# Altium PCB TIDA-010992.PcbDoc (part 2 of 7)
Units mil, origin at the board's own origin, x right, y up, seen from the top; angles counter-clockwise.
Board outline 2810.81 x 2427 mil, 8 copper layers (L01-TOP, L02-GND, L03-SIG, L04-GND, L05-PWR, L06-SIG, L07-GND, L08-BOTTOM), stack 61.9 mil thick; 521 components, 377 nets, 1545 pads, 874 vias.

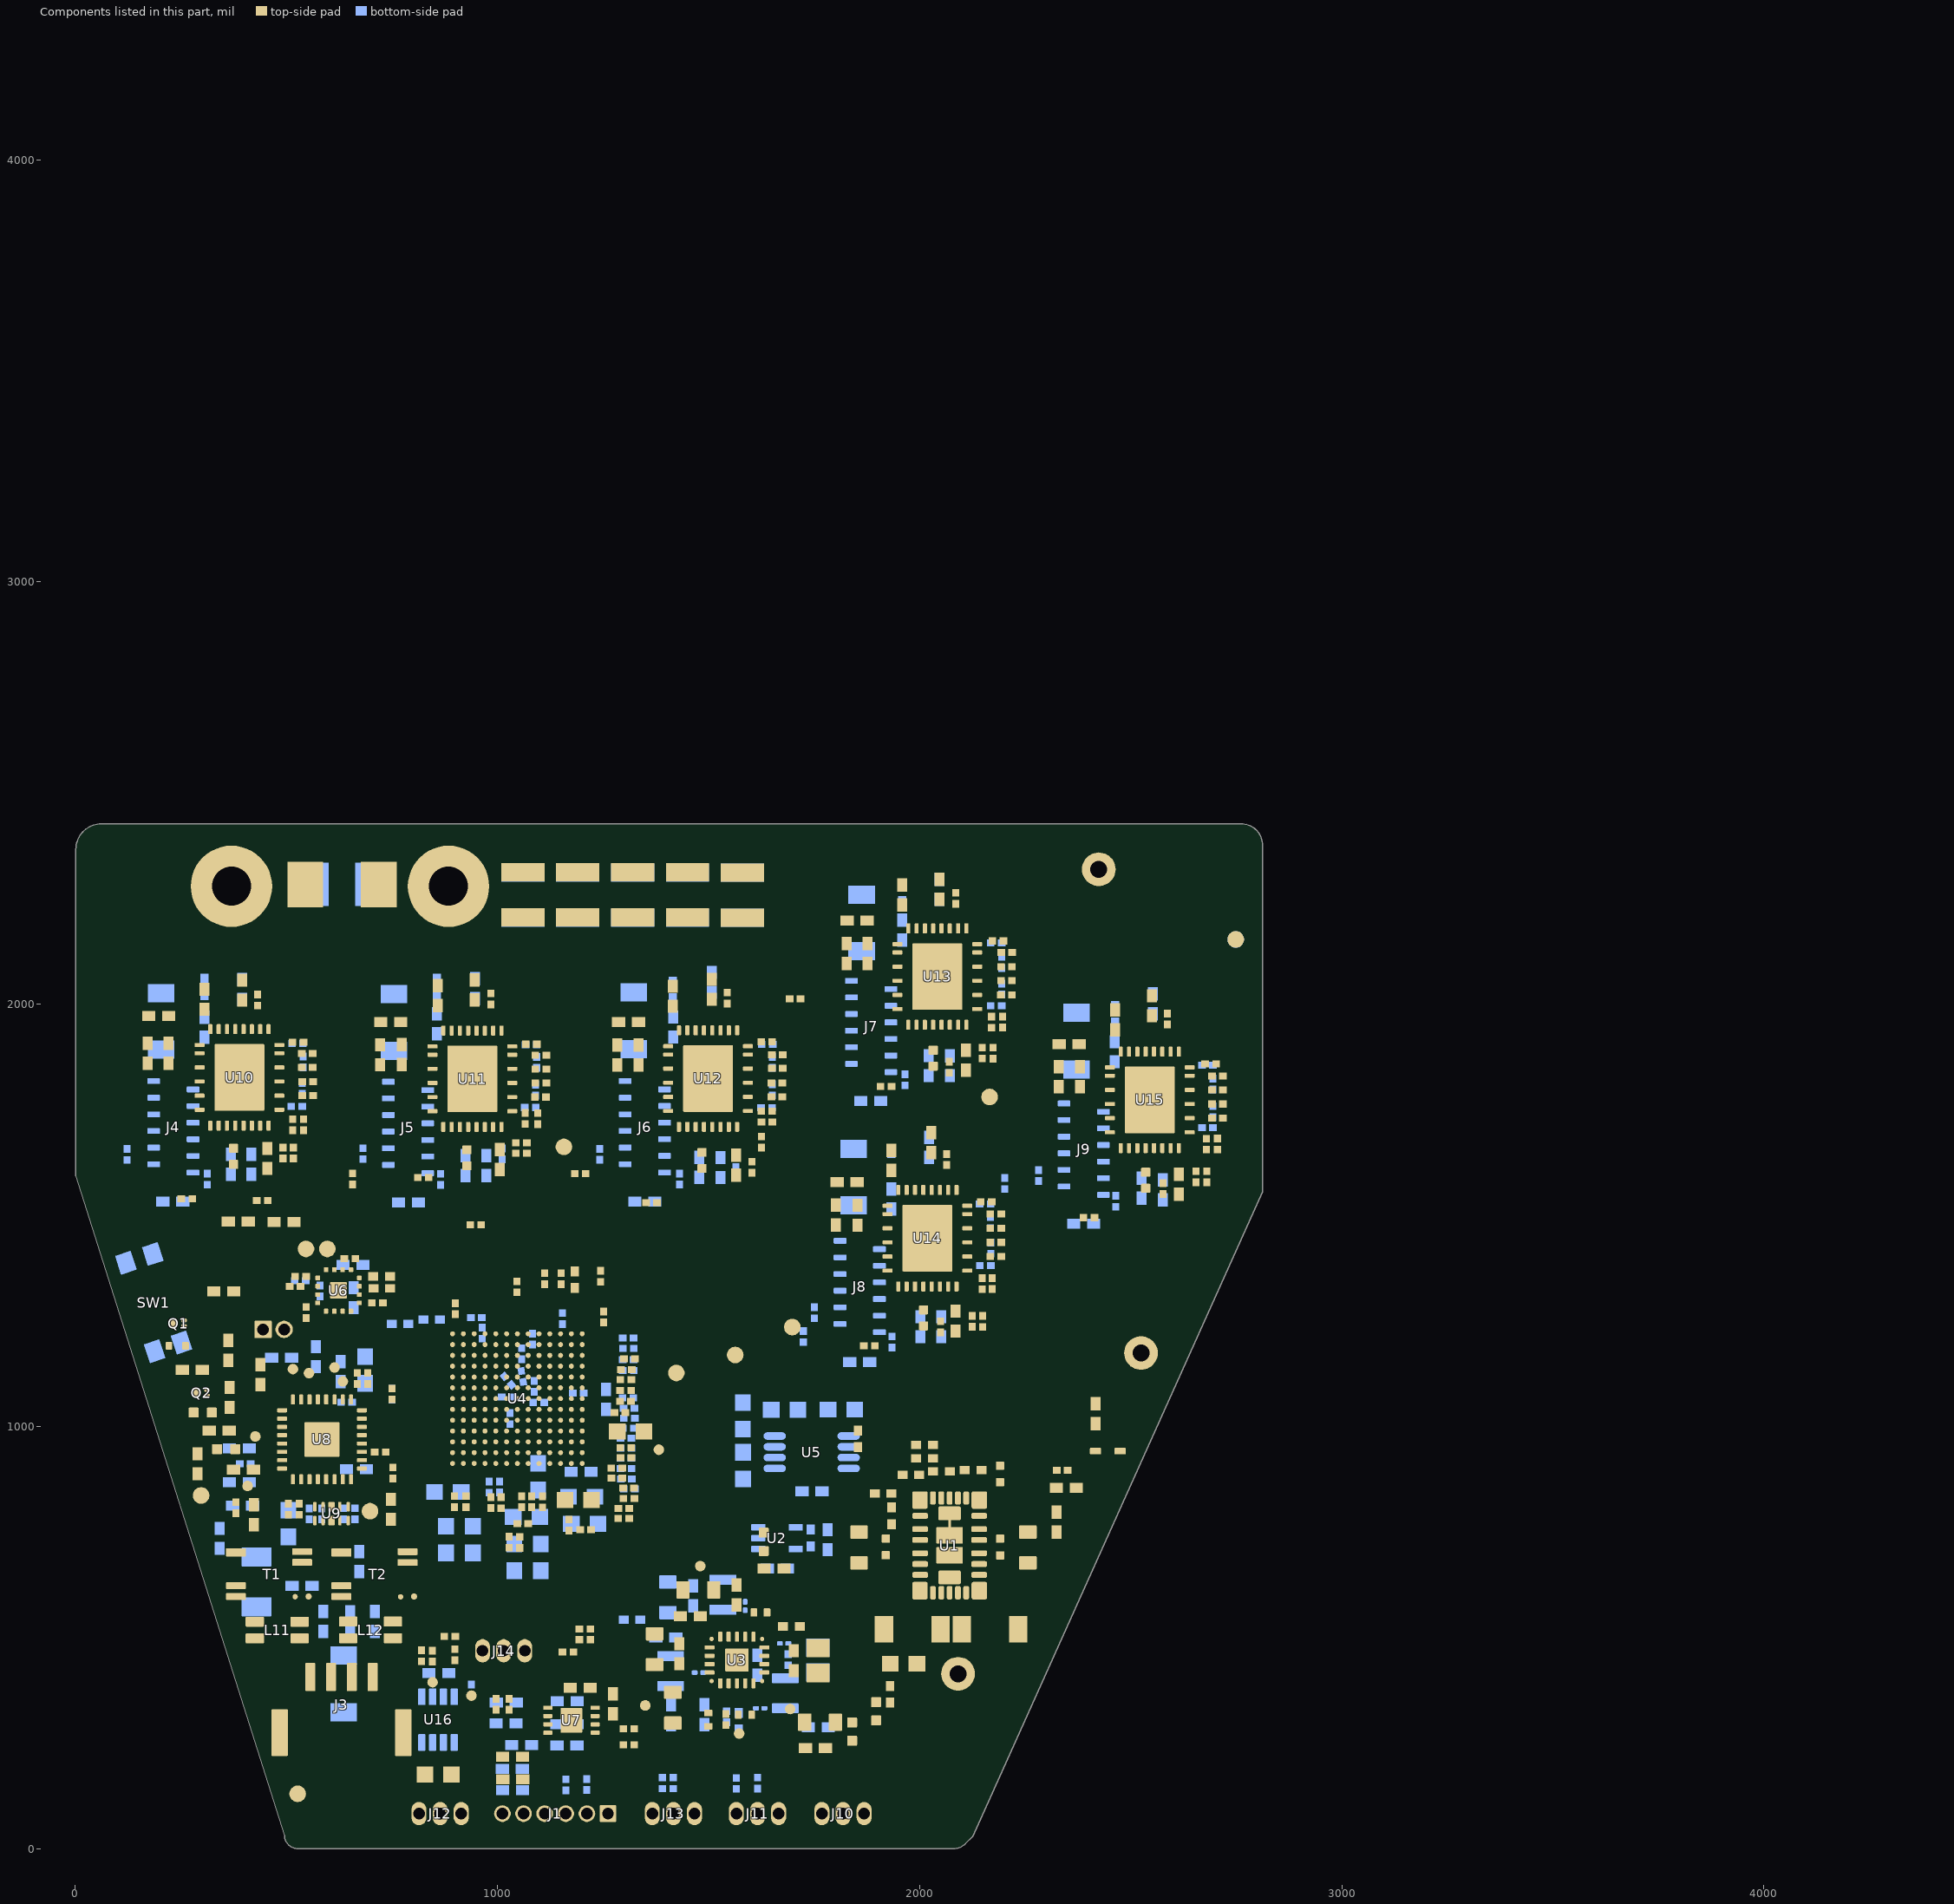
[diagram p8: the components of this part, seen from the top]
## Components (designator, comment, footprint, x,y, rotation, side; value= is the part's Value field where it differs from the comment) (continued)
R187 "RC0201FR-7D4K7L" 0201 2064,1632.04 r90 top value=4.70k
R188 "RC0201FR-7D4K7L" 0201 2049.39,1235.67 r270 top value=4.70k
R189 "CRCW020120R0FNED" 0201_033 2180.31,1469.13 r180 top value=20.0
R190 "CRCW04021K00FKED" 0402 2022.56,1660.43 r270 bottom value=1.00k
R191 "CRCW020120R0FNED" 0201_033 2180.31,1502.6 r180 top value=20.0
R192 "RC0402FR-0715KL" 0402 1932.82,1538.28 r270 bottom value=15.0k
R193 "CRCW040210K0FKED" 0402L 1933.08,1627.23 r270 bottom value=10.0k
R194 "CRCW04021K00FKED" 0402 2576.5,1560.19 r90 bottom value=1.00k
R195 "CRCW04021K00FKED" 0402 2614.01,1573.65 r90 top value=1.00k
R196 "CRCW020120R0FNED" 0201_033 2680.37,1591.04 r90 top value=20.0
R197 "CRCW020120R0FNED" 0201_033 2705.41,1668.69 r90 top value=20.0
R198 "ERJ-1GNJ220C" 0201 2281.89,1593.93 r90 bottom value=22
R199 "CRCW020120R0FNED" 0201_033 2705.6,1729.93 r180 top value=20.0
R200 "CRCW020120R0FNED" 0201_033 2705.6,1763.35 r180 top value=20.0
R201 "ERJ-1GNJ220C" 0201 2464.56,1532.86 r90 bottom value=22
R202 "ERJ-1GNJ220C" 0201 2689.21,1857.99 r180 top value=22
R203 "RC0201FR-7D4K7L" 0201 2586.9,1964.76 r90 top value=4.70k
R204 "RC0201FR-7D4K7L" 0201 2576.81,1562.92 r270 top value=4.70k
R205 "CRCW020120R0FNED" 0201_033 2705.6,1796.38 r180 top value=20.0
R206 "CRCW04021K00FKED" 0402 2551.98,2000.5 r270 bottom value=1.00k
R207 "CRCW020120R0FNED" 0201_033 2705.6,1829.56 r180 top value=20.0
R208 "RC0402FR-0715KL" 0402 2462.11,1887.2 r270 bottom value=15.0k
R209 "CRCW040210K0FKED" 0402L 2463.32,1976.24 r270 bottom value=10.0k
R210 "CMP-0025950-3" 0402 2324.18,773.39 r270 top value=100k
R211 "ERJ-1GNJ220C" 0201 1566.06,154.19 r270 bottom value=22
R212 "ERJ-1GNJ220C" 0201 1615.82,155.04 r270 bottom value=22
R213 "RC0402FR-0710K5L" 0402 2347.32,854.72 r180 top value=10.5k
R214 "CMP-0026825-5" 0402 2416.96,1030.24 r90 top value=10k
R215 "RC0603FR-07120RL" 0603 859.53,175.46 r180 top value=120
R216 "ERJ-1GNJ220C" 0201 1403.37,142 r0 bottom value=22
R217 "ERJ-1GNJ220C" 0201 938.15,375.22 r270 bottom value=22
R218 "RC0201FR-07100KL" 0201 1195.88,1598.07 r0 top value=100k
R219 "RC0201FR-07100KL" 0201 657,1586.06 r90 top value=100k
R220 "CRCW04020000Z0EDHP" 0402 1490.33,316.78 r270 bottom value=0
R221 "CRCW04020000Z0EDHP" 0402 1398.89,499.46 r180 bottom value=0
R222 "ERJ-2GE0R00X" 0402L 1182.73,1347.25 r90 top value=0
R223 "CRCW040210K0FKED" 0402L 1318.87,542.33 r180 bottom value=10.0k
RT1 "TMP6131DYAT" DYA0002A-MFG 2445.73,941.28 r180 top value=10k
SW1 "434351045816" FP-434351045816_SMT_SW_4MM7_4MM5-MFG 185.49,1292.97 r108 bottom
T1 "74930000" FP-74930000_SMT_4MM7_3MM22-MFG 458.67,650.2 r180 top
T2 "74930000" FP-74930000_SMT_4MM7_3MM22-MFG 708.51,649.97 r180 top
TP1 "5000" Keystone5000 2091.03,413.96 r90 top
TP2 "CMP-0055138-2" Keystone5001 2524.37,1173.74 r180 top
TP3 "CMP-0055138-2" Keystone5001 2424.26,2319.33 r180 top
TP4 "TP_SM_1MM" TP_SM_1MM 2165.66,1780.1 r180 top
TP5 "TP_SM_1MM" TP_SM_1MM 1157.21,1661.93 r180 top
TP6 "TP_SM_1MM" TP_SM_1MM 1698.31,1235.08 r180 top
TP7 "TP_SM_1MM" TP_SM_1MM 297.88,836.15 r180 top
TP8 "TESTPOINT" TP_25MIL-SMT 1572.32,272.42 r270 top
TP9 "TESTPOINT" TP_25MIL-SMT 1693.27,330.54 r270 top
TP10 "TESTPOINT" TP_25MIL-SMT 1350.06,338.88 r270 top
TP11 "TESTPOINT" TP_25MIL-SMT 1480.33,669.09 r270 top
TP12 "TESTPOINT" TP_25MIL-SMT 1382.2,944.69 r270 top
TP13 "TP_SM_1MM" TP_SM_1MM 546.27,1420.25 r270 top
TP14 "TP_SM_1MM" TP_SM_1MM 596.83,1420.25 r270 top
TP15 "TESTPOINT" TP_25MIL-SMT 613.75,1139.23 r270 top
TP16 "TESTPOINT" TP_25MIL-SMT 633.58,1106.29 r270 top
TP17 "TESTPOINT" TP_25MIL-SMT 553.4,1125.95 r270 top
TP18 "TP_SM_1MM" TP_SM_1MM 697.88,799.01 r270 top
TP19 "TESTPOINT" TP_25MIL-SMT 515.33,1135.65 r270 top
TP20 "TESTPOINT" TP_25MIL-SMT 426.29,975.96 r270 top
TP21 "TESTPOINT" TP_25MIL-SMT 407.9,858.7 r270 top
TP22 "TESTPOINT" TP_25MIL-SMT 938.26,362.12 r270 top
TP23 "TESTPOINT" TP_25MIL-SMT 846.25,393.98 r270 top
TP24 "TP_SM_1MM" TP_SM_1MM 1423.65,1126.49 r270 top
TP25 "TP_SM_1MM" TP_SM_1MM 1563.1,1169.09 r270 top
U1 "TLVM13630RDHR" RDH0030A-MFG 2070.88,718.09 r0 top
U2 "TLV7021DCKR" DCK0005A_N 1662.1,735.32 r0 bottom
U3 "TPS65035000RZDRQ1" RZD0022A-MFG 1567.06,446.54 r90 top
U4 "TMS320F28P650DK9NMRR" NMR0169A-MFG 1047.09,1065.65 r90 top locked
U5 "REF6230IDGKR" DGK0008A_N 1744.28,938.68 r0 bottom
U6 "LMK3C0105V33RERR" RER0016A-MFG 623.26,1321.92 r90 top
U7 "AT24C256C-MAHL-T" 8MA2 1175.17,303.85 r0 top
U8 "DP83826A" RHB0032M-MFG 584.22,969.03 r90 top locked
U9 "TPD4E05U06DQAR" DQA0010A 606.72,793.19 r270 top
U10 "DRV8376SNLGR" NLG0028A-MFG 388.61,1826.48 r0 top locked
U11 "DRV8376SNLGR" NLG0028A-MFG 940.42,1823.13 r0 top
U12 "DRV8376SNLGR" NLG0028A-MFG 1498.8,1823.59 r0 top
U13 "DRV8376SNLGR" NLG0028A-MFG 2041.86,2065.12 r0 top
U14 "DRV8376SNLGR" NLG0028A-MFG 2018.45,1445.51 r0 top
U15 "DRV8376SNLGR" NLG0028A-MFG 2545.14,1773.24 r0 top
U16 "TCAN332GDCNR" DCN0008A_N 859.04,305.3 r270 bottom
ZZ1 "This Assembly Note is for PCB labels only" AssemblyNoteLabel 185,3938 r0 top
ZZ2 "These assemblies are ESD sensitive, ESD precautions shall be observed." AssemblyNote 185,3829.11 r0 top
ZZ3 "These assemblies must be clean and free from flux and all contaminants. Use of no clean flux is not acceptable." AssemblyNote 185,3740.56 r0 top
ZZ4 "These assemblies must comply with workmanship standards IPC-A-610 Class 2, unless otherwise specified." AssemblyNote 185,3652 r0 top

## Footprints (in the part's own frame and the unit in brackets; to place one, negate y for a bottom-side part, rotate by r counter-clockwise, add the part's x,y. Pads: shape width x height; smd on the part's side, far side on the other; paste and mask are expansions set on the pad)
8MA2 [mm] "ATMEL DFN"
  rrect40% 0.55x0.25 smd: 1(-1.425,0.75) 2(-1.425,0.25) 3(-1.425,-0.25) 4(-1.425,-0.75) 5(1.425,-0.75) 6(1.425,-0.25) 7(1.425,0.25) 8(1.425,0.75)
  rrect8% 1.3x1.5 smd paste-1: 9(0,0)
  rrect8% 1.21x1.38 on Top Paste: 9(0,0)
  silkscreen extent -1.55,-1.15 0.75,1.15, body extent -1.55,-1.05 1.55,1.05, height 0.61
0201 [mm] "Data from Kemet datasheet CC101_COM dated 7/28/11"
  rect 0.46x0.42 smd mask+0.048: 1(-0.33,0) 2(0.33,0)
  body extent -0.31,-0.16 0.31,0.16, height 0.26
0201_033 [mm] "SMD, 2-Leads, Height 0.33mm"
  rect 0.46x0.42 smd mask+0.048: 1(-0.33,0) 2(0.33,0)
  body extent -0.31,-0.16 0.31,0.16, height 0.33
0402 [mm] "0402 from SM-752 data"
  rect 0.8x0.6 smd: 1(-0.6,0) 2(0.6,0)
  silkscreen extent -1.22,-0.52 1.22,0.52, body extent -0.55,-0.3 0.55,0.3, height 0.6
0402_065 [mm] "0402"
  rect 0.8x0.6 smd: 1(-0.6,0) 2(0.6,0)
  silkscreen extent -1.22,-0.52 1.22,0.52, body extent -0.55,-0.3 0.55,0.3, height 0.65
0402L [mm] "0402 from SM-752 data"
  rect 0.6x0.5 smd: 1(-0.5,0) 2(0.5,0)
  body extent -0.55,-0.3 0.55,0.3, height 0.6
0603 [mm] "0603 from SM-752 data"
  rect 1x0.95 smd: 1(-0.8,0) 2(0.8,0)
  silkscreen extent -1.52,-0.69 1.52,0.69, body extent -0.87,-0.47 0.87,0.47, height 1
0805L [mm] "0805 from SM-752 data"
  rect 1.1x1.4 smd: 1(-0.75,0) 2(0.75,0)
  body extent -1.1,-0.72 1.1,0.72, height 1.45
1206_180 [mm] "1206_180"
  rect 1.1x1.6 smd: 1(-1.7,0) 2(1.7,0)
  silkscreen extent -0.9,-1 0.9,1, body extent -1.75,-0.95 1.75,0.95, height 1.8
1206_190 [mm] "1206_190"
  rect 1.1x1.6 smd: 1(-1.7,0) 2(1.7,0)
  silkscreen extent -0.9,-1 0.9,1, body extent -1.75,-0.95 1.75,0.95, height 1.9
1210_270L [mm] "1210"
  rect 1.1x2.6 smd: 1(-1.35,0) 2(1.35,0)
  silkscreen extent -0.4,-1.2 0.4,1.2, body extent -1.7,-1.35 1.7,1.35, height 2.7
AssemblyNote [mil] "Assembly Note"
AssemblyNoteLabel [mil] "Assembly Note for PCB Labels"
CE_Mark_5mm [mil] "Minimum text height for CE Mark"
  silkscreen extent -138,-98 138,98
DCK0005A_N [mm] "SOT353, 5-Leads, Body 2x1.3mm, Pitch 0.65mm, Lead Span 2.1mm, IPC Medium Density"
  rrect25% 0.85x0.4 smd: 1(-1.125,0.65) 2(-1.125,0) 3(-1.125,-0.65) 4(1.125,-0.65) 5(1.125,0.65)
  silkscreen extent -1.48,-1.02 0.55,1.1, body extent -1.14,-1 1.14,1, height 0.95
DCN0008A_N [mm] "SOP, 8-Leads, Body 2.9x1.6mm, Pitch 0.65mm, IPC Medium Density"
  rrect22% 1x0.45 smd: 1(-1.375,0.975) 2(-1.375,0.325) 3(-1.375,-0.325) 4(-1.375,-0.975) 5(1.375,-0.975) 6(1.375,-0.325) 7(1.375,0.325) 8(1.375,0.975)
  silkscreen extent -1.75,-1.5 0.58,1.5, body extent -1.41,-1.45 1.41,1.45, height 1.45
DGK0008A_N [mm] "TSOP, 8-Leads, Body 3x3mm, Pitch 0.65mm, IPC Medium Density"
  oval 1.35x0.45 smd: 1(-2.225,0.975) 2(-2.225,0.325) 3(-2.225,-0.325) 4(-2.225,-0.975) 5(2.225,-0.975) 6(2.225,-0.325) 7(2.225,0.325) 8(2.225,0.975)
  silkscreen extent -2.75,-1.55 0.95,1.55, body extent -2.45,-1.5 2.45,1.5, height 0.96
DQA0010A [mm] "SON, 10-Leads, Body 1x2.5mm, Pitch 0.5mm, TI Recommended"
  rrect50% 0.565x0.2 smd: 1(-0.417,1) 2(-0.417,0.5) 4(-0.417,-0.5) 5(-0.417,-1) 6(0.417,-1) 7(0.417,-0.5) 9(0.417,0.5) 10(0.417,1)
  rrect28% 0.565x0.36 on Top Paste: 3(-0.417,0) 8(0.417,0)
  rrect25% 0.565x0.4 smd paste-0.2: 3(-0.417,0) 8(0.417,0)
  silkscreen extent -0.67,-1.45 0.55,1.45, body extent -0.55,-1.3 0.55,1.3, height 0.56
DYA0002A-MFG [mm]
  rrect25% 0.67x0.4 smd paste+0 mask+0: 1(-0.74,0) 2(0.74,0)
  silkscreen extent -1.75,-0.63 0.65,0.63, body extent -1.17,-0.67 1.17,0.67, height 0.25
FCC_disclaimer [mil]
Fiducial10-20 [mm]
  round 1 smd mask+0.5: 1(0,0)
  L01-TOP keep-out circle w1.178: c0,0 r0.5
FP-12FHT-SM1-GAN-TF(HF)_CONN_FPC_12-MFG [mm] "Recommended Land Pattern"
  rrect29% 0.35x0.77 smd paste+0 mask+0: 1(-2.75,1.185) 2(-2.25,-1.185) 3(-1.75,1.185) 4(-1.25,-1.185) 5(-0.75,1.185) 6(-0.25,-1.185) 7(0.25,1.185) 8(0.75,-1.185) 9(1.25,1.185) 10(1.75,-1.185) 11(2.25,1.185) 12(2.75,-1.185)
  silkscreen extent -3.75,-1.15 3.75,2.24, body extent -3.75,-1.5 3.75,1.44, height 3.3
FP-1206Y2K00222KET_1206-MFG [mm]
  rrect9% 1.15x1.8 smd paste+0 mask+0: 1(-1.5,0) 2(1.5,0)
  silkscreen extent -0.55,-0.9 0.55,0.9, body extent -1.6,-0.8 1.6,0.8, height 1.7
FP-150040RS73220_0402-MFG [mm]
  rrect25% 0.4x0.46 smd paste+0 mask+0: 1(-0.5,0) 2(0.5,0)
  silkscreen extent -1.37,-0.61 0.5,0.61, body extent -0.5,-0.25 0.5,0.25, height 0.35
FP-74930000_SMT_4MM7_3MM22-MFG [mm]
  rrect24% 1.2x0.41 smd paste+0 mask+0: 1(-1.99,-1.35) 2(-1.99,-0.7) 6(1.99,0.7) 7(1.99,1.35)
  round 0.373 smd paste+0 mask+0: 3(-2.382,1.347)
  round 0.321 smd paste+0 mask+0: 4(-1.574,1.365)
  rrect20% 1.2x0.5 smd paste+0 mask+0: 5(1.99,-1.305)
  L01-TOP region: -1.82,1.6 -1.69,1.1 -1.39,1.1 -1.39,1.6
  L01-TOP region: -2.59,1.6 -2.59,1.1 -2.16,1.1 -2.19,1.6
  silkscreen extent -3.27,-1.71 2.45,1.71, body extent -2.69,-1.81 2.69,1.81, height 0.25
FP-744232222_SMT4_3MM2_1MM6-MFG [mm]
  rrect17% 1.1x0.6 smd paste+0 mask+0: 1(-1.35,0.5) 2(1.35,0.5) 3(1.35,-0.5) 4(-1.35,-0.5)
  silkscreen extent -2.6,-0.9 0.43,0.9, body extent -2,-1 2,1, height 0.25
FP-434351045816_SMT_SW_4MM7_4MM5-MFG [mm]
  rrect10% 1.2x1 smd paste+0 mask+0: 1(2.8,0.85) 2(2.8,-0.85) 3(-2.8,0.85) 4(-2.8,-0.85)
  silkscreen extent -2.4,0.73 4.07,1.85, body extent -3.2,-2.75 3.2,1.75, height 1.75
FP-885012205086_0402-MFG [mm]
  rrect20% 0.5x0.5 smd paste+0 mask+0: 1(-0.5,0) 2(0.5,0)
  silkscreen extent -0.6,-0.63 0.6,0.63, body extent -0.5,-0.25 0.5,0.25, height 0.7
FP-BM04B-GHS-TBT(LF)(SN)_HDR4-MFG [mm] "Recommended Land Pattern"
  rrect17% 0.6x1.7 smd paste+0 mask+0: 1(1.875,2.325) 2(0.625,2.325) 3(-0.625,2.325) 4(-1.875,2.325)
  rrect10% 1x2.8 smd paste+0 mask+0: 5(-3.725,-1.025) 6(3.725,-1.025)
  silkscreen extent -4.13,-2.12 4.13,3.92, body extent -4.13,-2.12 4.13,2.83, height 4.2
FP-C2012X7R1H475K125AC_0805-MFG [mm]
  rrect13% 0.8x1.05 smd paste+0 mask+0: 1(-0.925,0) 2(0.925,0)
  silkscreen extent -0.15,-0.75 0.15,0.75, body extent -1,-0.63 1,0.63, height 1.5
FP-CGA4J3X7S1A106K125AE_0805-MFG [mm]
  rrect13% 0.8x1.05 smd paste+0 mask+0: 1(-0.925,0) 2(0.925,0)
  silkscreen extent -0.15,-0.75 0.15,0.75, body extent -1.2,-0.62 1.2,0.63, height 1.5
FP-GMC04X7R105K10NT_0402-MFG [mil]
  rrect19% 21x22 smd paste+0 mask+0: 1(-19,0) 2(19,0)
  silkscreen extent -21,-27 21,27, body extent -33,-15 33,15, height 10
FP-GRM155C71A105KE11D_0402-MFG [mm]
  rrect25% 0.4x0.5 smd paste+0 mask+0: 1(-0.4,0) 2(0.4,0)
  silkscreen extent -0.55,-0.65 0.55,0.65, body extent -0.7,-0.4 0.7,0.4, height 0.25
"FP-RC0201JR-070RL_0201 (0603 Metric)-IPC_C" [mil]
  rrect38% 13.94x10.34 smd paste+0 mask+0: 1(-10.01,0) 2(10.01,0)
  body extent -12,-6 12,6, height 10
IEC_HotSurface_Small [mil]
  silkscreen extent -107,-93 107,92
Keystone5000 [mil] "For Keystone 500x miniature loop terminals"
  round 80 hole 40: 1(0,0)
  silkscreen extent -52,-52 52,52, body extent -49,-49 49,49, height 182
Keystone5001 [mil] "For Keystone 500x miniature loop terminals"
  round 80 hole 40: 1(0,0)
  silkscreen extent -52,-52 52,52, body extent -49,-49 49,49, height 182
Label_650x200 [mil] "Thermal Transfer Label"
  round 1 on Mech13: 0(0,0)
  silkscreen extent -325,-100 325,100, body extent -325,-100 325,100, height 1
MTGP_2-48_PanHead [mm] "2-48 Mounting Hole, Plated, for Pan Head"
  round 4.9 hole 2.35: 1(0,0)
Net-Tie7milsWide_20milsLong [mil] "7 mils wide by 20 mils long"
  rect 10x7 smd paste-5 mask-5: 1(-5,0) 2(5,0)
NLG0028A-MFG [mm]
  rrect40% 0.6x0.25 smd paste+0 mask+0: 1(-2.4,1.95) 2(-2.4,1.45) 3(-2.4,0.6) 4(-2.4,-0.25) 5(-2.4,-1.1) 6(-2.4,-1.95) 15(2.4,-1.95) 16(2.4,-1.1) 17(2.4,-0.25) 18(2.4,0.6) 19(2.4,1.45) 20(2.4,1.95)
  rrect40% 0.25x0.6 smd paste+0 mask+0: 7(-1.75,-2.9) 8(-1.25,-2.9) 9(-0.75,-2.9) 10(-0.25,-2.9) 11(0.25,-2.9) 12(0.75,-2.9) 13(1.25,-2.9) 14(1.75,-2.9) 21(1.75,2.9) 22(1.25,2.9) 23(0.75,2.9) 24(0.25,2.9) 25(-0.25,2.9) 26(-0.75,2.9) 27(-1.25,2.9) 28(-1.75,2.9)
  rrect3% 3x4 smd paste-1000 mask+0: 29(0,0)
  silkscreen extent -3.37,-3.05 2.55,3.05, body extent -2.8,-3.3 2.8,3.3, height 0.25
NMR0169A-MFG [mm]
  round 0.3 smd paste+0 mask+0.05: A1(-3.9,3.9) A2(-3.25,3.9) A3(-2.6,3.9) A4(-1.95,3.9) A5(-1.3,3.9) A6(-0.65,3.9) A7(0,3.9) A8(0.65,3.9) A9(1.3,3.9) A10(1.95,3.9) A11(2.6,3.9) A12(3.25,3.9) A13(3.9,3.9) B1(-3.9,3.25) B2(-3.25,3.25) B3(-2.6,3.25) B4(-1.95,3.25) B5(-1.3,3.25) B6(-0.65,3.25) B7(0,3.25) B8(0.65,3.25) B9(1.3,3.25) B10(1.95,3.25) B11(2.6,3.25) B12(3.25,3.25) B13(3.9,3.25) C1(-3.9,2.6) C2(-3.25,2.6) C3(-2.6,2.6) C4(-1.95,2.6) C5(-1.3,2.6) C6(-0.65,2.6) C7(0,2.6) C8(0.65,2.6) C9(1.3,2.6) C10(1.95,2.6) C11(2.6,2.6) C12(3.25,2.6) C13(3.9,2.6) D1(-3.9,1.95) D2(-3.25,1.95) D3(-2.6,1.95) D4(-1.95,1.95) D5(-1.3,1.95) D6(-0.65,1.95) D7(0,1.95) D8(0.65,1.95) D9(1.3,1.95) D10(1.95,1.95) D11(2.6,1.95) D12(3.25,1.95) D13(3.9,1.95) E1(-3.9,1.3) E2(-3.25,1.3) E3(-2.6,1.3) E4(-1.95,1.3) E5(-1.3,1.3) E6(-0.65,1.3) E7(0,1.3) E8(0.65,1.3) E9(1.3,1.3) E10(1.95,1.3) E11(2.6,1.3) E12(3.25,1.3) E13(3.9,1.3) F1(-3.9,0.65) F2(-3.25,0.65) F3(-2.6,0.65) F4(-1.95,0.65) F5(-1.3,0.65) F6(-0.65,0.65) F7(0,0.65) F8(0.65,0.65) F9(1.3,0.65) F10(1.95,0.65) F11(2.6,0.65) F12(3.25,0.65) F13(3.9,0.65) G1(-3.9,0) G2(-3.25,0) G3(-2.6,0) G4(-1.95,0) G5(-1.3,0) G6(-0.65,0) G7(0,0) G8(0.65,0) G9(1.3,0) G10(1.95,0) G11(2.6,0) G12(3.25,0) G13(3.9,0) H1(-3.9,-0.65) H2(-3.25,-0.65) H3(-2.6,-0.65) H4(-1.95,-0.65) H5(-1.3,-0.65) H6(-0.65,-0.65) H7(0,-0.65) H8(0.65,-0.65) H9(1.3,-0.65) H10(1.95,-0.65) H11(2.6,-0.65) H12(3.25,-0.65) H13(3.9,-0.65) J1(-3.9,-1.3) J2(-3.25,-1.3) J3(-2.6,-1.3) J4(-1.95,-1.3) J5(-1.3,-1.3) J6(-0.65,-1.3) J7(0,-1.3) J8(0.65,-1.3) J9(1.3,-1.3) J10(1.95,-1.3) J11(2.6,-1.3) J12(3.25,-1.3) J13(3.9,-1.3) K1(-3.9,-1.95) K2(-3.25,-1.95) K3(-2.6,-1.95) K4(-1.95,-1.95) K5(-1.3,-1.95) K6(-0.65,-1.95) K7(0,-1.95) K8(0.65,-1.95) K9(1.3,-1.95) K10(1.95,-1.95) K11(2.6,-1.95) K12(3.25,-1.95) K13(3.9,-1.95) L1(-3.9,-2.6) L2(-3.25,-2.6) L3(-2.6,-2.6) L4(-1.95,-2.6) L5(-1.3,-2.6) L6(-0.65,-2.6) L7(0,-2.6) L8(0.65,-2.6) L9(1.3,-2.6) L10(1.95,-2.6) L11(2.6,-2.6) L12(3.25,-2.6) L13(3.9,-2.6) M1(-3.9,-3.25) M2(-3.25,-3.25) M3(-2.6,-3.25) M4(-1.95,-3.25) M5(-1.3,-3.25) M6(-0.65,-3.25) M7(0,-3.25) M8(0.65,-3.25) M9(1.3,-3.25) M10(1.95,-3.25) M11(2.6,-3.25) M12(3.25,-3.25) M13(3.9,-3.25) N1(-3.9,-3.9) N2(-3.25,-3.9) N3(-2.6,-3.9) N4(-1.95,-3.9) N5(-1.3,-3.9) N6(-0.65,-3.9) N7(0,-3.9) N8(0.65,-3.9) N9(1.3,-3.9) N10(1.95,-3.9) N11(2.6,-3.9) N12(3.25,-3.9) N13(3.9,-3.9)
  silkscreen extent -5.15,-4.55 4.55,4.55, body extent -5.05,-5.05 5.05,5.05, height 0.25
RDH0030A-MFG [mm]
  rrect22% 0.93x1.05 smd paste-1000 mask-1000: 1(-1.786,2.725) 8(-1.786,-2.725) 14(1.786,-2.725) 21(1.786,2.725)
  rrect57% 0.95x0.35 smd paste-1000 mask-1000: 2(-1.775,1.775) 3(-1.775,0.975) 4(-1.775,0.325) 5(-1.775,-0.475) 6(-1.775,-1.125) 7(-1.775,-1.775) 15(1.775,-1.775) 16(1.775,-1.125) 17(1.775,-0.475) 18(1.775,0.325) 19(1.775,0.975) 20(1.775,1.775)
  rrect57% 0.35x0.8 smd paste-1000 mask-1000: 9(-1,-2.85) 10(-0.5,-2.85) 11(0,-2.85) 12(0.5,-2.85) 13(1,-2.85) 22(1,2.85) 23(0.5,2.85) 24(0,2.85) 25(-0.5,2.85) 26(-1,2.85)
  rrect24% 1.35x0.84 smd paste-1000 mask-1000: 27(0,1.925) 30(0,-1.925)
  rrect12% 1.6x1 smd paste-1000 mask-1000: 28(0,0.6) 29(0,-0.6)
  L01-TOP region: -0.85,-1.05 -0.85,1.05 -0.837,1.1 -0.8,1.137 -0.75,1.15 -0.75,1.15 0.75,1.15 0.8,1.137 0.837,1.1 0.85,1.05 0.85,1.05 0.85,-1.05 0.837,-1.1 0.8,-1.137 0.75,-1.15 0.75,-1.15 -0.75,-1.15 -0.8,-1.137 -0.837,-1.1 -0.85,-1.05
  silkscreen extent -2.95,-3.65 2.05,3.65, body extent -2,-3 2,3, height 1.9
RER0016A-MFG [mm] "Recommended Land Pattern"
  rrect36% 0.3x0.275 smd paste-1000 mask+0: 1(-1.25,0.75) 2(-1.25,0.25) 3(-1.25,-0.25) 4(-1.25,-0.75) 9(1.25,-0.75) 10(1.25,-0.25) 11(1.25,0.25) 12(1.25,0.75)
  rrect36% 0.275x0.3 smd paste-1000 mask+0: 5(-0.75,-1.25) 6(-0.25,-1.25) 7(0.25,-1.25) 8(0.75,-1.25) 13(0.75,1.25) 14(0.25,1.25) 15(-0.25,1.25) 16(-0.75,1.25)
  rrect10% 1x1 smd paste-1000 mask+0: 17(0,0)
  silkscreen extent -2.15,-1.55 1.55,1.55, body extent -1.5,-1.5 1.5,1.5, height 1.5
RHB0032M-MFG [mm] "Recommended Land Pattern"
  rrect40% 0.6x0.25 smd paste+0 mask+0: 1(-2.4,1.75) 2(-2.4,1.25) 3(-2.4,0.75) 4(-2.4,0.25) 5(-2.4,-0.25) 6(-2.4,-0.75) 7(-2.4,-1.25) 8(-2.4,-1.75) 17(2.4,-1.75) 18(2.4,-1.25) 19(2.4,-0.75) 20(2.4,-0.25) 21(2.4,0.25) 22(2.4,0.75) 23(2.4,1.25) 24(2.4,1.75)
  rrect40% 0.25x0.6 smd paste+0 mask+0: 9(-1.75,-2.4) 10(-1.25,-2.4) 11(-0.75,-2.4) 12(-0.25,-2.4) 13(0.25,-2.4) 14(0.75,-2.4) 15(1.25,-2.4) 16(1.75,-2.4) 25(1.75,2.4) 26(1.25,2.4) 27(0.75,2.4) 28(0.25,2.4) 29(-0.25,2.4) 30(-0.75,2.4) 31(-1.25,2.4) 32(-1.75,2.4)
  rrect5% 2.1x2.1 smd paste-1000 mask+0: 33(0,0)
  silkscreen extent -3.37,-2.55 2.55,2.55, body extent -2.8,-2.8 2.8,2.8, height 0.25
RZD0022A-MFG [mm]
  round 0.259 smd paste+0 mask+0: 1(-1.269,1.519) 7(-1.269,-1.519) 12(1.269,-1.519) 18(1.269,1.519)
  rrect40% 0.6x0.25 smd paste+0 mask+0: 2(-1.4,1) 3(-1.4,0.5) 4(-1.4,0) 5(-1.4,-0.5) 6(-1.4,-1) 13(1.4,-1) 14(1.4,-0.5) 15(1.4,0) 16(1.4,0.5) 17(1.4,1)
  rrect40% 0.25x0.6 smd paste+0 mask+0: 8(-0.75,-1.65) 9(-0.25,-1.65) 10(0.25,-1.65) 11(0.75,-1.65) 19(0.75,1.65) 20(0.25,1.65) 21(-0.25,1.65) 22(-0.75,1.65)
  rrect7% 1.4x1.4 smd paste-1000 mask+0: 23(0,0)
  L01-TOP region: -1.175,-1.375 -1.156,-1.379 -1.14,-1.39 -1.129,-1.406 -1.125,-1.425 -1.125,-1.425 -1.125,-1.9 -1.129,-1.919 -1.14,-1.935 -1.156,-1.946 -1.175,-1.95 -1.175,-1.95 -1.325,-1.95 -1.35,-1.943 -1.368,-1.925 -1.375,-1.9 -1.375,-1.9 -1.375,-1.725 -1.383,-1.687 -1.404,-1.654 -1.437,-1.633 -1.475,-1.625 -1.475,-1.625 -1.65,-1.625 -1.675,-1.618 -1.693,-1.6 -1.7,-1.575 -1.7,-1.575 -1.7,-1.425 -1.693,-1.4 -1.675,-1.382 -1.65,-1.375 -1.65,-1.375
  L01-TOP region: 1.125,-1.425 1.129,-1.406 1.14,-1.39 1.156,-1.379 1.175,-1.375 1.175,-1.375 1.65,-1.375 1.669,-1.379 1.685,-1.39 1.696,-1.406 1.7,-1.425 1.7,-1.425 1.7,-1.575 1.693,-1.6 1.675,-1.618 1.65,-1.625 1.65,-1.625 1.475,-1.625 1.437,-1.633 1.404,-1.654 1.383,-1.687 1.375,-1.725 1.375,-1.725 1.375,-1.9 1.368,-1.925 1.35,-1.943 1.325,-1.95 1.325,-1.95 1.175,-1.95 1.15,-1.943 1.132,-1.925 1.125,-1.9 1.125,-1.9
  L01-TOP region: 1.175,1.375 1.156,1.379 1.14,1.39 1.129,1.406 1.125,1.425 1.125,1.425 1.125,1.9 1.129,1.919 1.14,1.935 1.156,1.946 1.175,1.95 1.175,1.95 1.325,1.95 1.35,1.943 1.368,1.925 1.375,1.9 1.375,1.9 1.375,1.725 1.383,1.687 1.404,1.654 1.437,1.633 1.475,1.625 1.475,1.625 1.65,1.625 1.675,1.618 1.693,1.6 1.7,1.575 1.7,1.575 1.7,1.425 1.693,1.4 1.675,1.382 1.65,1.375 1.65,1.375
  L01-TOP region: -1.125,1.425 -1.129,1.406 -1.14,1.39 -1.156,1.379 -1.175,1.375 -1.175,1.375 -1.65,1.375 -1.669,1.379 -1.685,1.39 -1.696,1.406 -1.7,1.425 -1.7,1.425 -1.7,1.575 -1.693,1.6 -1.675,1.618 -1.65,1.625 -1.65,1.625 -1.475,1.625 -1.437,1.633 -1.404,1.654 -1.383,1.687 -1.375,1.725 -1.375,1.725 -1.375,1.9 -1.368,1.925 -1.35,1.943 -1.325,1.95 -1.325,1.95 -1.175,1.95 -1.15,1.943 -1.132,1.925 -1.125,1.9 -1.125,1.9
  silkscreen extent -2.37,-2.17 1.92,2.17, body extent -1.5,-1.75 1.5,1.75, height 1.05
SMB-Bi [mil] "Molded Diode, 2-Leads, Body 5.4x3.6mm, IPC Medium Density, based on OnSemi component dimensions"
  rect 85x107.99 smd: 1(-87.01,0) 2(87.01,0)
  silkscreen extent -125,-79 125,79, body extent -104,-73 104,73, height 89
Sullins_GRPB021VWVN-RC [mil] "Sullins"
  rrect10% 41x41 hole 28: 1(-25,0)
  round 41 hole 28: 2(25,0)
  silkscreen extent -70,-42 50,42, body extent -50,-42 50,42, height 157
Sullins_GRPB031VWVN-RC [mm] "SULLINS"
  oval 0.9x1.4 hole 0.7: 1(-1.27,0) 2(0,0) 3(1.27,0)
  silkscreen extent -2.25,-1.47 2.17,1.2, body extent -2.15,-1.17 2.17,1.17, height 4.2
Sullins_GRPB061VWVN-RC [mm] "SULLINS"
  rrect10% 1x1 hole 0.7: 1(-3.175,0)
  round 1 hole 0.7: 2(-1.905,0) 3(-0.635,0) 4(0.635,0) 5(1.905,0) 6(3.175,0)
  silkscreen extent -4.25,-1.17 3.93,1.22, body extent -3.85,-1.1 3.85,1.1, height 4.3
TFM201610 [mm] "TDK"
  rect 0.6x1.6 smd: 1(-0.9,0) 2(0.9,0)
  silkscreen extent -0.4,-1 0.4,1, body extent -1.1,-0.9 1.1,0.9, height 1
TFM201610ALMA [mm] "TDK"
  rrect17% 0.6x1.6 smd: 1(-0.9,0) 2(0.9,0)
  body extent -1.1,-0.9 1.1,0.9, height 1
TI_Symbol_Overlay_Small [mil]
  silkscreen extent -90,-88 91,88
TP_25MIL-SMT [mil]
  round 25 smd mask-2.5: 1(0,0)
TP_SM_1MM [mm] "1mm Test Point, SMT"
  round 1 smd paste-0.5: 1(0,0)
WEEE_Minimum [mil] "WEEElie bin"
  silkscreen extent -95,-172 99,104
WL-SMCC_0402_Green [mm] "SMD, 2-Leads, Body 1x0.5mm"
  rrect17% 0.6x0.6 smd: 1(-0.55,0) 2(0.55,0)
  body extent -0.5,-0.25 0.5,0.25, height 0.39
YJC0003A [mm] "TI"
  rrect50% 0.25x0.2 on Top Paste: 0(-0.325,0.2) 0(-0.325,-0.2)
  rrect80% 0.35x0.25 smd paste-0.13 mask-0.05: 1(-0.325,0.175) 2(-0.325,-0.175)
  rrect57% 0.35x0.6 smd paste-0.05 mask-0.05: 3(0.325,0)
  body extent -0.5,-0.3 0.5,0.3, height 0.35

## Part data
1: library part CMP-0074837-1, "IEC 61010-1 Hot Surface Warning"
C1: library part CMP-0006620-2, "CAP, CERM, 1 uF, 35 V, +/- 20%, X5R, 0402", Cap_Case=0402, Manufacturer=MuRata, Supplier Part Number 1=490-10020-1-ND, TempCo=X5R, Tolerance_%=20%, Value1=Unknown, Value2=35V, ValueDisplayed=1uF
C2 C3: library part CMP-0008656-2, "CAP, CERM, 47 uF, 25 V, +/- 20%, X5R, 1206_190", Cap_Case=1206, Manufacturer=TDK, Supplier Part Number 1=445-8047-1-ND, TempCo=X5R, Tolerance_%=20%, Value1=Unknown, Value2=25V, ValueDisplayed=47uF
C4 C5 C6 C7 C8 C9 C16 C17 C18 C19 C20: library part CMP-0009226-3, "CAP, CERM, 10 uF, 50 V, +/- 10%, X7R, 1210", Cap_Case=1210, Manufacturer=MuRata, Supplier Part Number 1=490-6544-1-ND, TempCo=X7R, Tolerance_%=10%, Value1=Unknown, Value2=50V, ValueDisplayed=10uF
C10 C11 C14: library part CMP-0096737-1, "100 nF ±10% 50V Ceramic Capacitor X7R 0402 (1005 Metric)", Manufacturer=Wurth, Operating Temperature Range="-55°C to +125°C", TempCo=15%, Temperature Characteristic=X7R, Tolerance_%=10%, ValueDisplayed=100nF
C12 C13: library part CMP-0088943-1, "4.7µF ±10% 50V Ceramic Capacitor X7R 0805 (2012 Metric)", Digikey Part Number=445-C2012X7R1H475K125ACCT-ND, Manufacturer=TDK, Mouser Part Number=810-C2012X7R475K125C, Operating Temperature Range="-55°C to +125°C", TempCo=15%, Temperature Characteristic=X7R, Tolerance_%=10%, ValueDisplayed=4.7uF
C15: library part CMP-0860831-1, "CAP, CERM, 22 pF, 50 V,+/- 5%, C0G/NP0, AEC-Q200 Grade 1, 0402", Cap_Case=0402, Manufacturer=TDK, TempCo=C0G/NP0, Tolerance_%=5%, Value2=50V, ValueDisplayed=22pF
C21 C24 C26 C29 C31 C33 C36 C37 C41 C115 C116 C120 C125 C126 C130 C131 C135 C140 C141 C145 C146 C150 C155 C156 C160 C161 C165 C170 C171 C175 C176 C180 C185 C186 C190 C191 C195 C200 C201: library part CMP-0006326-2, "CAP, CERM, 0.1 uF, 50 V, +/- 20%, X7R, AEC-Q200 Grade 1, 0402", Cap_Case=0402, Manufacturer=TDK, Supplier Part Number 1=445-12271-1-ND, TempCo=X7R, Tolerance_%=20%, Value1=Unknown, Value2=50V, ValueDisplayed=0.1uF
C22 C23: library part CMP-0076706-1, "CAP, CERM, 4.7 µF, 25 V,+/- 10%, X7R, AEC-Q200 Grade 1, 0805", Cap_Case=2x1.25x1.25mm, Manufacturer=TDK, Supplier Part Number 1=445-6967-1-ND, TempCo=X7R, Tolerance_%=10%, Value2=25V, ValueDisplayed=4.7µF
C25 C30 C39: library part CMP-0035346-1, "1µF ±10% 10V Ceramic Capacitor X7S 0402 (1005 Metric)", Digikey Part Number=490-14457-1-ND, Manufacturer=Murata, Mouser Part Number=81-GRM155C71A105KE1D, Operating Temperature Range="-55°C to +125°C", TempCo=22%, Temperature Characteristic=X7S, Tolerance_%=10%, ValueDisplayed=1uF
C27 C40 C69 C70 C71 C72 C73 C76 C77 C78 C79 C86 C87 C88 C89 C90 C91 C92 C93 C96 C97 C111: library part CMP-0064970-1, "CAP, CERM, 0.1 uF, 16 V,+/- 10%, X7R, 0201", Cap_Case=0201, Manufacturer=MuRata, Supplier Part Number 1=81-GRM033Z71C104KE4D, TempCo=X7R, Tolerance_%=10%, Value1=Unknown, Value2=16V, ValueDisplayed=0.1uF
C28 C32 C34 C35 C38: library part CMP-0089543-1, "10µF ±10% 10V Ceramic Capacitor X7S 0805 (2012 Metric)", Digikey Part Number=445-173805-1-ND, Manufacturer=TDK, Mouser Part Number=810-CG4J3X7S1A106KAE, Operating Temperature Range="-55°C to +125°C", TempCo=22%, Temperature Characteristic=X7S, Tolerance_%=10%, ValueDisplayed=10uF
C42 C43 C95 C106 C203: library part CMP-0006228-2, "CAP, CERM, 0.1 uF, 16 V, +/- 10%, X7R, 0402", Cap_Case=0402, Manufacturer="Wurth Elektronik", Supplier Part Number 1=732-7532-1-ND, TempCo=X7R, Tolerance_%=10%, Value1=Unknown, Value2=16V, ValueDisplayed=0.1uF
C44 C48 C49 C68: library part CMP-0007341-4, "CAP, CERM, 4.7 uF, 16 V, +/- 10%, X5R, 0603", Cap_Case=0603, Manufacturer=MuRata, Supplier Part Number 1=490-10481-1-ND, TempCo=X5R, Tolerance_%=10%, Value1=Unknown, Value2=16V, ValueDisplayed=4.7uF
C45 C104: library part CMP-0007324-5, "CAP, CERM, 22 uF, 10 V, +/- 20%, X5R, 0603", Cap_Case=0603, Manufacturer=MuRata, Supplier Part Number 1=490-10476-1-ND, TempCo=X5R, Tolerance_%=20%, Value1=Unknown, Value2=10V, ValueDisplayed=22uF
C46 C47 C50 C51 C52 C53 C54 C55 C56 C57 C58 C59 C60 C61 C62 C63 C64 C65 C66 C67 C94: library part CMP-0009776-1, "CAP, CERM, 680 pF, 25 V, +/- 10%, X7R, 0201", Cap_Case=0201, Manufacturer=MuRata, Supplier Part Number 1=490-3182-1-ND, TempCo=X7R, Tolerance_%=10%, Value1=Unknown, Value2=25V, ValueDisplayed=680pF
C74: library part CMP-0006659-2, "CAP, CERM, 0.1 uF, 25 V, +/- 10%, X7R, 0402", Cap_Case=0402, Manufacturer=MuRata, Supplier Part Number 1=490-10698-1-ND, TempCo=X7R, Tolerance_%=10%, Value1=Unknown, Value2=25V, ValueDisplayed=0.1uF
C75 C80: library part CMP-0086225-1, "CAP, CERM, 10 µF, 16 V,+/- 10%, X5R, 0603", Cap_Case=0603, Manufacturer=MuRata, Supplier Part Number 1=490-10728-1-ND, TempCo=X5R, Tolerance_%=10%, Value2=16V, ValueDisplayed=10µF
C81 C84 C85: library part CMP-0006825-5, "CAP, CERM, 2.2 uF, 16 V, +/- 20%, X5R, 0603", Cap_Case=0603, Manufacturer="Wurth Elektronik", Supplier Part Number 1=732-7915-1-ND, TempCo=X5R, Tolerance_%=20%, Value1=Unknown, Value2=16V, ValueDisplayed=2.2uF
C82 C83: library part CMP-0006594-2, "CAP, CERM, 2.2 uF, 16 V, +/- 10%, X5R, 0402", Cap_Case=0402, Manufacturer=MuRata, Supplier Part Number 1=490-10695-1-ND, TempCo=X5R, Tolerance_%=10%, Value1=Unknown, Value2=16V, ValueDisplayed=2.2uF
C98 C99 C100 C101: library part CMP-0080076-1, "CAP, CERM, 4.7 pF, 50 V,+/- 3%, C0G/NP0, 0201", Cap_Case=0201, Manufacturer=MuRata, Supplier Part Number 1=490-11332-1-ND, TempCo=C0G/NP0, Tolerance_%=3%, Value2=50V, ValueDisplayed=4.7pF
C102: library part CMP-0007313-5, "CAP, CERM, 47 uF, 6.3 V, +/- 20%, X5R, 0603", Cap_Case=0603, Manufacturer=MuRata, TempCo=X5R, Tolerance_%=20%, Value1=Unknown, Value2=6.3V, ValueDisplayed=47uF
C103 C105: library part CMP-0860568-1, "CAP, CERM, 0.01 µF, 25 V,+/- 10%, X7R, 0201", Cap_Case=0201, Manufacturer=MuRata, TempCo=X7R, Tolerance_%=10%, Value2=25V, ValueDisplayed=0.01µF
C107: library part CMP-0090879-1, "2200pF ±10% 2000V (2kV) Ceramic Capacitor X7R (2R1) 1206 (3216 Metric)", Digikey Part Number=1608-1486-1-ND, Manufacturer="Knowles Syfer", Mouser Part Number=843-1206Y2K00222KET, Operating Temperature Range="-55°C to +125°C", TempCo=15%, Temperature Characteristic=X7R, Tolerance_%=10%, ValueDisplayed=2.2nF
C108: library part CMP-0085851-1, "CAP, CERM, 22 pF, 50 V,+/- 5%, C0G/NP0, 0402", Cap_Case=0402, Manufacturer=Walsin, TempCo=C0G/NP0, Tolerance_%=5%, Value2=50V, ValueDisplayed=22pF
C109: library part CMP-0008579-2, "CAP, CERM, 1000 pF, 2000 V, +/- 10%, X7R, AEC-Q200 Grade 1, 1206", Cap_Case=1206, Manufacturer=Kemet, Supplier Part Number 1=399-12976-1-ND, TempCo=X7R, Tolerance_%=10%, Value1=Unknown, Value2=2000V, ValueDisplayed=1000pF
C110: library part CMP-0006283-2, "CAP, CERM, 2.2 uF, 35 V, +/- 10%, X5R, 0402", Cap_Case=0402_065, Manufacturer=TDK, Supplier Part Number 1=445-9028-1-ND, TempCo=X5R, Tolerance_%=10%, Value1="0.005925 ohm", Value2=35V, ValueDisplayed=2.2uF
C112 C127 C142 C157 C172 C187: library part CMP-0008802-2, "CAP, CERM, 10 uF, 50 V, +/- 10%, X7R, 1206", Cap_Case=1206, Manufacturer=Samsung, Supplier Part Number 1=1276-6767-1-ND, TempCo=X7R, Tolerance_%=10%, Value1=Unknown, Value2=50V, ValueDisplayed=10uF
C113 C114 C128 C129 C143 C144 C158 C159 C173 C174 C188 C189: library part CMP-0064946-2, "CAP, CERM, 0.1 uF, 50 V,+/- 10%, X7R, 0402", Cap_Case=0402, Manufacturer=TDK, Supplier Part Number 1=445-173610-1-ND, TempCo=X7R, Tolerance_%=10%, Value1=Unknown, Value2=50V, ValueDisplayed=0.1uF
C117 C132 C147 C162 C177 C192: library part CMP-0093200-1, "1µF ±10% 10V Ceramic Capacitor X7R 0402 (1005 Metric)", Digikey Part Number=2571-GMC04X7R105K10NTTR-ND, Manufacturer="Cal-Chip Electronics", Operating Temperature Range="-55°C to +125°C", TempCo=15%, Temperature Characteristic=X7R, Tolerance_%=10%, ValueDisplayed=1uF
C118 C119 C121 C122 C123 C124 C133 C134 C136 C137 C138 C139 C148 C149 C151 C152 C153 C154 C163 C164 C166 C167 C168 C169 C178 C179 C181 C182 C183 C184 C193 C194 C196 C197 C198 C199: library part CMP-0009662-3, "CAP, CERM, 47 pF, 25 V, +/- 5%, C0G/NP0, 0201", Cap_Case=0201, Manufacturer=MuRata, Supplier Part Number 1=490-1256-1-ND, TempCo=C0G/NP0, Tolerance_%=5%, Value1=Unknown, Value2=25V, ValueDisplayed=47pF
C202: library part CMP-0009699-1, "CAP, CERM, 0.033 uF, 6.3 V, +/- 10%, X5R, 0201", Cap_Case=0201, Manufacturer=MuRata, Supplier Part Number 1=490-3170-1-ND, TempCo=X5R, Tolerance_%=10%, Value1=Unknown, Value2=6.3V, ValueDisplayed=0.033uF
D1: library part CMP-0005564-3, "Diode, TVS, Bi, 33 V, SMB", Manufacturer="Diodes Inc.", Value1=600W
D2 D3 D4 D5 D7: library part CMP-0081765-2, "LED, Green, SMD", Color=Green, Manufacturer="Wurth Elektronik", Power_TotalModule=99mW, Value1=0.099W, Value2=3.2V
D6: library part CMP-0122246-1, "Red 624nm LED Indication - Discrete 2V 0402 (1005 Metric)", Color=Red, Digikey Part Number=732-13422-1-ND, Forward Current=20mA, Manufacturer=Wurth, Mouser Part Number=710-150040RS73220, Operating Temperature Range="-40°C to +85°C", Power_TotalModule=48mW
DC+ GND: library part CMP-0078421-2, "PCB Mounting Hole", Manufacturer=Any, PartNumber=N/A
FID1 FID2 FID3: library part CMP-0077181-1, "Fiducial mark.  There is nothing to buy or mount.", Manufacturer=N/A
J1: library part CMP-0054561-1, "Header, 50mil, 6x1, Gold,  TH", Manufacturer="Sullins Connector Solutions", Supplier Part Number 1=S9014E-06-ND
J2: library part CMP-0054555-1, "Header, 50mil, 2x1, Gold, TH", Manufacturer="Sullins Connector Solutions", Supplier Part Number 1=S9014E-02-ND
J3: library part CMP-0125599-1, "Connector Header Surface Mount 4 position 0.049\" (1.25mm)", Current_A=1A, Digikey Part Number=455-1580-1-ND, Manufacturer=JST, Operating Temperature Range="-25°C to +85°C", Voltage_V=50V
J4 J5 J6 J7 J8 J9: library part CMP-0126588-1, "Conn FPC Connector F 12 POS 0.5mm Solder Ver SMD T/R", Current_A=500mA, Manufacturer=JST, Operating Temperature Range="-25°C to +85°C", Voltage_V=50V
J10 J11 J12 J13 J14: library part CMP-0054564-1, "Header, 50mil, 3x1, Gold, TH", Color=Black, Manufacturer="Sullins Connector Solutions", Supplier Part Number 1=S9014E-03-ND
L1: library part CMP-0081093-1, "Inductor, Shielded, Metal Composite, 1.5 µH, 2.3 A, 0.11 ohm, AEC-Q200 Grade 0, SMD", Manufacturer=TDK, Supplier Part Number 1=445-174575-1-ND, Value1="0.11 ohm", Value2=2.3A, ValueDisplayed=1.5µH
L2 L3: library part CMP-0062877-1, "Inductor, 1 uH, 3.1 A, 0.06 ohm, SMD", Manufacturer=TDK, Supplier Part Number 1=445-173102-1-ND, Value1="0.06 ohm", Value2=3.1A, ValueDisplayed=1uH
L4: library part CMP-0003226-1, "Ferrite Bead, 75 ohm @ 100 MHz, 0.3 A, 0402", Manufacturer="Wurth Elektronik", Supplier Part Number 1=732-2391-1-ND, Value1="0.31 ohm", Value2=0.3A, ValueDisplayed="75 ohm"
L5: library part CMP-0003353-2, "Ferrite Bead, 220 ohm @ 100 MHz, 2.5 A, 0603", Manufacturer=MuRata, Supplier Part Number 1=490-5225-1-ND, Value1="0.04 ohm", Value2=2.5A, ValueDisplayed="220 ohm"
L6 L7: library part CMP-0003173-2, "Ferrite Bead, 60 ohm @ 100 MHz, 3 A, 0603", Manufacturer="Wurth Elektronik", Supplier Part Number 1=732-4660-1-ND, Value1="0.04 ohm", Value2=3A, ValueDisplayed="60 ohm"
L9 L10: library part CMP-0003238-1, "Ferrite Bead, 70 ohm @ 100 MHz, 1.2 A, 0402", Manufacturer="Wurth Elektronik", Supplier Part Number 1=732-2390-1-ND, Value1="0.09 ohm", Value2=1.2A, ValueDisplayed="70 ohm"
L11 L12: library part CMP-0092201-1, "2 Line Common Mode Choke Surface Mount 200mA DCR 1.2Ohm", Digikey Part Number=732-1474-1-ND, Impedance At Frequency="2200Ω @ 100MHz", Manufacturer=Wurth, Mouser Part Number=710-744232222, Operating Temperature Range="-40°C to +125°C"
LBL1: library part CMP-0003625-1, "Thermal Transfer Printable Labels, 0.650\" W x 0.200\" H - 10,000 per roll", Manufacturer=Brady, Supplier Part Number 1=97C5133
Logo1: library part CMP-0074844-1
Logo2: library part CMP-0074838-1, "Texas Instrument Corporate Signature"
Logo3: library part CMP-0074847-1, "FCC_disclaimer"
Logo4: library part CMP-0074769-1
NT1: library part CMP-0078142-5, "Single point connection between nets.", Manufacturer=N/A
Q1 Q2: library part CMP-0000198-1, "MOSFET, N-CH, 12 V, 2.9 A, YJC0003A (PICOSTAR-3)", Alternate Manufacturer=None, Manufacturer="Texas Instruments", Supplier Part Number 1=296-39991-1-ND, Value1=0.04, Value2="2 nC"
R1: library part CMP-0026504-2, "RES, 681 k, 1%, 0.063 W, AEC-Q200 Grade 0, 0402", Manufacturer=Vishay-Dale, Power_W=63mW, Supplier Part Number 1=541-681KLCT-ND, TempCo="100 ppm/C", Tolerance_%=1%, Value2=0.063W, Value_Code=681k
R2: library part CMP-0026437-2, "RES, 51.1 k, 1%, 0.063 W, AEC-Q200 Grade 0, 0402", Manufacturer=Vishay-Dale, Power_W=63mW, Supplier Part Number 1=541-51.1KLCT-ND, TempCo="100 ppm/C", Tolerance_%=1%, Value2=0.063W, Value_Code=51k1, ValueDisplayed=51.1k
R3: library part CMP-0026367-2, "RES, 40.2 k, 1%, 0.063 W, AEC-Q200 Grade 0, 0402", Manufacturer=Vishay-Dale, Power_W=63mW, Supplier Part Number 1=541-40.2KLCT-ND, TempCo="100 ppm/C", Tolerance_%=1%, Value2=0.063W, Value_Code=40k2, ValueDisplayed=40.2k
R4 R6 R8 R15 R129 R145 R161 R177 R193 R209 R223: library part CMP-0025958-3, "RES, 10.0 k, 1%, 0.063 W, AEC-Q200 Grade 0, 0402", Manufacturer=Vishay-Dale, Power_W=63mW, Supplier Part Number 1=541-10.0KLCT-ND, TempCo="100 ppm/C", Tolerance_%=1%, Value2=0.063W, Value_Code=10k0, ValueDisplayed=10.0k
R5: library part CMP-0026003-3, "RES, 13.0 k, 1%, 0.063 W, AEC-Q200 Grade 0, 0402", Manufacturer=Vishay-Dale, Power_W=63mW, Supplier Part Number 1=541-13.0KLCT-ND, TempCo="100 ppm/C", Tolerance_%=1%, Value2=0.063W, Value_Code=13k0, ValueDisplayed=13.0k
R7 R9 R41: library part CMP-0026890-5, "RES, 2.2 k, 5%, 0.063 W, AEC-Q200 Grade 0, 0402", Manufacturer=Vishay-Dale, Power_W=63mW, Supplier Part Number 1=541-2.2KJCT-ND, TempCo="200 ppm/C", Tolerance_%=5%, Value2=0.063W, Value_Code=2k20, ValueDisplayed=2.2k
R10: library part CMP-0026464-2, "RES, 5.23 k, 1%, 0.063 W, AEC-Q200 Grade 0, 0402", Manufacturer=Vishay-Dale, Power_W=63mW, Supplier Part Number 1=541-5.23KLCT-ND, TempCo="100 ppm/C", Tolerance_%=1%, Value2=0.063W, Value_Code=5k23, ValueDisplayed=5.23k
R11: library part CMP-0086358-1, "RES, 0, 0%, 0.25 W, AEC-Q200 Grade 0, 0603", Manufacturer=Rohm, Power_W=250mW, Tolerance_%=0%, Value2=0.25W, Value_Code=0000, ValueDisplayed=0
R12 R13 R14 R16: library part CMP-0086442-2, "RES SMD 0 OHM JUMPER 1/20W 0201", Manufacturer=Yageo, Power_W=50mW, TempCo=200ppm/°C, Tolerance_%=5%
R17 R18 R19 R24 R25 R26 R27 R28 R29 R30 R31 R32 R34 R35 R37 R38 R40 R42 R116 R119 R120 R134 R137 R138 R150 R153 R154 R166 R169 R170 R182 R185 R186 R198 R201 R202 R211 R212 R216 R217: library part CMP-0027015-3, "RES, 22, 5%, 0.05 W, AEC-Q200 Grade 1, 0201", Manufacturer=Panasonic, Power_W=50mW, Supplier Part Number 1=ERJ-1GNJ220C-ND, TempCo="200 ppm/C", Tolerance_%=5%, Value2=0.05W, Value_Code=22R0, ValueDisplayed=22
R20: library part CMP-0026231-2, "RES, 2.20 k, 1%, 0.063 W, AEC-Q200 Grade 0, 0402", Manufacturer=Vishay-Dale, Power_W=63mW, Supplier Part Number 1=541-2.20KLCT-ND, TempCo="100 ppm/C", Tolerance_%=1%, Value2=0.063W, Value_Code=2k20, ValueDisplayed=2.20k
R21 R22 R23 R66 R91 R92 R93 R94 R95 R96 R97: library part CMP-0026658-1, "RES, 10.0 k, 1%, 0.1 W, 0402", Manufacturer=Panasonic, Power_W=100mW, Supplier Part Number 1=P10.0KLCT-ND, TempCo="100 ppm/C", Tolerance_%=1%, Value2=0.1W, Value_Code=10k0, ValueDisplayed=10.0k
R33 R36 R39 R46 R222: library part CMP-0026992-3, "RES, 0, 5%, 0.1 W, AEC-Q200 Grade 0, 0402", Manufacturer=Panasonic, Power_W=100mW, Supplier Part Number 1=P0.0JCT-ND, TempCo="600 ppm/C", Tolerance_%=5%, Value2=0.1W, Value_Code=0000, ValueDisplayed=0
R43: library part CMP-0022710-2, "RES, 0.005, 1%, 0.25 W, AEC-Q200 Grade 1, 0603", Manufacturer=Panasonic, Power_W=250mW, TempCo=ppm/C, Tolerance_%=1%, Value2=0.25W, Value_Code=5L000, ValueDisplayed=0.005
R44 R45 R48 R49 R50 R51 R52 R53 R54 R55 R56 R57 R58 R59 R60 R61 R62 R63 R64 R65 R77: library part CMP-0027944-1, "RES, 100, 1%, 0.05 W, 0201", Manufacturer="Yageo America", Power_W=50mW, Supplier Part Number 1=603-RC0201FR-7D100RL, TempCo="200 ppm/C", Tolerance_%=1%, Value2=0.05W, Value_Code=100R, ValueDisplayed=100
R47: library part CMP-0023427-3, "RES, 120 k, 0.1%, 0.1 W, 0603", Manufacturer="Susumu Co Ltd", Power_W=100mW, Supplier Part Number 1=RG16P120KBCT-ND, TempCo="25 ppm/C", Tolerance_%=0.1%, Value2=0.1W, Value_Code=120k
R67: library part CMP-0026178-2, "RES, 22.1 k, 1%, 0.063 W, AEC-Q200 Grade 0, 0402", Manufacturer=Vishay-Dale, Power_W=63mW, Supplier Part Number 1=541-22.1KLCT-ND, TempCo="100 ppm/C", Tolerance_%=1%, Value2=0.063W, Value_Code=22k1, ValueDisplayed=22.1k
R68 R69 R71 R72 R121 R122 R139 R140 R155 R156 R171 R172 R187 R188 R203 R204: library part CMP-0028031-1, "RES, 4.70 k, 1%, 0.05 W, 0201", Manufacturer="Yageo America", Power_W=50mW, Supplier Part Number 1=603-RC0201FR-7D4K7L, TempCo="200 ppm/C", Tolerance_%=1%, Value2=0.05W, Value_Code=4k70, ValueDisplayed=4.70k
R70: library part CMP-0027558-1, "RES, 2.20 k, 1%, 0.05 W, 0201", Manufacturer="Yageo America", Power_W=50mW, Supplier Part Number 1=YAG2572CT-ND, TempCo="200 ppm/C", Tolerance_%=1%, Value2=0.05W, Value_Code=2k20, ValueDisplayed=2.20k
R73 R74: library part CMP-0026880-3, "RES, 22, 5%, 0.063 W, AEC-Q200 Grade 0, 0402", Manufacturer=Vishay-Dale, Power_W=63mW, Supplier Part Number 1=541-22JCT-ND, TempCo="200 ppm/C", Tolerance_%=5%, Value2=0.063W, Value_Code=22R0, ValueDisplayed=22
R75: library part CMP-0078193-1, "RES, 1.0 k, 5%, 0.1 W, AEC-Q200 Grade 0, 0402", Manufacturer=Panasonic, Power_W=100mW, Supplier Part Number 1=P1.0KJCT-ND, TempCo="200 ppm/C", Tolerance_%=5%, Value2=0.1W, Value_Code=1k00, ValueDisplayed=1.0k
R76 R98 R100 R102 R110 R111 R220 R221: library part CMP-0081856-1, "RES, 0, 0%, 0.2 W, AEC-Q200 Grade 0, 0402", Manufacturer=Vishay-Dale, Power_W=200mW, Supplier Part Number 1=541-0.0YBTR-ND, Tolerance_%=0%, Value2=0.2W, Value_Code=0
R78 R79 R80: library part CMP-0027562-1, "RES, 2.49 k, 1%, 0.05 W, 0201", Manufacturer="Yageo America", Power_W=50mW, Supplier Part Number 1=YAG2338CT-ND, TempCo="200 ppm/C", Tolerance_%=1%, Value2=0.05W, Value_Code=2k49, ValueDisplayed=2.49k
R81: library part CMP-0028124-1, "RES, 1.50 k, 1%, 0.05 W, AEC-Q200 Grade 0, 0201", Manufacturer="KOA Speer", Power_W=50mW, Supplier Part Number 1=660-RK73H1HTTC1501F, TempCo="200 ppm/C", Tolerance_%=1%, Value2=0.05W, Value_Code=1k50, ValueDisplayed=1.50k
R82 R83 R84 R85 R86 R87 R88 R89 R90: library part CMP-0028071-1, "RES, 10.0 k, 1%, 0.05 W, 0201", Manufacturer="Yageo America", Power_W=50mW, Supplier Part Number 1=603-RC0201FS-7D10KL, TempCo="200 ppm/C", Tolerance_%=1%, Value2=0.05W, Value_Code=10k0, ValueDisplayed=10.0k
R99 R101: library part CMP-0026544-2, "RES, 75.0, 1%, 0.063 W, AEC-Q200 Grade 0, 0402", Manufacturer=Vishay-Dale, Power_W=63mW, Supplier Part Number 1=541-75.0LCT-ND, TempCo="100 ppm/C", Tolerance_%=1%, Value2=0.063W, Value_Code=75R0, ValueDisplayed=75.0
R103: library part CMP-0026515-2, "RES, 6.49 k, 1%, 0.063 W, AEC-Q200 Grade 0, 0402", Manufacturer=Vishay-Dale, Power_W=63mW, Supplier Part Number 1=541-6.49KLCT-ND, TempCo="100 ppm/C", Tolerance_%=1%, Value2=0.063W, Value_Code=6k49, ValueDisplayed=6.49k
R104 R105: library part CMP-0026631-1, "RES, 4.70 k, 1%, 0.063 W, 0402", Manufacturer="TE Connectivity", Power_W=63mW, Supplier Part Number 1=A121542CT-ND, TempCo="100 ppm/C", Tolerance_%=1%, Value2=0.063W, Value_Code=4k70, ValueDisplayed=4.70k
R106: library part CMP-0026088-3, "RES, 1.50 k, 1%, 0.063 W, AEC-Q200 Grade 0, 0402", Manufacturer=Vishay-Dale, Power_W=63mW, Supplier Part Number 1=541-1.50KLCT-ND, TempCo="100 ppm/C", Tolerance_%=1%, Value2=0.063W, Value_Code=1k50, ValueDisplayed=1.50k
R107 R112 R113 R124 R130 R131 R142 R146 R147 R158 R162 R163 R174 R178 R179 R190 R194 R195 R206: library part CMP-0026071-3, "RES, 1.00 k, 1%, 0.063 W, AEC-Q200 Grade 0, 0402", Manufacturer=Vishay-Dale, Power_W=63mW, Supplier Part Number 1=541-1.00KLCT-ND, TempCo="100 ppm/C", Tolerance_%=1%, Value2=0.063W, Value_Code=1k00, ValueDisplayed=1.00k
R108 R109: library part CMP-0026725-1, "RES, 1.00 k, 1%, 0.0625 W, 0402", Manufacturer="Yageo America", Power_W=62.5mW, Supplier Part Number 1=311-1.00KLRCT-ND, TempCo="100 ppm/C", Tolerance_%=1%, Value2=0.0625W, Value_Code=1k00, ValueDisplayed=1.00k
R114 R115 R117 R118 R123 R125 R132 R133 R135 R136 R141 R143 R148 R149 R151 R152 R157 R159 R164 R165 R167 R168 R173 R175 R180 R181 R183 R184 R189 R191 R196 R197 R199 R200 R205 R207: library part CMP-0078192-1, "RES, 20.0, 1%, 0.05 W, 0201", Manufacturer=Vishay-Dale, Power_W=50mW, Supplier Part Number 1=541-2947-1-ND, TempCo="200 ppm/C", Tolerance_%=1%, Value2=0.05W, Value_Code=20R0, ValueDisplayed=20.0
R126 R128 R218 R219: library part CMP-0027293-2, "RES, 100 k, 1%, 0.05 W, 0201", Manufacturer="Yageo America", Power_W=50mW, Supplier Part Number 1=311-100KMCT-ND, TempCo="200 ppm/C", Tolerance_%=1%, Value2=0.05W, Value_Code=100k
R127 R144 R160 R176 R192 R208: library part CMP-0078583-1, "RES, 15.0 k, 1%, 0.063 W, 0402", Manufacturer="Yageo America", Power_W=63mW, Supplier Part Number 1=311-15.0KLRCT-ND, TempCo="100 ppm/C", Tolerance_%=1%, Value2=0.063W, Value_Code=15k0, ValueDisplayed=15.0k
R210: "RES, 100 k, 1%, 0.063 W, AEC-Q200 Grade 0, 0402", Manufacturer=Vishay-Dale, PartNumber=CRCW0402100KFKED, Power_W=63mW, Supplier Part Number 1=541-100KLCT-ND, TempCo="100 ppm/C", Tolerance_%=1%, Value2=0.063W, Value_Code=100k
R213: library part CMP-0078781-1, "RES, 10.5 k, 1%, 0.063 W, 0402", Manufacturer="Yageo America", Power_W=63mW, Supplier Part Number 1=YAG2951CT-ND, TempCo="100 ppm/C", Tolerance_%=1%, Value2=0.063W, Value_Code=10k5, ValueDisplayed=10.5k
R214: "RES, 10 k, 5%, 0.063 W, AEC-Q200 Grade 0, 0402", Manufacturer=Vishay-Dale, PartNumber=CRCW040210K0JNED, Power_W=63mW, Supplier Part Number 1=541-10KJCT-ND, TempCo="200 ppm/C", Tolerance_%=5%, Value2=0.063W, Value_Code=10k0, ValueDisplayed=10k
R215: library part CMP-0022769-3, "RES, 120, 1%, 0.1 W, 0603", Manufacturer="Yageo America", Power_W=100mW, Supplier Part Number 1=311-120HRCT-ND, TempCo="200 ppm/C", Tolerance_%=1%, Value2=0.1W, Value_Code=120R, ValueDisplayed=120
RT1: library part CMP-0091865-2, "±1% tolerance 10kΩ linear thermistor available in 0402 and 0603 package options 2-SOT-5X3 -40 to 125", Digikey Part Number=296-TMP6131DYATCT-ND, Manufacturer="Texas Instruments", Max Current=400uA, Mouser Part Number=595-TMP6131DYAT, Operating Temperature Range="-40°C to +125°C", TempCo=6400ppm/°C, Tolerance_%=1%
SW1: library part CMP-0093456-1, "Tactile Switch SPST-NO Side Actuated Surface Mount, Right Angle", Coil Resistance_ohm=100mΩ, Contact Current Rating=50mA, Digikey Part Number=732-7057-1-ND, Manufacturer="Wurth Electronics", Mouser Part Number=710-434351045816, Operating Force=160gf, Operating Temperature Range="-40°C to +85°C"
T1 T2: library part CMP-0088807-1, "350µH  Pulse Transformer 1:1 Surface Mount", Digikey Part Number=732-74930000CT-ND, Manufacturer="Wurth Electronics", Mouser Part Number=710-74930000, Operating Temperature Range="-40°C to +105°C", Voltage_Isolation_Vrms=1500Vrms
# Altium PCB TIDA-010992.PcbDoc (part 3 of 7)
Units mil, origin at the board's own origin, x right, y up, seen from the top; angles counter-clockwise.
Board outline 2810.81 x 2427 mil, 8 copper layers (L01-TOP, L02-GND, L03-SIG, L04-GND, L05-PWR, L06-SIG, L07-GND, L08-BOTTOM), stack 61.9 mil thick; 521 components, 377 nets, 1545 pads, 874 vias.

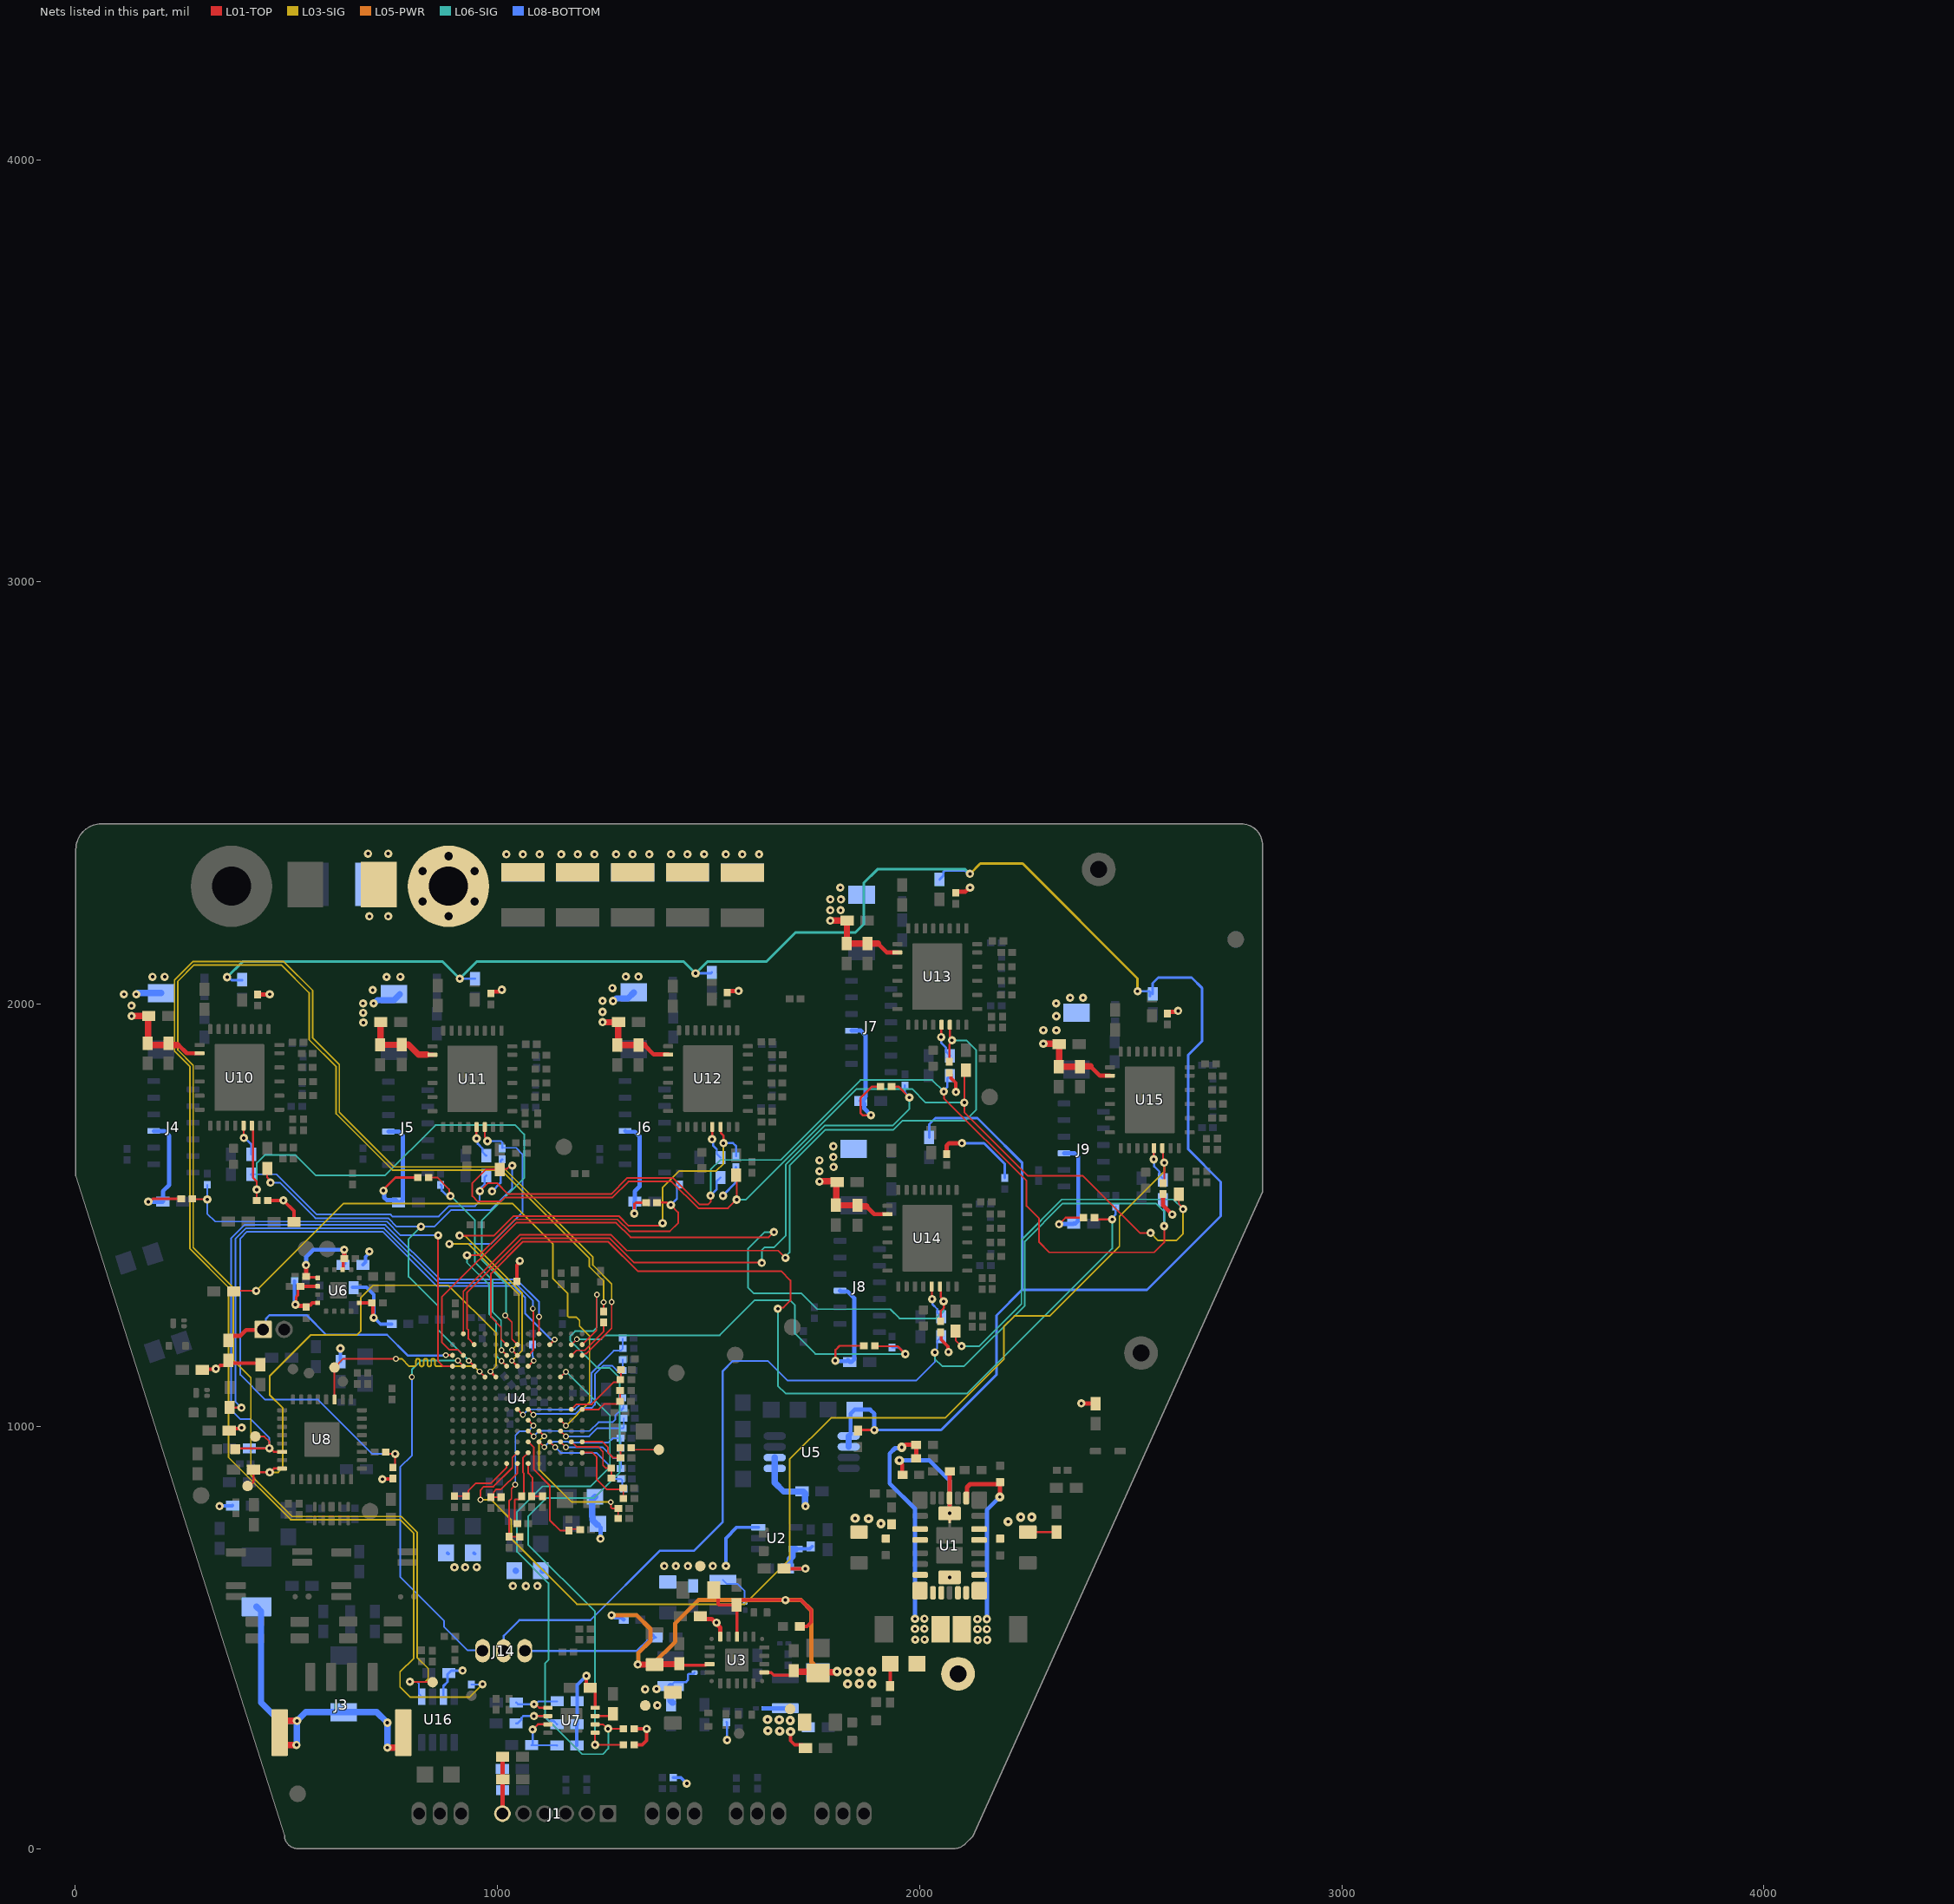
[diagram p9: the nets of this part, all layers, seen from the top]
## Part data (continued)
TP1: library part CMP-0055137-2, "Test Point, Miniature, Red, TH", Color=Red, Manufacturer="Keystone Electronics", Supplier Part Number 1=36-5000-ND
TP2 TP3: "Test Point, Miniature, Black, TH", Color=Black, Manufacturer="Keystone Electronics", PartNumber=5001, Supplier Part Number 1=36-5001-ND
TP4 TP5 TP6 TP7 TP13 TP14 TP18 TP24 TP25: library part CMP-0003825-1, "1mm Test Point, SMT", Manufacturer=Any
TP8 TP9 TP10 TP11 TP12 TP15 TP16 TP17 TP19 TP20 TP21 TP22 TP23: library part CMP-0078143-3, "TEST POINT.  No entry in BOM.", Manufacturer=N/A
U1: library part CMP-0092030-4, "3-V to 36-V Input, 1-V to 6-V Output, 3-A Power Module", Manufacturer="Texas Instruments", Max Supply Voltage=36V, Min Supply Voltage=3V, Operating Temperature Range=to, Output Voltage=1-6V, Switching Frequency=200-2200kHz
U2: library part CMP-0085889-2, "Small-Size Micropower Low-Voltage Comparator, DCK0005A (SOT-SC70-5)", Alternate Manufacturer="Texas Instruments", Alternate PartNumber=TLV7021DCKT, Operating Temperature Range="-40 to 125 C", Rating=Catalog
U3: library part CMP-0097122-2, "Automotive Camera PMIC", Manufacturer="Texas Instruments", Max Supply Voltage=18.3V, Min Supply Voltage=2.5V, Nominal Supply Current=10mA, Operating Temperature Range="-40°C to +125°C", Output Voltage=2.5-4/0.9-1.9/1.8-3.3V
U4: library part CMP-0098413-1, "Real-Time Microcontroller, NFBGA169", Frequency_Fixed=200MHz, Manufacturer="Texas Instruments", Max Supply Voltage=3.63V, Min Supply Voltage=1.14V, Operating Temperature Range="-40°C to +155°C"
U5: library part CMP-0077709-1, "High-Precision Voltage Reference with Integrated High-Bandwidth Buffer, DGK0008A (VSSOP-8)", Alternate Manufacturer="Texas Instruments", Alternate PartNumber=REF6230IDGKT
U6: library part CMP-0126121-1, "5 output reference-less clock generator with bulk acoustic wave (BAW) 16-TQFN -40 to 85", Digikey Part Number=296-LMK3C0105V33RERRTR-ND, Manufacturer="Texas Instruments", Max Frequency=200MHz, Max Supply Voltage=3.465V, Min Supply Voltage=1.71V, Mouser Part Number=595-LMK3C0105V33RERR, Operating Temperature Range="-40°C to +85°C"
U7: library part CMP-0005119-3, "I2C-Compatible (2-Wire) Serial EEPROM 256 kb, 8UDFN", Manufacturer=Atmel, Supplier Part Number 1=AT24C256C-MAHL-TCT-ND
U8: library part CMP-0124715-2, "Deterministic, Low-Latency, Low-Power, 10/100 Mbps, Industrial Ethernet PHY", Manufacturer="Texas Instruments", Max Supply Voltage=3.6V, Min Supply Voltage=1.62V, Operating Temperature Range="-40°C to +85°C"
U9: library part CMP-0073613-3, "4-Channel Ultra-Low-Capacitance IEC ESD Protection Diode, DQA0010A (USON-10)", Alternate Manufacturer="Texas Instruments"
U10 U11 U12 U13 U14 U15: library part CMP-0122073-1, "Three-Phase Integrated FET Motor Driver", Manufacturer="Texas Instruments", Max Supply Voltage=65V, Min Supply Voltage=4.5V, Nominal Supply Current=6.6-8.2mA, Operating Temperature Range="-40°C to +150°C", Switching Frequency=100kHz
U16: library part CMP-0080976-2, "3.3-V CAN Transceivers with CAN FD (Flexible Data Rate), DCN0008A (SOT-23-8)", Alternate Manufacturer="Texas Instruments", Alternate PartNumber=TCAN332GDCNT
ZZ1: library part CMP-0003616-3
ZZ2: library part CMP-0077236-1
ZZ3: library part CMP-0077237-1
ZZ4: library part CMP-0077238-1

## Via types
v1: diameter 19.68, hole 8, L01-TOP to L08-BOTTOM, tented both sides, 520 vias
v2: diameter 14, hole 8, L01-TOP to L08-BOTTOM, tented both sides, 146 vias
v3: diameter 19.68, hole 8, L01-TOP to L08-BOTTOM, 141 vias
v4: diameter 30, hole 18, L01-TOP to L08-BOTTOM, 18 vias
v5: diameter 22, hole 8, L01-TOP to L08-BOTTOM, tented both sides, 16 vias
v6: diameter 39.37, hole 19.68, L01-TOP to L08-BOTTOM, 12 vias
v7: diameter 22, hole 8, L01-TOP to L08-BOTTOM, 8 vias
v8: diameter 18, hole 8, L01-TOP to L08-BOTTOM, tented both sides, 5 vias
v9: diameter 14, hole 8, L01-TOP to L08-BOTTOM, 4 vias
v10: diameter 157.48, hole 98.43, L01-TOP to L08-BOTTOM, 4 vias

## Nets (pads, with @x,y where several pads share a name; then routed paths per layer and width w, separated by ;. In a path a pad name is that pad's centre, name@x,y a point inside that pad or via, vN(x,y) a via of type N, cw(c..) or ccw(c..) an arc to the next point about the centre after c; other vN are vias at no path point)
1V2: C37.1 C38.1 C80.1 L3.2 L5.1 R16.2 TP11.1 U2.3 | length 242.2
  L08-BOTTOM w4: L3.2@1533.71,636.03 1542.72,627.02 1568.48,627.02 1585.35,610.14 1585.35,585.8 R16.2@1586.74,584.41
  L08-BOTTOM w8: v1(1541.04,669.45) 1541.04,734.83 1567.11,760.91 U2.3@1617.81,760.91
  L08-BOTTOM w15: L5.1@1043.03,657.95 L5.1@1043.25,657.74 ; C80.1@1106.34,657.74 C80.1@1106.55,657.53
  other v1: 1036.45,622.01 1067.2,621.62 1094.52,621.88
  other v3: 1394.95,669.09 1422.51,669.09 1451.02,669.09 1510.02,669.09
1V8: C33.1 C34.1 L2.2 R14.2 TP10.1 | length 119.4
  L08-BOTTOM w5: L2.2@1410.13,385.05 1419.44,394.36 1446.69,394.36 1451.02,398.69 1451.02,411.84 1453.2,414.02 1464.23,414.02 R14.2@1466.91,416.69
  L08-BOTTOM w15: L2.2@1410.13,385.05 1410.13,349.76 1414.44,345.45 C33.1@1414.92,345.45
  other v1: 1378.46,339.19
  other v3: 1349.77,377.14 1376.71,377.77
3V3: C21.1 C31.1 C32.1 C41.1 C43.1 C71.1 C72.1 C73.1 C74.2 C81.1 C84.1 C120.2 C135.2 C150.2 C165.2 C180.2 C195.2 C203.2 J1.6 J4.7 J5.7 J6.7 J7.7 J8.7 J9.7 L1.2 L4.1 L6.1 L7.1 L9.2 L10.2 R6.1 R7.2 R9.2 R13.2 R20.2 R21.1 R22.1 R23.1 R33.2 R41.2 R66.1 R67.2 R68.2 R69.2 R70.2 R71.2 R72.2 R76.1 R82.2 R83.2 R84.2 R85.2 R86.2 R87.2 R88.2 R89.2 R92.1 R93.1 R94.1 R108.2 R109.2 R121.2 R122.2 R126.1 R139.2 R140.2 R155.2 R156.2 R171.2 R172.2 R187.2 R188.2 R203.2 R204.2 R214.2 TP9.1 U2.5 U3.17 U5.1 U5.2 U6.5 U6.14 U6.16 U7.8 U16.3 | length 5019.2
  L01-TOP w5: v1(1800.29,1155.69) 1800.6,1155.99 1800.6,1180.99 1810.28,1190.68 R87.2@1867.95,1190.68 ; v1(1884.56,1737.05) 1864.77,1737.05 1859.63,1742.19 1859.63,1777.41 1886.86,1804.63 R86.2@1907.22,1804.63 ; v1(2330.26,1478.61) 2345.91,1494.26 R88.2@2388.2,1494.26
  L01-TOP w6: v1(172.72,1531.92) 176.42,1531.92 183.55,1539.05 R83.2@251.15,1539.05 ; v1(521.28,1288.32) 523.38,1290.43 523.38,1307.17 527.53,1311.31 527.53,1326.49 532.79,1331.76 C72.1@533.58,1331.76 ; v1(729.61,1558.12) 729.61,1560.64 758.46,1589.48 R84.2@811.02,1589.48 ; v1(1323.98,1503.95) 1323.98,1526.28 1327.49,1529.79 R85.2@1351.95,1529.79
  L01-TOP w8: R108.2@300.53,1134.04 301.66,1135.18 v1@331.54,1135.18 ; v1(332.67,1136.31) 334.76,1136.31 343.2,1144.75 354.15,1144.75 361.96,1152.56 R66.1@361.96,1156.5 ; R66.1@362.94,1153.55 366.68,1149.82 433.89,1149.82 R67.2@437.83,1145.88 ; R109.2@364.31,990.14 368.65,994.48 391.56,994.48 v1(393.8,996.72) ; R122.2@455.76,1535.17 v1(492.71,1535.17) 517.98,1509.9 R41.2@517.98,1484.46 ; C72.1@533.58,1331.76 U6.14@574.04,1331.76 ; C73.1@546.93,1283.39 551.2,1287.65 556.75,1287.65 561.19,1292.09 573.75,1292.09 U6.16@574.04,1292.39 ; U6.5@672.47,1292.39 672.62,1292.24 702.16,1292.24 C71.1@702.31,1292.09 704.58,1289.82 704.58,1259.45 v1(706.82,1257.22) ; v1(727.37,874.82) 728.26,875.71 751.41,875.71 R70.2@752.3,876.6 ; R68.2@1046.11,1343.38 1045.78,1343.71 1045.78,1381.75 1052.71,1388.68 v1(1052.71,1391.84) ; v1(1210.61,408.93) 1210.61,388.32 1218.42,380.51 C74.2@1219.68,380.51 ; C74.2@1223.46,380.51 1231.27,372.69 U7.8@1231.27,333.37 ; R72.2@1323.92,245.74 1343.18,245.74 1353.23,255.79 v1(1353.23,283.54) 1353.03,283.74 1324.12,283.74 R71.2@1323.92,283.93 ; R7.2@1678.62,662.99 1678.67,663.03 1729.38,663.03 v1(1729.42,663.08) ; v5(1694.22,276.69) 1694.22,255.35 1703.83,245.74 1721.78,245.74 R9.2@1729.6,237.93 ; R188.2@2050.44,1221.33 2051.08,1220.69 2051.08,1204.83 2066.75,1189.16 2066.75,1177.62 v1(2068.43,1175.95) ; R172.2@2070.28,1837.54 2074.55,1833.27 2074.55,1824.22 2085.12,1813.66 2085.12,1792.69 v1(2085.99,1791.81)
  L01-TOP w10: R121.2@431.58,2022.53 431.93,2022.88 460.09,2022.88 v1(460.44,2023.23) ; v1(521.28,1288.32) 523.9,1288.32 526.89,1285.33 544.2,1285.33 C73.1@546.93,1282.6 ; R139.2@984.19,2025.38 987.46,2028.65 987.46,2029.43 1002.95,2029.43 1007.55,2034.02 v1(1010.17,2034.02) ; J1.6@1011.65,82.68 R21.1@1011.65,166.97 ; R21.1@1012.19,164.63 R20.2@1012.19,217.24 ; C41.1@1480.33,550.58 1487.14,543.77 1507.34,543.77 1515.91,535.2 v1(1518.53,535.2) 1518.53,532.58 1527.61,523.51 1527.61,501.73 U3.17@1527.69,501.66 ; R155.2@1543.62,2031.14 v1(1570.98,2031.14) ; R187.2@2064,1645.03 2064,1664.7 2069.96,1670.66 v1(2099.99,1670.66) ; v1@2084.14,1793.67 v1@2085.12,1792.69 ; R171.2@2085.17,2263.73 2087.93,2266.5 2108.71,2266.5 2118.17,2275.96 v1(2119.41,2275.96) ; v1(2382.77,1054.4) 2416.42,1054.4 R214.2@2416.96,1053.86 ; R204.2@2576.81,1549.93 2576.81,1523.27 v1(2598.24,1501.84) ; R203.2@2586.9,1977.75 2586.9,1978.54 2590.17,1981.8 2607.56,1981.8 2609.73,1983.98 v1(2612.35,1983.98)
  L08-BOTTOM w5: v1(987.09,1556.5) 1007.22,1576.63 1007.22,1628.35 R140.2@1011.19,1632.31 ; R69.2@1542.56,299.19 1543.87,297.88 v1(1543.87,256.87)
  L08-BOTTOM w6: U16.3@871.84,359.44 871.84,384.77 881.47,394.4 881.47,412.51 C203.2@884.76,415.8 890.51,421.54 v1(917.16,421.54) ; v1(1534.24,1546.19) 1534.24,1547.36 1564.82,1577.94 R156.2@1564.82,1613.82 ; v1(2099.99,1670.66) 2152.6,1670.66 2201.54,1621.72 R126.1@2201.54,1588.19
  L08-BOTTOM w8: v1(341.58,810.87) 342.32,811.61 371.63,811.61 L10.2@372.37,812.35 ; R82.2@518.55,1343.49 518.55,1294.22 521.28,1291.49 v1(521.28,1288.32) ; v1(627.88,1184.57) 628.04,1184.41 628.04,1153.69 L9.2@628.2,1153.53 ; R76.1@656.1,1329.26 689.24,1329.26 706.82,1311.68 v1(706.82,1257.22) 707.89,1257.22 722.8,1242.31 R33.2@749.18,1242.31 ; L4.1@681.25,1382.77 687.24,1388.75 687.24,1401.89 696.3,1410.95 v1(696.3,1414.11) ; v1(727.37,874.82) v1@728.37,875.82 ; C84.1@881.51,699.95 C84.1@883.23,698.23 ; L7.1@944.21,699.95 L7.1@945.94,698.23 ; R94.1@1187.98,244.42 1187.98,294.19 R93.1@1188.23,294.44 ; R93.1@1188.72,294.19 R92.1@1188.72,348.42 1188.72,387.04 v1(1210.61,408.93) ; R89.2@1416.36,168.04 1434.33,168.04 v1(1448.36,154) ; C21.1@1686.1,662.99 1688.43,662.99 1729.33,662.99 v1(1729.42,663.08) ; U2.5@1706.39,709.73 1739.4,709.73 1745.25,715.57 R6.1@1745.25,715.63
  L08-BOTTOM w10: v1(172.72,1531.92) 172.87,1532.06 207.27,1532.06 C120.2@207.42,1532.21 ; J4.7@185.49,1699.46 210.98,1699.46 222.14,1688.3 222.14,1571.53 207.52,1556.91 C120.2@207.52,1532.21 ; v1(729.61,1558.12) 731.46,1556.27 731.46,1542.09 737.32,1536.23 759.12,1536.23 C135.2@765.56,1529.79 ; J5.7@741.4,1698 766.31,1698 775.81,1688.5 775.81,1536.61 C135.2@768.99,1529.79 ; J1.6@1012.14,83.16 R23.1@1012.14,138.02 R22.1@1012.14,187.65 ; C81.1@1237.64,766.6 1243.8,760.43 v1(1243.8,733.72) ; J6.7@1302.44,1699.57 1304.33,1697.69 1325.7,1697.69 1336.58,1686.81 1336.58,1568.01 1325.32,1556.75 C150.2@1325.32,1532.68 1323.98,1531.33 v1(1323.98,1503.95) ; R13.2@1630.21,332.28 L1.2@1681.64,332.28 ; v1(1800.29,1155.69) 1801.85,1154.12 1827.11,1154.12 1830.06,1157.07 C180.2@1834.56,1152.56 1838.5,1152.56 1845.31,1159.37 1845.31,1163.3 1845.46,1163.45 1845.46,1303.37 1829.15,1319.68 1813.01,1319.68 J8.7@1811.42,1321.26 ; J7.7@1838.64,1937.16 1860.64,1937.16 1871.55,1926.25 1871.55,1781.68 1871.39,1781.52 1871.39,1777.58 1864.58,1770.77 C165.2@1861.85,1770.77 ; C165.2@1860.64,1770.77 C165.2@1861.85,1770.77 ; v1(1884.56,1737.05) 1868.66,1752.95 1868.66,1763.96 C165.2@1861.85,1770.77 ; v1(2330.26,1478.61) 2330.97,1479.33 2364.04,1479.33 C195.2@2364.75,1480.04 2368.69,1480.04 2375.5,1486.85 2375.5,1492.65 2375.55,1492.71 2375.55,1638.35 2367.23,1646.67 J9.7@2342.03,1646.67
  L08-BOTTOM w15: L6.1@1231.13,833.15 1223.91,825.93 1223.91,786.35 1225.22,785.04 1225.22,777.57 1236.42,766.36 C81.1@1237.4,766.36 ; U5.2@1656.68,925.88 U5.1@1656.68,900.29 1656.69,866.51 1677.56,845.64 C43.1@1721.56,845.64 1724.39,845.64 1728.7,841.32 1728.7,811.77 v1(1729.6,810.87) ; C21.1@1688.43,662.99 1692.74,667.3 1692.74,685.72 1698.93,691.91 1698.93,709.35 1699.31,709.73 U2.5@1706.39,709.73
  other v1: 897.94,665.97 923.48,665.97 950.6,666.45
  other v5: 1668.29,278.15 1693.39,303.25 1667.3,304.97 1639.87,305.58
  other v7: 1640.33,278.92
3V3_VDDO: C69.1 C70.1 L4.2 U6.10 U6.13 | length 254.1
  L01-TOP w6: C69.1@548.55,1353.42 572.07,1353.42 U6.13@574.04,1351.44
  L01-TOP w8: U6.10@633.1,1371.13 634.51,1372.54 634.51,1393.19 C70.1@637.06,1395.74
  L01-TOP w10: v1(546.37,1382.07) 546.47,1381.97 546.47,1355.49 C69.1@548.55,1353.42 ; v1(636.72,1418.32) 636.89,1418.14 636.89,1395.92 C70.1@637.06,1395.74
  L08-BOTTOM w10: v1(546.37,1382.07) 546.37,1401 563.69,1418.32 v1(636.72,1418.32) L4.2@636.72,1385.48
5V: C22.1 C23.1 C24.1 C28.1 C29.1 C35.1 C36.1 R8.1 R11.1 R15.2 R223.2 U3.8 U3.15 U3.21 | length 1792.2
  L01-TOP w8: C36.1@1431.03,437.87 1434.83,434.07 1492.58,434.07 1495.21,436.69 U3.21@1502.1,436.69 ; C28.1@1510.43,610.09 1522.18,598.34 1522.18,579.53 1524.81,576.91 C29.1@1566.06,576.91 ; U3.15@1567.19,501.79 1567.19,575.78 C29.1@1566.06,576.91 ; U3.8@1632.02,417.01 1632.29,416.74 1648.3,416.74 1654.59,410.44 1694,410.44 C24.1@1701.81,418.25 ; R15.2@1715.91,526.26 1732.82,526.26 1743.5,536.94 1743.5,564.01 1718.93,588.58 v1(1682.11,588.58) 1573.88,588.58 1566.06,580.77 C29.1@1566.06,576.91 ; R8.1@1930.21,385 1930.21,421.54 R11.1@1934.34,425.67
  L01-TOP w15: v1(1332.41,435.88) 1332.58,435.7 1364.81,435.7 1365.8,436.7 1429.86,436.7 C36.1@1431.03,437.87 ; C24.1@1701.81,419.09 1702.43,418.47 C23.1@1759.35,418.47 ; C23.1@1759.35,415.72 1763.34,419.71 1765.1,417.96 1802.06,417.96 v5@1803.82,419.71
  L05-PWR w10: v1(1270.17,552.5) 1329.85,552.5 1362.39,519.96 1362.39,492.15 1333.83,463.59 1333.83,437.31 v1(1332.41,435.88) 1366.99,435.88 1420.97,489.86 1420.97,533.83 1475.72,588.58 v1(1682.11,588.58) 1718.93,588.58 1743.5,564.01 1743.5,441.91 1767.34,418.07 1803.33,418.07 v5(1804.4,419.14)
  L08-BOTTOM w10: v1(1270.17,552.5) 1272.79,552.5 1278.12,547.17 1294.34,547.17 R223.2@1299.19,542.33
  L08-BOTTOM w15: C22.1@1758.7,417.01 1759.77,418.07 1803.33,418.07 v5(1804.4,419.14)
  other v5: 1886.63,389.74 1857.18,390.6 1857.4,419.4 1886.63,419.18
  other v7: 1829.45,389.7 1829.45,418.97
5V_SYS: C2.1 C3.1 C14.2 C15.1 R3.2 R11.2 TP1.1 U1.7 U1.8 U1.9 U1.10 U1.12 U1.13 U1.14 U1.15 U1.22 U1.30 | length 962.4
  L01-TOP w10: v7(1957.68,950.48) 1960.93,950.48 1966.58,956.14 C15.1@1991.99,956.14 ; R3.2@1991.73,922.09 C15.1@1991.73,950.48 ; U1.22@2110.25,830.3 2112.14,832.19 2112.14,855.82 2119.41,863.09 2186.1,863.09 C14.2@2190.41,867.41 2190.14,867.13 2190.14,832.89 v7(2189.86,832.61)
  L08-BOTTOM w10: v7(1957.68,950.48) 1955.38,948.18 1941.71,948.18 1928.92,935.4 1928.92,864.79 1988.93,804.79 v1(1988.93,544.05) ; v1(2159.24,543.58) 2159.24,801.99 v7(2189.86,832.61)
  other v1: 2137.41,494.09 2159.79,494.29 1989.48,494.76 2011.85,494.95 1988.93,520.23 2011.3,520.42 2136.86,519.56 2159.24,519.76 2136.86,543.38 2011.3,544.24
  other v3: 2070.88,642.31
24V: C4.2 C5.2 C6.2 C7.2 C8.2 C9.2 C10.2 C11.2 C12.2 C13.2 C16.2 C17.2 C18.2 C19.2 C20.2 C112.1 C113.1 C114.1 C115.1 C127.1 C128.1 C129.1 C130.1 C142.1 C143.1 C144.1 C145.1 C157.1 C158.1 C159.1 C160.1 C172.1 C173.1 C174.1 C175.1 C187.1 C188.1 C189.1 C190.1 D1.2 DC+.1 R1.2 R210.2 U1.3 U1.4 U1.18 U1.19 U10.2 U11.2 U12.2 U13.2 U14.2 U15.2 | length 1573
  L01-TOP w5: C12.2@2256.68,749.77 R210.2@2324.18,749.77
  L01-TOP w10: 241.07,1903.25 244.46,1903.25 264.14,1883.56 U10.2@294.12,1883.56 ; 832.49,1880.22 U11.2@845.93,1880.22 ; 1347.95,1903.08 1370.36,1880.68 U12.2@1404.31,1880.68 ; 1873.79,1521.11 1892.3,1502.6 U14.2@1923.96,1502.6 ; 1901.23,2143.53 1922.48,2122.28 1947.3,2122.28 U13.2@1947.38,2122.2 ; 2404.81,1852.93 2427.42,1830.32 U15.2@2450.65,1830.32
  L01-TOP w15: v1(133.14,1971.72) C115.1@173.7,1971.72 172.42,1970.44 172.42,1908.47 C114.1@171.14,1907.19 175.08,1903.25 241.07,1903.25 ; C130.1@723.34,1957.14 722.57,1956.37 722.57,1904.47 721.87,1903.77 773.44,1903.77 C128.1@773.51,1903.84 789.14,1903.84 812.77,1880.22 832.49,1880.22 ; v1(1248.8,1957.13) C145.1@1287.07,1957.13 1285.59,1955.64 1285.59,1904.31 C143.1@1284.24,1902.95 ; C143.1@1284.11,1902.82 C143.1@1284.24,1902.95 ; 1347.95,1903.08 C144.1@1333.69,1903.08 1333.56,1902.95 C143.1@1284.24,1902.95 ; v1(1762.67,1579.69) 1763.94,1579.69 1765.01,1580.75 1802.78,1580.75 C175.1@1804.84,1578.69 1802.22,1576.08 C174.1@1802.22,1524.14 ; v1(1788.51,2197.67) 1788.78,2197.94 C160.1@1828.06,2197.94 ; C174.1@1802.73,1523.63 C173.1@1852.79,1523.61 ; C159.1@1826.68,2143.2 C159.1@1826.85,2143.37 ; C160.1@1828.33,2198.21 C160.1@1828.06,2197.94 ; C173.1@1852.79,1523.61 1855.29,1521.11 1873.79,1521.11 ; 1901.23,2143.53 C158.1@1876.15,2143.53 1875.98,2143.37 C159.1@1826.85,2143.37 ; v1(2293.04,1906.17) 2293.28,1905.93 C190.1@2320.77,1905.93 ; C188.1@2329.96,1851.59 C188.1@2330.18,1851.81 ; C190.1@2330.68,1905.66 2330.32,1905.3 2330.32,1851.95 C188.1@2330.18,1851.81 ; C189.1@2380.09,1852.03 2379.87,1851.81 C188.1@2330.18,1851.81 ; C189.1@2380.98,1852.93 2404.81,1852.93 ; C159.1@1826.85,2143.37 1827.51,2144.02 1827.51,2197.39 C160.1@1828.06,2197.94
  L08-BOTTOM w15: v1(144.4,2023.23) 145.66,2023.23 148.54,2026.11 C112.1@202.98,2026.11 ; v1(706.37,2001.76) 707.64,2001.76 715.1,2009.23 754.48,2009.23 C127.1@768.63,2023.38 ; v1@1274.06,2007.71 v1(1273.68,2007.33) 1274.95,2007.33 1281.08,2013.47 1308.76,2013.47 C142.1@1322.91,2027.62 ; v1(1813.39,2247.88) v1@1814.29,2246.98
  other v1: 1762.57,1604.28 1796.17,1614.1 1762.67,1630.08 1795.53,1637.75 1795.53,1663.3 2293.04,1938.32 2323.87,1938.1 682.19,1956.37 2323.87,1971.37 681.83,1979.37 1248.69,1981.71 133.04,1996.3 681.37,2001.61 2323.24,2001.76 1248.8,2007.52 2356.54,2015.11 2386.89,2015.11 114.88,2023.23 704.35,2033.42 1272.03,2038.09 737.23,2064.46 182.92,2064.75 211.57,2064.75 769.95,2064.75 1304.05,2065.12 1333.74,2065.12 696.3,2207.78 741.17,2207.78 1788.4,2222.26 1812.76,2222.26 1788.51,2248.07 1812.12,2275.96 1020.96,2354.67 1060,2354.67 1099.55,2354.87 1150.96,2354.67 1190,2354.67 1229.55,2354.87 1280.96,2354.67 1320,2354.67 1359.55,2354.87 1410.96,2354.87 1450,2354.87 1489.55,2355.06 1540.96,2354.67 1580,2354.67 1619.55,2354.87 693.2,2356.28 741.17,2356.28
  other v5: 1908.2,769.49 2239.27,784.96 2265.59,784.96
  other v6: 883.92,2207.78 822.12,2243.46 945.72,2243.46 822.12,2314.82 945.72,2314.82 883.92,2350.5
  other v7: 2209.49,774.19 1879.18,781.38 1846.98,782.1
ADC_VREF: R43.2 R46.2 R124.1 R142.1 R158.1 R174.1 R190.1 R206.1 U5.5 U5.6 | length 5459.6
  L01-TOP w6: R46.2@1854.15,989.86 1855.44,991.14 v3(1892.66,991.14)
  L03-SIG w6: v1(2119.18,2308.47) 2143.71,2333 2244,2333 2516.03,2060.97 v1(2516.03,2030.53)
  L06-SIG w6: v1(359.37,2063.78) 396.04,2100.45 870.34,2100.45 v1(910.51,2060.29) 950.68,2100.45 1441.39,2100.45 v1(1469.13,2072.71) ; v1@1469.13,2072.79 1496.8,2100.45 1636.84,2100.45 1706.44,2170.06 1848.36,2170.06 1867.38,2189.07 1867.38,2286.79 1899.9,2319.32 2108.34,2319.32 v1(2119.18,2308.47)
  L08-BOTTOM w6: v1(359.37,2063.78) 363.07,2063.78 370.06,2056.79 R124.1@395.08,2056.79 ; v1(910.51,2060.29) R142.1@946.86,2060.29 ; v1(1469.13,2072.71) 1505.23,2072.71 R158.1@1507.71,2075.18 ; v3(1892.66,991.14) 2050.96,991.14 2182.03,1122.22 2182.03,1262.87 2242.33,1323.18 ; R190.1@2022.56,1684.05 2022.56,1715.38 2037.1,1729.93 2137.12,1729.93 2159.47,1707.57 2242.33,1624.72 2242.33,1323.18 ; R174.1@2047.42,2295.36 2056.24,2304.17 2056.24,2313.08 2059.75,2316.59 2107.36,2316.59 2115.48,2308.47 v1(2119.18,2308.47) ; v1(2516.03,2030.53) 2543.17,2030.53 2546.07,2027.63 R206.1@2546.07,2018.3 ; R206.1@2551.98,2024.12 2551.98,2049.64 2565.02,2062.69 2644.08,2062.69 2669.29,2037.48 2669.29,1912.79 2635.9,1879.4 2635.9,1656.38 2713,1579.28 2713,1497.68 2538.49,1323.18 2242.33,1323.18
  L08-BOTTOM w10: U5.5@1831.88,977.07 1832.74,977.07 1836.3,980.63 1836.3,1029.69 R43.2@1846.01,1039.4 1882.95,1039.4 1892.66,1029.69 v3(1892.66,991.14)
  L08-BOTTOM w15: U5.6@1831.88,951.48 U5.5@1831.88,977.07
AGND: NT1.2 R4.1 R5.1 U1.24 U1.27 | length 373.3
  L01-TOP w6: NT1.2@2070.88,776.09 v3(2070.88,793.88)
  L01-TOP w10: v5(1952.14,919.21) 1952.14,915.96 1958.63,909.47 1958.63,889.94 1959.73,888.84 R5.1@1959.73,885.09 ; v3(2070.88,793.88) U1.24@2070.88,830.3 R4.1@2070.88,896.09
  L08-BOTTOM w10: v5(1952.14,919.21) 2023.09,919.21 2070.88,871.42 v3(2070.88,793.88)
BOOTPIN1: J2.1 R66.2 U4.A11 | length 617.2
  L01-TOP w5: v2(877.31,1168.68) 877.65,1168.35 893.21,1168.35 U4.A11@893.54,1168.01
  L01-TOP w10: R66.2@360.01,1201.53 360.01,1205.73 368.77,1214.49 390.72,1214.49 404.29,1228.06 J2.1@451.14,1228.06
  L08-BOTTOM w5: J2.1@451.14,1228.06 451.14,1254.64 459.84,1263.34 547.45,1263.34 594.01,1216.79 738.37,1216.79 787.14,1168.01 876.64,1168.01 v2(877.31,1168.68)
CAN_TX: R42.2 TP23.1 U16.1 | length 3755.9
  L01-TOP w4: v1(792.56,394.99) 793.07,394.49 845.74,394.49 TP23.1@846.25,393.98 ; R42.2@1251.09,1271.96 v2(1251.09,1293.96)
  L03-SIG w3.7: v1(792.56,394.99) 828.67,394.99 835.84,402.16 835.84,426.45 809.37,452.91 809.37,749.65 772.4,786.61 513.11,786.61 415.68,884.05 415.68,1115.33 373.83,1157.17 373.83,1328.94 279.22,1423.55 279.22,1854.85 242.56,1891.52 242.56,2054.2 281.23,2092.87 487.66,2092.87 553.92,2026.61 553.92,1915.6 617.65,1851.87 617.65,1740.31 751.14,1606.83 1008.76,1606.83 1217.25,1398.34 1217.25,1378.65 1251.09,1344.8 v2(1251.09,1293.96)
  L08-BOTTOM w4: v1(792.56,394.99) 808.8,394.99 814.04,389.75 814.04,366.05 U16.1@820.66,359.44
CANA_RX: R217.1 U4.N11 | length 4034.1
  L01-TOP w3.7: U4.N11@1200.63,1168.01 1202.83,1168.01 1206.88,1172.07 1210.07,1172.07 1270.35,1232.34 v2(1270.35,1294.26)
  L03-SIG w3.7: v1(964.67,389.34) 933.74,358.41 793.49,358.41 769.21,382.69 769.21,418.51 801.67,450.96 801.67,746.46 769.21,778.91 509.92,778.91 362.79,926.05 362.79,1329.09 271.52,1420.36 271.52,1851.66 234.86,1888.33 234.86,2057.39 278.04,2100.57 493.76,2100.57 562.36,2031.97 562.36,1919.85 625.35,1856.86 625.35,1743.5 754.33,1614.53 1011.95,1614.53 1225.97,1400.51 1225.97,1381.82 1270.35,1337.45 v2(1270.35,1294.26)
  L08-BOTTOM w3.7: R217.1@938.15,388.21 963.54,388.21 v1(964.67,389.34)
CANA_TX: R42.1 U4.M11 | length 121.2
  L01-TOP w3.7: U4.M11@1175.04,1168.01 1186.8,1179.77 1206.88,1179.77 1251.09,1223.98 R42.1@1251.09,1245.98
Current_A1: C50.1 R48.2 U4.L3 | length 183.1
  L01-TOP w4: U4.L3@1149.45,963.23 U4.L3@1149.45,963.29 v2(1162.25,950.49)
  L08-BOTTOM w4: v2(1162.25,950.49) 1248.85,950.49 1274.71,924.63 C50.1@1291.34,924.63 1292.47,923.49 1292.47,901.13 R48.2@1291.67,900.32
Current_A2: C51.1 R51.2 U4.K3 | length 239.1
  L01-TOP w4: U4.K3@1123.86,963.29 U4.K3@1123.86,963.29 1136.6,950.61 v2(1136.65,950.61)
  L08-BOTTOM w4: v2(1136.65,950.61) 1149.93,937.33 1234.8,937.33 1269.72,902.41 1269.72,885.09 1279.7,875.1 C51.1@1292.56,875.1 ; C51.1@1292.42,875.41 1296,871.83 1296,858.04 1299.2,854.84 R51.2@1299.54,854.84
Current_A3: C52.1 R54.2 U4.J3 | length 231.9
  L01-TOP w4: U4.J3@1098.27,963.29 U4.J3@1098.27,963.29 1110.89,950.74 v2(1110.97,950.74)
  L08-BOTTOM w4: v2(1110.97,950.74) 1110.97,951.17 1121.47,961.68 1129.76,961.68 1131.39,963.31 1167.39,963.31 1169.02,961.68 1263.04,961.68 1273.26,971.9 C52.1@1291.31,971.9 ; R54.2@1291.56,948.4 C52.1@1291.56,971.65
Current_A4: C53.1 R57.2 U4.H3 | length 287.4
  L01-TOP w4: U4.H3@1072.68,963.29 1086.36,949.6 1086.36,897.4 1123.99,859.78 1123.99,777.54 1148.12,753.41 C53.1@1169.28,753.41 1172.52,756.65 R57.2@1193.09,756.65
Current_A5: C54.1 R60.2 U4.H2 | length 200.2
  L01-TOP w4: R60.2@1040.48,769.62 1046.75,763.36 R60.2@1047.19,763.36 ; R60.2@1046.9,769.62 1046.75,769.62 1040.48,775.89 1040.48,825.06 1042.82,827.4 1051.29,827.4 1057.56,833.67 C54.1@1057.56,834.45 1062.25,839.15 1062.25,888.95 1060.07,891.13 1060.07,925.09 U4.H2@1072.68,937.7
Current_A6: C55.1 R63.2 U4.H1 | length 107.1
  L01-TOP w4: U4.H1@1072.68,912.11 1072.68,888.95 1082.65,878.99 C55.1@1082.65,834.67 ; C55.1@1081.33,834.23 R63.2@1106.82,834.23
Current_B1: C56.1 R49.2 U4.N2 | length 187.6
  L01-TOP w4: U4.N2@1200.63,937.7 1224.84,937.7 1234.63,927.9 1234.63,874.98 1258.51,851.1 C56.1@1296.53,851.1 ; C56.1@1297.34,854.02 1297.34,851.92 1298.16,851.1 R49.2@1298.16,829.53
Current_B2: C57.1 R52.2 U4.J4 | length 359.3
  L01-TOP w4: U4.J4@1098.27,988.88 1098.41,988.88 1110.73,976.56 v2(1110.87,976.56) ; v2(1268.41,820.3) 1268.61,820.1 1268.61,807.7 1270.95,805.36 1285.73,805.36 C57.1@1285.81,805.45 ; R52.2@1285.81,781.33 R52.2@1285.76,781.75 C57.1@1285.81,805.45 ; C57.1@1286.01,805.65 C57.1@1285.81,805.45
  L03-SIG w4: v2(1110.87,976.56) 1109.99,976.56 1098.27,964.84 1098.27,898.59 1176.26,820.6 1268.11,820.6 v2(1268.41,820.3)
Current_B3: C58.1 R55.2 U4.M3 | length 162.2
  L01-TOP w4: U4.M3@1175.04,963.29 1186.95,951.38 1238.07,951.38 1249.88,939.58 1249.88,907.71 1256.43,901.15 C58.1@1269.37,901.15 ; R55.2@1269.74,877.49 C58.1@1269.74,900.95
Current_B4: C59.1 R58.2 U4.L4 | length 185.1
  L01-TOP w4: U4.L4@1149.45,988.88 v2(1162.12,976.18)
  L08-BOTTOM w4: v2(1162.12,976.18) 1162.37,976.43 1217.24,976.43 1236.49,995.68 1292.76,995.68 1297.21,995.68 1299.12,997.58 R58.2@1299.12,1018.91
Current_B5: C60.1 R61.2 U4.M6 | length 169.1
  L01-TOP w4: U4.M6@1175.04,1040.06 1187.34,1052.36 1223.21,1052.36 1274.85,1104 1284.67,1104 C60.1@1290.94,1110.26 1292.18,1111.51 R61.2@1292.18,1133.92
Current_B6: C61.1 R64.2 U4.N6 | length 121.3
  L01-TOP w4: U4.N6@1200.63,1040.06 1239.9,1040.06 1252.75,1052.91 1284,1052.91 C61.1@1290.14,1059.05 1290.14,1082.8 R64.2@1290.28,1082.94
Current_C1: C62.1 R50.2 U4.F1 | length 164.3
  L01-TOP w4: R50.2@898.1,834.76 923.63,834.76 930.7,841.83 930.7,847.13 949.02,865.45 984.6,865.45 1021.5,902.34 U4.F1@1021.5,912.11
Current_C2: C63.1 R53.2 U4.G1 | length 136.6
  L01-TOP w4: R53.2@1007.83,832.52 R53.2@1008.39,831.95 985.25,831.95 C63.1@984.68,832.52 990.95,838.78 990.95,844.18 997.59,850.82 1008.39,850.82 1047.15,889.59 1047.15,896.72 1047.09,896.79 U4.G1@1047.09,912.11
Current_C3: C64.1 R56.2 U4.H4 | length 285.8
  L01-TOP w4: U4.H4@1072.68,988.88 1072.81,988.88 1085.47,976.22 v2(1085.61,976.22)
  L08-BOTTOM w4: v2(1085.61,976.22) 1085.61,976.49 1098.52,989.4 1123.41,989.4 1123.93,988.88 1218.37,988.88 1239.33,1009.84 1272.35,1009.84 1279.56,1017.05 1279.56,1026.41 1289.69,1036.54 1291.42,1036.54 1295.6,1040.72 C64.1@1295.6,1042.45 ; R56.2@1298.09,1065.73 1298.09,1043.2 C64.1@1298.48,1042.81
Current_C4: C65.1 R59.2 U4.H5 | length 342.4
  L01-TOP w4: C65.1@1027.07,738.54 1027.07,822.96 1033.1,828.99 1033.1,851.95 1041.77,860.62 v2(1041.77,861.66) ; C65.1@1027.17,738.44 1052.32,738.44 R59.2@1052.63,738.13 ; U4.H5@1072.68,1014.47 1072.68,1014.33 1084.92,1002.09 v2(1084.92,1001.95)
  L08-BOTTOM w4: v2(1041.77,861.66) 1042.31,862.2 1042.31,978.42 1052.57,988.68 1072.75,988.68 1084.92,1000.85 v2(1084.92,1001.95)
Current_C5: C66.1 R62.2 U4.H6 | length 349.9
  L01-TOP w4: U4.H6@1072.68,1040.06 1072.68,1039.92 1084.92,1027.68 v2(1084.92,1027.54)
  L08-BOTTOM w4: v2(1084.92,1027.54) 1086.78,1029.39 1184.37,1029.39 1198.72,1043.73 1222.9,1043.73 1230.59,1051.43 1230.59,1123.34 1250.93,1143.69 1271.34,1143.69 1282.64,1132.39 C66.1@1296.59,1132.39 1296.59,1157.98 R62.2@1296.52,1158.06
Current_C6: C67.1 R65.2 U4.G6 | length 383.3
  L01-TOP w4: U4.G6@1047.09,1040.06 v2(1059.9,1027.24)
  L08-BOTTOM w4: v2(1059.9,1027.24) 1060.12,1027.24 1073.12,1040.24 1120.16,1040.24 1120.47,1039.92 1183.51,1039.92 1195.95,1052.36 1216.07,1052.36 1222.59,1058.87 1222.59,1126.66 1275.18,1179.25 1291.7,1179.25 C67.1@1296.95,1184.5 1296.95,1207.17 R65.2@1296.75,1207.37
DAC_OUT: R77.2 TP12.1 | length 66.6
  L01-TOP w4: R77.2@1316.77,947.61 1319.69,944.69 TP12.1@1382.2,944.69
DACC_OUT: C94.1 R77.1 U4.N3 | length 135.6
  L01-TOP w4: U4.N3@1200.63,963.29 1248.55,963.29 1261.78,950.06 1261.78,937.56 1273.69,925.65 C94.1@1291.22,925.65 1291.22,947.18 R77.1@1290.79,947.61
DRV_FLT_AX1: R122.1 U4.G12 U10.12 | length 1541.7
  L01-TOP w4: v9(1017.96,1262.9) 1034.16,1246.7 1034.16,1206.53 U4.G12@1047.09,1193.6
  L01-TOP w5: U10.12@418.14,1712.3 420.45,1709.99 420.45,1589.28 429.63,1580.1 v1(429.63,1560.72) 429.63,1535.32 R122.1@429.78,1535.17
  L06-SIG w4: v1(429.63,1560.72) 429.63,1623.92 448.3,1642.59 521.28,1642.59 569.81,1594.06 733.59,1594.06 852.9,1713.37 1041.85,1713.37 1063.33,1691.89 1063.33,1587.94 962.37,1486.98 962.37,1395.02 1019.82,1337.58 1019.82,1264.75 v9(1017.96,1262.9)
DRV_FLT_AX2: R140.1 U4.G11 U11.12 | length 847.6
  L01-TOP w4: v2(1034.02,1180.81) 1034.16,1180.81 1046.95,1168.01 U4.G11@1047.09,1168.01
  L01-TOP w5: U11.12@969.95,1708.96 969.95,1685.68 v3@976.09,1679.54
  L03-SIG w4: v1(886.03,1431.9) 931.01,1431.9 1050.5,1312.4 1050.5,1197.29 v2(1034.02,1180.81)
  L08-BOTTOM w4: v1(886.03,1431.9) 984.13,1431.9 1059.09,1506.86 1059.09,1644.61 1044.11,1659.59 R140.1@1011.5,1659.59
  L08-BOTTOM w5: v3(976.09,1675.57) 1007.81,1675.57 1011.5,1671.88 R140.1@1011.5,1659.59
DRV_FLT_AX3: R156.1 U4.G10 U12.12 | length 1304.5
  L01-TOP w4: v1@910.29,1452.11 910.56,1451.83 991.52,1451.83 1037.78,1498.1 1287.33,1498.1 1310.4,1475.03 1380.83,1475.03 1386.97,1481.16 v3(1391.02,1481.16) ; v2(1034.02,1155.22) 1034.16,1155.22 1046.95,1142.42 U4.G10@1047.09,1142.42
  L01-TOP w5: U12.12@1528.32,1709.42 1529.46,1708.28 1529.46,1694.36 1535.19,1688.63 v1(1535.19,1670.56)
  L03-SIG w4: v1(910.01,1451.83) 911.03,1450.82 923.4,1450.82 1058.5,1315.72 1058.5,1179.7 v2(1034.02,1155.22) ; v3(1391.02,1481.16) 1391.02,1565.09 1430.71,1604.79 1518.08,1604.79 1534.97,1621.67 v1@1534.97,1670.33
  L08-BOTTOM w5: v1(1535.19,1670.56) 1557.91,1670.56 1565.38,1663.1 1565.38,1640.36 R156.1@1564.82,1639.81
DRV_FLT_AX4: R172.1 U4.B13 U13.12 | length 1963
  L01-TOP w3.8: U4.B13@919.13,1219.2 919.13,1319.49 921.27,1321.63
  L01-TOP w4: 921.27,1321.63 1052.9,1453.26 1269.26,1453.26 1306.32,1416.21 1664.99,1416.21 v1(1682.07,1399.13)
  L01-TOP w5: R172.1@2070.56,1863.8 2070.56,1904.44 2076.47,1910.35 2076.47,1918.3 2071.39,1923.38 U13.12@2071.39,1950.94 U13.12@2073.14,1949.2
  L06-SIG w4: v1(1682.07,1399.13) 1682.07,1401.67 1692,1411.6 1692,1617.91 1776.5,1702.41 1937.66,1702.41 1959.02,1723.77 2107.63,1723.77 2134,1750.14 2134,1891.06 2110.74,1914.33 v1(2076.47,1914.33)
DRV_FLT_AX5: R188.1 U4.B11 U14.12 | length 1833.6
  L01-TOP w4: U4.B11@919.13,1168.01 905.45,1181.7 885.34,1181.7 868,1199.04 868,1305.97 1044.33,1482.3 1280.79,1482.3 1315.48,1447.6 1642.37,1447.6 v1(1654.98,1460.21)
  L01-TOP w5: U14.12@2047.98,1331.34 2050.16,1329.16 2050.16,1306.6 2056.74,1300.02 v1(2056.74,1296.04) 2057.21,1295.57 2057.21,1280.03 2050.46,1273.28 2050.46,1249.74 R188.1@2049.39,1248.67
  L06-SIG w4: v1(1654.98,1460.21) 1632.87,1460.21 1593.35,1420.69 1593.35,1328.91 1607.63,1314.63 1720.07,1314.63 1757.14,1277.55 1930.39,1277.55 1952.12,1255.82 2039.16,1255.82 2056.74,1273.4 v1(2056.74,1296.04)
DRV_FLT_AX6: R204.1 U4.G2 U15.12 | length 2667.3
  L01-TOP w4: v2(959.42,825.73) 959.42,848.52 967.78,856.88 990.03,856.88 1035.18,902.03 1035.18,925.79 U4.G2@1047.09,937.7 ; U15.12@2574.67,1659.06 2576.95,1656.79 2576.95,1626.78 v3(2579.22,1624.5) 2579.22,1578.32 R204.1@2576.81,1575.91
  L03-SIG w4: v2(959.42,825.73) 985.6,825.73 1032.58,778.75 1032.58,734.32 1188.11,578.79 1585.76,578.79 ; 1586.05,579.08 1585.76,578.79 ; v3(2579.22,1624.5) 2579.22,1603.23 2473.26,1497.26 2473.26,1426.44 2308.37,1261.55 2224.47,1261.55 2199.33,1236.42 2199.33,1158.51 2061.38,1020.55 1790.78,1020.55 1691.82,921.59 1691.82,684.85 1585.76,578.79
DRV_nSleep: R113.1 R131.1 R147.1 R163.1 R179.1 R195.1 U4.C10 | length 4358.6
  L01-TOP w4: R113.1@454.33,1611 454.33,1589.25 462.19,1581.39 v1(462.19,1577.18) ; U4.C10@944.73,1142.42 U4.C10@944.73,1142.56 ; v1(1034.77,1617.42) 1030.52,1617.42 1023.06,1609.96 1006.37,1609.96 R131.1@1004.87,1608.46 972.39,1608.46 940.33,1576.41 940.33,1545.35 953.2,1532.48 1007.52,1532.48 1017.21,1542.18 1272.36,1542.18 1310.03,1579.85 1412.46,1579.85 1475.9,1516.4 1545.97,1516.4 v1(1566.48,1536.92) 1566.48,1593.84 R147.1@1565.38,1594.95 ; R179.1@2085.32,1225.69 2085.32,1203.9 v1(2099.46,1189.77) ; R163.1@2109.44,1843.51 2105.89,1839.97 v1(2105.89,1766.9) 2105.89,1744.01 2256.9,1593 2386.74,1593 2521.86,1457.88 v1(2546.82,1457.88) ; R195.1@2614.01,1550.03 2614.01,1526.94 2623.89,1517.06 v1(2623.89,1514.41)
  L01-TOP w5: v2(931.93,1155.31) 944.64,1142.56 U4.C10@944.73,1142.56
  L01-TOP w6: U4.C10@944.73,1142.42 U4.C10@944.73,1143
  L03-SIG w4: v1(2546.82,1457.88) 2564.65,1440.05 2608.12,1440.05 2623.89,1455.82 v1(2623.89,1514.41)
  L06-SIG w4: v3(818.74,1473.07) 789.14,1443.47 789.14,1354.48 859.23,1284.4 859.23,1228.01 v2(931.93,1155.31) ; v1(1566.48,1536.92) 1588.39,1536.92 1850.69,1799.22 1982.21,1799.22 2014.54,1766.9 v1(2105.89,1766.9) ; v1(2099.46,1189.77) 2141.37,1189.77 2241.1,1289.5 2241.1,1441.34 2337.12,1537.36 2600.93,1537.36 v1(2623.89,1514.41)
  L08-BOTTOM w4: v1(462.19,1577.18) 484.43,1577.18 568.65,1492.96 741.17,1492.96 761.06,1473.07 v3(818.74,1473.07) 850.63,1473.07 889.46,1511.9 982.87,1511.9 1034.82,1563.85 v1(1034.77,1617.42) v1(1034.77,1617.42)
DRV_OFF: J14.2 R112.1 R130.1 R146.1 R162.1 R178.1 R194.1 | length 5466.5
  L01-TOP w4: v1(958.49,1557.24) 977.24,1575.99 998.67,1575.99 1024.49,1550.18 1269.05,1550.18 1306.71,1587.85 1415.77,1587.85 1477.94,1525.68 1498.98,1525.68 1504.65,1531.35 v1(1504.65,1546.49) ; v1(2057.33,1792.82) 2057.59,1792.56 2057.59,1776.98 2253.06,1581.52 2253.06,1521.8 2283.04,1491.82 2283.04,1436.21 2307.21,1412.04 2555.88,1412.04 2579.18,1435.34 v1(2579.18,1474.31)
  L06-SIG w4: v1(1504.65,1546.49) 1504.65,1607.81 1527.73,1630.9 1670.58,1630.9 1859.93,1820.25 2029.9,1820.25 v1(2057.33,1792.82) ; v1(2036.04,1175) 2036.04,1159.83 2053.35,1142.52 2105.43,1142.52 2249.1,1286.18 2249.1,1438.03 2339.14,1528.07 2559.9,1528.07 2579.18,1508.79 v1(2579.18,1474.31)
  L08-BOTTOM w4: R112.1@416.47,1596.95 475.97,1596.95 570.89,1502.03 745.94,1502.03 750.92,1497.05 860.69,1497.05 885.44,1521.8 946.92,1521.8 957.58,1532.46 957.58,1556.33 v1(958.49,1557.24) ; 1557.01,1154.41 1641.09,1154.41 1686.78,1108.71 1992.2,1108.71 2036.04,1152.56 v1(2036.04,1175) 2036.04,1179.24 2041.37,1184.57 2041.37,1202.39 R178.1@2051.18,1212.2
  L08-BOTTOM w5: R112.1@416.47,1596.95 R112.1@417.06,1596.36 ; v1(958.49,1557.24) 961.3,1560.05 961.3,1565.77 968.96,1573.43 968.96,1589.58 R130.1@973.12,1593.75 ; J14.2@1014.58,468.46 1014.58,503.71 1051.88,541.01 1219.98,541.01 1383.99,705.02 1465.04,705.02 1533.74,773.72 1533.74,1131.13 1557.01,1154.41 ; v1(1504.65,1546.49) 1518.78,1560.62 1518.78,1579.99 R146.1@1528.1,1589.3 ; v1(2057.33,1792.82) 2057.33,1795.31 2065.11,1803.1 2065.11,1823.78 R162.1@2071.84,1830.51 ; R194.1@2575.69,1540.54 2579.18,1537.05 v1(2579.18,1474.31)
DRV_OFF_MCU: J14.3 U4.B10 | length 914.9
  L01-TOP w4: v2(906.34,1155.49) 906.34,1155.35 919.13,1142.56 U4.B10@919.13,1142.42
  L06-SIG w4: v2(796.94,1117.06) 796.94,1134.19 818.24,1155.49 v2(906.34,1155.49)
  L08-BOTTOM w4: v2(796.94,1117.06) 796.94,1025.81 796.96,930.71 769.37,903.12 769.37,643.52 873.52,539.37 873.52,524.95 928.78,469.69 963.36,469.69 J14.3@964.58,468.46
DRV_OFF_PMIC: J14.1 R221.2 | length 349.3
  L08-BOTTOM w5: J14.1@1064.58,468.46 1330.73,468.46 1354.95,492.68 1364.55,492.68 R221.2@1371.33,499.46 ; R221.2@1362.02,508.77 R221.2@1371.33,499.46 ; R221.2@1366.32,508.4 R221.2@1375.27,499.46 R221.2@1371.33,499.46
DRVOFF1: R112.2 U10.11 | length 77.3
  L01-TOP w5: U10.11@398.46,1712.3 398.76,1711.99 398.76,1683.31 v1(399.07,1683)
  L08-BOTTOM w5: v1(399.07,1683) 402.05,1683 416.47,1668.57 R112.2@416.47,1644.19
DRVOFF2: R130.2 U11.11 | length 77.4
  L01-TOP w5: v1(950.32,1681.71) U11.11@950.29,1708.93
  L08-BOTTOM w5: v1(950.32,1681.71) 953.13,1678.9 953.13,1669.2 963.81,1658.52 963.81,1650.3 R130.2@973.12,1640.99
DRVOFF3: R146.2 U12.11 | length 81.4
  L01-TOP w5: v1(1508.1,1679.85) 1508.37,1680.11 1508.37,1709.15 U12.11@1508.64,1709.42
  L08-BOTTOM w5: v1(1508.1,1679.85) 1510.9,1677.04 1510.9,1664.6 1519.45,1656.06 1519.45,1645.19 R146.2@1528.1,1636.54
DRVOFF4: R162.2 U13.11 | length 82.3
  L01-TOP w5: v1(2050.82,1921.91) 2051.26,1922.35 2051.26,1950.5 U13.11@2051.71,1950.94
  L08-BOTTOM w5: v1(2050.82,1921.91) 2051.33,1921.39 2051.33,1907.9 2062.53,1896.7 2062.53,1887.06 R162.2@2071.84,1877.75
DRVOFF5: R178.2 U14.11 | length 81.4
  L01-TOP w5: U14.11@2028.29,1331.34 2028.94,1330.69 2028.94,1301.92 v1(2029.59,1301.27)
  L08-BOTTOM w5: v1(2029.59,1301.27) 2030.95,1299.92 2030.95,1288.31 2041.87,1277.39 2041.87,1268.76 R178.2@2051.18,1259.45
DRVOFF6: R194.2 U15.11 | length 80.3
  L01-TOP w5: v1(2554.44,1632.48) 2554.71,1632.75 2554.71,1658.79 U15.11@2554.98,1659.06
  L08-BOTTOM w5: v1(2554.44,1632.48) 2555.49,1631.43 2555.49,1615.76 2567.88,1603.37 2567.88,1595.59 R194.2@2575.69,1587.78
EARTH: C107.2 C109.2 J3.5 J3.6 | length 874.3
  L01-TOP w15: v1(523.69,245.41) 495.89,245.41 483.71,257.6 J3.5@483.71,274.42 483.71,290.26 495.89,302.45 v1(525.09,302.45) ; v1(739,239) 764.83,239 777.01,251.19 J3.6@777.01,274.42
  L08-BOTTOM w15: C107.2@429.26,572.53 439.75,562.04 439.75,345.7 483.01,302.45 v1(525.09,302.45) ; v1(523.69,245.41) 524.39,246.11 524.39,301.75 v1(525.09,302.45) ; v1(739,239) v1(739,297.95) 713.9,323.05 C109.2@635.42,323.05 545.69,323.05 v1(525.09,302.45)
EEPROM_A0: R92.2 R95.2 U7.1 | length 137.8
  L01-TOP w5: v1(1086.47,341.7) 1090.44,341.7 1098.77,333.37 U7.1@1119.07,333.37
  L08-BOTTOM w5: R95.2@1044.36,346.19 1048.84,341.7 1090.03,341.7 1096.74,348.42 R92.2@1141.48,348.42
EEPROM_A1: R93.2 R96.2 U7.2 | length 147.3
  L01-TOP w5: v1(1086.25,313.69) U7.2@1119.07,313.69
  L08-BOTTOM w5: R96.2@1043.83,296.66 1047.76,296.66 1057.08,305.97 1057.08,309.9 1060.86,313.69 v1(1086.25,313.69) 1110.48,313.69 1121.28,302.9 1132.52,302.9 R93.2@1140.98,294.44
EEPROM_A2: R94.2 R97.2 U7.3 | length 141
  L01-TOP w5: v1(1083.16,282.01) 1083.7,282.01 1095.69,294 1114.98,294 1117.02,291.96 U7.3@1119.07,294
  L08-BOTTOM w5: v1(1083.16,282.01) 1083.16,247.07 R97.2@1080.76,244.66 1140.49,244.66 R94.2@1140.73,244.42
EEPROM_WP: R91.1 U7.7 | length 47.5
  L01-TOP w5: U7.7@1231.27,313.69 1271.29,313.69 R91.1@1276.55,318.95
ENC_SPI_CS1: R83.1 R119.1 U4.A10 | length 1010.3
  L01-TOP w4: R83.1@277.13,1539.05 278.71,1537.47 v1(312.4,1537.47) ; v1(859.4,1452.46) 859.23,1452.29 859.23,1154.22 871.03,1142.42 U4.A10@893.54,1142.42
  L08-BOTTOM w4: R119.1@312.14,1572.31 312.4,1572.05 v1(312.4,1537.47) 312.4,1503.6 331.04,1484.96 737.86,1484.96 770.52,1452.3 v1@859.24,1452.3
ENC_SPI_CS2: R84.1 R137.1 U4.F11 | length 550.9
  L01-TOP w4: R84.1@837,1589.48 857.34,1589.48 885.57,1561.25 885.57,1548.41 v3(888.58,1545.41) ; v2(1009.51,1180.3) 1009.51,1180.15 1021.5,1168.17 U4.F11@1021.5,1168.01
  L06-SIG w4: v3(888.58,1545.41) 889.14,1545.41 946.37,1488.17 946.37,1388.4 988.32,1346.45 988.32,1270.96 1008.43,1250.85 1008.43,1181.38 v2(1009.51,1180.3)
  L08-BOTTOM w5: R137.1@865.14,1572 868.02,1569.12 868.02,1558.38 878.18,1548.22 885.77,1548.22 v3(888.58,1545.41)
ENC_SPI_CS3: R85.1 R153.1 U4.F10 | length 998.6
  L01-TOP w3.8: v1(927.76,1405.24) 956.1,1405.24 1041.05,1490.2 1284.06,1490.2 1312.27,1461.98 1408.54,1461.98 1427.84,1481.28 1427.84,1507.05 v1(1410.64,1524.24)
  L01-TOP w4: v2(1009.51,1154.71) 1009.51,1154.56 1021.5,1142.57 U4.F10@1021.5,1142.42
  L01-TOP w5: R85.1@1377.93,1529.79 1401.11,1529.79 1406.66,1524.24 v1(1410.64,1524.24)
  L06-SIG w3.8: v1(927.76,1405.24) 927.76,1387.68 980.42,1335.02 980.42,1265.54 996.52,1249.44 996.52,1167.41 1009.22,1154.71 v2(1009.51,1154.71)
  L08-BOTTOM w5: v1(1410.64,1524.24) 1425.03,1538.64 1425.03,1566.83 R153.1@1430.8,1572.6
ENC_SPI_CS4: R86.1 R169.1 U4.C12 | length 1636
  L01-TOP w3.8: 929.78,1318.83 927.63,1316.68 927.63,1231.55 931.04,1228.14 931.04,1207.29 U4.C12@944.73,1193.6
  L01-TOP w4: 929.78,1318.83 1056.22,1445.26 1265.95,1445.26 1323.33,1387.88 1625.19,1387.88 v1(1626.02,1387.06)
  L01-TOP w5: R86.1@1933.21,1804.63 1949.68,1804.63 v3(1975.56,1778.76)
  L06-SIG w4: v1(1626.02,1387.06) 1626.02,1417.35 1632.87,1424.21 1655.6,1424.21 1682.5,1451.12 1682.5,1619.73 1775.7,1712.93 1936.87,1712.93 1975.35,1751.41 v3@1975.35,1778.55
  L08-BOTTOM w5: R169.1@1964.95,1807.5 1964.95,1790.95 1975.56,1780.34 v3(1975.56,1778.76)
ENC_SPI_CS5: R87.1 R185.1 U4.M12 | length 1044.3
  L01-TOP w4: U4.M12@1175.04,1193.6 1175.11,1193.6 v2(1188.04,1206.47) v2(1188.04,1206.47)
  L01-TOP w5: R87.1@1893.93,1190.68 1894.98,1189.63 1947.64,1189.63 v3(1966.04,1171.23)
  L06-SIG w4: v2(1188.04,1206.47) 1246.12,1206.47 1255.14,1215.49 1526.44,1215.49 1609.58,1298.63 1692.57,1298.63 1704.59,1286.61 1704.59,1219.69 1753.04,1171.23 v3(1966.04,1171.23)
  L08-BOTTOM w5: R185.1@1934.75,1186.7 1950.57,1186.7 v3(1966.04,1171.23)
ENC_SPI_CS6: R88.1 R201.1 U4.F12 | length 2318.2
  L01-TOP w4: U4.F12@1021.5,1193.6 1008.43,1206.67 1008.43,1234.67 984.45,1258.66 984.45,1362.18 1059.53,1437.26 1262.64,1437.26 1332.08,1367.82 1671.61,1367.82 1694,1345.42 1694,1297.91 1677.57,1281.49 1667.08,1281.49 v1(1664.08,1278.48)
  L01-TOP w5: R88.1@2414.18,1494.26 2418.36,1490.08 v3(2456.23,1490.08)
  L06-SIG w4: v1(1664.08,1278.48) 1664.08,1096.16 1682.35,1077.89 2112.95,1077.89 2456.23,1421.18 v3(2456.23,1490.08)
  L08-BOTTOM w5: v3(2456.23,1490.08) 2456.23,1494.05 2464,1501.82 2464,1519.3 R201.1@2464.56,1519.86
ESC_I2C_SCL: R71.1 U4.L9 U7.6 | length 1380.9
  L01-TOP w3.8: U7.6@1231.27,294 1250.01,294 1260.25,283.77 v1(1261.75,283.77) 1297.76,283.77 R71.1@1297.93,283.93
  L01-TOP w4: U4.L9@1149.45,1116.83 1149.58,1116.83 1162.12,1129.37 v2(1162.25,1129.37)
  L06-SIG w3.8: v2(1162.25,1129.37) 1266.19,1025.43 1266.19,903.97 1219.85,857.62 1106.21,857.62 1046.13,797.55 1046.13,702.94 1120.62,628.45 1120.62,446.69 1112.46,438.54 1112.46,311.72 1200.47,223.7 1249.66,223.7 1262.45,236.49 1262.45,283.07 v1(1261.75,283.77)
ESC_I2C_SDA: R72.1 U4.N12 U7.5 | length 1632.5
  L01-TOP w4: U4.N12@1200.63,1193.6 1234.39,1227.36 1234.39,1310.91 v2(1235.45,1311.97) ; U7.5@1231.27,274.32 1231.11,274.16 v1(1231.11,245.67) R72.1@1297.93,245.74 R72.1@1297.93,245.74
  L06-SIG w4: v1@1230.87,245.91 1230.87,561.22 1072.36,719.73 1072.36,786.62 1116,830.26 1229.01,830.26 1289.59,890.83 1289.59,1114.24 1265.79,1138.04 1237.57,1138.04 1171.93,1203.68 1171.93,1213.23 1183.94,1225.24 1225.97,1225.24 1235.45,1234.72 v2(1235.45,1311.97)
ESC_LED_ERR: R110.1 U4.L5 | length 1399.8
  L01-TOP w4: R110.1@375.11,1319.88 376.09,1320.87 v1(428.46,1320.87) ; U4.L5@1149.45,1014.47 1149.45,1014.34 1162.05,1001.74 v2(1162.05,1001.6)
  L03-SIG w4: v1(428.46,1320.87) 635.57,1527.98 1035.13,1527.98 1130.92,1432.2 1130.92,1350.29 1166.04,1315.17 1166.04,1261.43 1169.23,1258.23 1186.69,1258.23 1194.33,1250.6 1194.33,1237.11 1217.97,1213.47 1217.97,1057.52 v2(1162.05,1001.6)
ESC_LED_RUN: R111.1 U4.H11 | length 1356.6
  L01-TOP w3.7: 1085.12,1180.46 v2@1085.12,1277.15
  L01-TOP w4: U4.H11@1072.68,1168.01 1085.12,1180.46 ; v2(1083.57,1278.7) v2@1085.12,1277.15
  L01-TOP w5: R111.1@365.19,1044.99 366.27,1043.92 v1(393.41,1043.92)
  L08-BOTTOM w4: v1(393.41,1043.92) 378.8,1058.53 378.8,1444.19 403.56,1468.96 731.23,1468.96 860.1,1340.09 1041.48,1340.09 1083.57,1297.99 v2(1083.57,1278.7)
ESC_MDC: R32.1 U4.H10 | length 57.5
  L01-TOP w4: U4.H10@1072.68,1142.42 v2@1085.59,1155.35
  L08-BOTTOM w4: R32.1@1083.05,1193.51 1083.05,1166.96 1083.68,1166.33 1083.68,1157.27 v2(1085.59,1155.35)
ESC_MDIO: R19.1 R70.1 U4.K12 | length 1719.2
  L01-TOP w4: R19.1@739.75,939.58 739.75,936.9 742.04,934.6 v1(757.65,934.6) 757.65,907.93 R70.1@752.3,902.58 ; U4.K12@1123.86,1193.6 1123.86,1193.78 1135.49,1205.41 v2(1135.49,1205.58)
  L08-BOTTOM w4: v1(757.65,934.6) 703.5,934.6 575.04,1063.06 449.79,1063.06 390.66,1122.19 390.66,1444.74 406.88,1460.96 727.92,1460.96 856.79,1332.09 1038.16,1332.09 1065.45,1304.8 1065.45,1267.16 1126.07,1206.54 1134.53,1206.54 v2(1135.49,1205.58)
ESC_PHY0_LINK: D5.2 R106.1 TP20.1 U4.J13 U8.30 | length 1660.8
  L01-TOP w4: TP20.1@426.29,975.96 447.62,975.96 459.72,963.86 v1(459.72,947.91) ; U4.J13@1098.27,1219.2 v2@1098.3,1259.22
  L01-TOP w5: D5.2@378.82,946.03 380.7,947.91 v1(459.72,947.91) 462.02,947.91 470.43,939.5 U8.30@489.74,939.5
  L08-BOTTOM w4: v1(459.72,947.91) 459.72,972.69 415.36,1017.05 390.66,1017.05 369.11,1038.6 369.11,1445.82 400.25,1476.96 734.55,1476.96 863.42,1348.09 1044.79,1348.09 1098.33,1294.55 v2(1098.33,1259.25)
  L08-BOTTOM w5: R106.1@414.33,940.46 421.63,947.76 v1@459.57,947.76
ESC_PHY_RST: R105.2 TP21.1 U4.E9 U8.32 | length 1220.5
  L01-TOP w5: TP21.1@407.9,858.7 413.31,858.7 413.31,859.9 422.08,868.66 R105.2@422.08,897.51 428.46,891.13 461.43,891.13 470.43,900.13 U8.32@489.74,900.13 ; v2(982.98,1129.76) U4.E9@995.91,1116.83
  L03-SIG w3.8: v2(982.98,1129.76) 996.71,1143.49 996.71,1220.8
  L03-SIG w4: v1(460.44,891.13) 480.74,891.13 490.78,901.17 490.78,1044.02 460.38,1074.42 460.38,1119.21 557.96,1216.79 667.35,1216.79 676.06,1225.5 676.06,1304.43 705.68,1334.05 883.45,1334.05 996.71,1220.8
ESC_RX0_CLK: TP15.1 U4.D9 U8.19 | length 545.6
  L01-TOP w4: U8.19@613.75,1063.52 TP15.1@613.75,1139.23 634.72,1160.2 v2(759,1160.2) ; v2(957.52,1129.76) 957.52,1129.7 970.32,1116.9 U4.D9@970.32,1116.83
  L03-SIG w4: v2(759,1160.2) 772.9,1160.2 790.97,1142.13 800.49,1142.13 802.49,1142.13 ccw(c802.49,1146.63) 806.99,1146.63 806.99,1155.66 cw(c811.49,1155.66) 815.99,1155.66 815.99,1146.23 ccw(c820.49,1146.23) 824.99,1146.23 824.99,1155.66 cw(c829.49,1155.66) 833.99,1155.66 833.99,1146.23 ccw(c838.49,1146.23) 842.99,1146.23 842.99,1155.66 cw(c847.49,1155.66) 851.99,1155.66 851.99,1146.63 ccw(c856.49,1146.63) 856.49,1142.13 867.95,1142.13 945.16,1142.13 v2(957.52,1129.76)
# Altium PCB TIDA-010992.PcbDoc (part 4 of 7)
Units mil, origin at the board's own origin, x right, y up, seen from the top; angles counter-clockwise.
Board outline 2810.81 x 2427 mil, 8 copper layers (L01-TOP, L02-GND, L03-SIG, L04-GND, L05-PWR, L06-SIG, L07-GND, L08-BOTTOM), stack 61.9 mil thick; 521 components, 377 nets, 1545 pads, 874 vias.

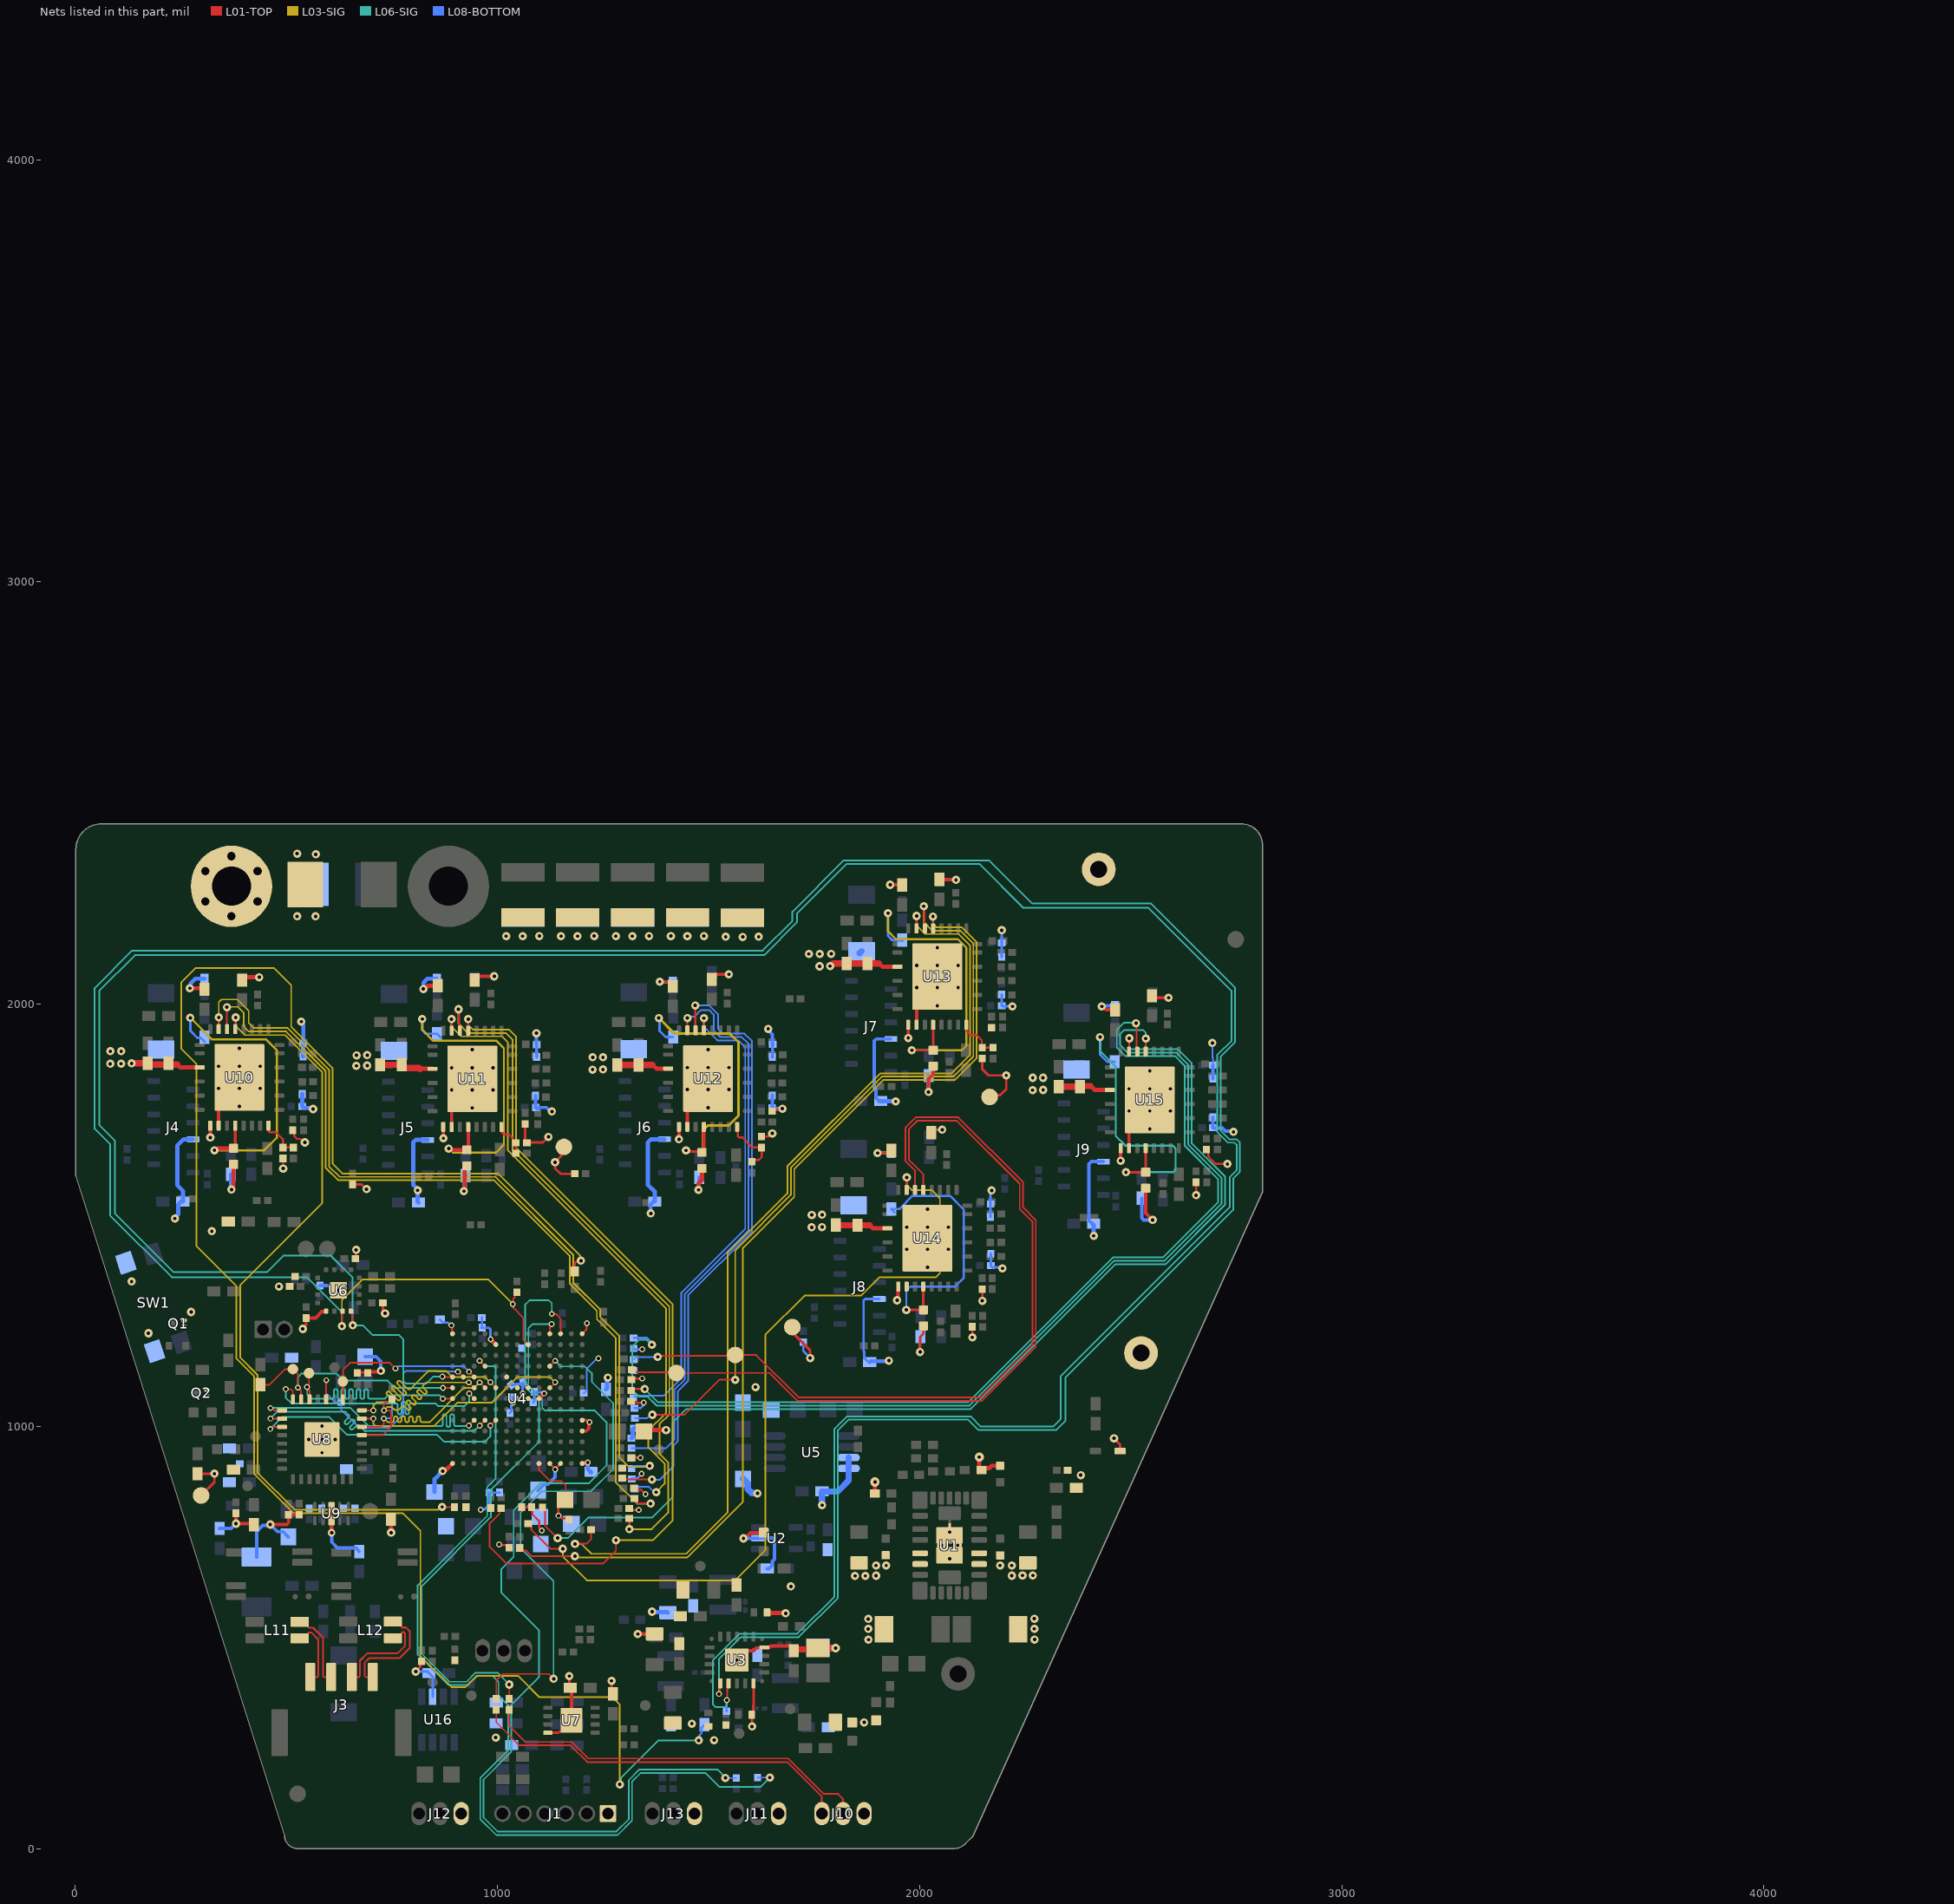
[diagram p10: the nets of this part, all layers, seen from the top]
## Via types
v1: diameter 19.68, hole 8, L01-TOP to L08-BOTTOM, tented both sides, 520 vias
v2: diameter 14, hole 8, L01-TOP to L08-BOTTOM, tented both sides, 146 vias
v3: diameter 19.68, hole 8, L01-TOP to L08-BOTTOM, 141 vias
v4: diameter 30, hole 18, L01-TOP to L08-BOTTOM, 18 vias
v5: diameter 22, hole 8, L01-TOP to L08-BOTTOM, tented both sides, 16 vias
v6: diameter 39.37, hole 19.68, L01-TOP to L08-BOTTOM, 12 vias
v7: diameter 22, hole 8, L01-TOP to L08-BOTTOM, 8 vias
v8: diameter 18, hole 8, L01-TOP to L08-BOTTOM, tented both sides, 5 vias
v9: diameter 14, hole 8, L01-TOP to L08-BOTTOM, 4 vias
v10: diameter 157.48, hole 98.43, L01-TOP to L08-BOTTOM, 4 vias

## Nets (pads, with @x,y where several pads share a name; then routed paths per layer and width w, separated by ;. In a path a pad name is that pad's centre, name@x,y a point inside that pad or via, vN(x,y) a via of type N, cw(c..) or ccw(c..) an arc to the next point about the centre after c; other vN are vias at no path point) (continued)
ESC_RX0_D0: U4.E8 U8.16 | length 548.8
  L01-TOP w4: U8.16@678.71,1037.93 678.77,1037.88 706.11,1037.88 v2(706.16,1037.82) ; v2(983.11,1104.17) 983.11,1104.11 995.91,1091.31 U4.E8@995.91,1091.24
  L03-SIG w4: v2(706.16,1037.82) 706.16,1049.77 713.21,1056.82 740.79,1056.82 745.48,1056.82 ccw(c745.48,1061.32) 748.66,1064.51 738.4,1074.78 cw(c741.58,1077.96) 738.4,1081.14 cw(c741.58,1077.96) 744.76,1081.14 763.1,1062.8 ccw(c766.29,1065.98) 769.47,1062.8 ccw(c766.29,1065.98) 769.47,1069.16 751.12,1087.5 cw(c754.31,1090.69) 751.12,1093.87 cw(c754.31,1090.69) 757.49,1093.87 775.83,1075.52 ccw(c779.01,1078.7) 782.2,1075.52 ccw(c779.01,1078.71) 782.2,1081.89 763.85,1100.23 cw(c767.03,1103.41) 763.85,1106.6 cw(c767.03,1103.41) 770.21,1106.6 787.97,1088.84 ccw(c791.16,1092.02) 794.34,1088.84 802.77,1097.27 836.17,1130.67 879,1130.67 893.03,1116.64 970.65,1116.64 v2(983.11,1104.17)
ESC_RX0_D1: U4.K8 U8.15 | length 544.2
  L01-TOP w4: U8.15@678.71,1018.24 678.82,1018.35 705.55,1018.35 v2(705.66,1018.47) ; U4.K8@1123.86,1091.28 v2(1136.65,1104.11)
  L03-SIG w4: v2(705.66,1018.47) 705.66,1006.74 712.07,1000.32 849.26,1000.32 904.68,1055.74 986.33,1055.74 1047.49,1116.9 1123.86,1116.9 v2(1136.65,1104.11)
ESC_RX0_D2: R80.1 U4.D8 U8.14 | length 496.2
  L01-TOP w4: U8.14@678.71,998.56 723.15,998.56 730.71,1006.12 v2(730.71,1018.72) ; v2(957.52,1103.94) 957.57,1103.94 U4.D8@970.32,1091.24 U4.D8@970.32,1091.24
  L03-SIG w4: v2(730.71,1018.72) 731,1018.72 740.05,1009.67 747.8,1009.67 749.8,1009.67 ccw(c749.8,1014.17) 754.3,1014.17 754.3,1019.09 cw(c758.8,1019.09) 763.3,1019.09 763.3,1014.17 ccw(c767.8,1014.17) 772.3,1014.17 772.3,1019.09 cw(c776.8,1019.09) 781.3,1019.09 781.3,1014.17 ccw(c785.8,1014.17) 790.3,1014.17 790.3,1019.09 cw(c794.8,1019.09) 799.3,1019.09 799.3,1014.17 ccw(c803.8,1014.17) 808.3,1014.17 808.3,1019.09 cw(c812.8,1019.09) 817.3,1019.09 817.3,1014.17 ccw(c821.8,1014.17) 821.8,1009.67 837.64,1009.67 838.51,1009.67 919.95,1091.11 944.69,1091.11 v2(957.52,1103.94)
  L08-BOTTOM w4: v2(730.71,1018.72) 743.98,1018.72 749.94,1024.67 R80.1@749.94,1063.38
ESC_RX0_D3: R79.1 U4.C8 U8.13 | length 543.8
  L01-TOP w4: U8.13@679.52,979.68 U8.13@678.71,978.87 727.84,978.87 747.65,998.69 747.65,1033.9 743.81,1037.74 v2(730.97,1037.74) 730.97,1052.8 734.99,1056.82 743.67,1056.82 749.94,1063.09 R79.1@749.94,1063.67 ; v2(931.93,1103.94) 931.98,1103.94 U4.C8@944.73,1091.24 U4.C8@944.73,1091.24
  L03-SIG w4: v2(730.97,1037.74) 739.21,1045.98 748.95,1045.98 756.21,1038.72 765.86,1038.72 773.64,1046.49 cw(c776.82,1043.31) 780,1046.49 786.53,1039.97 ccw(c789.71,1043.15) 792.9,1039.97 ccw(c789.71,1043.15) 792.9,1046.33 785.69,1053.54 cw(c788.87,1056.72) 785.69,1059.91 cw(c788.87,1056.72) 792.05,1059.91 799.26,1052.7 ccw(c802.44,1055.88) 805.62,1052.7 ccw(c802.44,1055.88) 805.62,1059.06 798.41,1066.27 cw(c801.6,1069.45) 798.41,1072.63 cw(c801.6,1069.45) 804.78,1072.63 811.99,1065.42 ccw(c815.17,1068.61) 818.35,1065.42 ccw(c815.17,1068.61) 818.35,1071.79 811.14,1079 cw(c814.32,1082.18) 811.14,1085.36 cw(c814.32,1082.18) 817.51,1085.36 824.72,1078.15 ccw(c827.9,1081.33) 831.08,1078.15 ccw(c827.9,1081.33) 831.08,1084.52 824.55,1091.04 cw(c827.73,1094.22) 824.55,1097.41 831.08,1103.94 843,1103.94 v2(931.93,1103.94)
ESC_RX0_DV: TP16.1 U4.C9 U8.18 | length 406.4
  L01-TOP w4: U8.18@633.44,1063.52 633.58,1063.67 633.58,1106.14 TP16.1@633.66,1106.21 ; TP16.1@633.58,1106.29 633.94,1106.64 633.94,1133.28 650.85,1150.19 744.75,1150.19 v2(757.98,1136.96) ; v2(932.39,1129.43) 932.39,1129.3 944.73,1116.97 U4.C9@944.73,1116.83
  L08-BOTTOM w4: v2(757.98,1136.96) 759.65,1136.96 765.32,1142.63 919.19,1142.63 v2(932.39,1129.43)
ESC_RX0_ERR: R78.1 U4.B9 U8.20 | length 563.6
  L01-TOP w4: U8.20@594.07,1063.52 594.24,1063.69 594.24,1108.98 v2(594.4,1109.15) ; v2(906.53,1129.43) U4.B9@919.13,1116.83
  L08-BOTTOM w4: v2(594.4,1109.15) 594.31,1109.05 594.31,1078.24 615.72,1056.82 R78.1@629.34,1056.82 629.34,1039.37 672.03,996.68 745.64,996.68 776.64,1027.68 776.64,1124.61 782.7,1130.67 854.37,1130.67 854.8,1130.24 905.71,1130.24 v2(906.53,1129.43)
ESC_TX0_CLK: TP17.1 U4.A7 U8.22 | length 636.2
  L01-TOP w4: TP17.1@553.4,1125.95 553.4,1100.24 548.9,1095.74 v2(548.9,1093.03) 548.9,1090.33 554.7,1084.53 554.7,1066.74 553.08,1065.13 U8.22@554.7,1063.52 ; v2(870.47,1065.66) U4.A7@893.54,1065.65
  L06-SIG w4: v2(548.9,1093.03) 549.2,1092.74 549.2,1075.63 559.17,1065.66 605.76,1065.66 607.76,1065.66 ccw(c607.76,1070.16) 612.26,1070.16 612.26,1083.82 cw(c616.76,1083.82) 621.26,1083.82 621.26,1069.32 ccw(c625.76,1069.32) 630.26,1069.32 630.26,1083.84 cw(c634.76,1083.84) 639.26,1083.84 639.26,1069.32 ccw(c643.76,1069.32) 648.26,1069.32 648.26,1083.87 cw(c652.76,1083.87) 657.26,1083.87 657.26,1069.32 ccw(c661.76,1069.32) 666.26,1069.32 666.26,1083.9 cw(c670.76,1083.9) 675.26,1083.9 675.26,1069.32 ccw(c679.76,1069.32) 684.26,1069.32 684.26,1083.93 cw(c688.76,1083.93) 693.26,1083.93 693.26,1070.16 ccw(c697.76,1070.16) 697.76,1065.66 704.34,1065.66 733.31,1065.66 741.68,1074.04 862.09,1074.04 v2(870.47,1065.66)
ESC_TX0_D0: U4.C7 U8.24 | length 638.1
  L01-TOP w4: v2(498.3,1088.32) 499.16,1087.46 511.3,1087.46 515.33,1083.43 U8.24@515.33,1063.52 ; v2(933.06,1077.66) 933.06,1077.48 944.73,1065.82 U4.C7@944.73,1065.65
  L06-SIG w4: v2(498.3,1088.32) 498.3,1068.23 512.2,1054.34 741.93,1054.34 759.04,1054.34 cw(c759.04,1049.84) 763.54,1049.84 763.54,1033.16 ccw(c768.04,1033.16) 772.54,1033.16 772.54,1054.23 cw(c777.04,1054.23) 781.54,1054.23 781.54,1033.16 ccw(c786.04,1033.16) 790.54,1033.16 790.54,1049.84 cw(c795.04,1049.84) 795.04,1054.34 797.04,1054.34 852.9,1054.34 859.5,1047.74 921.22,1047.74 933.06,1059.58 v2(933.06,1077.66)
ESC_TX0_D1: U4.C5 U8.25 | length 637.6
  L01-TOP w4: v2(462.05,1043.3) 464.75,1043.3 470.12,1037.93 U8.25@489.74,1037.93 ; v2(932.24,1001.8) 932.24,1001.89 944.73,1014.38 U4.C5@944.73,1014.47
  L06-SIG w4: v2(462.05,1043.3) 462.28,1043.53 651.7,1043.53 694.9,1000.32 863.53,1000.32 865.53,1000.32 ccw(c865.53,1004.82) 870.03,1004.82 870.03,1024.08 cw(c874.53,1024.08) 879.03,1024.08 879.03,1003.08 ccw(c883.53,1003.08) 888.03,1003.08 888.03,1024.08 cw(c892.53,1024.08) 897.03,1024.08 897.03,1004.82 ccw(c901.53,1004.82) 901.53,1000.32 909.04,1000.32 930.76,1000.32 v2(932.24,1001.8)
ESC_TX0_D2: U4.D5 U8.26 | length 640.2
  L01-TOP w4: v2(462.08,1018.47) 462.19,1018.35 489.62,1018.35 U8.26@489.74,1018.24 ; v2(957.92,1001.8) 957.92,1001.94 970.32,1014.33 U4.D5@970.32,1014.47
  L06-SIG w4: v2(462.08,1018.47) 478.52,1034.91 639.4,1034.91 647.18,1027.14 cw(c643.99,1023.95) 647.18,1020.77 639.08,1012.68 ccw(c642.26,1009.5) 639.08,1006.31 ccw(c642.26,1009.5) 645.45,1006.31 653.91,1014.77 cw(c657.09,1011.59) 660.27,1014.77 cw(c657.09,1011.59) 660.27,1008.41 651.81,999.95 ccw(c654.99,996.77) 651.81,993.59 ccw(c654.99,996.77) 658.17,993.59 666.27,1001.68 cw(c669.45,998.5) 672.63,1001.68 685.64,988.68 688.52,988.68 688.82,988.98 945.1,988.98 v2(957.92,1001.8)
ESC_TX0_D3: U4.E5 U8.27 | length 636.9
  L01-TOP w4: v2(461.89,993.86) 464.6,993.86 469.46,998.72 489.58,998.72 U8.27@489.74,998.56 ; v2(982.88,1001.71) 983.01,1001.71 995.77,1014.47 U4.E5@995.91,1014.47
  L06-SIG w4: v2(461.89,993.86) 490.56,1022.52 600.78,1022.52 642.77,980.53 856.28,980.53 873.55,963.26 970.32,963.26 983.11,976.05 983.11,1001.48 v2(982.88,1001.71)
ESC_TX0_EN: R67.1 TP19.1 U4.A8 U8.23 | length 592.9
  L01-TOP w4: R67.1@444.32,1105.13 R67.1@437.83,1098.64 459.84,1098.64 496.06,1134.85 514.53,1134.85 TP19.1@515.33,1135.65 527.2,1123.77 v2(527.2,1091.61) 534.77,1084.04 534.77,1067.71 532.8,1065.73 U8.23@535.01,1063.52 ; v2(870.72,1091.06) 870.81,1091.15 U4.A8@893.54,1091.24 U4.A8@893.54,1091.24
  L06-SIG w4: v2(527.2,1091.61) 527.2,1116.19 536.31,1125.3 618.35,1125.3 635.18,1108.47 739.71,1108.47 757.12,1091.06 v2(870.72,1091.06)
Fault_IN: R220.2 R222.2 | length 4474.5
  L01-TOP w5: R222.2@1182.73,1366.94 1182.73,1386.25 1185.94,1389.46 1194.98,1389.46 v1(1197.79,1392.27)
  L03-SIG w4: v1(1197.79,1392.27) 1195.76,1394.31 1195.76,1404.64 1001.61,1598.79 632.55,1598.79 608.91,1622.43 608.91,1848.19 511.29,1945.81 511.29,2044.54 470.81,2085.02 284.48,2085.02 250.41,2050.95 250.41,1894.77 287.07,1858.11 287.07,1426.8 381.68,1332.19 381.68,1160.42 423.53,1118.58 423.53,887.3 516.37,794.46 775.66,794.46 817.37,752.75 817.37,456.01 891.04,382.35 923.92,382.35 950.25,408.68 1049.23,408.68 1099.29,358.62 1271.96,358.62 1289.67,340.91 v1(1289.67,151.81)
  L06-SIG w4: v1(1289.67,151.81) 1292.04,154.18 1292.04,167.21 1381.03,256.2 v1(1476.61,256.2)
  L08-BOTTOM w5: v1(1476.61,256.2) 1478.82,258.41 1478.82,268.52 1483.14,272.84 1483.14,285.97 R220.2@1490.33,293.16
FSIRXA_CLK: R211.1 U4.K13 | length 2387.2
  L01-TOP w3.8: U4.K13@1123.86,1219.2 1123.88,1235.44 1127.85,1239.41 v2(1127.85,1242.17)
  L06-SIG w3.8: v2(1127.85,1242.17) 1082.96,1242.17 1072.99,1232.2 1072.99,1096.61 1106.05,1063.55 1106.05,1043.17 1111.81,1037.41 1230.6,1037.41 1258.39,1009.62 1258.39,907.2 1216.61,865.42 1102.83,865.42 1038.33,800.92 1038.33,690.87 1008.7,661.24 1008.7,606.52 1098.11,517.11 1098.11,406.53 1097.57,405.99 1097.57,405.1 1032.89,340.42 1032.89,229.29 967.01,163.41 967.01,73.04 999.69,40.36 1282.04,40.36 1310.93,69.25 1310.93,161.89 1336.32,187.29 1520.64,187.29 1539.67,168.26 v1(1539.67,167.18)
  L08-BOTTOM w3.8: v1(1539.67,167.18) R211.1@1566.06,167.18
FSIRXA_D0: R212.1 U4.D10 | length 2286.1
  L01-TOP w4: v2(957.52,1155.31) U4.D10@970.32,1142.47
  L06-SIG w3.7: v2(957.52,1155.31) 970.32,1142.47 993.67,1142.47 995.84,1140.3 995.84,876.69 975.53,856.37 975.53,788.08 810.89,623.45 810.89,459.61 882.99,387.51 930.63,387.51 951.8,408.68 988.82,408.68 1002.21,395.28 1002.21,362.87 1025.14,339.95 1025.14,232.5 959.26,166.62 959.26,69.83 997.09,32 1284.64,32 1318.73,66.09 1318.73,158.73 1338.72,178.73 1493.26,178.73 1526.17,145.81 1622.67,145.81 v1(1644.89,168.04)
  L08-BOTTOM w3.8: R212.1@1615.82,168.04 v1(1644.89,168.04)
FSITXA_CLK: R18.1 U4.K10 | length 1242.9
  L01-TOP w3.7: R18.1@997.04,354.58 997.04,397.9 1012.72,413.58 1121.51,413.58 v1(1132.91,402.18)
  L01-TOP w4: U4.K10@1123.86,1142.42 v2(1136.65,1155.22)
  L06-SIG w3.7: v1(1132.91,402.18) 1132.91,633.6 1054.76,711.76 1054.76,795.22 1105.45,845.91 1221.15,845.91 1273.94,898.69 1273.94,1054.9 1223.43,1105.41 1223.43,1125.7 1207.03,1142.1 1149.78,1142.1 v2(1136.65,1155.22)
FSITXA_CLK_P1: J10.1 R18.2 | length 913.9
  L01-TOP w3.8: R18.2@997.04,328.59 997.04,299.04 1051.66,244.42 1172.78,244.42 1212.48,204.72 1686.3,204.72 1768.35,122.67 J10.1@1768.35,82.68
FSITXA_D0: R17.1 U4.L13 | length 1402.4
  L01-TOP w3.7: R17.1@1027.07,354.7 1027.78,355.41 v1(1027.78,388.47) ; v2(1128.55,1266.14) 1128.84,1265.85 1138.62,1265.85 1149.45,1255.01 U4.L13@1149.45,1219.2
  L06-SIG w3.7: v1(1027.78,388.47) 999.82,416.43 947.92,416.43 926.76,395.26 886.2,395.26 820.17,461.3 820.17,621.16 984.09,785.08 984.09,849.13 1098.25,963.29 1098.25,1060.32 1065.19,1093.38 1065.19,1287.96 1075.86,1298.63 1121.43,1298.63 1128.55,1291.51 v2(1128.55,1266.14)
FSITXA_D0_P1: J10.2 R17.2 | length 935.5
  L01-TOP w3.8: R17.2@1027.07,328.71 1027.07,291.56 1066.41,252.22 1176.01,252.22 1214.98,213.26 1688.79,213.26 1772.83,129.22 1806.93,129.22 1818.35,117.8 J10.2@1818.35,82.68
GND: C1.2 C2.2 C3.2 C4.1 C5.1 C6.1 C7.1 C8.1 C9.1 C10.1 C11.1 C12.1 C13.1 C14.1 C16.1 C17.1 C18.1 C19.1 C20.1 C21.2 C22.2 C23.2 C24.2 C25.2 C26.2 C28.2 C29.2 C30.2 C31.2 C32.2 C33.2 C34.2 C35.2 C36.2 C37.2 C38.2 C39.1 C40.1 C41.2 C42.2 C43.2 C44.2 C45.2 C46.2 C47.2 C48.2 C49.2 C50.2 C51.2 C52.2 C53.2 C54.2 C55.2 C56.2 C57.2 C58.2 C59.2 C60.2 C61.2 C62.2 C63.2 C64.2 C65.2 C66.2 C67.2 C68.2 C69.2 C70.2 C71.2 C72.2 C73.2 C74.1 C75.2 C76.2 C77.2 C78.2 C79.2 C80.2 C81.2 C82.2 C83.2 C84.2 C85.2 C86.2 C87.2 C88.2 C89.2 C90.2 C91.2 C92.2 C93.2 C94.2 C95.2 C96.2 C97.2 C98.1 C99.1 C100.1 C101.1 C102.2 C103.2 C104.2 C105.2 C106.2 C107.1 C108.2 C110.2 C111.2 C112.2 C113.2 C114.2 C116.1 C117.1 C118.2 C119.2 C120.1 C121.2 C122.2 C123.2 C124.2 C125.1 C126.1 C127.2 C128.2 C129.2 C131.1 C132.1 C133.2 C134.2 C135.1 C136.2 C137.2 C138.2 C139.2 C140.1 C141.1 C142.2 C143.2 C144.2 C146.1 C147.1 C148.2 C149.2 C150.1 C151.2 C152.2 C153.2 C154.2 C155.1 C156.1 C157.2 C158.2 C159.2 C161.1 C162.1 C163.2 C164.2 C165.1 C166.2 C167.2 C168.2 C169.2 C170.1 C171.1 C172.2 C173.2 C174.2 C176.1 C177.1 C178.2 C179.2 C180.1 C181.2 C182.2 C183.2 C184.2 C185.1 C186.1 C187.2 C188.2 C189.2 C191.1 C192.1 C193.2 C194.2 C195.1 C196.2 C197.2 C198.2 C199.2 C200.1 C201.1 C202.2 C203.1 D1.1 D2.1 D3.1 D4.1 GND.1 J1.1 J4.8 J5.8 J6.8 J7.8 J8.8 J9.8 J10.3 J11.3 J12.3 J13.3 NT1.1 Q1.2 Q2.2 R2.1 R10.1 R36.1 R47.1 R75.1 R81.1 R90.1 R91.2 R95.1 R96.1 R97.1 R102.1 R103.2 R105.1 R106.2 R107.1 R128.1 R129.1 R145.1 R161.1 R177.1 R193.1 R209.1 R213.1 R218.1 R219.1 RT1.1 SW1.2 SW1.4 TP2.1 TP3.1 TP4.1 TP5.1 TP6.1 TP7.1 U1.5 U1.6 U1.16 U1.17 U1.28 U1.29 U2.2 U3.6 U3.11 U3.23 U4.A1 U4.A13 U4.E12 U4.F9 U4.G7 U4.G8 U4.H7 U4.H8 U4.J1 U4.J7 U4.K1 U4.L1 U4.N1 U4.N4 U4.N5 U4.N13 U5.7 U5.8 U6.1 U6.17 U7.4 U7.9@1175.17,303.85 U8.33 U9.3@606.72,809.63 U9.8@606.72,776.75 U10.3 U10.7 U10.8 U10.29 U11.3 U11.7 U11.8 U11.29 U12.3 U12.7 U12.8 U12.29 U13.3 U13.7 U13.8 U13.29 U14.3 U14.7 U14.8 U14.29 U15.3 U15.7 U15.8 U15.29 U16.2 | length 9750
  L01-TOP w4: U4.J1@1098.27,912.11 1098.27,897.51 1125.82,869.96 1151.57,869.96 1161.48,860.06 1161.48,832.05 C68.2@1167.35,826.18
  L01-TOP w5: C118.2@491.73,1634.21 492.26,1633.68 v1(492.26,1610.55) ; C119.2@514.74,1701.44 518.38,1697.79 518.38,1687.81 525.43,1680.76 533.39,1680.76 541.69,1672.46 v1(543.66,1672.46) ; v2(890.89,1239.35) 892.62,1237.63 892.62,1232.69 892.7,1232.6 892.7,1220.04 U4.A13@893.54,1219.2 ; v2(1003.6,720.39) 1004.98,719.01 1021.41,719.01 1027.17,713.24 C65.2@1027.17,712.46 ; C54.2@1057.56,808.47 C55.2@1082.4,808.47 ; C55.2@1081.21,808.36 1082.29,807.29 1082.29,791.55 1098.41,775.42 1098.41,760.48 1105,753.89 v2(1105,753.05) ; U4.J1@1098.27,912.11 U4.J1@1098.99,911.38 ; U4.K1@1123.86,912.11 1123.86,911.5 v2@1136.72,898.65 ; v2(1136.72,898.04) v2@1136.72,898.65 ; U4.L1@1149.45,912.11 1149.45,911.44 1136.72,898.71 v2@1136.72,898.65 ; C53.2@1167.35,782.61 1151.77,782.61 1145.97,788.41 v2(1144.34,788.41) 1144.34,811.11 1159.4,826.18 C68.2@1167.35,826.18 ; U4.N13@1200.63,1219.2 1200.63,1219.28 1210.89,1229.54 1210.89,1243.14 v2(1211.79,1244.04) ; C57.2@1312,802.01 1312.1,801.91 v2(1334.7,801.91) ; C60.2@1315.32,1110.68 1317.92,1113.28 v2(1342.99,1113.28) ; C61.2@1316.12,1059.05 1319.35,1055.82 v2(1346.49,1055.82) ; C94.2@1317.2,925.65 1317.42,925.44 v2(1338.87,925.44) ; C56.2@1323.14,850.46 1339.28,850.46 v2(1350.6,839.15) ; C178.2@2124.44,1235.67 2124.85,1235.26 v1(2124.85,1210.69) ; C179.2@2148.13,1324.9 2148.54,1324.49 v1(2148.54,1297.27) ; v3(2654.9,1547.27) 2654.9,1578.03 C193.2@2654.96,1578.09 ; C194.2@2680.88,1655.4 2683.74,1652.54 2683.74,1638.57 2700.79,1621.52 v1(2729,1621.52)
  L01-TOP w6: R107.1@289.84,887.8 v1(329.43,887.8) 329.43,867.69 TP7.1@297.88,836.15 ; v1(538.69,1230.71) 538.69,1232.31 546.93,1240.55 C73.2@546.93,1256.62 ; R219.1@657,1573.07 678.16,1573.07 v1(689.58,1561.64) ; C70.2@663.23,1397.28 665.19,1399.25 v1(665.19,1418.02) ; C71.2@728.3,1292.09 728.61,1291.78 728.61,1276.21 733.69,1271.12 v1(733.69,1267.42) ; v1(806.19,419.31) 817.03,430.15 817.03,440.17 C47.2@820.17,443.31 ; C46.2@898.97,446.07 C46.2@899.23,446.34 ; C134.2@1065.72,1716.09 1065.72,1675.33 C133.2@1069.27,1671.78 1069.95,1672.46 1107.35,1672.46 v3(1120.57,1685.68) ; U7.4@1119.07,274.32 1144.62,274.32 1147.62,277.32 1152.58,277.32 1175.17,299.91 U7.9@1175.17,303.85 ; TP5.1@1157.21,1661.93 1150.83,1655.54 1150.83,1640.03 v1(1136.39,1625.6) 1136.49,1625.5 1136.49,1611.05 1149.48,1598.07 R218.1@1182.89,1598.07 ; v1(1170.05,408.38) 1170.05,382.88 C74.1@1172.43,380.51 C74.1@1175.17,377.77 ; U4.N5@1200.63,1014.47 1201.37,1015.21 1210.52,1015.21 1215.8,1009.93 v2(1217.96,1009.93) ; v1(1270.05,397.19) 1270.05,369.53 R91.2@1273.54,366.04 ; v1(1603.03,289.13) 1602.5,289.66 1602.5,315.66 1599.97,318.19 1605.4,323.62 1605.4,337.88 1606.43,338.91 U3.6@1606.43,391.42 ; C148.2@1625.74,1686.42 1641.16,1686.42 1648.46,1693.72 v3(1651,1693.72) ; C149.2@1650.61,1746.65 1653.65,1749.7 1672.19,1749.7 v1(1674.81,1752.32) ; TP6.1@1698.31,1235.08 1704.69,1228.7 1704.69,1215.77 1740.7,1179.76 v1@1740.7,1161.78 ; v1(1900.48,1647.41) 1927.13,1647.41 C186.1@1933.42,1653.71 ; v1(2000.88,1176.13) 2000.88,1211.37 2008.99,1219.48 C177.1@2008.99,1237.67 ; C185.1@2025.64,1694.23 2033.82,1702.41 v1(2053.26,1702.41) ; v3(2070.88,749.59) NT1.1@2070.88,766.09 ; C163.2@2147.78,1871.12 2147.78,1846.67 2163.25,1831.2 v3(2205.16,1831.2) 2205.16,1798.96 2190.26,1784.06 2169.62,1784.06 TP4.1@2165.66,1780.1 ; v1(2460.5,971.56) 2474.86,957.2 RT1.1@2474.86,941.28
  L01-TOP w8: v1(319.72,1684.03) U10.7@319.72,1712.3 ; U10.8@338.48,1711.38 U10.8@339.4,1712.3 339.4,1751.74 345.24,1757.58 v1(388.61,1757.58) ; C111.2@380.67,794.49 v1(380.67,769.57) 420.55,769.57 C110.2@423.14,766.98 ; v1(461.63,767.41) 500.3,767.41 504.98,772.1 C105.2@504.98,790.61 C97.2@530.32,790.61 ; C73.2@546.93,1256.62 568.88,1256.62 583.77,1271.51 592.54,1271.51 U6.1@593.73,1272.7 ; C103.2@667.44,1126.51 668.5,1127.57 692.69,1127.57 692.85,1127.41 694.72,1129.29 721.5,1129.29 v1(723.74,1131.52) ; U11.7@871.52,1708.96 871.7,1708.79 871.7,1682.48 v1(871.87,1682.31) ; U11.8@890.29,1708.04 U11.8@891.21,1708.96 891.21,1748.39 897.05,1754.24 v1(940.42,1754.24) ; C140.1@945.64,2057.04 945.64,2058.15 953.45,2065.96 v3(992.34,2065.96) ; U4.E12@995.91,1193.6 U4.E12@995.91,1193.74 ; U7.9@1175.17,303.85 C74.1@1175.17,377.77 ; U4.N4@1200.63,988.88 1210.52,988.88 1216.81,995.18 1216.81,1008.78 v2(1217.96,1009.93) ; v1(1384.32,2052.98) 1407.78,2052.98 1415.37,2045.39 C156.1@1415.37,2041.19 ; v1(1429.9,1679.8) U12.7@1429.9,1709.42 ; U12.8@1449.58,1709.42 1449.58,1748.85 1455.43,1754.69 v1(1498.8,1754.69) ; C155.1@1507.71,2058.79 1507.71,2062.69 1515.52,2070.5 v3(1548.01,2070.5) ; C29.2@1566.06,624.15 C29.2@1572,618.21 ; v1(1567.06,446.54) 1588.98,468.46 1606.43,468.46 1613.11,475.14 1631.1,475.14 U3.11@1632.02,476.06 1632.94,476.99 1644.89,476.99 1648.02,480.12 1694,480.12 C24.2@1701.81,472.31 ; v1(1582.67,734.56) 1585.83,734.56 1599.26,747.99 D4.1@1630.66,747.99 ; v1(1930.17,2282.61) 1958.01,2282.61 C171.1@1958.21,2282.42 ; v1(1946.72,1298.56) 1948.63,1300.47 1948.63,1330.42 U14.7@1949.55,1331.34 ; v1(1972.97,1919.75) U13.7@1972.97,1950.94 ; U13.8@1992.65,1950.94 1992.65,1990.38 1998.49,1996.22 v1(2041.86,1996.22) ; v1(2021.14,1791.81) 2021.14,1822.31 2032.02,1833.2 C162.1@2032.02,1852.85 ; C170.1@2047.42,2295.36 2084.73,2295.36 v3(2086.02,2294.06) ; v1(2431.33,1994.49) 2433.98,1994.49 2441.41,1987.06 2462.48,1987.06 C201.1@2463.32,1986.22 ; v1(2476.24,1629.01) U15.7@2476.24,1659.06 ; U15.8@2495.93,1659.06 2495.93,1698.5 2501.77,1704.34 v1(2545.14,1704.34) ; C192.1@2535.54,1563.9 2535.54,1505.06 v1(2551.81,1488.8) ; C200.1@2550.75,2019.63 2555.41,2014.98 2589.46,2014.98 v3(2589.59,2015.11)
  L01-TOP w10: 241.07,1856.94 247.92,1850.1 U10.3@294.12,1850.1 ; v1(271.12,2037.77) 303.3,2037.77 C126.1@306.14,2034.93 ; v1(369.9,1560.88) 369.9,1563.5 374.71,1568.32 C117.1@374.71,1620.4 ; C125.1@395.14,2061.12 397.54,2063.52 v3(435.61,2063.52) ; U9.3@606.72,809.63 606.9,809.45 606.9,776.75 606.81,776.66 606.81,748.08 v8(606.9,747.99) ; C108.2@747.65,779.98 747.85,779.78 747.85,748.29 v1(748.04,748.09) ; 816.41,1846.76 U11.3@845.93,1846.76 ; v1(824.19,2035.74) 826.81,2035.74 834.75,2043.68 851.22,2043.68 853.51,2041.38 C141.1@853.51,2033.42 ; v1(870.02,894.2) 871.87,896.05 877.49,896.05 U4.A1@893.54,912.11 ; v1(920.46,1557) 922.08,1558.61 922.08,1614.89 C132.1@927.42,1620.23 ; v2(983.8,1206) 983.8,1205.85 U4.E12@995.91,1193.75 ; U4.J7@1098.27,1065.65 v2@1110.74,1078.08 ; U4.L1@1149.45,912.11 U4.L1@1149.8,911.76 ; U4.N1@1200.63,912.11 1201.12,912.11 1201.47,912.45 1210.91,912.45 1212.8,914.34 v2(1213.88,914.34) ; v1(1332.41,508.05) 1332.56,508.21 1371.91,508.21 C35.2@1372.06,508.36 ; C49.2@1346.58,988.03 1349.86,991.3 v3(1399.32,991.3) ; 1367.42,1855.84 1376.05,1847.21 U12.3@1404.31,1847.21 ; v1(1476.04,1559.94) 1476.14,1560.05 1476.14,1574.97 1484.27,1583.1 C147.1@1484.27,1610.75 ; C30.2@1638.52,559.09 1639.55,558.05 1681.46,558.05 v1(1682.5,557.01) ; C24.2@1701.81,468.46 C24.2@1702.14,468.79 ; 1881.64,1476.36 1888.87,1469.13 U14.3@1923.96,1469.13 ; R2.1@1893.73,841.09 1893.93,841.3 1893.93,867.82 v5(1894.13,868.02) ; 1903.81,2096.29 1911.36,2088.74 U13.3@1947.38,2088.74 ; C1.2@2140.1,896.09 C1.2@2140.65,896.64 ; v5(2141.19,927.32) 2140.65,926.77 C1.2@2140.65,896.64 ; C14.1@2190.41,906.78 2170.52,906.78 2164.67,900.94 2144.94,900.94 C1.2@2140.65,896.64 ; 2404.96,1806.21 2414.31,1796.86 U15.3@2450.65,1796.86
  L01-TOP w15: v1(133.14,1859.56) 133.33,1859.75 170.95,1859.75 C114.2@171.14,1859.94 174.14,1856.94 241.07,1856.94 ; C129.2@721.8,1856.07 747.2,1856.07 747.65,1856.53 773.44,1856.53 C128.2@773.51,1856.6 ; C129.2@721.8,1856.46 C129.2@721.87,1856.53 ; C128.2@773.51,1852.81 777.82,1848.5 814.66,1848.5 816.41,1846.76 ; C8.1@1059.53,2205.38 C8.1@1060,2205.85 ; C143.2@1284.11,1855.58 1284.35,1855.82 C144.2@1333.69,1855.84 ; C144.2@1333.69,1855.84 1367.42,1855.84 ; C24.2@1702.14,468.79 1704.97,471.62 1756.19,471.62 C23.2@1759.35,474.78 v1(1800.95,474.78) v1@1800.06,473.88 ; v1(1787.76,2090.05) 1789.03,2090.05 1795.27,2096.29 C158.2@1876.15,2096.29 1903.81,2096.29 ; C174.2@1802.76,1476.36 C173.2@1852.79,1476.36 1881.64,1476.36 ; C188.2@2329.8,1804.18 C188.2@2329.96,1804.35 2330.18,1804.57 2379.87,1804.57 C189.2@2380.09,1804.79 2381.51,1806.21 2404.96,1806.21
  L08-BOTTOM w4: C91.2@1204.1,1078.52 1204.86,1078.52 1211.13,1084.79 1211.13,1135.37 1236.92,1161.16 v2(1239.13,1161.16)
  L08-BOTTOM w5: R36.1@863.73,1252.66 871.07,1245.32 882.49,1245.32 888.46,1239.35 v2(890.89,1239.35) ; C51.2@1317.11,876.53 1330.8,876.53 1341.35,887.07 v2(1341.35,887.66) ; C50.2@1317.32,924.63 1318.13,925.44 v2(1338.87,925.44) ; C67.2@1322.93,1184.5 1325.22,1182.21 v2(1342.92,1182.21) ; C64.2@1324.46,1042.81 1324.93,1043.28 1339.01,1043.28 1344.77,1049.04 1344.77,1054.09 v2(1346.49,1055.82) ; v1(2000.88,1176.13) 2000.88,1211.37 C176.1@2001.92,1212.41 ; v1@2693.64,1907.9 2693.64,1874.31 2694.68,1873.26 C199.2@2694.68,1855.16
  L08-BOTTOM w6: v1(806.19,419.31) 833.49,419.31 833.75,419.56 C203.1@837.51,415.8 846.25,407.06 U16.2@846.25,359.44 ; v2(960.04,802.49) 961.1,803.56 969.6,803.56 980.15,814.11 C92.2@980.15,843.04 1004.78,843.04 C90.2@1004.96,843.22 ; C93.2@961.89,1233.35 979.6,1233.35 983.11,1229.84 983.11,1206.69 v2(983.8,1206) ; C93.2@963.15,1233.96 C89.2@963.15,1257.74 ; C79.2@1029.57,1031.35 1034.83,1036.62 1033.19,1036.62 1032.41,1037.41 1032.41,1049.41 1036.59,1053.59 v2(1036.59,1055.75) 1036.59,1068.51 C76.2@1035.76,1069.34 ; C86.2@1032.93,1098.66 1033.43,1098.15 1041.95,1098.15 1044.32,1100.51 1055.97,1100.51 1059.09,1103.64 1059.09,1078.67 v2(1059.73,1078.04) ; C88.2@1084.43,1056.67 1086.97,1059.21 C78.2@1086.97,1081.79 ; C78.2@1086.56,1081.01 1105.68,1081.01 1108.62,1078.08 v2(1110.78,1078.08) ; C151.2@1650.43,1754.61 1651.57,1753.46 1673.67,1753.46 v1(1674.81,1752.32) ; R128.1@1724.39,1199.42 1724.39,1178.49 1740.7,1162.18 v1(1740.7,1161.59) ; C180.1@1881.81,1152.56 1877.87,1152.56 1869.06,1161.37 1869.06,1176.13 1867.18,1178.02 1867.18,1298.06 1870.69,1301.57 J8.8@1904.73,1301.57 ; v1(1900.48,1647.41) 1932.58,1647.41 R193.1@1933.08,1646.92 ; C183.2@2168.06,1495.5 C184.2@2168.06,1526.16 ; C182.2@2168.27,1409.11 2168.27,1380.44 C181.2@2168.39,1380.31 2172,1376.7 2193.73,1376.7 v1(2196.35,1374.08) ; C184.2@2168.24,1526.34 2167.58,1527.01 2167.58,1551.97 2170.5,1554.89 v1(2170.5,1558.6) ; C167.2@2194.35,2022.6 C166.2@2194.35,1996.22 2195.21,1995.36 2219.09,1995.36 v1(2219.95,1994.49) ; C168.2@2194.35,2111.57 C169.2@2194.35,2144.69 v1(2194.35,2175.1)
  L08-BOTTOM w8: C95.2@341.58,758.22 369.31,758.22 v1(380.67,769.57) ; C107.1@429.26,690.64 429.26,751.23 443.64,765.61 459.82,765.61 v1(461.63,767.41) 478.59,750.45 492.22,750.45 C104.2@504.6,738.07 ; R90.1@579.65,1333.78 608.23,1333.78 620.1,1321.92 v1(623.26,1321.92) ; v8(606.9,747.99) 606.9,725.84 620.69,712.05 664.56,712.05 672.37,704.24 C106.2@672.37,703.57 ; C102.2@686.1,1164.95 712.55,1164.95 723.74,1153.76 v1(723.74,1131.52) ; C137.2@1090.49,1783.43 C136.2@1090.49,1755.16 1094.24,1751.42 1094.24,1753.85 1095.55,1755.16 1116.06,1755.16 1125.58,1745.64 v1(1128.75,1745.64) ; v1(1092.09,1931.16) 1092.29,1930.95 1092.29,1903.43 C139.2@1092.49,1903.23 1092.57,1903.15 1092.57,1875.1 C138.2@1092.64,1875.02 ; C44.2@1095.65,847.12 1095.65,847.86 1110.35,862.56 1119.56,862.56 1136.72,879.71 v2(1136.72,898.04) ; v1(1384.32,2052.98) 1384.44,2053.09 1415.47,2053.09 R161.1@1415.59,2053.21 ; v1(1476.04,1559.94) 1476.81,1560.72 1476.81,1588.75 C146.1@1477.58,1589.52 ; v1(1582.67,734.56) 1583.05,734.94 1617.43,734.94 U2.2@1617.81,735.32 1651.73,735.32 1656.42,730.63 1656.42,685.65 1650.57,679.8 1650.57,670.8 1642.76,662.99 C21.2@1638.85,662.99 ; v1(1641.16,1941.46) 1641.16,1938.3 1651.21,1928.26 1651.21,1905.25 C154.2@1651.68,1904.78 1651.49,1904.59 1651.49,1875.07 C153.2@1651.31,1874.88 ; C151.2@1650.43,1754.61 1650.58,1754.76 1650.58,1783.9 C152.2@1650.74,1784.06 ; C165.1@1903.95,1770.77 1896.14,1778.58 1896.14,1797.53 1892.65,1801.02 1892.65,1912.79 1897.34,1917.48 J7.8@1931.95,1917.48 ; v1(1930.17,2282.61) 1958.29,2282.61 R177.1@1958.86,2283.18 ; v1(2021.14,1791.81) C161.1@2021.14,1830.52 ; C195.1@2409,1480.04 2401.19,1487.85 2401.19,1621.31 2406.86,1626.99 J9.8@2435.34,1626.99 ; v1(2431.33,1994.49) 2432.76,1995.92 R209.1@2463.32,1995.92 ; C191.1@2525.93,1540.2 2525.93,1493.48 2530.62,1488.8 v1(2551.81,1488.8) ; C197.2@2694.68,1732.11 C196.2@2694.68,1707.62 2696.16,1706.13 2717.52,1706.13 2724.1,1699.56 2741.13,1699.56 v3(2743.36,1697.32) ; C198.2@2694.68,1823.56 C199.2@2694.68,1855.16
  L08-BOTTOM w10: v1(235.78,1492.26) 235.78,1494.88 243.92,1503.02 243.92,1525.4 250.73,1532.21 C120.1@254.67,1532.21 ; C120.1@254.76,1532.21 254.76,1557.68 241.25,1571.19 241.25,1664.36 256.67,1679.78 J4.8@278.79,1679.78 ; v1(271.12,2037.77) 272.97,2039.62 272.97,2049.06 284.24,2060.33 R129.1@306.14,2060.33 ; C116.1@368.33,1596.75 369.11,1595.97 369.11,1561.67 v1(369.9,1560.88) ; v1(535.1,1958.61) 535.1,1955.99 539.91,1951.17 539.91,1909.57 539.12,1908.77 C123.2@539.1,1875.91 ; C122.2@537.15,1787.3 537.14,1758.11 537.54,1757.71 541.19,1754.04 558.13,1754.04 560.55,1751.62 v1(563.17,1751.62) ; C135.1@812.8,1529.79 810.89,1531.7 v1(810.89,1559.02) 810.89,1561.64 800.23,1572.31 800.23,1672.46 806.08,1678.31 J5.8@834.7,1678.31 ; v1(824.19,2035.74) 824.54,2036.09 824.54,2050.52 834.21,2060.19 R145.1@856.47,2060.19 ; C85.2@851,844.51 851,875.18 v1(870.02,894.2) ; v1(920.46,1557) 922.31,1558.85 922.31,1591.33 C131.1@924.58,1593.6 ; v2(1213.88,914.34) 1213.88,898.41 C83.2@1221.6,890.7 ; C82.2@1256.8,1087.49 1259.67,1090.35 1259.67,1113.7 v1(1261.52,1115.55) ; C52.2@1317.3,971.9 1320.25,974.85 1320.25,992.41 1323.02,995.18 1365.44,995.18 1369.48,991.14 1399.16,991.14 v3(1399.32,991.3) ; v1(1362.95,1504.13) 1362.95,1525.87 1369.76,1532.68 C150.1@1372.56,1532.68 1372.56,1555.54 1356.04,1572.06 1356.04,1672.38 1363.55,1679.89 J6.8@1395.75,1679.89 ; v1(1366.21,561) 1367.34,559.87 1402.25,559.87 C38.2@1403.37,558.75 ; C180.1@1881.81,1152.56 1883.37,1154.12 1925.62,1154.12 v1(1927.18,1155.69) ; C165.1@1903.95,1770.77 1904.6,1770.12 1942.58,1770.12 v1(1943.23,1769.46) ; C195.1@2409,1480.04 2412.27,1476.77 v1(2412.27,1451.12)
  L08-BOTTOM w15: R47.1@1581.63,875.54 1592.83,864.34 1592.83,851.42 1602.26,841.99 1614.92,841.99 v1(1615.82,841.09) ; C22.2@1758.7,476.06 1759.35,475.42 1800.31,475.42 v1(1800.95,474.78) ; v1(1768.96,813.19) 1768.88,813.27 1768.88,845.56 C43.2@1768.8,845.64 1805.99,845.64 1831.88,871.52 U5.8@1831.88,900.29 U5.7@1831.88,925.88 ; C157.2@1857.74,2120.61 C157.2@1862.59,2125.46
  other v1: 1513.13,256.72 995.69,262.98 1460.31,295.74 1868.35,298.65 1878.62,494.64 2272.29,495.03 1878.07,520.11 2271.74,520.5 1878.07,543.93 2271.74,544.32 1694.76,620.85 1846.98,645.7 1871.35,645.7 1896.82,646.25 2218.23,646.33 2243.7,646.88 2268.07,646.88 1896.82,670.48 1920.64,670.48 2190.56,670.48 2218.2,670.48 2381.74,884.44 584.22,937.53 552.73,969.03 584.22,969.03 615.72,969.03 584.22,1000.53 1611.21,1092.86 172.87,1220.47 274.34,1270.9 482.09,1331.24 133.14,1343.09 2018.45,1376.61 1969.24,1419.33 2018.45,1419.33 2067.66,1419.33 323.34,1461.98 1744.15,1471.28 1768.96,1471.84 1969.24,1471.69 2018.45,1471.69 2067.66,1471.69 1744.43,1500.58 1768.96,1501.28 2018.45,1514.41 2495.93,1747.06 2545.14,1747.06 2594.35,1747.06 2267.59,1796.31 891.21,1796.95 940.42,1796.95 989.63,1796.95 1449.58,1797.41 1498.8,1797.41 1548.01,1797.41 2292.4,1796.86 2495.93,1799.42 2545.14,1799.42 2594.35,1799.42 339.4,1800.3 388.61,1800.3 437.83,1800.3 2267.87,1825.6 2292.13,1825.6 2545.14,1842.13 1225.06,1844.71 1249.88,1845.27 891.21,1849.31 940.42,1849.31 989.63,1849.31 1449.58,1849.77 1498.8,1849.77 1548.01,1849.77 339.4,1852.66 388.61,1852.66 437.83,1852.66 665.47,1853.9 691.43,1854.33 82.66,1858.8 108.33,1859.01 1225.34,1874.01 1249.88,1874.01 665.96,1878.82 691.21,1879.2 82.77,1888.3 108.6,1888.3 940.42,1892.03 1498.8,1892.49 388.61,1895.37 2693.52,1908.02 1992.65,2038.94 2041.86,2038.94 2091.08,2038.94 1762.95,2089.49 1992.65,2091.3 2041.86,2091.3 2091.08,2091.3 1737.39,2118.79 1763.23,2118.79 1790.53,2118.99 2041.86,2134.01 1580.93,2159.18 1540.61,2159.69 1618.71,2159.52 1020.49,2161 1059.53,2161 1099.08,2161.2 1150.49,2161 1189.53,2161 1229.08,2161.2 1280.49,2161 1319.53,2161 1359.08,2161.2 1410.64,2161.2 1449.66,2161 1488.95,2161.2 525.43,2207.78 568.88,2207.78 569.53,2354.87 525.43,2356.28
  other v3: 2070.88,686.6 2051.59,718.09 2090.17,718.09
  other v6: 369.74,2207.78 307.94,2243.46 431.54,2243.46 307.94,2314.82 431.54,2314.82 369.74,2350.5
GVDD1: C117.2 R127.2 U10.10 | length 778.7
  L01-TOP w8: C117.2@378.69,1663.83 378.69,1712.23 U10.10@378.77,1712.3
  L01-TOP w10: v1(329.43,1653.76) 332.05,1653.76 336.61,1658.33 374.63,1658.33 C117.2@374.71,1658.41 ; C117.2@376.17,1661.31 C117.2@378.69,1663.83
  L03-SIG w5: v1(272.18,1967.69) 323.81,1916.07 452.04,1916.07 476.9,1891.2 476.9,1683.4 447.26,1653.76 v1(329.43,1653.76)
  L08-BOTTOM w6: v1(272.18,1967.69) 272.18,1936.99 288.84,1920.33 297.33,1920.33 306.14,1911.52 R127.2@306.14,1911.27
GVDD2: C132.2 R144.2 U11.10 | length 784.7
  L01-TOP w8: C132.2@927.33,1654.77 930.62,1658.06 U11.10@930.62,1708.92
  L01-TOP w10: v1(884.37,1657.88) 886.99,1657.88 890.37,1654.5 C132.2@927.06,1654.5
  L03-SIG w5: v1(821.82,1964.83) 821.82,1938.93 847.79,1912.96 997.56,1912.96 1015.15,1895.37 1015.15,1667.04 996.35,1648.24 894.64,1648.24 885,1657.88 v1(884.37,1657.88)
  L08-BOTTOM w6: v1(821.82,1964.83) 821.82,1938.93 830.88,1929.87 R144.2@856.68,1929.87 R144.2@865.47,1921.08
GVDD3: C147.2 R160.2 U12.10 | length 744.5
  L01-TOP w6: v1(1446.58,1653.44) 1448.92,1651.09 1481.93,1651.09 C147.2@1484.27,1648.75
  L01-TOP w8: C147.2@1484.27,1648.75 1488.95,1653.44 U12.10@1488.95,1709.42
  L03-SIG w6: v1(1382.2,1967.01) 1419.23,1929.98 1550.48,1929.98 1570.98,1909.48 1570.98,1735.76 1548.15,1712.93 1498.68,1712.93 1486.54,1700.79 1486.54,1655.71 1481.93,1651.09 1448.92,1651.09 v1(1446.58,1653.44)
  L08-BOTTOM w6: v1(1382.2,1967.01) 1384.02,1965.19 1384.02,1936.41 1398.16,1922.26 R160.2@1415.93,1922.26
GVDD4: C162.2 R176.2 U13.10 | length 815.3
  L01-TOP w6: v3(1981.4,1890.69) 1981.48,1890.77 2031.94,1890.77 C162.2@2032.02,1890.85 U13.10@2032.02,1950.94
  L03-SIG w5: v1(1924.99,2215.36) 1924.99,2172.59 1943.93,2153.65 2090.39,2153.65 2110.64,2133.39 2110.64,1901.1 2100.23,1890.69 v3(1981.4,1890.69)
  L08-BOTTOM w6: v1(1924.99,2215.36) 1924.99,2161.68 1935.19,2151.48 R176.2@1958.86,2151.48 R176.2@1958.86,2149.27
GVDD5: C177.2 R192.2 U14.10 | length 661
  L01-TOP w6: v1(1968.35,1275.73) C177.2@2008.99,1275.67 ; U14.10@2008.61,1331.34 2008.61,1276.05 C177.2@2008.99,1275.67
  L08-BOTTOM w5: R192.2@1932.82,1514.66 1951.68,1514.66 1982.87,1545.85 2071.78,1545.85 2104.81,1512.81 2104.81,1352.05 2083.76,1331 1978.12,1331 1968.35,1321.23 v1(1968.35,1275.73)
  L08-BOTTOM w6: R192.2@1932.82,1514.66 R192.2@1940.22,1507.26
GVDD6: C192.2 R208.2 U15.10 | length 761.8
  L01-TOP w6: v3(2488.63,1601.9) C192.2@2535.54,1601.9 2535.3,1602.15 U15.10@2535.3,1659.06
  L06-SIG w5: v1(2427.45,1921.87) 2427.45,1888.68 2464.51,1851.61 2464.51,1687.51 2487.02,1665 2599.66,1665 2606.3,1658.36 2606.3,1607.68 2600.53,1601.9 v3(2488.63,1601.9)
  L08-BOTTOM w6: v1(2427.45,1921.87) 2427.45,1879.98 2443.84,1863.58 R208.2@2462.11,1863.58
H0_RD_N: J3.3 L11.2 | length 182.9
  L01-TOP w4.25: L11.2@531.31,537.16 541.15,537.16 550.84,527.48 550.84,525.57 553.33,523.08 563.17,523.08 586.75,499.49 586.75,408.8 589.24,406.31 J3.3@605.75,406.31
H0_RD_P: J3.4 L11.3 | length 164.3
  L01-TOP w4.25: L11.3@531.31,497.79 541.15,497.79 550.84,507.48 550.84,509.39 553.33,511.88 558.53,511.88 575.55,494.86 575.55,408.8 573.06,406.31 J3.4@556.54,406.31
H0_TD_N: J3.1 L12.2 | length 262.8
  L01-TOP w4.25: J3.1@704.18,406.31 687.66,406.31 685.17,408.8 685.17,440.35 695.86,451.04 767.84,451.04 792.28,475.47 792.28,514.39 783.23,523.44 774.31,523.44 771.83,525.93 771.83,527.84 762.14,537.52 L12.2@752.3,537.52
H0_TD_P: J3.2 L12.3 | length 244.3
  L01-TOP w4.25: J3.2@654.97,406.31 671.48,406.31 673.97,408.8 673.97,444.99 691.22,462.24 763.21,462.24 781.08,480.11 781.08,509.75 778.59,512.24 774.31,512.24 771.83,509.75 771.83,507.84 762.14,498.15 L12.3@752.3,498.15
I2CA_SCL: R68.1 U3.2 U4.H12 U6.3 | length 7542.9
  L01-TOP w4: v1(631.37,1237.3) 632.24,1238.17 632.24,1271.84 U6.3@633.1,1272.7 ; v2(1036.09,1289.2) 1036.42,1289.53 1036.42,1300.73 1040.69,1305.01 1040.69,1311.97 R68.1@1046.11,1317.39 ; v2@1036.42,1289.2 1037.8,1287.82 1037.8,1280.2 1060.77,1257.23 1060.77,1205.51 U4.H12@1072.68,1193.6
  L01-TOP w5: v2(1524.81,366.21) 1526.25,367.65 1526.25,389.98 U3.2@1527.69,391.42
  L03-SIG w4: v1(631.37,1237.3) 631.37,1299.15 680.31,1348.09 977.53,1348.09 1036.09,1289.53 v2(1036.09,1289.2)
  L06-SIG w4: v1(631.37,1237.3) 631.37,1270.29 548.61,1353.05 228.43,1353.05 82.66,1498.83 82.66,1667.77 45.68,1704.76 45.68,2037.8 134.47,2126.59 1628.2,2126.59 1698.44,2196.84 1698.44,2218.69 1820.02,2340.27 2164.27,2340.27 2265.78,2238.76 2547.37,2238.76 2747.25,2038.88 2747.25,1910.33 2712.72,1875.8 2712.72,1700.7 2733.42,1680 2750.88,1680 2758.78,1672.1 2758.78,1602.96 2742.56,1586.75 2742.56,1512.3 2345.15,1114.89 2345.15,1012.6 2323.7,991.14 2138.96,991.14 2114.46,1015.64 1831.24,1015.64 1806.49,990.89 1806.49,593.82 1713.44,500.77 1576.28,500.77 1524.81,449.29 v2(1524.81,366.21)
I2CA_SDA: R69.1 U3.3 U4.A9 U6.4 | length 7416
  L01-TOP w4: U6.4@652.78,1272.7 655.42,1270.07 655.42,1240.77 v1(657,1239.19) ; v2(869.58,1117.54) 869.93,1117.19 893.19,1117.19 U4.A9@893.54,1116.83
  L01-TOP w5: v2(1542.89,351.61) 1544.07,352.8 1544.07,373.06 1544.95,373.93 1544.95,389 U3.3@1547.37,391.42
  L06-SIG w4: v2(869.58,1117.54) 847.25,1117.54 830.61,1100.91 783.51,1100.91 776.64,1107.77 776.64,1113.28 776.6,1113.33 776.6,1206.3 766.11,1216.79 703.47,1216.79 681.07,1239.19 v1(657,1239.19) 657,1352.25 605.24,1404.01 492.67,1404.01 454.4,1365.74 231.85,1365.74 93.48,1504.1 93.48,1676.99 56.39,1714.07 56.39,2031.32 141.01,2115.94 1631.52,2115.94 1709.43,2193.85 1709.43,2214.82 1826.88,2332.27 2141.37,2332.27 2245.72,2227.92 2541.66,2227.92 2739.25,2030.33 2739.25,1913.64 2704.72,1879.11 2704.72,1697.39 2730.11,1672 2745.91,1672 2750.78,1667.13 2750.78,1606.27 2734.56,1590.06 2734.56,1519.25 2334.37,1119.06 2334.37,1017.91 2316.07,999.61 2145.03,999.61 2121,1023.64 1827.93,1023.64 1798.13,993.84 1798.13,596.77 1710.12,508.77 1572.97,508.77 1510.02,445.82 1510.02,341.78 1516.93,334.86 1538.25,334.86 1542.89,339.51 v2(1542.89,351.61)
  L08-BOTTOM w5: R69.1@1542.56,325.18 1542.89,325.51 v2(1542.89,351.61)
I_A1: R48.1 U10.27 | length 1959.5
  L01-TOP w5: U10.27@339.4,1940.65 339.57,1940.82 339.57,1968.47 v3(339.74,1968.64)
  L03-SIG w4: v3(339.74,1968.64) 339.74,2004.37 346.35,2010.99 383.77,2010.99 410.55,1984.21 410.55,1955.49 422.13,1943.91 501.87,1943.91 600.91,1844.87 600.91,1615.91 626.03,1590.79 994.96,1590.79 1179.47,1406.27 1179.47,1340.64 1243.45,1276.66 1243.45,1259.25 1288.41,1214.29 1288.41,926.59 1311.38,903.62 1357.95,903.62 v3(1360.61,906.28)
  L08-BOTTOM w4: R48.1@1318.01,902.59 1321.7,906.28 v3(1360.61,906.28)
I_A2: R51.1 U11.27 | length 1514
  L01-TOP w5: U11.27@891.21,1937.31 v3@891.17,1964.47
  L03-SIG w4: v3(891.14,1964.5) 891.14,1946.69 914.23,1923.6 1010.74,1923.6 1024.63,1909.71 1024.63,1653.61 1399.04,1279.2 1399.04,1031.43 1357,989.39 1357,950.52 1396.08,911.44 1396.08,864.19 v3(1375.9,844)
  L08-BOTTOM w4: R51.1@1325.63,852.15 1330.18,856.69 1358.96,856.69 1371.66,844 v3(1375.9,844)
I_A3: R54.1 U12.27 | length 1357.6
  L01-TOP w5: U12.27@1449.58,1937.76 1449.66,1937.84 1449.66,1966.88 v3(1449.74,1966.96)
  L08-BOTTOM w4: R54.1@1317.54,948.4 1399.59,948.4 1418.77,967.58 1418.77,1085.98 1443.58,1110.79 1443.58,1313.48 1594.79,1464.69 1594.79,1905.76 1578.57,1921.98 1527.71,1921.98 1511.85,1937.84 1511.85,1975.29 1501.16,1985.99 1482.32,1985.99 1466.29,1969.96 1452.74,1969.96 v3(1449.74,1966.96)
I_A4: R57.1 U13.27 | length 2354.2
  L01-TOP w4: v3(1183.65,721.39) 1184.12,721.87 1210.67,721.87 1221.23,732.43 1221.23,754.7 R57.1@1221.81,755.28
  L01-TOP w5: U13.27@1992.65,2179.29 v3(1992.65,2208.75)
  L03-SIG w4: v3(1183.65,721.39) 1183.82,721.22 1199.49,721.22 1222.58,698.13 1446.84,698.13 1544.76,796.06 1544.76,1409.58 1686.79,1551.61 1686.79,1616 1907.04,1836.25 2075.52,1836.25 2119.14,1879.88 2119.14,2139.36 2092.49,2166.02 2013.12,2166.02 1992.65,2186.49 v3(1992.65,2208.75)
I_A5: R60.1 U14.27 | length 1962.1
  L01-TOP w4: R60.1@1072.88,769.62 1073.34,769.62 1079.61,763.36 1079.61,755.7 1125.36,709.94 v1(1154.52,709.94)
  L01-TOP w6: U14.27@1969.24,1559.68 1969.46,1559.91 v3(1969.46,1589.36)
  L03-SIG w4: v1(1154.52,709.94) 1154.39,709.81 1154.39,692.22 1211.54,635.08 1562.85,635.08 1634.48,706.7 1634.48,1216.5 1727.53,1309.55 1861.18,1309.55 1904.29,1352.66 2037.51,1352.66 2048,1363.16 2048,1539.98 2028.07,1559.91 1981.16,1559.91 1969.46,1571.61 v3(1969.46,1589.36)
I_A6: R63.1 U15.27 | length 2685.8
  L01-TOP w4: R63.1@1106.2,808.68 1112.47,802.41 1112.47,765.25 v3(1142.43,735.28) ; U15.27@2496.07,1887.55 2496.3,1887.78 2496.3,1918.63 v3(2496.67,1919)
  L01-TOP w5: U15.27@2495.93,1887.41 U15.27@2496.07,1887.55
  L06-SIG w4: v3(1142.43,735.28) 1166.39,735.28 1214.64,783.53 1366.2,783.53 1415.04,832.37 1415.04,1009.39 1446.61,1040.97 2121.28,1040.97 2464.51,1384.2 2583.01,1384.2 2723.41,1524.6 2723.41,1591.49 2643.9,1671.01 2643.9,1860.64 2611.54,1892.99 2500.54,1892.99 2496.07,1897.46 2496.07,1918.4 v3(2496.67,1919)
I_B1: R49.1 U10.26 | length 1992.4
  L01-TOP w4: v3(359,1992.8) v3(359,1992.8) 359.04,1940.69 U10.26@359.09,1940.65 ; R49.1@1324.14,829.53 1330.29,823.38 1330.29,819.99 1332.64,817.65 1361.65,817.65 v3(1362.42,816.89)
  L03-SIG w4: v3(359,1992.8) 359.66,1993.46 385,1993.46 398.46,1980.01 398.46,1946.84 410.11,1935.19 499.28,1935.19 592.91,1841.56 592.91,1612.6 622.72,1582.79 991.64,1582.79 1171.47,1402.96 1171.47,1337.32 1235.45,1273.35 1235.45,1253.72 1280.41,1208.76 1280.41,867.04 1330.57,816.89 v3(1362.42,816.89)
I_B2: R52.1 U11.26 | length 1654.2
  L01-TOP w5: v3(907.38,1987.88) 909.14,1986.12 909.14,1939.06 U11.26@910.89,1937.31 ; v3(1312.28,756.42) R52.1@1312.28,780.43
  L03-SIG w4: v3(907.38,1987.88) 907.38,1954.02 929.8,1931.6 1019.67,1931.6 1035.2,1916.07 1035.2,1655.77 1407.04,1283.93 1407.04,1028.11 1383.78,1004.85 1383.78,935.06 1404.08,914.75 1404.08,795.29 1365.22,756.42 v3(1312.28,756.42)
I_B3: R55.1 U12.26 | length 1469
  L01-TOP w4: R55.1@1295.84,878.4 1300.12,874.12 v3(1365.96,874.12)
  L01-TOP w5: v3(1468.5,1997) 1468.89,1996.62 1468.89,1938.15 U12.26@1469.27,1937.76
  L08-BOTTOM w4: v3(1365.96,874.12) 1366.6,873.48 1384.89,873.48 1416.98,905.58 1416.98,954.47 1426.77,964.27 1426.77,1082.67 1451.58,1107.48 1451.58,1310.16 1602.79,1461.37 1602.79,1912.35 1585.16,1929.98 1534.57,1929.98 1522.35,1942.2 1522.35,1976.11 1501.46,1997 v3(1468.5,1997)
I_B4: R58.1 U13.26 | length 1872.1
  L01-TOP w4: v3(1366.65,1027.43) 1442.73,1027.43 1525.93,1110.64 1562.61,1110.64 v1(1563.24,1110.01)
  L01-TOP w5: v3(2009.68,2231.74) 2011.01,2230.41 2011.01,2180.62 U13.26@2012.34,2179.29
  L03-SIG w4: v1(1563.24,1110.01) 1563.1,1110.14 1563.1,1416.61 1694.79,1548.29 1694.79,1612.69 1910.35,1828.25 2079.54,1828.25 2127.14,1875.86 2127.14,2143.38 2096.51,2174.02 2029.98,2174.02 2009.68,2194.32 v3(2009.68,2231.74)
  L08-BOTTOM w4: R58.1@1325.1,1018.91 1353.88,1018.91 1362.41,1027.43 v3(1366.65,1027.43)
I_B5: R61.1 TP24.1 U14.26 | length 1952.4
  L01-TOP w4: R61.1@1317.73,1133.48 1323.55,1127.65 1423.65,1127.65 1424.81,1126.49 1644.21,1126.49 1710.36,1060.35 2147.37,1060.35 2275.04,1188.01 2275.04,1488.51 2245.06,1518.49 2245.06,1578.2 2091.5,1731.77 1990.76,1731.77 1966.49,1707.49 1966.49,1627.96 1988.96,1605.49 U14.26@1988.96,1559.72
I_B6: R64.1 U15.26 | length 2299.7
  L01-TOP w4: v3(2512.49,1954.69) 2514.05,1953.13 2514.05,1888.97 U15.26@2515.61,1887.41
  L01-TOP w5: R64.1@1316.41,1084.52 1320.22,1088.32 v3(1348.77,1088.32)
  L06-SIG w4: v3(1348.77,1088.32) 1380.13,1056.97 2114.65,1056.97 2457.88,1400.2 2576.39,1400.2 2707.41,1531.23 2707.41,1584.86 2627.9,1664.38 2627.9,1854.01 2604.91,1876.99 2487.02,1876.99 2467.14,1896.88 2467.14,1939.12 2483.71,1955.7 2511.49,1955.7 v3(2512.49,1954.69)
I_C1: R50.1 U10.25 | length 1849.7
  L01-TOP w4: v3@869.01,808.78 R50.1@898.1,808.78
  L01-TOP w5: U10.25@378.77,1940.65 379.31,1941.19 379.31,1967.81 v3(379.86,1968.35)
  L03-SIG w4: v3(379.86,1968.35) 379.86,1947.9 401.07,1926.69 496.47,1926.69 584.91,1838.25 584.91,1529.19 390.66,1334.94 390.66,1162.76 431.53,1121.89 431.53,890.62 519.68,802.46 858.62,802.46 865.14,808.99 v3(868.81,808.99)
I_C2: R53.1 U11.25 | length 2074.7
  L01-TOP w4: R53.1@1008.39,805.97 1005.36,802.94 1005.36,793.26 981.01,768.9 981.01,715.4 1021.57,674.83 1249.8,674.83 1280.69,705.72 v3(1280.69,730.11)
  L01-TOP w5: U11.25@930.58,1937.31 v3(930.58,1964.5)
  L03-SIG w4: v3(930.58,1964.5) 930.82,1964.26 930.82,1950.21 941.44,1939.6 1027.29,1939.6 1044.2,1922.69 1044.2,1659.5 1415.04,1288.66 1415.04,777.47 1367.68,730.11 v3(1280.69,730.11)
I_C3: R56.1 U12.25 | length 1144.8
  L01-TOP w5: U12.25@1488.95,1937.76 U12.25@1488.95,1937.76 1489,1966.83 v3(1489.05,1966.88)
  L08-BOTTOM w4: R56.1@1324.07,1067.94 1328.91,1072.78 1394.26,1072.78 1435.58,1114.1 1435.58,1316.79 1586.79,1468 1586.79,1897.76 1570.57,1913.98 1520.92,1913.98 1489.02,1945.89 v3@1489.02,1966.85
I_C4: R59.1 U13.25 | length 2414.1
  L01-TOP w4: R59.1@1052.63,712.15 1052.63,711.84 1058.89,705.57 1067.62,705.57 1081.09,692.1 1182.84,692.1 v3(1183.21,692.47)
  L01-TOP w5: v3(2031.65,2207.45) 2031.83,2207.27 2031.83,2179.48 U13.25@2032.02,2179.29
  L03-SIG w4: v3(1183.21,692.47) 1185.86,689.83 1449.85,689.83 1581.53,821.5 1581.53,1422.72 1702.79,1543.98 1702.79,1609.37 1913.67,1820.25 2082.85,1820.25 2135.14,1872.55 2135.14,2146.7 2099.82,2182.02 2039.45,2182.02 2031.65,2189.83 v3(2031.65,2207.45)
I_C5: R62.1 TP25.1 U14.25 | length 1928.4
  L01-TOP w4: v3(1379.54,1164.42) 1381.87,1166.76 1560.77,1166.76 TP25.1@1563.1,1169.09 1612.93,1169.09 1713.67,1068.35 2144.06,1068.35 2267.04,1191.33 2267.04,1485.2 2237.06,1515.18 2237.06,1574.89 2088.18,1723.77 1994.07,1723.77 1974.49,1704.18 1974.49,1631.28 1986,1619.76 1986.12,1619.76 2008.61,1597.27 U14.25@2008.61,1559.68
  L08-BOTTOM w4: R62.1@1322.76,1158.31 1328.65,1164.2 1379.32,1164.2 v3(1379.54,1164.42)
I_C6: R65.1 U15.25 | length 2503.7
  L01-TOP w4: U15.25@2535.3,1887.41 2535.42,1887.53 2535.42,1918.41 v3(2535.54,1918.53)
  L06-SIG w4: v3(1365.79,1193.34) 1364.54,1193.34 1352.55,1205.33 1335.65,1205.33 1318.73,1188.4 1318.73,1086.57 1334.57,1070.73 1354.95,1070.73 1376.71,1048.97 2117.96,1048.97 2461.2,1392.2 2579.7,1392.2 2715.41,1527.91 2715.41,1588.18 2635.9,1667.69 2635.9,1857.32 2608.22,1884.99 2493.27,1884.99 2475.14,1903.13 2475.14,1929.41 2483.83,1938.1 2529.42,1938.1 2535.5,1932.03 2535.5,1918.57 v3(2535.54,1918.53)
  L08-BOTTOM w5: R65.1@1322.26,1209.42 1353.82,1209.42 1357.36,1205.89 1357.36,1205.75 1365.79,1197.31 v3(1365.79,1193.34)
INHA1: C118.1 R114.2 U10.14 | length 97.5
  L01-TOP w5: U10.14@457.51,1712.3 457.51,1699.23 460.44,1696.3 475.32,1696.3 491.73,1679.9 C118.1@491.73,1660.2 491.83,1660.3 R114.2@514.14,1660.3
INHA2: C133.1 R132.2 U11.14 | length 84.1
  L01-TOP w5: U11.14@1009.32,1708.96 1011.74,1706.54 1011.74,1694.33 1014.67,1691.4 1026.79,1691.4 1036.73,1681.46 1036.73,1677.54 1042.5,1671.78 C133.1@1043.29,1671.78 R132.2@1043.29,1646.54
INHA3: C148.1 R148.2 U12.14 | length 140.8
  L01-TOP w5: U12.14@1567.69,1709.42 1569.01,1708.1 1569.01,1687.13 1571.94,1684.2 1580.2,1684.2 1603.96,1660.43 C148.1@1625.74,1660.43 1625.74,1637.75 1618.89,1630.9 1606.88,1630.9 R148.2@1602.79,1626.82
INHA4: C163.1 R164.2 U13.14 | length 104
  L01-TOP w5: U13.14@2110.76,1950.94 2112.41,1949.3 2112.41,1934.26 2120.05,1926.62 2134.93,1926.62 2147.12,1914.44 2147.12,1897.77 C163.1@2147.78,1897.11 ; C163.1@2147.98,1896.91 R164.2@2174.08,1896.91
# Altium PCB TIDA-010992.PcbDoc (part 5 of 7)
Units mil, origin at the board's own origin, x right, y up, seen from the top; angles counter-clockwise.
Board outline 2810.81 x 2427 mil, 8 copper layers (L01-TOP, L02-GND, L03-SIG, L04-GND, L05-PWR, L06-SIG, L07-GND, L08-BOTTOM), stack 61.9 mil thick; 521 components, 377 nets, 1545 pads, 874 vias.

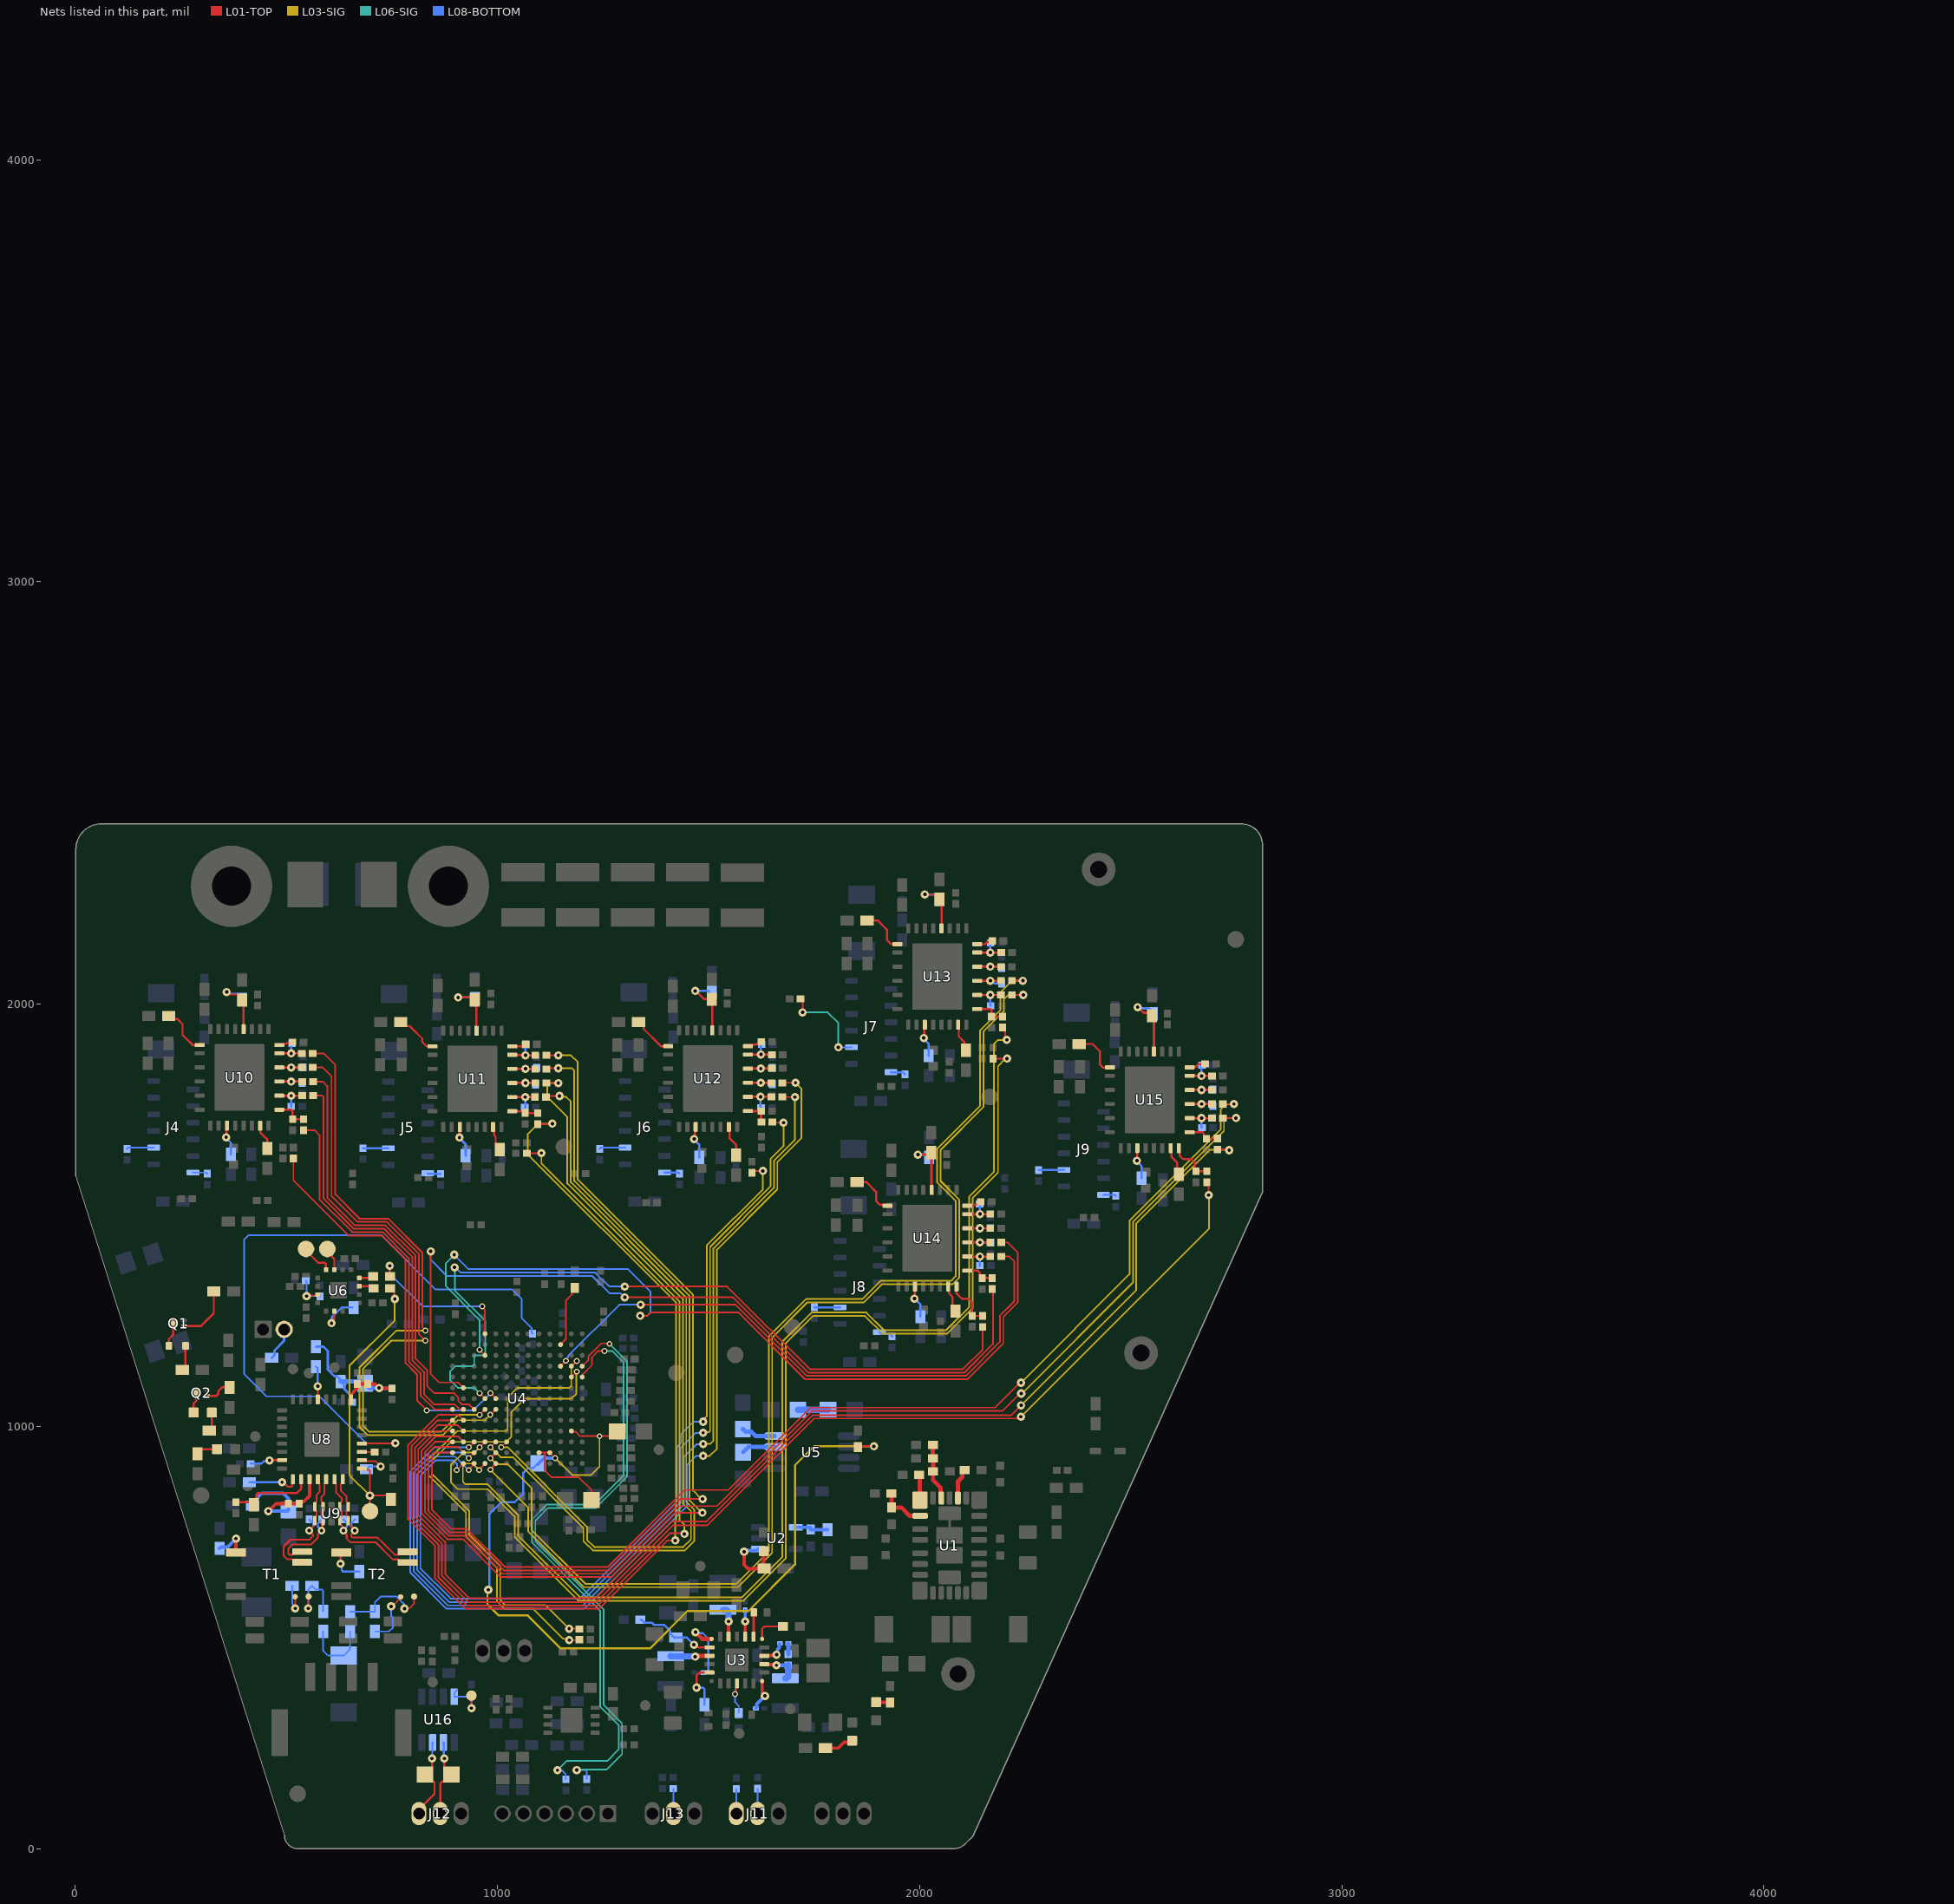
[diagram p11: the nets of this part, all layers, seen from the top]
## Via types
v1: diameter 19.68, hole 8, L01-TOP to L08-BOTTOM, tented both sides, 520 vias
v2: diameter 14, hole 8, L01-TOP to L08-BOTTOM, tented both sides, 146 vias
v3: diameter 19.68, hole 8, L01-TOP to L08-BOTTOM, 141 vias
v4: diameter 30, hole 18, L01-TOP to L08-BOTTOM, 18 vias
v5: diameter 22, hole 8, L01-TOP to L08-BOTTOM, tented both sides, 16 vias
v6: diameter 39.37, hole 19.68, L01-TOP to L08-BOTTOM, 12 vias
v7: diameter 22, hole 8, L01-TOP to L08-BOTTOM, 8 vias
v8: diameter 18, hole 8, L01-TOP to L08-BOTTOM, tented both sides, 5 vias
v9: diameter 14, hole 8, L01-TOP to L08-BOTTOM, 4 vias
v10: diameter 157.48, hole 98.43, L01-TOP to L08-BOTTOM, 4 vias

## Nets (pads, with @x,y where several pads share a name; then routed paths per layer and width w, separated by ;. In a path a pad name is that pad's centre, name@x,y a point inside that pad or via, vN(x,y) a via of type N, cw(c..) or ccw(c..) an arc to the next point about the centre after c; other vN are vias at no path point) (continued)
INHA5: C178.1 R180.2 U14.14 | length 119.3
  L01-TOP w5: U14.14@2087.35,1331.34 2087.35,1314.7 2099.91,1302.13 2116,1302.13 2124.44,1293.69 C178.1@2124.44,1261.66 ; C178.1@2124.57,1261.53 R180.2@2149.4,1261.53
INHA6: C193.1 R196.2 U15.14 | length 109.1
  L01-TOP w5: U15.14@2614.04,1659.06 2616.46,1656.64 2616.46,1640.28 2623.89,1632.85 2643.84,1632.85 2651.61,1625.08 2651.61,1607.42 2655,1604.03 R196.2@2680.37,1604.03
INHB1: C121.1 R117.2 U10.16 | length 79.7
  L01-TOP w5: U10.16@483.1,1783.17 537.01,1783.17 R117.2@537.15,1783.3
  L08-BOTTOM w5: C121.1@511.15,1757.3 511.29,1757.44 v1(511.29,1782.83)
INHB2: C136.1 R135.2 U11.16 | length 78.8
  L01-TOP w5: U11.16@1034.91,1779.83 v1(1065.72,1779.83) R135.2@1088.51,1779.83
  L08-BOTTOM w5: C136.1@1064.51,1755.16 1065.72,1756.37 v1(1065.72,1779.83)
INHB3: C151.1 R151.2 U12.16 | length 82.5
  L01-TOP w5: U12.16@1593.28,1780.28 1593.56,1780.56 v1(1622.96,1780.56) 1648.25,1780.56 R151.2@1648.83,1779.98
  L08-BOTTOM w5: v1(1622.96,1780.56) 1622.96,1756.09 C151.1@1624.44,1754.61
INHB4: C166.1 R167.2 U13.16 | length 82.1
  L01-TOP w5: U13.16@2136.35,2021.81 v1(2167.27,2021.81) R167.2@2192.36,2021.81
  L08-BOTTOM w5: v1(2167.27,2021.81) 2167.27,1997.31 C166.1@2168.36,1996.22
INHB5: C181.1 R183.2 U14.16 | length 76.4
  L01-TOP w5: U14.16@2112.94,1402.2 R183.2@2167.31,1402.2
  L08-BOTTOM w5: C181.1@2142.41,1380.31 2142.69,1380.6 v1(2142.69,1402.2)
INHB6: C196.1 R199.2 U15.16 | length 75.7
  L01-TOP w5: U15.16@2639.63,1729.93 v1(2667.65,1729.93) R199.2@2692.61,1729.93
  L08-BOTTOM w5: v1(2667.65,1729.93) 2667.65,1708.67 C196.1@2668.7,1707.62
INHC1: C123.1 R123.2 U10.18 | length 80.9
  L01-TOP w5: U10.18@483.1,1850.1 v1(511.29,1850.1) R123.2@536.15,1850.1
  L08-BOTTOM w5: v1(511.29,1850.1) 538.93,1850.1 C123.1@539.1,1849.93
INHC2: C138.1 R141.2 U11.18 | length 82.3
  L01-TOP w5: U11.18@1034.91,1846.76 v1(1066.11,1846.76) 1089.41,1846.76 R141.2@1089.62,1846.55
  L08-BOTTOM w5: v1(1066.11,1846.76) 1090.36,1846.76 C138.1@1092.64,1849.04
INHC3: C153.1 R157.2 U12.18 | length 84.9
  L01-TOP w5: U12.18@1593.28,1847.21 v1(1623.84,1847.21) 1648.8,1847.21 R157.2@1649.66,1848.07
  L08-BOTTOM w5: v1(1623.84,1847.21) 1649.62,1847.21 C153.1@1651.31,1848.9
INHC4: C168.1 R173.2 U13.18 | length 84.7
  L01-TOP w5: U13.18@2136.35,2088.74 v1(2167.27,2088.74) R173.2@2192.69,2088.74
  L08-BOTTOM w5: v1(2167.27,2088.74) 2191.2,2088.74 C168.1@2194.35,2085.59
INHC5: C183.1 R189.2 U14.18 | length 79.2
  L01-TOP w5: U14.18@2113.47,1469.13 v1(2142.84,1469.13) R189.2@2167.31,1469.13
  L08-BOTTOM w5: v1(2142.84,1469.13) 2167.68,1469.13 C183.1@2168.06,1469.52
INHC6: C198.1 R205.2 U15.18 | length 80.5
  L01-TOP w5: U15.18@2639.63,1796.86 v1(2667.65,1796.86) 2692.13,1796.86 R205.2@2692.61,1796.38
  L08-BOTTOM w5: v1(2667.65,1796.86) 2693.96,1796.86 C198.1@2694.68,1797.58
INLA1: C119.1 R115.2 U10.15 | length 78.2
  L01-TOP w5: U10.15@483.1,1749.71 511.81,1749.71 514.74,1746.78 C119.1@514.74,1727.42 ; C119.1@514.85,1727.3 R115.2@540.86,1727.3
INLA2: C134.1 R133.2 U11.15 | length 62.1
  L01-TOP w5: U11.15@1034.91,1746.36 1061.63,1746.36 C134.1@1065.82,1742.17 ; C134.1@1065.72,1742.07 1066.15,1741.64 R133.2@1094.96,1741.64
INLA3: C149.1 R149.2 U12.15 | length 57.5
  L01-TOP w6: U12.15@1593.28,1746.82 1593.37,1746.74 1624.54,1746.74 C149.1@1624.62,1746.65 1624.62,1721.38 R149.2@1625.19,1720.82
INLA4: C164.1 R165.2 U13.15 | length 72.9
  L01-TOP w5: U13.15@2136.35,1988.34 2167.27,1988.34 2170.2,1985.42 C164.1@2170.2,1970.22 2192.43,1970.22 R165.2@2192.7,1970.5
INLA5: C179.1 R181.2 U14.15 | length 70.6
  L01-TOP w5: U14.15@2112.94,1368.74 2137.64,1368.74 2142.84,1363.53 2142.84,1356.17 C179.1@2148.13,1350.89 2148.43,1351.19 R181.2@2171.68,1351.19
INLA6: C194.1 R197.2 U15.15 | length 77.1
  L01-TOP w5: U15.15@2639.63,1696.47 2670.09,1696.47 2673.02,1693.54 2673.02,1687.92 2679.55,1681.39 C194.1@2680.88,1681.39 ; C194.1@2679.1,1681.68 R197.2@2705.41,1681.68
INLB1: C122.1 R118.2 U10.17 | length 81.3
  L01-TOP w5: U10.17@483.1,1816.63 v1(511.29,1816.63) R118.2@537.15,1816.63
  L08-BOTTOM w5: v1(511.29,1816.63) 533.8,1816.63 C122.1@537.15,1813.29
INLB2: C137.1 R136.2 U11.17 | length 80.8
  L01-TOP w5: U11.17@1034.91,1813.29 v1(1066.11,1813.29) 1089.31,1813.29 R136.2@1089.62,1812.98
  L08-BOTTOM w5: v1(1066.11,1813.29) 1086.62,1813.29 C137.1@1090.49,1809.42
INLB3: C152.1 R152.2 U12.17 | length 84.1
  L01-TOP w5: U12.17@1593.28,1813.75 v1(1623.84,1813.75) 1648.65,1813.75 R152.2@1648.83,1813.57
  L08-BOTTOM w5: v1(1623.84,1813.75) 1647.03,1813.75 C152.1@1650.74,1810.04
INLB4: C167.1 R168.2 U13.17 | length 86.2
  L01-TOP w5: U13.17@2136.35,2055.27 v1(2167.27,2055.27) R168.2@2192.69,2055.27
  L08-BOTTOM w5: v1(2167.27,2055.27) 2170.85,2055.27 2177.54,2048.58 C167.1@2194.35,2048.58
INLB5: C182.1 R184.2 U14.17 | length 79.5
  L01-TOP w5: U14.17@2113.47,1435.67 v1(2142.84,1435.67) R184.2@2167.31,1435.67
  L08-BOTTOM w5: v1(2142.84,1435.67) 2167.69,1435.67 C182.1@2168.27,1435.09
INLB6: C197.1 R200.2 U15.17 | length 82.2
  L01-TOP w5: U15.17@2639.63,1763.39 v1(2667.65,1763.39) 2692.56,1763.39 R200.2@2692.61,1763.35
  L08-BOTTOM w5: v1(2667.65,1763.39) 2689.38,1763.39 C197.1@2694.68,1758.09
INLC1: C124.1 R125.2 U10.19 | length 76.9
  L01-TOP w5: U10.19@483.1,1883.56 535.89,1883.56 R125.2@536.15,1883.3
  L08-BOTTOM w5: v1(511.29,1883.3) 511.29,1904.44 C124.1@513.15,1906.3
INLC2: C139.1 R143.2 U11.19 | length 80
  L01-TOP w5: U11.19@1034.91,1880.22 1035.62,1879.51 1065.4,1879.51 v1(1066.11,1878.79) 1089.33,1878.79 R143.2@1089.62,1879.09
  L08-BOTTOM w5: v1(1066.11,1878.79) 1066.11,1902.83 C139.1@1066.51,1903.23
INLC3: C154.1 R159.2 U12.19 | length 81.3
  L01-TOP w5: U12.19@1593.28,1880.68 v1(1624.09,1880.68) 1649.29,1880.68 R159.2@1649.66,1880.31
  L08-BOTTOM w5: v1(1624.09,1880.68) 1624.09,1903.18 C154.1@1625.69,1904.78
INLC4: C169.1 R175.2 U13.19 | length 79.7
  L01-TOP w5: U13.19@2136.35,2122.2 U13.19@2136.35,2122.2 2167.23,2122.24 v1(2167.27,2122.28) 2193.09,2122.28 R175.2@2193.16,2122.2
  L08-BOTTOM w5: v1(2167.27,2122.28) 2167.27,2143.6 C169.1@2168.36,2144.69
INLC5: C184.1 R191.2 U14.19 | length 77.8
  L01-TOP w5: U14.19@2113.47,1502.6 v1(2142.84,1502.6) R191.2@2167.31,1502.6
  L08-BOTTOM w5: C184.1@2142.26,1526.34 2142.84,1525.76 v1(2142.84,1502.6)
INLC6: C199.1 R207.2 U15.19 | length 78.8
  L01-TOP w5: U15.19@2639.63,1830.32 2639.8,1830.15 2667.65,1830.15 v1(2667.82,1829.98) 2692.19,1829.98 R207.2@2692.61,1829.56
  L08-BOTTOM w5: v1(2667.82,1829.98) 2667.82,1854.29 C199.1@2668.7,1855.16
MCU_CLK_25M: R73.2 U4.D13 | length 363
  L01-TOP w4: v1(744.74,1380.34) 744.74,1355.47 R73.2@745.14,1355.07 ; v2(964.05,1284.4) 964.05,1281.69 970.32,1275.42 U4.D13@970.32,1219.2
  L08-BOTTOM w4: v1(744.74,1380.34) 744.74,1361.95 822.29,1284.4 v2(964.05,1284.4)
MDC: R32.2 U8.12 | length 1641.5
  L01-TOP w4: U8.12@678.71,959.19 679.19,959.66 757.44,959.66 v1(757.91,960.14)
  L08-BOTTOM w4: v1(757.91,960.14) 689.28,960.14 578.35,1071.06 453.1,1071.06 399.48,1124.68 399.48,1442.24 410.19,1452.96 724.61,1452.96 853.47,1324.09 1034.85,1324.09 1057.45,1301.49 1057.45,1255.94 1081.18,1232.21 1081.18,1221.37 R32.2@1083.05,1219.5
MDIO: R19.2 U8.11 | length 30.1
  L01-TOP w4: U8.11@678.89,939.33 R19.2@709.01,939.33
NetC1_1: C1.1 U1.23 | length 73.3
  L01-TOP w10: U1.23@2090.56,830.3 2090.56,869.23 2100.73,879.4 2100.73,891.38 2105.57,896.22 C1.1@2106.78,896.22
NetC15_2: C15.2 R3.1 R4.2 U1.25 | length 127.6
  L01-TOP w10: C15.2@2031.1,947.09 2031.3,946.89 R3.1@2031.32,924.38 ; R4.2@2031.51,896.09 2031.51,872.7 2049.3,854.91 2049.3,832.19 U1.25@2051.19,830.3 ; R4.2@2031.79,893.02 R3.1@2031.79,923.91
NetC27_1: C27.1 R12.2 | length 25.8
  L08-BOTTOM w10: C27.1@1688.5,460.03 1688.73,460.25 1688.73,485.43 R12.2@1688.95,485.61 R12.2@1688.95,485.61
NetC27_2: C27.2 L1.1 U3.9 | length 92.8
  L01-TOP w8: U3.9@1632.02,436.69 1632.94,435.77 1658.94,435.77 v1(1660.64,434.07)
  L08-BOTTOM w10: v1@1660.66,434.06 C27.2@1688.49,434.06
  L08-BOTTOM w15: L1.1@1681.64,403.15 1684.19,403.15 1688.5,407.46 C27.2@1688.5,434.05
NetC30_1: C30.1 U3.13 | length 57.7
  L01-TOP w6: U3.13@1606.43,501.66 1606.72,501.95 1606.72,558.79 C30.1@1607.02,559.09
NetC44_1: C44.1 C49.1 C68.1 R46.1 U4.J2 U4.K2 U4.M4 | length 2354.6
  L01-TOP w4: U4.J2@1098.27,937.7 1111.36,937.7 ; v2(1136.65,924.63) 1136.65,924.77 1123.86,937.56 U4.K2@1123.86,937.7 1111.36,937.7 ; U4.M4@1175.04,988.88 1176.16,987.76 1184.92,987.76 1195.7,976.97 1275.72,976.97 C49.1@1286.51,987.76 ; C68.1@1230.34,826.18 1222.74,833.78 1222.74,848.71 1192.46,879 1128.8,879 1111.34,896.46 1111.34,937.68
  L01-TOP w5: R46.1@1854.15,950.49 1856.22,952.56 v1(1891.74,952.56)
  L03-SIG w4: v2(1136.65,924.63) 1176.63,884.66 1222.05,884.66 1241.59,904.19 v2(1241.59,976.49)
  L03-SIG w5: v1(978.07,612.85) 976.07,610.85 976.07,578.79 1002.93,551.93 1071.8,551.93 1149.71,474.02 1361.15,474.02 1449.8,562.66 1594.6,562.66 1704.74,672.81 1704.74,907.73 1749.57,952.56 v1(1891.74,952.56)
  L08-BOTTOM w5: v1(978.07,612.85) 980.39,615.17 980.39,792.03 1008.69,820.33 1040.71,820.33 1061.16,840.78 1061.16,890.04 1072.56,901.44 1085.28,901.44 C44.1@1096.11,912.28
  L08-BOTTOM w8: C44.1@1095.65,910.11 1110.18,924.63 v2(1136.65,924.63)
NetC45_1: C45.1 R43.1 | length 71.7
  L08-BOTTOM w15: C45.1@1711.38,1039.32 1711.42,1039.36 R43.1@1783.02,1039.4 R43.1@1783.02,1039.4
NetC48_1: C48.1 U5.4 | length 82.3
  L08-BOTTOM w10: C48.1@1581.15,993.45 1587.65,986.94 1601.35,986.94 1611.23,977.07 U5.4@1656.68,977.07
NetC95_1: C95.1 T1.5 | length 81.3
  L01-TOP w8: T1.5@380.32,701.58 380.67,701.92 v1(380.67,734.09)
  L08-BOTTOM w8: C95.1@341.58,710.97 344.75,714.13 360.71,714.13 v1(380.67,734.09)
NetC106_1: C106.1 T2.5 | length 86.9
  L01-TOP w5: v1(628.05,674.41) 628.05,699.24 T2.5@630.16,701.35
  L08-BOTTOM w5: v1(628.05,674.41) 630.86,671.6 630.86,659.26 633.79,656.33 C106.1@672.37,656.33
NetC109_1: C109.1 R99.2 R101.2 | length 162.4
  L08-BOTTOM w4: R99.2@587,514.29 587,468.46 598.55,456.91 C109.1@635.42,456.91 650.54,472.03 650.54,482.22 650.92,482.59 R101.2@650.92,513.9
NetC110_1: C110.1 C111.1 U8.2 | length 205.5
  L01-TOP w5: C111.1@380.67,820.47 416.89,820.47 C110.1@423.14,814.23 429.26,820.35 429.26,838.68 432.19,841.61 524.07,841.61 535.01,852.55 U8.2@535.01,874.54
NetC115_2: C115.2 U10.1 | length 116.6
  L01-TOP w5: C115.2@220.94,1971.72 227.7,1964.96 241.26,1964.96 253.91,1952.31 253.91,1926.64 277.31,1903.25 U10.1@294.12,1903.25
NetC116_2: C116.2 U10.9 | length 82.7
  L01-TOP w5: v3(357.16,1684.58) 358.12,1685.54 358.12,1711.34 U10.9@359.09,1712.3
  L01-TOP w6: U10.9@357.16,1703.49 359.01,1705.34 U10.9@359.01,1711.72
  L08-BOTTOM w5: v3(357.16,1684.58) 357.16,1682.39 368.33,1671.22 C116.2@368.33,1644
NetC125_2: C125.2 R124.2 U10.24 | length 173.3
  L01-TOP w5: v3(358.48,2028.73) 362.45,2028.73 368.39,2022.79 385.77,2022.79 387.87,2020.68 387.87,2006.73 C125.2@397.89,2006.73 ; C125.2@395.08,2009.54 C125.2@397.89,2006.73 ; U10.24@398.46,1940.65 398.46,2006.16 C125.2@397.89,2006.73
  L08-BOTTOM w5: v3(358.48,2028.73) 362.45,2028.73 367.11,2024.07 385.77,2024.07 395.08,2014.76 R124.2@395.08,2010.83
NetC130_2: C130.2 U11.1 | length 103.5
  L01-TOP w5: C130.2@770.58,1957.14 779.89,1947.82 792.13,1947.82 794.94,1945.01 821.51,1918.45 821.51,1910.89 832.49,1899.9 U11.1@845.93,1899.9
NetC131_2: C131.2 U11.9 | length 74.7
  L01-TOP w6: v1(909.79,1683.95) 910.34,1684.5 910.34,1708.41 U11.9@910.89,1708.96
  L08-BOTTOM w6: v1(909.79,1683.95) 909.79,1682.64 924.58,1667.85 C131.2@924.58,1640.84
NetC140_2: C140.2 R142.2 U11.24 | length 155.1
  L01-TOP w5: v3(906.66,2015.71) 936.33,2015.71 950.26,2001.77 U11.24@950.26,1937.31
  L08-BOTTOM w5: v3(906.66,2015.71) 944.19,2015.71 R142.2@946.86,2013.04
NetC145_2: C145.2 U12.1 | length 97.5
  L01-TOP w5: C145.2@1334.31,1957.13 1337.12,1957.13 1346.43,1947.81 1346.43,1941.08 1387.15,1900.36 U12.1@1404.31,1900.36
NetC146_2: C146.2 U12.9 | length 79
  L01-TOP w5: v3(1465.81,1680.42) 1467.54,1682.15 1467.54,1707.69 U12.9@1469.27,1709.42
  L08-BOTTOM w5: v3(1465.81,1680.42) 1465.81,1679.44 1477.58,1667.67 C146.2@1477.58,1636.77
NetC155_2: C155.2 R158.2 U12.24 | length 162
  L01-TOP w5: v3(1468.5,2031.14) 1470.41,2031.14 1490.01,2011.55 C155.2@1507.71,2011.55 ; C155.2@1507.26,2010.52 1507.26,2006.59 1508.64,2005.21 U12.24@1508.64,1937.76
  L08-BOTTOM w5: v3(1468.5,2031.14) 1498.72,2031.14 R158.2@1506.6,2023.26
NetC160_2: C160.2 U13.1 | length 109.4
  L01-TOP w5: C160.2@1875.57,2198.21 1900.62,2198.21 1922.48,2176.36 1922.48,2152.03 1932.61,2141.89 U13.1@1947.38,2141.89
NetC161_2: C161.2 U13.9 | length 79
  L01-TOP w5: v3(2009.68,1919.75) 2011.01,1921.08 2011.01,1949.61 U13.9@2012.34,1950.94
  L08-BOTTOM w5: v3(2009.68,1919.75) 2009.68,1918.14 2021.14,1906.68 C161.2@2021.14,1877.77
NetC170_2: C170.2 R174.2 U13.24 | length 152.9
  L01-TOP w5: v3(2012.34,2259.86) 2013.14,2259.05 2038.11,2259.05 2047.42,2249.74 C170.2@2047.42,2248.11 2051.71,2243.83 U13.24@2051.71,2179.29
  L08-BOTTOM w5: v3(2012.34,2259.86) 2038.11,2259.86 2047.42,2250.55 R174.2@2047.42,2248.11
NetC175_2: C175.2 U14.1 | length 108.1
  L01-TOP w5: C175.2@1852.08,1578.69 1873.79,1578.69 1876.45,1576.04 1896.8,1555.68 1896.8,1533.68 1905.77,1524.7 1921.54,1524.7 U14.1@1923.96,1522.28
NetC176_2: C176.2 U14.9 | length 78.2
  L01-TOP w5: v3(1987.56,1302.39) 1988.24,1303.07 1988.24,1330.66 U14.9@1988.92,1331.34
  L08-BOTTOM w5: v3(1987.56,1302.39) 2001.92,1288.03 C176.2@2001.92,1259.66
NetC185_2: C185.2 R190.2 U14.24 | length 146.5
  L01-TOP w6: v1(1995.91,1643.57) 2027.74,1643.57 2028.29,1644.12 U14.24@2028.29,1559.68
  L08-BOTTOM w6: v1(1995.91,1643.57) 2015.79,1643.57 R190.2@2022.56,1636.81
NetC190_2: C190.2 U15.1 | length 114.2
  L01-TOP w5: C190.2@2377.93,1905.66 2409.54,1905.66 2427.42,1887.79 2427.42,1856.4 2433.8,1850.01 U15.1@2450.65,1850.01
NetC191_2: C191.2 U15.9 | length 76.7
  L01-TOP w5: v3(2514.64,1629.01) 2515.13,1629.5 2515.13,1658.58 U15.9@2515.61,1659.06
  L08-BOTTOM w5: v3(2514.64,1629.01) 2514.64,1627.07 2525.93,1615.78 C191.2@2525.93,1587.45
NetC200_2: C200.2 R206.2 U15.24 | length 178.2
  L01-TOP w6: v3(2516.34,1992.88) 2517.03,1992.88 2530.01,1979.9 2546.46,1979.9 2554.98,1971.37 U15.24@2554.98,1887.41
  L08-BOTTOM w6: v3(2516.34,1992.88) 2520.05,1992.88 2523.3,1989.62 2543.17,1989.62 2551.69,1981.1 R206.2@2551.69,1974.65
NetD2_2: D2.2 R8.2 | length 33.9
  L01-TOP w8: D2.2@1896.82,346.75 1897.38,346.19 1929.64,346.19 R8.2@1930.21,345.63
NetD3_2: D3.2 R9.1 | length 70.4
  L01-TOP w8: R9.1@1776.84,237.93 1806.93,237.93 1821,252 1836.65,252 D3.2@1840,255.35
NetD4_2: D4.2 R7.1 U2.1 | length 160.2
  L01-TOP w8: v1(1584.17,702.92) 1584.17,672.27 1593.45,662.99 R7.1@1631.38,662.99 1630.66,663.7 D4.2@1630.66,704.68
  L08-BOTTOM w8: v1(1584.17,702.92) 1587.33,702.92 1590.26,705.85 1613.93,705.85 U2.1@1617.81,709.73
NetD5_1: D5.1 R107.2 | length 51.2
  L01-TOP w5: R107.2@289.84,935.04 289.84,936.72 299.15,946.03 D5.1@335.51,946.03
NetD6_1: D6.1 Q1.3 | length 57.6
  L01-TOP w5: D6.1@221.56,1190.58 221.56,1206.69 231.66,1216.79 Q1.3@231.66,1244
NetD6_2: D6.2 R108.1 | length 59.7
  L01-TOP w5: R108.1@253.28,1134.04 260.93,1141.7 D6.2@260.93,1190.58
NetD7_1: D7.1 Q2.3 | length 49.2
  L01-TOP w5: D7.1@280.03,1032.55 280.03,1053.94 286.17,1060.09 Q2.3@286.17,1079.23
NetD7_2: D7.2 R109.1 | length 45
  L01-TOP w5: R109.1@317.06,990.14 323.34,996.41 D7.2@323.34,1032.55
NetJ2_2: J2.2 R75.2 | length 79.3
  L08-BOTTOM w6: R75.2@465.31,1162.35 471.54,1168.59 471.54,1179.65 494.52,1202.63 J2.2@494.52,1229.6
NetJ4_9: J4.9 R116.2 | length 64.7
  L08-BOTTOM w5: R116.2@122.04,1657.02 125.11,1660.09 J4.9@185.49,1660.09
NetJ4_12: J4.12 R119.2 | length 34.5
  L08-BOTTOM w4: J4.12@278.79,1601.04 309.4,1601.04 R119.2@312.14,1598.3
NetJ5_9: J5.9 R134.2 | length 60
  L08-BOTTOM w5: R134.2@681.51,1658.79 681.67,1658.63 J5.9@741.4,1658.63
NetJ5_12: J5.12 R137.2 | length 31.1
  L08-BOTTOM w5: J5.12@834.7,1599.57 836.29,1597.99 R137.2@865.14,1597.99
NetJ6_9: J6.9 R150.2 | length 62
  L08-BOTTOM w5: R150.2@1241.73,1657.11 1244.83,1660.2 J6.9@1302.44,1660.2
NetJ6_12: J6.12 R153.2 | length 36.1
  L08-BOTTOM w5: J6.12@1395.75,1601.15 1428.23,1601.15 R153.2@1430.8,1598.58
NetJ7_9: J7.9 R166.2 | length 217.8
  L01-TOP w4: R166.2@1717.93,2012.39 1722.54,2007.77 v1(1722.54,1980.31)
  L06-SIG w4: v1(1722.54,1980.31) 1782.12,1980.31 1807.38,1955.05 v3(1807.38,1897.79)
  L08-BOTTOM w4: v3(1807.38,1897.79) J7.9@1838.64,1897.79
NetJ7_12: J7.12 R169.2 | length 35.2
  L08-BOTTOM w5: J7.12@1931.95,1838.74 1959.7,1838.74 R169.2@1964.95,1833.49
NetJ8_9: J8.9 R182.2 | length 60.9
  L08-BOTTOM w5: R182.2@1750.59,1282.07 1750.77,1281.89 J8.9@1811.42,1281.89
NetJ8_12: J8.12 R185.2 | length 34.5
  L08-BOTTOM w5: J8.12@1904.73,1222.83 1908.34,1219.22 1922.6,1219.22 1922.98,1218.84 1928.98,1218.84 1934.75,1213.08 R185.2@1934.75,1212.69
NetJ9_9: J9.9 R198.2 | length 60.3
  L08-BOTTOM w5: R198.2@2281.89,1606.92 2282.27,1607.3 J9.9@2342.03,1607.3
NetJ9_12: J9.12 R201.2 | length 30.2
  L08-BOTTOM w5: J9.12@2435.34,1548.25 2462.17,1548.25 R201.2@2464.56,1545.85
NetJ11_1: J11.1 R211.2 | length 58.6
  L08-BOTTOM w3.8: J11.1@1565.82,82.68 1565.82,140.95 R211.2@1566.06,141.2
NetJ11_2: J11.2 R212.2 | length 59.4
  L08-BOTTOM w3.8: J11.2@1615.82,82.68 R212.2@1615.82,142.05
NetJ12_1: J12.1 R215.2 U16.7 | length 203.1
  L01-TOP w5: J12.1@814,82.68 814,92.52 850.7,129.22 850.7,156.33 847.77,159.26 844.24,159.26 R215.2@828.04,175.46 828.65,175.46 844.85,191.66 v1(844.85,213.19)
  L08-BOTTOM w5: v1(844.85,213.19) 845.55,213.88 845.55,250.47 U16.7@846.25,251.17
NetJ12_2: J12.2 R215.1 U16.6 | length 191.2
  L01-TOP w5: J12.2@864,82.68 864.51,83.19 864.51,154.24 869.53,159.26 874.83,159.26 R215.1@891.03,175.46 890.2,175.46 874,191.66 v1(874,213.26)
  L08-BOTTOM w5: U16.6@871.84,251.17 872.92,250.09 872.92,214.34 v1(874,213.26)
NetJ13_2: J13.2 R216.2 | length 59.1
  L08-BOTTOM w4: J13.2@1416.36,82.94 R216.2@1416.36,142
NetL2_1: L2.1 U3.20 | length 93.4
  L01-TOP w10: v1(1468.34,454.45) 1470.19,456.3 1502.02,456.3 U3.20@1502.1,456.38
  L08-BOTTOM w15: L2.1@1410.13,455.7 1410.76,455.08 1467.71,455.08 v1(1468.34,454.45) v1@1468.23,454.34
NetL3_1: L3.1 U3.16 | length 74.7
  L01-TOP w8: U3.16@1547.37,501.66 v1(1547.37,537.91)
  L08-BOTTOM w15: L3.1@1533.71,565.17 1543.06,565.17 1547.37,560.86 v1(1547.37,537.91)
NetQ1_1: Q1.1 R110.2 | length 135.4
  L01-TOP w5: Q1.1@257.25,1237.11 297.23,1237.11 327.86,1267.75 R110.2@327.86,1319.88
NetQ2_1: Q2.1 R111.2 | length 65.4
  L01-TOP w5: Q2.1@311.77,1072.34 334.23,1072.34 338.29,1076.4 338.29,1082.79 347.73,1092.24 R111.2@365.19,1092.24
NetR1_1: R1.1 R2.2 U1.2 | length 109.3
  L01-TOP w10: R2.2@1933.1,841.09 1933.29,840.9 1933.29,807.85 R1.1@1933.48,807.66 1956.85,807.66 1976.41,788.09 2000.88,788.09 U1.2@2001,787.98
NetR5_2: R5.2 U1.1 | length 61.7
  L01-TOP w10: U1.1@2000.56,825.38 R5.2@2000.56,887.09
NetR6_2: R6.2 R10.2 U2.4 | length 75.2
  L08-BOTTOM w8: U2.4@1706.39,760.91 R6.2@1741.47,760.91 ; R6.2@1741.74,755.07 R10.2@1781.87,755.07
NetR12_1: R12.1 U3.10 | length 60.2
  L01-TOP w8: U3.10@1632.02,456.38 1632.94,457.3 1659.1,457.3 v1(1660.87,459.07)
  L08-BOTTOM w8: v1(1660.87,459.07) 1663.1,461.3 1663.1,471.35 1667.16,475.41 1667.16,484.43 1668.33,485.61 R12.1@1668.92,485.61
NetR13_1: R13.1 U3.7 | length 76.4
  L01-TOP w8: U3.7@1626.85,396.59 1626.85,368.33 1633.56,361.62 v1(1633.56,361.51)
  L08-BOTTOM w8: R13.1@1612.16,332.38 1613.11,332.38 1614.28,333.56 1614.28,342.23 v1(1633.56,361.51)
NetR14_1: R14.1 U3.18 | length 173.2
  L01-TOP w10: v1(1468.76,512.5) 1484.78,496.49 U3.18@1507.26,496.49
  L08-BOTTOM w5: v1(1468.76,512.5) 1471,510.27 1486.1,510.27 1499.53,496.84 1499.53,419.94 1496.6,417.01 1487.25,417.01 R14.1@1486.93,416.69
NetR15_1: R15.1 U3.12 | length 76.1
  L01-TOP w5: U3.12@1626.85,496.49 1626.85,520.6 1632.3,526.05 R15.1@1676.53,526.05
NetR16_1: R16.1 U3.14 | length 62.7
  L01-TOP w8: U3.14@1586.74,501.66 v1(1586.74,537.91)
  L08-BOTTOM w8: v1(1586.74,537.91) R16.1@1586.74,564.38
NetR24_2: R24.2 U4.M10 | length 1172.5
  L01-TOP w3.8: v1(1169.81,493.8) 1192.94,493.8 R24.2@1193.89,494.76
  L01-TOP w4: U4.M10@1175.04,1142.42 1175.13,1142.42 v2(1187.45,1154.65) v2(1187.45,1154.65)
  L03-SIG w3.8: v1(1169.81,493.8) 1166.77,496.84 1155.55,496.84 1084.46,567.93 1016.38,567.93 998.64,585.67 998.64,665.63 925.36,738.91 925.36,795.86 836.17,885.06 836.17,920.72 904.36,988.9 1019.26,988.9 1023.74,993.38 1023.74,1067.93 1047.05,1091.24 1170.22,1091.24 1174.95,1095.98 1174.95,1142.24 v2(1187.45,1154.65) v2(1187.45,1154.65)
NetR25_2: R25.2 U4.N9 | length 1507.4
  L01-TOP w3.8: U4.N9@1200.63,1116.83 1202.16,1118.37 1202.16,1123.72 1223.66,1145.22 1223.66,1163.5 1238.58,1178.43 v2(1253.16,1178.43)
  L06-SIG w3.8: v1(1142.06,185.63) 1163.95,207.53 1259.91,207.53 1287.1,234.72 1287.1,292.28 1242.86,336.53 1242.86,563.53 1081.9,724.48 1081.9,779.83 1116.62,814.56 1229.68,814.56 1298.85,883.72 1298.85,1150.64 1271.06,1178.43 v2(1253.16,1178.43)
  L08-BOTTOM w3.8: v1(1142.06,185.63) 1144.03,183.67 1154.47,183.67 1161.61,176.53 1161.61,164.05 R25.2@1161.65,164
NetR26_2: R26.2 U4.M9 | length 1125.8
  L01-TOP w3.8: v1(1169.69,520.75) 1192.86,520.75 R26.2@1194.13,519.48 ; U4.M9@1175.04,1116.83 v2(1187.73,1129.55)
  L03-SIG w3.8: v1(1169.69,520.75) 1114.13,576.31 1019.03,576.31 1006.44,588.9 1006.44,669.79 933.16,743.07 933.16,799.1 844.17,888.09 844.17,917.68 889.73,963.25 1020.49,963.25 1032.68,975.43 1032.68,1033.64 1064.52,1065.48 1174.87,1065.48 1186.96,1077.57 1186.96,1128.77 v2(1187.73,1129.55)
NetR28_2: R28.2 U4.N10 | length 1489.3
  L01-TOP w3.8: U4.N10@1200.63,1142.42 1215.66,1157.45 1215.66,1166.54 1245.56,1196.44 1264.08,1196.44 v2(1265.2,1195.32)
  L06-SIG w3.8: v1(1187.6,185.78) 1189.12,187.29 1258.89,187.29 1294.9,223.3 1294.9,296.77 1251.09,340.58 1251.09,566.32 1089.7,727.72 1089.7,776.6 1119.86,806.76 1232.91,806.76 1306.65,880.49 1306.65,1153.87 v2(1265.2,1195.32)
  L08-BOTTOM w3.8: v1(1187.6,185.78) 1187.74,185.63 1208.97,185.63 1211.2,183.41 R28.2@1211.2,164.58
NetR47_2: R47.2 U5.3 | length 80.4
  L08-BOTTOM w10: R47.2@1581.63,938.53 1594.57,951.48 U5.3@1656.68,951.48
NetR73_1: R73.1 U6.8 | length 33.9
  L01-TOP w5: U6.8@672.47,1351.44 704.85,1351.44 R73.1@705.96,1352.55
NetR74_1: R74.1 U6.7 | length 35.5
  L01-TOP w5: U6.7@672.47,1331.76 701,1331.76 R74.1@705.96,1326.8
NetR76_2: R76.2 U6.2 | length 103.6
  L01-TOP w5: v1(606.7,1244.43) 606.7,1248.4 613.41,1255.12 U6.2@613.41,1272.7
  L08-BOTTOM w5: v1(606.7,1244.43) 607.53,1245.26 607.53,1258.13 631.41,1282.02 R76.2@656.1,1282.02
NetR82_1: R82.1 R90.2 U6.15 | length 97.7
  L01-TOP w4: v1(547.68,1308.28) 549.57,1310.18 572.15,1310.18 U6.15@574.04,1312.07
  L08-BOTTOM w4: R82.1@545.51,1345.03 547.68,1342.86 v1(547.68,1308.28) 579.16,1308.28 R90.2@579.65,1307.79
NetR98_1: R98.1 R99.1 T1.3 | length 166.7
  L01-TOP w4: v1(551.62,568.63) 552.04,569.05 552.04,596.74 T1.3@552.46,597.17
  L08-BOTTOM w4: v1(551.62,568.63) 551.62,613.32 R98.1@560.64,622.33 569.89,613.09 584.66,613.09 587,610.74 R99.1@587,561.53
NetR98_2: R98.2 T1.4 | length 84.5
  L01-TOP w4: v1(520.65,568.63) T1.4@520.65,596.46
  L08-BOTTOM w4: R98.2@513.39,622.33 513.39,580.14 520.65,572.88 v1(520.65,568.63)
NetR100_1: R100.1 R101.1 T2.3 | length 218.6
  L01-TOP w4: v1(779.56,568.13) 781.19,569.76 792.33,569.76 802.31,579.74 T2.3@802.31,596.94
  L08-BOTTOM w4: R101.1@650.92,561.15 709.08,561.15 R100.1@709.46,561.53 709.46,583.33 722.81,596.68 761.07,596.68 777.39,580.36 777.39,570.31 v1(779.56,568.13)
NetR100_2: R100.2 T2.4 | length 131.6
  L01-TOP w4: v1(748.06,573.58) 750.57,573.58 770.49,593.51 T2.4@770.49,596.24
  L08-BOTTOM w4: R100.2@709.46,514.29 742.6,514.29 752.3,523.99 752.3,546.56 748.06,550.8 v1(748.06,573.58)
NetR102_2: R102.2 U8.1 | length 122.9
  L01-TOP w5: v1(489.74,867.65) 492.71,867.65 503.49,856.88 511.29,856.88 512.91,858.5 512.91,872.12 U8.1@515.33,874.54
  L08-BOTTOM w5: R102.2@412.23,867.65 v1(489.74,867.65)
NetR103_1: R103.1 U8.10 | length 86.9
  L01-TOP w4: U8.10@678.71,919.82 680.77,917.76 710.53,917.76 v1(723.26,905.03)
  L08-BOTTOM w4: R103.1@689.58,898.8 695.8,905.03 v1(723.26,905.03)
NetR104_2: R104.2 U8.21 | length 79.7
  L01-TOP w4: v1(574.3,1094.95) v1(574.3,1094.95) 574.34,1063.56 U8.21@574.38,1063.52
  L08-BOTTOM w5: R104.2@569.89,1141.33 574.3,1136.92 v1(574.3,1094.95)
NetR120_2: R120.2 U10.20 | length 33.7
  L01-TOP w5: U10.20@483.1,1903.25 485.52,1905.67 498.62,1905.67 500.14,1907.19 511.97,1907.19 R120.2@514.25,1909.46
NetR138_2: R138.2 U11.20 | length 35.2
  L01-TOP w5: U11.20@1034.91,1899.9 1060.59,1899.9 1067.11,1906.42 R138.2@1067.11,1906.74
NetR154_2: R154.2 U12.20 | length 35.7
  L01-TOP w5: U12.20@1593.28,1900.36 1595.71,1902.78 1608.27,1902.78 1610.57,1905.08 1618.89,1905.08 R154.2@1624.65,1910.85
NetR170_2: R170.2 U13.20 | length 39.1
  L01-TOP w5: U13.20@2136.35,2141.89 2155.35,2141.89 2160.85,2147.38 2169.92,2147.38 R170.2@2172.19,2149.65
NetR186_2: R186.2 U14.20 | length 35.6
  L01-TOP w5: U14.20@2112.94,1522.28 2127.63,1522.28 2130.92,1525.58 2138.98,1525.58 R186.2@2144.75,1531.35
NetR202_2: R202.2 U15.20 | length 39.9
  L01-TOP w5: U15.20@2639.63,1850.01 2641.65,1852.03 2655,1852.03 2660.96,1857.99 R202.2@2676.22,1857.99
NetR217_2: R217.2 TP22.1 U16.4 | length 120.2
  L01-TOP w4: TP22.1@938.26,362.12 TP22.1@938.26,362.12 938.31,332.4 v1(938.37,332.35)
  L08-BOTTOM w4: U16.4@904.29,375.17 897.43,368.32 U16.4@897.43,359.44 935.36,359.44 R217.2@938.15,362.23 938.37,362.01 v1(938.37,332.35)
NetR220_1: R220.1 U3.22 | length 119.8
  L01-TOP w5: v1(1471.53,381.16) 1471.53,409.48 1479.06,417.01 U3.22@1502.1,417.01
  L08-BOTTOM w5: v1(1471.53,381.16) 1487.25,381.16 1490.33,378.08 R220.1@1490.33,340.4
NetR221_1: R221.1 R223.1 U3.19 | length 194
  L01-TOP w5: v1(1465.23,482.59) 1469.2,482.59 1475.73,476.06 U3.19@1502.1,476.06
  L08-BOTTOM w5: R223.1@1338.86,542.16 1340.69,542.16 1347.87,534.99 1365.13,534.99 1370.25,529.87 1393.95,529.87 1409.26,514.56 1409.26,508.77 1418.57,499.46 R221.1@1422.51,499.46 1448.36,499.46 v1(1465.23,482.59)
NetR222_1: R222.1 U4.L12 | length 147.7
  L01-TOP w3.7: 1162.02,1206.17 1162.02,1298.12
  L01-TOP w4: U4.L12@1149.45,1193.6 1162.02,1206.17 ; 1162.02,1298.12 1176.03,1312.13 1176.03,1320.87 R222.1@1182.73,1327.57
NetTP13_1: TP13.1 U6.12 | length 78
  L01-TOP w5: TP13.1@546.27,1420.25 546.27,1416.28 575.08,1387.48 590.8,1387.48 593.73,1384.55 U6.12@593.73,1371.13
NetTP14_1: TP14.1 U6.11 | length 56
  L01-TOP w5: TP14.1@596.83,1420.25 596.83,1412.42 613.41,1395.84 U6.11@613.41,1371.13
nSLEEP1: R113.2 U10.13 | length 60.9
  L01-TOP w5: U10.13@437.83,1712.3 437.83,1696.3 454.33,1679.8 R113.2@454.33,1658.25
nSLEEP2: R131.2 U11.13 | length 59.6
  L01-TOP w5: U11.13@989.63,1708.96 992.06,1706.54 992.06,1696.75 ; 992.09,1696.72 992.09,1689.47 995.56,1685.99 995.56,1665.02 R131.2@1004.87,1655.7
nSLEEP3: R147.2 U12.13 | length 74.4
  L01-TOP w5: U12.13@1548.01,1709.42 1550.16,1707.26 1550.16,1681.78 1565.38,1666.57 R147.2@1565.38,1642.19
nSLEEP4: R163.2 U13.13 | length 67.8
  L01-TOP w5: U13.13@2091.08,1950.94 2092.63,1949.39 2092.63,1923.54 2105.1,1911.08 2105.1,1895.1 R163.2@2109.44,1890.76
nSLEEP5: R179.2 U14.13 | length 65.7
  L01-TOP w5: U14.13@2067.66,1331.34 2069.53,1329.47 2069.53,1314.74 2077.62,1306.65 2077.62,1280.64 R179.2@2085.32,1272.93
nSLEEP6: R195.2 U15.13 | length 69.9
  L01-TOP w5: U15.13@2594.35,1659.06 2596.3,1657.12 2596.3,1638.36 2609.61,1625.05 2609.61,1601.67 R195.2@2614.01,1597.27
PHY0_25MHZ_CLK: C108.1 R74.2 TP18.1 U8.9 | length 738.5
  L01-TOP w4: U8.9@685.6,900.13 U8.9@678.71,900.13 681.63,897.21 694.72,897.21 697.76,894.17 v1(697.76,835.9) ; TP18.1@697.88,799.01 697.82,799.08 697.82,835.84 v1(697.76,835.9) ; R74.2@745.33,1326.8 747.3,1326.8 755.14,1318.96 755.14,1303.13 v1(756.69,1301.58) ; C108.1@747.65,827.22 738.97,835.9 v1(697.76,835.9)
  L03-SIG w4: v1(697.76,835.9) 649.22,884.44 649.22,1143.45 756.69,1250.92 v1(756.69,1301.58)
PHY0_LED1: R81.2 U8.31 | length 77.8
  L01-TOP w5: v1(459.85,919.4) 460.06,919.61 489.53,919.61 U8.31@489.74,919.82
  L08-BOTTOM w5: R81.2@415.41,911.38 440.25,911.38 445.47,916.59 457.04,916.59 v1(459.85,919.4)
PHY0_RD_N: C99.2 T1.2 U8.4 U9.5 U9.6 | length 339.7
  L01-TOP w4.25: T1.2@537.02,677.76 521.46,677.76 514.27,684.95 502.38,684.95 493.33,694 493.33,715.07 509.79,731.53 554.09,731.53 562.86,740.3 562.86,743.82 553.87,752.8 v8(553.87,753.05) 565.54,764.72 565.54,774.94 U9.6@567.35,776.75 567.35,783.94 571.59,788.18 571.59,798.2 567.35,802.44 U9.5@567.35,809.63 567.35,816.81 571.59,821.06 571.59,837.61 578.62,844.64 578.62,863.41 574.38,867.65 U8.4@574.38,874.54
  L08-BOTTOM w4.25: v8(553.87,753.05) 553.87,753.3 563.28,762.72 563.28,770.23 560.79,772.72 560.16,772.72 554.01,778.87 C99.2@554.01,779.65
PHY0_RD_P: C98.2 T1.1 U8.5 U9.4 U9.7 | length 316.9
  L01-TOP w4.25: T1.1@537.02,703.35 521.46,703.35 514.27,696.15 507.02,696.15 504.53,698.64 504.53,710.43 514.42,720.33 558.73,720.33 574.06,735.66 574.06,743.82 583.04,752.8 v8(583.04,753.05) 585.22,755.23 585.22,774.94 U9.7@587.04,776.75 587.04,783.94 582.79,788.18 582.79,798.2 587.04,802.44 U9.4@587.04,809.63 587.04,816.81 582.79,821.06 582.79,832.97 589.82,840 589.82,863.41 594.07,867.65 U8.5@594.07,874.54
  L08-BOTTOM w4.25: v8(583.04,753.05) 583.04,753.86 574.48,762.42 574.48,770.35 576.97,772.84 577.56,772.84 583.71,778.98 C98.2@583.71,779.77
PHY0_TD_N: C101.2 T2.2 U8.6 U9.2 U9.9 | length 360.6
  L01-TOP w4.25: U8.6@613.75,874.54 613.75,867.65 617.99,863.41 617.99,842.81 630.65,830.16 630.65,821.06 626.41,816.81 U9.2@626.41,809.63 626.41,802.44 630.65,798.2 630.65,788.18 626.41,783.94 U9.9@626.41,776.75 626.41,769.57 632.42,763.55 632.42,755.68 v8(635.05,753.05) 635.05,751.3 642.67,743.69 642.67,734.28 651.72,725.23 665.76,725.23 665.84,725.31 711.29,725.31 751.87,684.73 764.11,684.73 771.3,677.53 T2.2@786.86,677.53
  L08-BOTTOM w4.25: v8(635.05,753.05) 635.05,754.29 643.17,762.42 643.17,771.36 635.32,779.21 C101.2@635.32,780
PHY0_TD_P: C100.2 T2.1 U8.7 U9.1 U9.10 | length 344.4
  L01-TOP w4.25: U8.7@633.44,874.54 633.44,867.65 629.19,863.41 629.19,847.45 641.85,834.8 641.85,821.06 646.09,816.81 U9.1@646.09,809.63 646.09,802.44 641.85,798.2 641.85,788.18 646.09,783.94 U9.10@646.09,776.75 646.09,769.57 661.48,754.18 v8(661.48,753.05) 661.48,751.3 653.87,743.69 653.87,738.92 656.36,736.43 661.13,736.43 661.2,736.51 715.92,736.51 726.61,725.83 730.57,721.87 756.51,695.93 764.11,695.93 771.3,703.12 T2.1@786.86,703.12
  L08-BOTTOM w4.25: v8(661.48,753.05) 661.48,755.31 654.37,762.42 654.37,771.36 662.23,779.21 C100.2@662.23,780
PHY0_VDDA: C97.1 C104.1 C105.1 L10.1 U8.3 | length 336.5
  L01-TOP w8: v1(457.21,798.98) 475.21,816.98 504.59,816.98 C105.1@504.98,816.59 C97.1@530.32,816.59 530.32,817.38 534.59,821.64 540.93,821.64 554.7,835.41 U8.3@554.7,874.54
  L08-BOTTOM w8: L10.1@419.61,812.35 421.45,812.35 429.26,820.16 429.26,829.51 441.36,841.61 492.01,841.61 504.6,829.02 C104.1@504.6,801.07 502.52,798.98 v1(457.21,798.98)
PHY0_VDDIO: C96.1 C102.1 C103.1 L9.1 R78.2 R79.2 R80.2 R104.1 U8.17 | length 439.6
  L01-TOP w8: U8.17@653.12,1063.52 654.04,1064.44 654.04,1076.9 666.18,1089.04 666.18,1099.27 C103.1@667.44,1100.52 667.51,1100.45 692.61,1100.45 693.16,1099.9 709.38,1099.9 718.34,1090.95 v1(719.46,1090.95) 720.11,1090.3 749.29,1090.3 R79.2@749.94,1089.65
  L08-BOTTOM w6: R104.1@569.89,1188.57 587.59,1188.57 597.88,1178.28 597.88,1134.76 613.61,1119.03 619.39,1119.03 628.2,1110.22 L9.1@628.2,1106.29 637.01,1097.48 637.01,1088.46 654.04,1071.43 654.04,1058.11 R78.2@655.33,1056.82
  L08-BOTTOM w8: v1(719.46,1090.95) 720.25,1090.16 749.15,1090.16 R80.2@749.94,1089.36
  L08-BOTTOM w10: L9.1@628.2,1106.29 681.78,1106.29 697.12,1090.95 v1(719.46,1090.95)
PMIC_NRST: R39.1 U3.4 | length 75.6
  L01-TOP w5: v2(1562.71,365.71) 1564.43,367.43 1564.43,371.99 1564.52,372.08 1564.52,379.18 1564.64,379.3 1564.64,389 U3.4@1567.06,391.42
  L08-BOTTOM w4: v2(1562.71,365.71) 1562.71,346.39 1571.31,337.8 R39.1@1571.31,321.13
PWM_A1_H: R114.1 U4.E7 | length 959.1
  L01-TOP w4: R114.1@516.42,1634.37 516.42,1582.12 646.46,1452.07 724.6,1452.07 781.97,1394.7 781.97,1149.99 809.64,1122.32 809.64,1060.59 v9(832.49,1037.74) ; v2(983.29,1078.49) 983.29,1078.38 995.91,1065.76 U4.E7@995.91,1065.65
  L08-BOTTOM w4: v9(832.49,1037.74) 942.59,1037.74 983.29,1078.43 v2(983.29,1078.49)
PWM_A1_L: R115.1 U4.A6 | length 889.8
  L01-TOP w4: R115.1@540.86,1701.32 566.72,1701.32 578.37,1689.66 578.37,1537.47 655.78,1460.07 727.92,1460.07 789.97,1398.02 789.97,1153.31 817.64,1125.64 817.64,1073.23 850.81,1040.06 U4.A6@893.54,1040.06
PWM_A2_H: R132.1 U4.A5 | length 2218.7
  L01-TOP w4: U4.A5@893.54,1014.47 858.09,1014.47 796.17,952.55 796.17,783.37 860,719.54 860,643 927.23,575.77 1237.63,575.77 1408.55,746.68 1441.19,746.68 v1(1442.78,745.09) ; R132.1@1069.14,1646.41 1069.98,1647.25 v3(1103.91,1647.25)
  L03-SIG w4: v3(1103.91,1647.25) 1103.91,1623.12 1431.04,1295.99 1431.04,778.61 1442.78,766.87 v1(1442.78,745.09)
PWM_A2_L: R133.1 U4.B5 | length 2387
  L01-TOP w4: U4.B5@919.13,1014.47 906.47,1027.13 859.44,1027.13 788.17,955.86 788.17,780.05 852,716.22 852,639.69 923.92,567.77 1240.95,567.77 1403,729.83 v1(1420.97,729.83) ; R133.1@1094.96,1715.65 1128.49,1715.65 v3(1129.83,1716.99)
  L03-SIG w4: v3(1129.83,1716.99) 1097.21,1716.99 1071.33,1691.11 1071.33,1644.39 1423.04,1292.68 1423.04,774.16 1420.63,771.75 1420.63,730.16 v1(1420.97,729.83)
PWM_A3_H: R148.1 U4.B1 | length 2003.9
  L01-TOP w4: v2(903.39,896.29) U4.B1@919.13,912.11 ; R148.1@1602.79,1600.83 1606.91,1604.95 v3(1628.57,1604.95)
  L03-SIG w4: v1(1487.06,1010.87) 1487.06,1015.12 1495.54,1023.6 1495.54,1428.24 1628.57,1561.27 v3(1628.57,1604.95)
  L08-BOTTOM w4: v2(903.39,896.29) 904.05,896.95 904.05,911.29 895.94,919.4 853.54,919.4 817.37,883.24 817.37,663.41 888.85,591.93 1195.56,591.93 1424.98,821.35 1424.98,951.16 1434.77,960.95 1434.77,982.15 1463.5,1010.87 v1(1487.06,1010.87)
PWM_A3_L: R149.1 U4.C1 | length 2199.1
  L01-TOP w4: v2(931.68,896.46) 931.68,897.76 944.73,910.81 U4.C1@944.73,912.11 ; R149.1@1651.17,1720.82 1652.73,1719.26 v3(1677.57,1719.26)
  L03-SIG w4: v1(1487.06,984.68) 1488.26,985.89 1500.26,985.89 1503.54,989.17 1503.54,1424.93 1646.79,1568.18 1646.79,1632.57 1677.57,1663.35 v3(1677.57,1719.26)
  L08-BOTTOM w4: v2(931.68,896.46) 899.93,928.21 851.03,928.21 809.37,886.55 809.37,660.09 885.54,583.93 1198.87,583.93 1432.98,818.04 1432.98,947.85 1469.82,984.68 v1(1487.06,984.68)
PWM_A4_H: R164.1 U4.D3 | length 2804.7
  L01-TOP w4: v2(957.76,950.56) v2(957.76,950.56) 970.32,963.2 U4.D3@970.32,963.29 ; R164.1@2174.08,1870.93 v3@2206.8,1870.93
  L03-SIG w4: v2(957.76,950.56) 945.06,937.86 918.98,937.86 889.65,908.53 889.65,867.69 906.18,851.15 976.2,851.15 1040.58,786.77 1040.58,738.15 1191.65,587.08 1582.73,587.08 1682.48,686.82 1682.48,1196.62 1747.41,1261.55 1870.25,1261.55 1912.1,1219.7 2065.72,1219.7 2125.38,1279.36 2125.38,1540.8 2185.66,1601.09 2185.66,1853.04 2203.5,1870.87 v3(2206.85,1870.87)
PWM_A4_L: R165.1 U4.D1 | length 2779.5
  L01-TOP w4: R165.1@2196.78,1944.45 2203.04,1938.19 2203.04,1923.1 2206.44,1919.7 v3(2206.44,1915.46)
  L01-TOP w5: v2(956.56,896.46) 956.56,897.41 970.32,911.16 U4.D1@970.32,912.11
  L03-SIG w3.8: 918.04,868.59 918.04,904.81 925.15,911.92 941.11,911.92
  L03-SIG w4: 918.04,868.59 924.07,862.56 976.1,862.56 1048.58,790.08 1048.58,741.47 1194.97,595.08 1579.42,595.08 1674.48,690.14 1674.48,1199.93 1744.09,1269.55 1873.7,1269.55 1915.55,1227.7 2062.4,1227.7 2117.38,1282.68 2117.38,1544.12 2175.47,1602.21 2175.47,1905.19 2185.09,1914.81 2205.79,1914.81 v3(2206.44,1915.46) ; 941.11,911.92 v2(956.56,896.46)
PWM_A5_H: R180.1 U4.D7 | length 1890.9
  L01-TOP w4: v2@957.56,1078.36 U4.D7@970.32,1065.65 ; v1(1301.43,1330.98) 1544.02,1330.98 1739.6,1135.41 2102.72,1135.41 2149.4,1182.09 R180.1@2149.4,1235.55
  L06-SIG w3.8: 888.12,1130.24 900,1142.13 940.4,1142.13 944.63,1146.36 944.63,1166.04 ; 905.8,1091.24 944.64,1091.24 v2(957.52,1078.36) ; 946.97,1168.38 966.62,1168.38 971.1,1172.86 971.1,1249.83
  L06-SIG w4: 888.12,1130.24 888.12,1108.91 905.8,1091.24 ; v1(898.27,1376.26) 898.83,1375.7 898.83,1322.1 971.1,1249.83 ; 944.63,1166.04 946.97,1168.38
  L08-BOTTOM w4: v1(898.27,1376.26) 900.31,1376.26 912.48,1364.09 1231.81,1364.09 1264.91,1330.98 v1(1301.43,1330.98)
PWM_A5_L: R181.1 U4.B8 | length 2003.6
  L01-TOP w4: v1(841.64,1414.53) 841.64,1123.7 861.41,1103.94 906.44,1103.94 U4.B8@919.13,1091.24 ; v1(1301.6,1305.4) 1557.69,1305.4 1735.69,1127.41 2106.03,1127.41 2173.65,1195.03 2173.65,1323.23 R181.1@2171.68,1325.21
  L08-BOTTOM w4: v1(841.64,1414.53) 841.64,1394.19 879.75,1356.09 1224.51,1356.09 1265.8,1314.79 1291.9,1314.79 1301.29,1305.4 v1(1301.6,1305.4)
PWM_A6_H: R196.1 U4.B4 | length 2793.4
  L01-TOP w4: U4.B4@919.13,988.88 905.45,1002.57 857.5,1002.57 804.17,949.23 804.17,786.68 868,722.85 868,646.31 930.53,583.78 1234.33,583.78 1416.23,765.68 1497.26,765.68 1750.24,1018.66 2229.71,1018.66 2230.85,1019.8 2236.89,1019.8 v1(2239.89,1022.8) ; R196.1@2680.37,1578.05 2684.76,1573.65 v3(2684.76,1547.75)
  L03-SIG w4: v1(2239.89,1022.8) 2685.12,1468.03 2685.12,1547.39 v3(2684.76,1547.75)
PWM_A6_L: R197.1 U4.A4 | length 2864.3
  L01-TOP w4: U4.A4@893.54,988.88 855.13,988.88 812.17,945.92 812.17,790 876.17,726 876.17,649.46 932.6,593.03 1232.27,593.03 1414.1,774.86 1495.13,774.86 1746.93,1026.66 2217.19,1026.66 v1(2240.37,1049.84) ; R197.1@2705.41,1655.7 2731.43,1655.7 v3(2733.23,1653.91)
  L03-SIG w4: v1(2240.37,1049.84) 2513.26,1322.73 2513.26,1480.69 2687.97,1655.4 2731.73,1655.4 v3(2733.23,1653.91)
PWM_B1_H: R117.1 U4.B6 | length 979.1
  L01-TOP w4: R117.1@563.13,1783.3 584.7,1783.3 588.11,1779.89 588.11,1539.05 659.09,1468.07 731.23,1468.07 797.97,1401.33 797.97,1156.62 825.64,1128.95 825.64,1076.54 850.22,1051.97 898.48,1051.97 905.45,1044.99 905.45,1044.81 910.2,1040.06 U4.B6@919.13,1040.06
PWM_B1_L: R118.1 U4.C6 | length 1027.9
  L01-TOP w4: R118.1@563.13,1816.63 585.98,1816.63 596.83,1805.79 596.83,1541.65 662.41,1476.07 734.55,1476.07 805.97,1404.64 805.97,1159.94 833.64,1132.26 833.64,1095.01 850.29,1078.36 897.67,1078.36 907.2,1068.83 907.2,1060.75 915.92,1052.03 932.76,1052.03 U4.C6@944.73,1040.06
PWM_B2_H: R135.1 U4.E3 | length 1857.3
  L01-TOP w4: v2(983.07,950.65) 983.17,950.65 995.81,963.29 U4.E3@995.91,963.29 ; R135.1@1114.49,1779.83 1117.12,1782.45 v3(1146.75,1782.45)
  L03-SIG w4: v2(983.07,950.65) 983.15,950.65 1007.03,926.77 1036.04,926.77 1203.65,759.16 1203.65,728.38 1225.89,706.13 1443.53,706.13 1466.32,728.92 1466.32,801.73 1447.04,821.01 1447.04,1304.73 1173.42,1578.35 1173.42,1769.46 1162.59,1780.29 1148.91,1780.29 v3(1146.75,1782.45)
PWM_B2_L: R136.1 U4.F3 | length 1863
  L01-TOP w4: v2(1008.55,950.59) 1008.67,950.59 1021.37,963.29 U4.F3@1021.5,963.29 ; R136.1@1115.61,1812.98 v3(1144.13,1812.98)
  L03-SIG w4: v2(1008.55,950.59) 1023.53,950.59 1211.96,762.16 1211.96,731.38 1229.21,714.13 1440.21,714.13 1458.32,732.24 1458.32,798.41 1439.04,817.69 1439.04,1301.42 1165.42,1575.03 1165.42,1732.1 1117.86,1779.66 1117.86,1804.39 1126.53,1813.06 1144.05,1813.06 v3(1144.13,1812.98)
PWM_B3_H: R151.1 U4.C2 | length 2301.6
  L01-TOP w4: v2(931.72,924.85) 931.8,924.85 944.65,937.7 U4.C2@944.73,937.7 ; R151.1@1674.81,1779.98 1674.97,1779.83 v3(1704.59,1779.83)
  L03-SIG w4: v1(1487.06,958.45) 1503.95,958.45 1511.54,966.04 1511.54,1421.61 1654.79,1564.86 1654.79,1629.26 1704.59,1679.05 v3(1704.59,1779.83)
  L08-BOTTOM w4: v2(931.72,924.85) 918.87,937.7 849.21,937.7 801.37,889.87 801.37,656.78 882.22,575.93 1202.18,575.93 1440.98,814.73 1440.98,927.12 1471.22,957.35 1485.96,957.35 v1(1487.06,958.45)
PWM_B3_L: R152.1 U4.C3 | length 2382.8
  L01-TOP w4: v2(932.11,950.56) v2(932.11,950.56) 944.73,963.23 U4.C3@944.73,963.29 ; R152.1@1674.81,1813.57 1674.99,1813.75 v3(1706,1813.75)
  L03-SIG w4: v1(1487.06,930.1) 1502.65,930.1 1519.54,946.99 1519.54,1418.3 1662.79,1561.55 1662.79,1625.94 1720.13,1683.28 1720.13,1799.62 v3(1706,1813.75)
  L08-BOTTOM w4: v2(932.11,950.56) 850.75,950.56 793.37,893.18 793.37,653.47 878.91,567.93 1205.5,567.93 1448.98,811.41 1448.98,908.8 1470.29,930.1 v1(1487.06,930.1)
PWM_B4_H: R167.1 U4.E1 | length 2698.5
  L01-TOP w4: R167.1@2218.36,2021.79 v3(2245.41,2021.79)
  L01-TOP w5: v2(982.93,897.43) 982.93,898.28 995.91,911.26 U4.E1@995.91,912.11
  L03-SIG w4: v2(982.93,897.43) 1072.58,807.79 1072.58,751.41 1204.91,619.08 1569.48,619.08 1650.48,700.08 1650.48,1209.87 1734.15,1293.55 1867.81,1293.55 1910.55,1336.29 2077.74,1336.29 2093.38,1351.93 2093.38,1537.18 2049.52,1581.05 2049.52,1654.71 2151.16,1756.35 2151.16,1934.59 2199.33,1982.77 2199.33,2011.32 2210.31,2022.3 2244.91,2022.3 v3(2245.41,2021.79)
PWM_B4_L: R168.1 U4.E2 | length 2745.8
  L01-TOP w4: R168.1@2218.67,2055.27 2218.77,2055.38 v3(2244.57,2055.38)
  L01-TOP w5: v2(983.11,924.63) 983.11,924.77 995.91,937.56 U4.E2@995.91,937.7
  L03-SIG w4: v2(983.11,924.63) 995.82,911.92 995.91,911.92 997.84,909.99 1024.81,909.99 1080.58,854.22 1080.58,754.72 1208.22,627.08 1566.17,627.08 1642.48,703.39 1642.48,1213.19 1730.84,1301.55 1864.49,1301.55 1907.61,1344.66 2074.66,1344.66 2085.38,1355.38 2085.38,1533.87 2041.52,1577.73 2041.52,1658.02 2143.14,1759.65 2143.14,1937.89 2191.33,1986.08 2191.33,2027.94 2218.77,2055.38 v3(2244.57,2055.38)
PWM_B5_H: R183.1 U4.L10 | length 1448
  L01-TOP w4: U4.L10@1149.45,1142.42 1149.45,1142.5 1162.25,1155.29 v2(1162.25,1155.36) ; v1(1338.78,1288.03) 1563.75,1288.03 1732.37,1119.41 2109.35,1119.41 2190.01,1200.07 2190.01,1262.22 2224.28,1296.5 2224.28,1390.33 2212.41,1402.2 R183.1@2193.3,1402.2
  L08-BOTTOM w4: v2(1162.25,1155.36) 1162.25,1158.07 1166.95,1162.77 1166.95,1166.22 1288.63,1287.9 v1@1338.65,1287.9
PWM_B5_L: R184.1 U4.D11 | length 2106.9
  L01-TOP w4: v2(957.52,1181.08) 957.52,1180.94 970.32,1168.15 U4.D11@970.32,1168.01 ; v1(1337.99,1261.69) 1355.04,1261.69 1363.54,1270.19 1570.28,1270.19 1729.06,1111.41 2112.66,1111.41 2198.01,1196.76 2198.01,1258.91 2232.28,1293.19 2232.28,1412.04 2208.66,1435.67 R184.1@2193.3,1435.67
  L06-SIG w4: v1(897.59,1406.35) 877.07,1385.83 877.07,1332.54 957.52,1252.1 v2(957.52,1181.08)
  L08-BOTTOM w4: v1(897.59,1406.35) 897.59,1405.67 931.17,1372.09 1309.42,1372.09 1362.08,1319.43 1362.08,1268.8 1354.97,1261.69 v1(1337.99,1261.69)
PWM_B6_H: R199.1 U4.A3 | length 2778
  L01-TOP w4: U4.A3@893.54,963.29 852.17,963.29 828.17,939.29 828.17,796.62 883.93,740.86 921.13,740.86 1011.16,650.83 1267.44,650.83 1427.76,811.15 1520.1,811.15 1745.3,1036.35 2195.76,1036.35 2237.06,1077.64 v1(2240.68,1077.64) ; R199.1@2718.59,1729.93 2719,1730.34 v3(2749.38,1730.34)
  L03-SIG w4: v1(2240.68,1077.64) 2242.23,1077.64 2505.26,1340.67 2505.26,1484.01 2720.86,1699.6 2720.86,1727.59 2723.61,1730.34 v3(2749.38,1730.34)
PWM_B6_L: R200.1 U4.A2 | length 2719.4
  L01-TOP w4: U4.A2@893.54,937.7 849.21,937.7 844.17,932.66 844.17,803.25 890.56,756.86 927.76,756.86 1017.79,666.83 1260.81,666.83 1443.07,849.09 1546.73,849.09 1741.99,1044.35 2178.08,1044.35 2237.09,1103.36 v1(2240.03,1103.36) ; R200.1@2718.59,1763.35 v3(2744.49,1763.35)
  L03-SIG w4: v1(2240.03,1103.36) 2497.26,1360.59 2497.26,1487.32 2712.86,1702.92 2712.86,1749.63 2726.02,1762.8 2743.93,1762.8 v3(2744.49,1763.35)
PWM_C1_H: R123.1 U4.D6 | length 1439.1
  L01-TOP w4: R123.1@562.13,1850.1 585.98,1850.1 606.72,1829.36 606.72,1545.82 668.47,1484.07 737.86,1484.07 813.97,1407.96 813.97,1218.01 v9(828.94,1203.04) ; v2(957.52,1027) 957.52,1027.13 970.32,1039.93 U4.D6@970.32,1040.06
  L03-SIG w4: v9(828.94,1203.04) 748.04,1203.04 681.05,1136.04 681.05,1001.9 695.43,987.52 867.36,987.52 906.83,1027 v2(957.52,1027)
PWM_C1_L: R125.1 U4.E6 | length 1510.9
  L01-TOP w4: R125.1@562.13,1883.3 588.01,1883.3 615.72,1855.6 615.72,1549.4 673.05,1492.07 741.17,1492.07 821.97,1411.27 821.97,1234.06 828.94,1227.09 v9(828.94,1226.72) ; v2(982.84,1027.27) 982.98,1027.27 995.77,1040.06 U4.E6@995.91,1040.06
  L03-SIG w3.8: 856.39,979.52 870.53,979.52 905.41,1014.4 963.14,1014.4 969.57,1014.4
  L03-SIG w4: v9(828.94,1226.72) 760.41,1226.72 673.05,1139.36 673.05,998.59 692.11,979.52 856.39,979.52 ; 969.57,1014.4 982.44,1027.27 v2(982.84,1027.27)
PWM_C2_H: R141.1 U4.B3 | length 2300.8
  L01-TOP w4: U4.B3@919.13,963.29 906.42,976.01 853.57,976.01 820.17,942.6 820.17,793.31 880.62,732.86 917.82,732.86 1007.84,642.83 1270.75,642.83 1423.53,795.61 v1(1485.27,795.61) ; R141.1@1115.61,1846.55 1117.13,1848.07 v3(1144.13,1848.07)
  L03-SIG w4: v3(1144.13,1848.07) 1176.47,1848.07 1181.97,1842.57 1181.97,1581.11 1455.04,1308.04 1455.04,824.32 1483.75,795.61 v1(1485.27,795.61)
PWM_C2_L: R143.1 U4.B2 | length 2249.5
  L01-TOP w4: U4.B2@919.13,937.7 905.45,951.38 851.58,951.38 836.17,935.98 836.17,799.94 887.25,748.86 924.44,748.86 1014.47,658.83 1264.13,658.83 1433.08,827.79 v1(1485.96,827.79) ; R143.1@1115.61,1879.09 1115.9,1878.79 v3(1144.13,1878.79)
  L03-SIG w4: v3(1144.13,1878.79) 1173.75,1878.79 1190,1862.55 1190,1584.4 1463.04,1311.36 1463.04,847.97 1483.23,827.79 v1(1485.96,827.79)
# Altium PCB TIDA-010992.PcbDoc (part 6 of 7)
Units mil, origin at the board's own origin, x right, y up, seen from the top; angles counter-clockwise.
Board outline 2810.81 x 2427 mil, 8 copper layers (L01-TOP, L02-GND, L03-SIG, L04-GND, L05-PWR, L06-SIG, L07-GND, L08-BOTTOM), stack 61.9 mil thick; 521 components, 377 nets, 1545 pads, 874 vias.

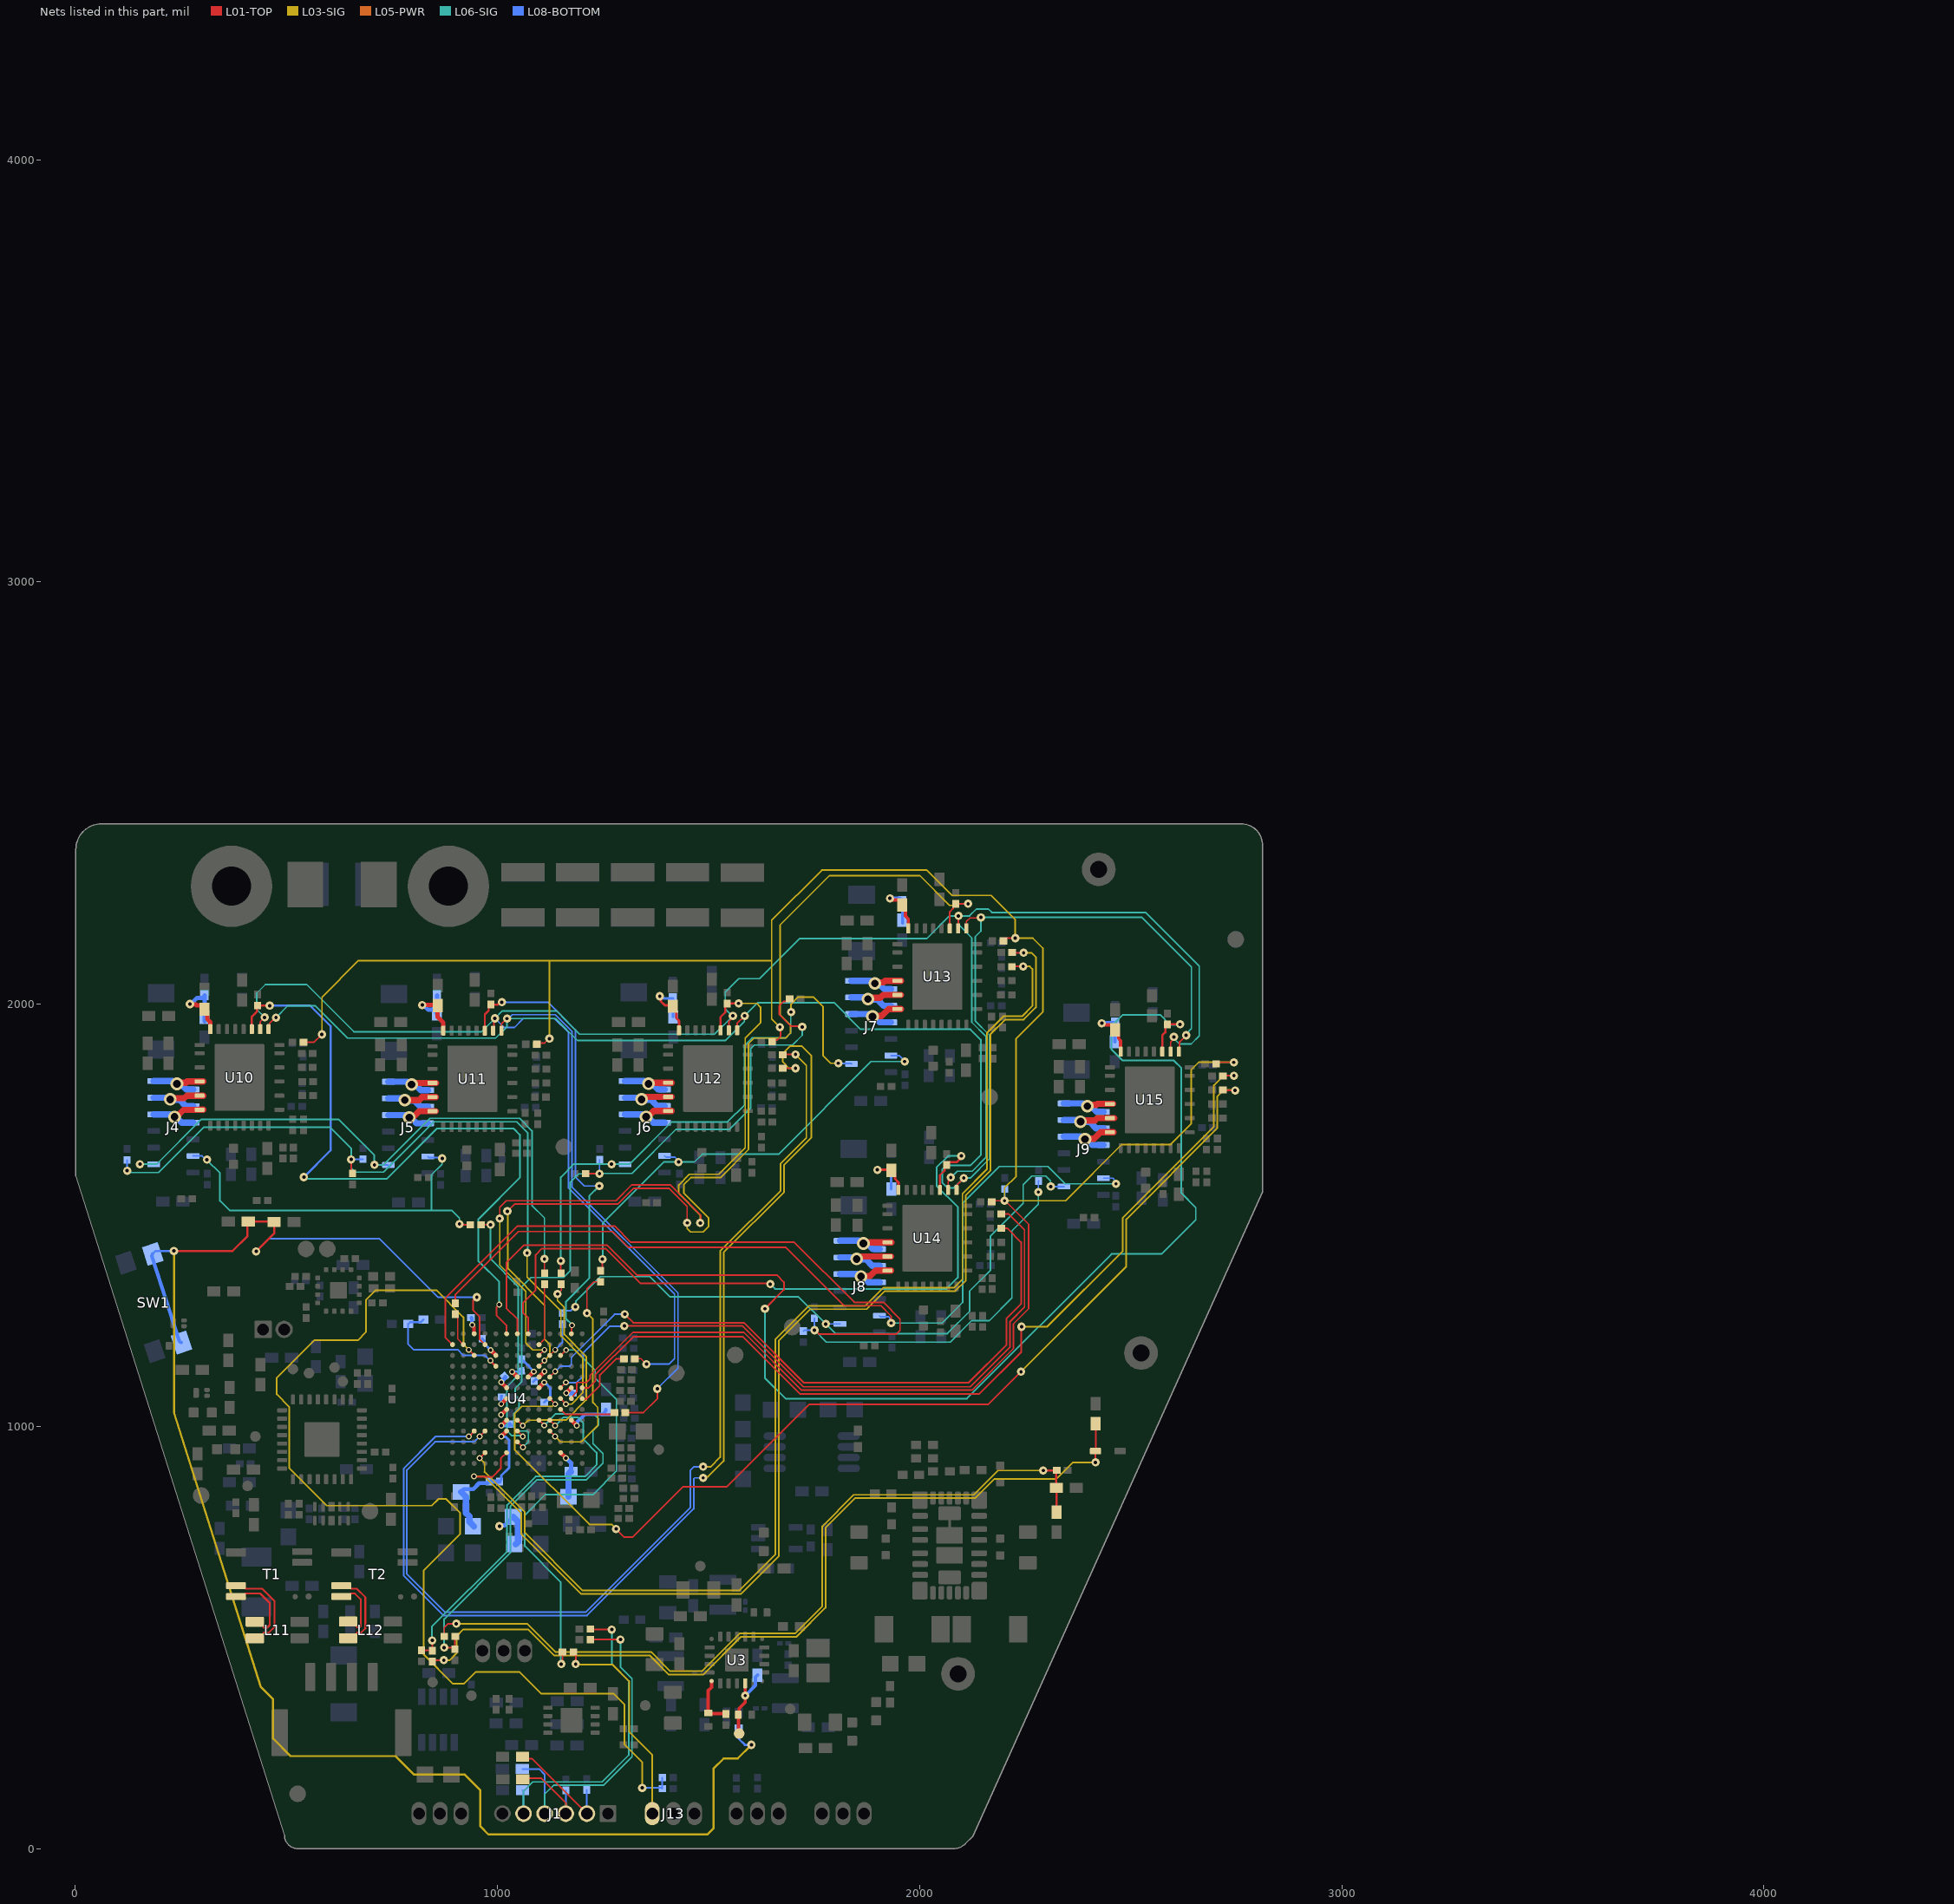
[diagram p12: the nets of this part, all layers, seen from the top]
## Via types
v1: diameter 19.68, hole 8, L01-TOP to L08-BOTTOM, tented both sides, 520 vias
v2: diameter 14, hole 8, L01-TOP to L08-BOTTOM, tented both sides, 146 vias
v3: diameter 19.68, hole 8, L01-TOP to L08-BOTTOM, 141 vias
v4: diameter 30, hole 18, L01-TOP to L08-BOTTOM, 18 vias
v5: diameter 22, hole 8, L01-TOP to L08-BOTTOM, tented both sides, 16 vias
v6: diameter 39.37, hole 19.68, L01-TOP to L08-BOTTOM, 12 vias
v7: diameter 22, hole 8, L01-TOP to L08-BOTTOM, 8 vias
v8: diameter 18, hole 8, L01-TOP to L08-BOTTOM, tented both sides, 5 vias
v9: diameter 14, hole 8, L01-TOP to L08-BOTTOM, 4 vias
v10: diameter 157.48, hole 98.43, L01-TOP to L08-BOTTOM, 4 vias

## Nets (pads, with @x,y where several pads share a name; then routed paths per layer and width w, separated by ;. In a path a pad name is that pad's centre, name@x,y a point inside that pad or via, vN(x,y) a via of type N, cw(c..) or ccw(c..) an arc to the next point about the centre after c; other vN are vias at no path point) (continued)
PWM_C3_H: R157.1 U4.C4 | length 2665.6
  L01-TOP w4: v2(931.94,975.96) v2(931.94,975.96) 944.73,988.81 U4.C4@944.73,988.88 ; R157.1@1675.64,1848.07 v3(1706,1848.07)
  L03-SIG w4: v1(1487.06,877.89) 1489.85,880.68 1498.68,880.68 1535.54,917.54 1535.54,1411.67 1678.79,1554.92 1678.79,1619.32 1743.81,1684.33 1743.81,1877.19 1720.13,1900.87 1693.57,1900.87 1675.83,1883.13 1675.83,1863.07 1690.82,1848.07 v3(1706,1848.07)
  L08-BOTTOM w4: v2(931.94,975.96) v2(931.94,975.96) 853.57,976.01 777.37,899.81 777.37,646.84 872.28,551.93 1212.12,551.93 1464.98,804.78 1464.98,875.55 1467.32,877.89 v1(1487.06,877.89)
PWM_C3_L: R159.1 U4.D4 | length 2532.2
  L01-TOP w4: v2(957.53,975.96) v2(957.53,975.96) 970.32,988.81 U4.D4@970.32,988.88 ; R159.1@1675.64,1880.31 1676.01,1880.68 v3(1706,1880.68)
  L03-SIG w4: v1(1487.06,904.32) 1505.12,904.32 1527.54,926.74 1527.54,1414.98 1670.79,1558.24 1670.79,1622.63 1731.66,1683.5 1731.66,1855.02 v3(1706,1880.68)
  L08-BOTTOM w4: v2(957.53,975.96) 957.12,975.96 944.42,963.26 852.14,963.26 785.37,896.49 785.37,650.15 875.6,559.93 1208.81,559.93 1456.98,808.1 1456.98,895.98 1465.32,904.32 v1(1487.06,904.32)
PWM_C4_H: R173.1 U4.D2 | length 2816.9
  L01-TOP w4: R173.1@2218.67,2088.74 2219.11,2089.18 v3(2245.15,2089.18)
  L01-TOP w5: v2(957.52,924.63) 957.52,924.77 970.32,937.56 U4.D2@970.32,937.7
  L03-SIG w3.8: 969.26,892.03 969.26,912.89
  L03-SIG w4: v2(957.52,924.63) 969.26,912.89 ; 969.26,892.03 1064.58,796.71 1064.58,748.09 1201.59,611.08 1572.79,611.08 1658.48,696.76 1658.48,1206.56 1737.47,1285.55 1871.12,1285.55 1913.86,1328.29 2081.06,1328.29 2101.38,1348.62 2101.38,1550.74 2159.47,1608.84 2159.47,1931.59 2199.31,1971.43 2243.05,1971.43 2267.21,1995.59 2267.21,2083.06 2261.09,2089.18 v3(2245.15,2089.18)
PWM_C4_L: R175.1 U4.F2 | length 2951.3
  L01-TOP w4: v2(944.26,881.71) 945.36,880.61 988.45,880.61 1007.81,899.97 1007.81,924.01 U4.F2@1021.5,937.7 ; R175.1@2219.15,2122.2 2219.76,2121.6 v3(2246.17,2121.6)
  L03-SIG w4: v2(944.26,881.71) 968.27,881.71 1056.58,793.4 1056.58,744.78 1198.28,603.08 1576.11,603.08 1666.48,693.45 1666.48,1203.25 1740.78,1277.55 1874.44,1277.55 1917.18,1320.29 2084.37,1320.29 2109.38,1345.3 2109.38,1547.43 2167.47,1605.53 2167.47,1928.28 2202.62,1963.43 2242.37,1963.43 2246.36,1963.43 2275.21,1992.28 2275.21,2111.17 2264.78,2121.6 v3(2246.17,2121.6)
PWM_C5_H: R189.1 U4.K9 | length 1575.5
  L01-TOP w4: U4.K9@1123.86,1116.83 1123.86,1116.97 v2(1136.65,1129.82) v2(1136.65,1129.82) ; v1(1301.43,1265.5) 1321.37,1245.56 1583.6,1245.56 1725.75,1103.41 2115.97,1103.41 2206.01,1193.44 2206.01,1255.6 2240.28,1289.87 2240.28,1435.83 2206.98,1469.13 R189.1@2193.3,1469.13
  L08-BOTTOM w3.8: v2(1136.65,1129.82) 1136.81,1129.82 1149.45,1142.46 1171.2,1142.46 1174.85,1146.1 1174.85,1162.95 1277.4,1265.5 v1(1301.43,1265.5)
PWM_C5_L: R191.1 U4.L8 | length 1618.3
  L01-TOP w4: U4.L8@1149.48,1091.24 v2(1162.12,1103.84) ; v1(1300.37,1237.56) 1580.28,1237.56 1724.2,1093.64 2119.43,1093.64 2214.01,1188.22 2214.01,1248.25 2248.28,1282.52 2248.28,1465.51 2213.21,1500.59 2211.2,1502.6 R191.1@2193.3,1502.6
  L08-BOTTOM w3.8: v2(1162.12,1103.84) 1162.24,1103.72 1187.51,1103.72 1203.23,1119.43 1203.23,1174.67 1265.23,1236.68 1299.49,1236.68 v1(1300.37,1237.56)
PWM_C6_H: R205.1 U4.K7 | length 2579.4
  L01-TOP w4: U4.K7@1123.86,1065.65 1123.86,1065.53 1136.65,1052.74 v2(1136.65,1052.62) ; v1(1280.95,757.12) 1300.57,737.5 1320.17,737.5 1439.76,857.09 1543.42,857.09 1738.67,1052.35 2162.79,1052.35 2239.62,1129.18 v1(2240.06,1129.18) ; R205.1@2718.59,1796.38 2719.45,1795.52 v3(2747.23,1795.52)
  L03-SIG w3.8: 1040.61,1030.39 1057.51,1047.29 1129.31,1047.29
  L03-SIG w4: 1040.61,1030.39 1040.61,944.83 1217.6,767.84 1270.23,767.84 v1(1280.95,757.12) ; 1129.31,1047.29 1134.64,1052.62 v2(1136.65,1052.62) ; v1(2240.06,1129.18) 2240.06,1129.51 2489.26,1378.71 2489.26,1490.63 2704.86,1706.23 2704.86,1780.73 2720.98,1796.86 2745.89,1796.86 v3(2747.23,1795.52)
PWM_C6_L: R207.1 U4.N8 | length 2135.8
  L01-TOP w3.8: 1231.73,1122.23 1321.4,1211.9
  L01-TOP w4: U4.N8@1200.63,1091.24 1215.68,1091.24 1231.73,1107.29 1231.73,1122.23 ; 1321.4,1211.9 1321.8,1212.3 1581.03,1212.3 1716.99,1076.35 2140.74,1076.35 2240.59,1176.19 2240.59,1235.2 v1(2241.32,1235.93) ; R207.1@2718.59,1829.56 2719.35,1830.32 v3(2744.49,1830.32)
  L03-SIG w4: v1(2241.32,1235.93) 2301.93,1235.93 2481.26,1415.26 2481.26,1493.95 2696.86,1709.55 2696.86,1807.82 2719.35,1830.32 v3(2744.49,1830.32)
SPIA_CLK_AX1_2: J4.11 J5.11 R29.2 | length 1502.8
  L01-TOP w3.75: R29.2@1111.2,1362.87 v3(1111.2,1396.3)
  L06-SIG w3.75: v3(153.14,1621.04) 192.28,1621.04 298.49,1727.25 623.61,1727.25 708.26,1642.59 v3@708.26,1619.5 ; v3(708.51,1619.26) 729.82,1619.26 839.93,1729.37 1052.15,1729.37 1081.6,1699.92 1081.6,1523.28 1111.2,1493.68 v3(1111.2,1396.3)
  L08-BOTTOM w3.75: v3(153.14,1621.04) 153.3,1620.88 185.33,1620.88 J4.11@185.49,1620.72 ; v3(708.51,1619.26) J5.11@741.4,1619.26
SPIA_CLK_AX12: R29.1 U4.J12 | length 148.6
  L01-TOP w3.75: U4.J12@1098.27,1193.6 1111.2,1206.54 R29.1@1111.2,1336.89
SPIA_PICO_AX1_2: J4.10 J5.10 R27.2 | length 942.9
  L01-TOP w3.75: v1(909.86,1479.24) 911.79,1477.31 R27.2@936.61,1477.31
  L06-SIG w3.75: v3(311.82,1631.7) 311.82,1630.3 342.47,1599.65 342.47,1534.04 365.21,1511.3 843.61,1511.3 ; v3(869.06,1634.52) 868.6,1634.06 868.6,1621.02 843.61,1596.04 843.61,1511.3 ; v1(909.86,1479.24) 909.86,1493.09 891.65,1511.3 843.61,1511.3
  L08-BOTTOM w3.75: J4.10@278.79,1640.41 279.02,1640.63 299.95,1640.63 308.88,1631.7 v3(311.82,1631.7) ; J5.10@834.7,1638.94 836.91,1636.73 866.85,1636.73 v3(869.06,1634.52)
SPIA_PICO_AX12: R27.1 U4.G4 | length 608.1
  L01-TOP w3.75: R27.1@962.6,1477.31 962.97,1477.69 v3(983.46,1477.69) ; U4.G4@1047.09,988.88 1047.09,988.76 1059.75,976.1 v2(1059.75,975.98)
  L06-SIG w3.75: v3(983.46,1477.69) 983.46,1396.57 1048.79,1331.24 1048.79,1120.05 1022.34,1093.6 1022.34,990.04 1034.49,977.89 1057.84,977.89 v2(1059.75,975.98)
SPIA_POCI_AX12: R116.1 R134.1 R219.2 U4.L7 | length 1955.6
  L01-TOP w3.75: v3(653.27,1632.17) 653.27,1602.78 R219.2@657,1599.05 ; U4.L7@1149.45,1065.65 1149.45,1065.53 1162.25,1052.74 v2(1162.25,1052.62)
  L03-SIG w3.75: v1(1070.04,1410.89) 1070.04,1353.41 1150.04,1273.41 1150.04,1214.78 1150.83,1213.99 1150.83,1213.46 1201.7,1162.59 1201.97,1162.32 1201.97,1079.11 1175.53,1052.67 1162.29,1052.67 v2(1162.25,1052.62)
  L06-SIG w3.75: v1(122.62,1605.49) 126.87,1605.49 131.3,1601.06 196.91,1601.06 304.5,1708.66 602.97,1708.66 653.27,1658.36 v3(653.27,1632.17) 653.27,1612.51 663.72,1602.06 729.86,1602.06 849.17,1721.37 1045.17,1721.37 1071.33,1695.2 1071.33,1412.18 v1(1070.04,1410.89)
  L08-BOTTOM w3.75: R116.1@122.04,1631.03 122.62,1630.45 v1(122.62,1605.49) ; v3(653.27,1632.17) 680.88,1632.17 R134.1@681.51,1632.8
SPIB_CLK_AX3_4: J6.11 J7.11 R35.2 | length 1381.9
  L01-TOP w3.75: v1(1149.99,1391.89) 1149.99,1363.73 R35.2@1150.84,1362.87
  L03-SIG w3.75: v1(1695.28,1981.19) 1695.28,1999.87 1712.31,2016.9 1748.38,2016.9 1770.87,1994.42 1770.87,1878.12 1789.11,1859.88 v3(1807.38,1859.88)
  L06-SIG w3.75: v1(1149.99,1391.89) 1149.99,1590.07 1181.16,1621.24 1269.74,1621.24 v1(1270.04,1620.94) 1312.64,1620.94 1412.62,1720.93 1544.83,1720.93 1585.35,1761.45 1585.35,1902.21 1602.88,1919.74 1682.76,1919.74 1694.76,1931.73 1694.76,1980.66 v1(1695.28,1981.19)
  L08-BOTTOM w3.75: v1(1270.04,1620.94) 1270.09,1620.89 1302.38,1620.89 J6.11@1302.44,1620.83 ; v3(1807.38,1859.88) 1808.11,1859.15 1837.91,1859.15 J7.11@1838.64,1858.42 J7.11@1838.36,1858.7
SPIB_CLK_AX34: R35.1 U4.G5 | length 498.6
  L01-TOP w3.75: U4.G5@1047.09,1014.47 v2(1059.87,1001.68) ; v1(1142.11,1313.39) 1142.11,1313.55 1151.15,1322.59 1151.15,1335.64 R35.1@1150.95,1335.84
  L03-SIG w3.75: v2(1059.87,1001.68) 1072.84,1014.65 1104.89,1014.65 1105.06,1014.82 1162.37,1014.82 1209.97,1062.42 1209.97,1165.48 1209.87,1165.58 ; v1(1142.11,1313.39) 1142.11,1297.9 1158.04,1281.96 1158.04,1217.56 1209.87,1165.73
SPIB_PICO_AX3_4: J6.10 J7.10 R34.2 | length 1068.4
  L01-TOP w3.75: R34.2@1244.46,1368.38 1248.41,1372.33 v1(1248.41,1395.89)
  L06-SIG w3.75: v1(1248.41,1395.89) 1249.09,1396.58 1249.09,1481.01 1394.04,1625.96 v3(1428.75,1625.96) 1466.04,1625.96 1484.65,1644.56 1665.51,1644.56 1884.91,1863.96 v3(1964.62,1863.96)
  L08-BOTTOM w3.75: J6.10@1395.75,1640.52 1398.77,1637.5 1419.91,1637.5 1428.75,1628.66 v3(1428.75,1625.96) ; J7.10@1931.95,1878.11 1951.44,1878.11 1964.62,1864.93 v3(1964.62,1863.96)
SPIB_PICO_AX34: R34.1 U4.K4 | length 514.3
  L01-TOP w3.75: U4.K4@1123.86,988.88 1123.86,988.8 1136.39,976.26 v2(1136.39,976.18) ; v1(1211.9,1267.89) 1211.9,1325.68 1228.62,1342.4 R34.1@1244.46,1342.4
  L03-SIG w3.75: v2(1136.39,976.18) 1136.53,976.18 1149.45,963.26 1198.54,963.26 1237.56,1002.27 1237.56,1044.82 1225.97,1056.41 1225.97,1253.82 v1(1211.9,1267.89)
  L06-SIG w3.75: v2(1136.39,976.18) v2@1136.39,976.41
SPIB_POCI_AX34: R150.1 R166.1 R218.2 U4.G3 | length 1767.7
  L01-TOP w3.75: U4.G3@1047.09,963.29 1047.22,963.29 1060.02,950.49 v2(1060.15,950.49) ; R218.2@1208.88,1598.07 1209.24,1598.42 v3(1241.56,1598.42) ; R166.1@1691.95,2012.39 1685.68,2006.12 1677.39,2006.12 1667.58,1996.31 1667.58,1974.99 1694.76,1947.81 1719.93,1947.81 v1(1721.86,1945.89)
  L06-SIG w3.75: v2(1060.15,950.49) 1060.15,950.7 1073.03,963.57 1073.03,986.31 1070.66,988.68 1047.4,988.68 1038.12,997.96 1038.12,1030.14 1050.91,1042.93 1050.91,1065.03 1041.71,1074.23 1041.71,1089.59 1057.01,1104.9 1057.01,1330.23 1079.45,1352.66 1155.97,1352.66 1172.6,1369.29 1172.6,1578.53 1192.13,1598.07 1241.2,1598.07 1242.28,1599.14 1318.58,1599.14 1422.91,1703.47 1549.85,1703.47 1599.42,1753.05 1599.42,1893.93 1608.64,1903.15 1698.83,1903.15 1721.86,1926.17 v1(1721.86,1945.89)
  L08-BOTTOM w3.75: v3(1241.56,1598.42) 1241.56,1630.95 R150.1@1241.73,1631.12
SPIC_CLK_AX5_6: J8.11 J9.11 R38.2 | length 1594.9
  L06-SIG w3.75: v3(1184.19,1282.95) 1185.44,1284.19 1185.44,1296.11 1243.96,1354.63 1361.09,1354.63 1409.09,1306.63 1713.16,1306.63 v1(1777.42,1242.37) 1800.09,1219.7 2065.72,1219.7 2118.38,1272.36 2118.38,1320.52 2167.87,1370.01 2167.87,1451.06 2245.06,1528.25 2245.06,1571.93 2266.13,1593 2298.33,1593 2309.9,1581.43 2309.9,1568.42 v3(2310.39,1567.93)
  L08-BOTTOM w3.75: R38.2@1153.69,1268.32 1159.46,1274.08 1174.01,1274.08 1182.87,1282.95 v3(1184.19,1282.95) ; v1(1777.42,1242.37) 1777.49,1242.44 1811.35,1242.44 J8.11@1811.42,1242.52 ; v3(2310.39,1567.93) J9.11@2342.03,1567.93
SPIC_CLK_AX56: R38.1 U4.K11 | length 86.7
  L01-TOP w3.75: U4.K11@1123.86,1168.15 v2@1136.65,1180.94
  L01-TOP w4: U4.K11@1123.86,1168.01 U4.K11@1123.86,1168.15 ; v2@1136.65,1180.94 v2(1136.65,1181.08)
  L08-BOTTOM w3.75: v2(1136.65,1181.08) 1153.69,1198.12 R38.1@1153.69,1242.33
SPIC_PICO_AX5_6: J8.10 J9.10 R37.2 | length 2135.3
  L01-TOP w3.75: R37.2@900.37,1291.63 900.37,1312.04 1049.59,1461.26 1272.58,1461.26 1309.63,1424.21 1682.5,1424.21 1821.16,1285.55 1908.16,1285.55 1932.48,1261.24 v1(1932.48,1244.71)
  L06-SIG w3.75: v1(1932.48,1244.71) 2052.88,1244.71 2101.66,1293.48 2101.66,1528.39 2188.83,1615.57 2303.88,1615.57 2345.15,1574.3 v3(2465.13,1574.3)
  L08-BOTTOM w3.75: J8.10@1904.73,1262.2 1907.64,1259.29 1926.68,1259.29 1929.67,1256.3 1929.67,1247.52 v1(1932.48,1244.71) ; J9.10@2435.34,1587.62 2457.51,1587.62 2462.51,1582.61 2462.51,1576.92 v3(2465.13,1574.3) v3@2466.45,1572.98
SPIC_PICO_AX56: R37.1 U4.B12 | length 79.8
  L01-TOP w3.75: R37.1@900.37,1265.64 905.66,1260.35 905.66,1207.08 U4.B12@919.13,1193.6
SPIC_POCI_AX56: R128.2 R182.1 R198.1 U4.A12 | length 2475
  L01-TOP w3.75: U4.A12@893.54,1193.6 876.17,1210.98 876.17,1302.83 1047.64,1474.3 1277.47,1474.3 1315.84,1435.93 1702.91,1435.93 1845.29,1293.55 1914.39,1293.55 1953.65,1254.3 1953.65,1226.94 1945.42,1218.71 1760.98,1218.71 1752.04,1227.66 v3(1750.84,1227.66)
  L06-SIG w3.75: v3(1750.84,1227.66) 1778.98,1199.52 2072.42,1199.52 2123.19,1250.29 2164.81,1250.29 2218.35,1303.83 2218.35,1462.93 2281.22,1525.8 v3(2281.22,1554.83)
  L08-BOTTOM w3.75: R128.2@1724.39,1225.41 1726.64,1227.66 v3(1750.84,1227.66) 1750.84,1255.84 R182.1@1750.59,1256.08 ; v3(2281.22,1554.83) 2281.22,1580.27 R198.1@2281.89,1580.94
SPID_CLK_DRV: R30.1 U4.N7 | length 152.8
  L01-TOP w3.75: U4.N7@1200.63,1065.65 1211.41,1065.65 1242.42,1096.66 1242.42,1121.63 1280.49,1159.71 1298.99,1159.71 R30.1@1299.61,1160.33
SPID_CLK_DRVCFG: R30.2 U10.22 U11.22 U12.22 U13.22 U14.22 U15.22 | length 4968.7
  L01-TOP w3.75: U10.22@437.83,1940.65 437.83,1958.17 v3(448.3,1968.64) ; U11.22@989.63,1937.31 991.71,1939.38 991.71,1964.24 v3(993.78,1966.31) ; R30.2@1325.6,1160.33 1339.74,1160.33 v3(1352.78,1147.28) ; U12.22@1548.01,1937.76 1548.01,1958.89 1557.48,1968.36 v3(1557.48,1972.33) ; U14.22@2067.66,1559.68 2067.66,1579.38 2073.67,1585.39 v3(2073.67,1589.36) ; U13.22@2091.08,2179.29 2091.44,2179.65 2091.44,2208.55 v3(2091.8,2208.91) ; U15.22@2594.35,1887.41 2596.78,1889.83 2594.35,1892.25 2594.35,1910.4 2602.24,1918.28 v3(2602.24,1922.26)
  L06-SIG w3.75: v3(448.3,1968.64) 429.57,1987.37 429.57,2025.92 450.11,2046.46 547.8,2046.46 659.81,1934.45 961.92,1934.45 v3(993.78,1966.31) 1011.37,1983.9 1139.61,1983.9 1194.74,1928.77 1513.91,1928.77 v3(1557.48,1972.33) 1555.81,1972.33 1539.49,1988.65 1539.49,2028.11 1571.66,2060.29 1620.31,2060.29 1715.23,2155.21 2016.65,2155.21 2070.35,2208.91 v3(2091.8,2208.91) ; v3(2073.67,1589.36) 2074.41,1589.36 2089.33,1604.28 2124.59,1604.28 2156.91,1636.6 2156.91,1923.59 2123.45,1957.05 2123.45,2156.87 2091.81,2188.51 v3(2091.8,2208.91) ; v3(2602.24,1922.26) 2602.24,1918.42 2615.03,1905.62 2643.27,1905.62 2662.43,1924.78 2662.43,2089.98 2535.25,2217.16 2170.85,2217.16 2162.9,2225.11 2134.37,2225.11 2118.16,2208.9 v3(2091.8,2208.91)
  L08-BOTTOM w3.75: v3(993.78,1966.31) 1015.36,1944.73 1039.83,1944.73 1060.78,1965.68 1135.2,1965.68 1168.28,1932.6 1168.28,1564.04 1419.2,1313.13 1419.2,1160.29 1406.19,1147.28 v3(1352.78,1147.28)
SPID_CS1_DRV: R121.1 U4.F13 U10.23 | length 1753.9
  L01-TOP w4: v2(1004.19,1288.57) 1004.19,1287.92 997.5,1281.23 997.5,1262.88 1021.5,1238.88 U4.F13@1021.5,1219.2 U4.F13@1021.24,1219.45
  L01-TOP w5: U10.23@418.14,1940.65 418.14,1970.24 429.73,1981.82 429.73,1994.7 R121.1@431.58,1996.55 431.83,1996.3 v3(460.44,1996.3)
  L06-SIG w4: v1(541.29,1590.37) 545.53,1590.37 549.85,1586.06 736.9,1586.06 856.21,1705.37 1038.54,1705.37 1052.99,1690.92 1052.99,1588.91 957.57,1493.49 954.37,1490.29 954.37,1391.71 957.57,1388.51 1004.19,1341.9 v2(1004.19,1288.57)
  L08-BOTTOM w5: v3(460.44,1996.3) 556.5,1996.3 604.79,1948.01 604.79,1653.88 v1(541.29,1590.37)
SPID_CS2_DRV: R139.1 U4.M13 U11.23 | length 1101.8
  L01-TOP w4: U4.M13@1175.04,1219.2 1175.75,1219.91 1175.75,1238.64 v2(1176.47,1239.35)
  L01-TOP w5: U11.23@969.95,1937.31 969.95,1975.71 979.16,1984.92 979.16,1994.36 R139.1@984.19,1999.39 985.36,1998.23 999.96,1998.23 1006.29,2004.56 v3(1010.17,2004.56)
  L06-SIG w4: v2(1176.47,1239.35) 1176.47,1240.36 1162.02,1254.8 1162.02,1295.44 1217.25,1350.67 1217.25,1545.42 v1(1241.1,1569.27)
  L08-BOTTOM w4: v3(1010.17,2004.56) 1118.95,2004.56 1184.28,1939.23 1184.28,1590.83 1205.84,1569.27 v1(1241.1,1569.27)
SPID_CS3_DRV: R155.1 U4.J11 U12.23 | length 1770
  L01-TOP w3.8: v1(1005.23,1492.26) 1005.23,1519.03 1020.48,1534.28 1280.49,1534.28 1318.16,1571.95 1409.19,1571.95 1482.01,1499.12 1482.01,1483.34 v1(1480.35,1481.68)
  L01-TOP w4: U4.J11@1098.27,1168.01 1098.27,1168.15 1111.06,1180.94 v2(1111.06,1181.08)
  L01-TOP w5: U12.23@1528.32,1937.76 1528.32,1969.15 1539.49,1980.31 1539.49,1997 R155.1@1543.82,2001.34 1544.25,2001.76 v3(1570.98,2001.76)
  L03-SIG w3.8: v1(1005.23,1492.26) 1005.23,1381.75 1066.97,1320.01 1066.97,1197.1 1082.99,1181.08 v2(1111.06,1181.08) ; v1(1480.35,1481.68) 1480.35,1500.78 1429.24,1551.89 1429.24,1571.61 1454.52,1596.89 1524.18,1596.89 1586.68,1659.39 1586.68,1919.42 1622.96,1955.7 1622.96,1992.88 1614.08,2001.76 v3(1570.98,2001.76)
SPID_CS4_DRV: R171.1 U4.J10 U13.23 | length 2553.7
  L01-TOP w3.7: v1(1023.27,1509.4) 1040.39,1526.53 1284.95,1526.53 1321.71,1563.29 1406.88,1563.29 1449.24,1520.93 v1(1449.24,1481.85) ; R171.1@2085.17,2237.74 v3(2114.79,2237.7)
  L01-TOP w4: U4.J10@1098.27,1142.42 1098.27,1142.56 1111.06,1155.35 v2(1111.06,1155.49) ; U13.23@2071.39,2179.29 2071.39,2218.75 2078.9,2226.26 2078.9,2231.48 R171.1@2085.17,2237.74
  L03-SIG w3.7: v1(1023.27,1509.4) 1024.63,1508.04 1024.63,1373.7 1111.2,1287.12 1111.2,1206.81 1123.86,1194.15 1123.86,1168.28 v2(1111.06,1155.49) ; v1(1449.24,1481.85) 1449.24,1468.17 1457.21,1460.21 1487.06,1460.21 1500.26,1473.41 1500.26,1493.47 1441.7,1552.03 1441.7,1572.98 1457.86,1589.14 1527.93,1589.14 1594.43,1655.64 1594.43,1906.33 1607.84,1919.74 1682.43,1919.74 1694.01,1931.31 1694.01,1950.38 1669.45,1974.94 1669.45,2187.41 1786.49,2304.44 2000.24,2304.44 2070.83,2233.85 2088.72,2233.85 2092.57,2237.7 v3(2114.79,2237.7)
SPID_CS5_DRV: R187.1 U4.H13 U14.23 | length 1725.2
  L01-TOP w4: U4.H13@1072.68,1219.2 1072.68,1256.63 1060.71,1268.6 1060.71,1292.93 1090.14,1322.36 1090.14,1406.35 1105.05,1421.26 1256.01,1421.26 1338.21,1339.06 1643.74,1339.06 v1(1646.05,1336.75)
  L01-TOP w5: U14.23@2047.98,1559.68 2047.98,1594.98 2059.06,1606.06 2059.06,1614.1 2067.81,1622.86 2067.81,1623.64 2069.77,1625.6 2087.49,1625.6 2098.52,1636.63 v3(2098.52,1640.54)
  L06-SIG w4: v1(1646.05,1336.75) 1657.46,1325.34 2063.53,1325.34 2090.35,1352.16 2090.35,1519.6 2040.26,1569.69 2040.26,1613.38 2067.42,1640.54 v3(2098.52,1640.54)
SPID_CS6_DRV: R203.1 U4.G13 U15.23 | length 3248.8
  L01-TOP w4: U4.G13@1047.09,1219.2 1047.09,1253.42 1021.21,1279.29 1021.21,1387.63 1062.84,1429.26 1259.32,1429.26 1330.2,1358.39 1661.54,1358.39 1678.62,1341.31 1678.62,1323.62 v1(1633.49,1278.48)
  L01-TOP w5: U15.23@2574.67,1887.41 2574.67,1926.19 2581.81,1933.33 2581.81,1946.68 2587.71,1952.58 2588.18,1952.1 v3(2616.85,1952.1)
  L06-SIG w4: v1(1633.49,1278.48) 1633.49,1114.51 1682.35,1065.66 2112.03,1065.66 2454.57,1408.2 2573.07,1408.2 2654.02,1489.15 2654.02,1517.95 2619.69,1552.28 2619.69,1848.71 2601.78,1866.62 2480.23,1866.62 2454.28,1892.56 2454.28,1947.54 2481.42,1974.67 2569.48,1974.67 2593.81,1950.34 2615.09,1950.34 v3(2616.85,1952.1)
SPID_PICO_DRV: R31.1 U4.L6 | length 134.2
  L01-TOP w3.75: U4.L6@1149.45,1040.06 1161.36,1028.16 1272.42,1028.16 R31.1@1276.85,1032.59
SPID_PICO_DRVCFG: R31.2 U10.21 U11.21 U12.21 U13.21 U14.21 U15.21 | length 5214.8
  L01-TOP w3.75: U10.21@457.51,1940.65 459.72,1942.86 459.72,1954.63 473.12,1968.03 v3(475.21,1968.03) ; U11.21@1009.32,1937.31 1009.32,1953.77 1021.23,1965.68 v3(1022.55,1965.68) ; R31.2@1302.83,1032.59 1345.9,1032.59 1378.61,1065.3 v3(1378.61,1089.05) ; U12.21@1567.69,1937.76 1567.69,1954.62 v3(1585.41,1972.33) ; U14.21@2087.35,1559.68 2089.77,1562.1 2089.77,1573.27 v3(2104.43,1587.93) ; U13.21@2110.76,2179.29 2110.76,2195.5 2119.39,2204.13 2143.95,2204.13 v3(2145.11,2205.29) ; U15.21@2614.04,1887.41 2615.81,1889.18 2615.81,1910.69 v3(2631.26,1926.14)
  L06-SIG w3.75: v3(475.21,1968.03) 503.48,1996.3 567.59,1996.3 644.46,1919.43 995.55,1919.43 1022.55,1946.43 v3(1022.55,1965.68) 1137.63,1965.68 1189.68,1913.62 1539.49,1913.62 1584.71,1958.83 1584.71,1971.63 1616.61,2003.54 1797.24,2003.54 1860.34,1940.44 2120.18,1940.44 2144.94,1915.68 2144.94,1642.33 2120.81,1618.2 2063.71,1618.2 2053.52,1608.01 2053.52,1577.04 2065.83,1564.73 2081.23,1564.73 v3(2104.43,1587.93) 2119.56,1587.93 2165.66,1634.03 2165.66,1926.16 2131.45,1960.37 2131.45,2159.34 2145.11,2173 v3(2145.11,2205.29) 2145.76,2204.65 2146.41,2205.29 2526.71,2205.29 2643.69,2088.31 2643.69,1941.77 2631.26,1929.34 v3(2631.26,1926.14)
  L08-BOTTOM w3.75: v3(1022.55,1965.68) 1026.07,1965.68 1035.51,1975.12 1137.07,1975.12 1176.28,1935.91 1176.28,1567.36 1427.58,1316.05 1427.58,1138.02 v3(1378.61,1089.05)
SPID_POCI_DRV: R120.1 R126.2 R138.1 R154.1 R170.1 R186.1 R202.1 U4.M7 | length 5700.9
  L01-TOP w3.75: R120.1@540.23,1909.46 564.98,1909.46 v3(583.78,1928.26) ; R138.1@1092.64,1907.75 1111.5,1907.75 1122.02,1918.28 v3(1122.96,1918.28) ; U4.M7@1174.55,1068.29 1187.4,1081.14 1187.4,1101.65 1189.63,1103.88 1210.96,1103.88 1219.27,1112.18 1219.27,1120.9 1321.21,1222.84 1583.12,1222.84 1720.2,1085.77 2123.72,1085.77 2222.08,1184.12 2222.08,1242.64 2258.01,1278.57 2258.01,1478.88 2202.63,1534.26 v3(2201.05,1534.26) R186.1@2170.52,1534.26 ; R154.1@1650.15,1913.49 1651.88,1915.22 1662.68,1915.22 1670.7,1923.24 1670.7,1943.82 v3(1668.96,1945.56) ; R170.1@2197.68,2152.3 2201.68,2156.29 v3(2226.33,2156.29) ; R202.1@2701.71,1860.63 2703.19,1862.11 v3(2744.21,1862.11)
  L03-SIG w3.75: v3(583.78,1928.26) 584.06,1928.54 584.06,2016.33 670.82,2103.1 1122.96,2103.1 ; v3(1122.96,1918.28) 1122.96,2103.09 ; v3(1668.96,1945.56) 1649.55,1964.97 1649.55,2103.1 ; v3(2744.21,1862.11) 2743.8,1862.52 2661.66,1862.52 2643.2,1844.06 2643.2,1716.1 2594.75,1667.64 2478.9,1667.64 2345.52,1534.26 v3(2201.05,1534.26) 2201.05,1564.85 2228.4,1592.2 2228.4,1918.2 2291.64,1981.43 2291.64,2132.75 2268.09,2156.29 v3(2226.33,2156.29) 2226.33,2200.27 2168.96,2257.63 2076.73,2257.63 2016.9,2317.46 1768.33,2317.46 1649.55,2198.68 1649.55,2103.1 ; 1122.96,2103.1 1649.55,2103.1
  L08-BOTTOM w3.75: v3(2201.05,1534.26) 2201.54,1534.75 R126.2@2201.54,1562.21
T0_RD_N: L11.1 T1.7 | length 189.7
  L01-TOP w4.25: T1.7@380.32,597.05 395.87,597.05 403.07,604.24 437.77,604.24 460.44,581.57 460.44,529.26 454.25,523.08 447.03,523.08 444.54,525.57 444.54,527.48 434.85,537.16 L11.1@425.01,537.16
T0_RD_P: L11.4 T1.6 | length 226.9
  L01-TOP w4.25: T1.6@380.32,622.64 395.87,622.64 403.07,615.44 442.41,615.44 471.64,586.21 471.64,524.62 458.89,511.88 447.03,511.88 444.54,509.39 444.54,507.48 434.85,497.79 L11.4@425.01,497.79
T0_TD_N: L12.1 T2.7 | length 156.4
  L01-TOP w4.25: T2.7@630.16,596.83 645.71,596.83 652.91,604.02 662.19,604.02 675.71,590.5 675.71,525.93 673.22,523.44 668.02,523.44 665.53,525.93 665.53,527.84 655.84,537.52 L12.1@646,537.52
T0_TD_P: L12.4 T2.6 | length 193.5
  L01-TOP w4.25: T2.6@630.16,622.42 645.71,622.42 652.91,615.22 666.83,615.22 686.91,595.14 686.91,521.29 677.86,512.24 668.02,512.24 665.53,509.75 665.53,507.84 655.84,498.15 L12.4@646,498.15
TCK: J1.4 R22.2 R24.1 | length 801.4
  L01-TOP w3.8: R24.1@1219.88,494.09 1220.72,494.93 v1(1291.31,494.93)
  L06-SIG w3.8: J1.4@1111.65,82.68 1111.65,129.02 1132.64,150 1251.09,150 1318.73,217.63 1318.73,402.18 1291.31,429.59 v1(1291.31,494.93)
  L08-BOTTOM w4: R22.2@1058.79,188.24 1098.77,188.24 1111.65,175.36 J1.4@1111.65,82.68
TDI: J1.3 R21.2 R25.1 | length 207.3
  L01-TOP w4: R21.2@1059.57,166.97 1102.9,166.97 1161.65,108.22 J1.3@1161.65,82.68
  L08-BOTTOM w4: J1.3@1161.65,82.68 R25.1@1161.65,138.02
TDO: J1.5 R23.2 R26.1 | length 758.9
  L01-TOP w3.8: R26.1@1220.11,518.7 v1(1270.75,518.7)
  L06-SIG w3.8: J1.5@1061.65,82.68 1061.65,135.75 1083.71,157.8 1247.69,157.8 1310.93,221.03 1310.93,397.2 1270.75,437.37 v1(1270.75,518.7)
  L08-BOTTOM w4: R23.2@1059.38,138.02 1061.65,135.75 J1.5@1061.65,82.68
Temp_PCB: R45.1 R214.1 RT1.2 | length 2082.1
  L01-TOP w4: R45.1@845.26,442.78 848.68,446.2 v1(872.77,446.2) ; v1(2416.58,914.72) RT1.2@2416.6,941.28 ; RT1.2@2416.6,941.28 2416.96,941.64 R214.1@2416.96,1006.62
  L03-SIG w4: v1(872.77,446.2) 886.82,446.2 903.12,462.5 903.12,503.27 918.49,518.64 1072.82,518.64 1133.94,457.52 1360.25,457.52 1405.9,411.87 1487.38,411.87 1576.92,501.4 1707.96,501.4 1777.22,570.66 1777.22,759.97 1847.08,829.84 2131.47,829.84 2177.22,875.59 2324.26,875.59 2363.4,914.72 v1(2416.58,914.72)
TEMP_SEN: C47.1 R45.2 U4.K5 | length 907.1
  L01-TOP w4: C47.1@820.17,469.29 844.74,469.29 R45.2@845.26,468.77 845.22,468.81 v1(845.22,493.11) ; U4.K5@1123.86,1014.47 1123.86,1014.34 1136.46,1001.74 v2(1136.46,1001.6)
  L06-SIG w4: v1(845.22,493.11) 844.16,494.17 844.16,525.2 1022.43,703.46 1022.43,813.35 1090.4,881.32 1207.41,881.32 1234.77,908.69 1234.77,937.62 1203.53,968.85 1203.53,1007.77 1189.79,1021.51 1156.56,1021.51 1136.65,1001.6 v2(1136.46,1001.6)
TMS: J1.2 R20.1 R28.1 | length 264.1
  L01-TOP w4: R20.1@1059.44,217.24 1064.27,212.41 1081.92,212.41 J1.2@1211.65,82.68
  L08-BOTTOM w4: R28.1@1211.2,138.6 1211.2,83.13 J1.2@1211.65,82.68
U1: J4.1 J4.2 U10.4 | length 166.2
  L01-TOP w15: v4(240.59,1811.16) 243.46,1814.03 261.53,1814.03 264.14,1816.63 U10.4@294.12,1816.63 294.22,1816.73 U10.4@303.06,1816.73
  L08-BOTTOM w15: J4.1@185.49,1817.57 230.11,1817.57 236.53,1811.16 v4(240.59,1811.16) 243.46,1808.29 252.28,1808.29 262.68,1797.89 J4.2@278.79,1797.89
U2: J5.1 J5.2 U11.4 | length 160.7
  L01-TOP w15: v4(796.5,1809.7) 800.55,1809.7 804.15,1813.29 U11.4@845.93,1813.29 845.98,1813.34 U11.4@854.25,1813.34
  L08-BOTTOM w15: J5.1@741.4,1816.11 786.02,1816.11 792.44,1809.7 v4(796.5,1809.7) 799.37,1806.83 808.19,1806.83 818.59,1796.42 J5.2@834.7,1796.42
U3: J6.1 J6.2 U12.4 | length 157.6
  L01-TOP w15: v4(1357.54,1811.27) 1360.01,1813.75 U12.4@1404.31,1813.75 ; U12.4@1404.37,1813.69 U12.4@1412.69,1813.69
  L08-BOTTOM w15: J6.1@1302.44,1817.69 1347.07,1817.69 1353.48,1811.27 v4(1357.54,1811.27) 1360.41,1808.4 1369.23,1808.4 1379.63,1798 J6.2@1395.75,1798
U4: J7.1 J7.2 U13.4 | length 166.3
  L01-TOP w15: v4(1893.74,2048.86) 1896.61,2051.73 1914.69,2051.73 1918.23,2055.27 U13.4@1955.97,2055.27
  L08-BOTTOM w15: J7.1@1838.64,2055.27 1883.27,2055.27 1889.68,2048.86 v4(1893.74,2048.86) 1896.61,2045.99 1905.43,2045.99 1915.84,2035.59 J7.2@1931.95,2035.59
U5: J8.1 J8.2 U14.4 | length 168.9
  L01-TOP w15: v4(1866.71,1433.14) 1869.24,1435.67 U14.4@1933.13,1435.67
  L08-BOTTOM w15: J8.1@1811.61,1439.56 1856.24,1439.56 1862.66,1433.14 v4(1866.71,1433.14) 1869.58,1430.28 1878.41,1430.28 1888.81,1419.87 J8.2@1904.92,1419.87
U6: J9.1 J9.2 U15.4 | length 164.8
  L01-TOP w15: v4(2397.13,1758.37) 2400,1761.24 2418.08,1761.24 2420.69,1763.85 U15.4@2458.24,1763.85
  L08-BOTTOM w15: J9.1@2342.03,1764.78 2386.66,1764.78 2393.07,1758.37 v4(2397.13,1758.37) 2400,1755.5 2408.83,1755.5 2419.23,1745.1 J9.2@2435.34,1745.1
UART_TX: J13.1 R40.2 | length 510.2
  L01-TOP w4: R40.2@1180.07,465.22 1185.18,460.11 v1(1185.18,436.99)
  L03-SIG w4: v1(1185.18,436.99) 1186.49,435.68 1272.45,435.68 1311.87,396.25 1311.87,276.72 1366.62,221.96 J13.1@1366.62,82.68
UARTA_RX: R89.1 R216.1 U4.C11 | length 2596.7
  L01-TOP w4: v2(931.93,1181.08) 931.93,1180.94 944.73,1168.15 U4.C11@944.73,1168.01
  L01-TOP w6: U4.C11@944.73,1168.01 U4.C11@944.73,1168.12
  L03-SIG w4: v2(931.93,1181.08) 919.13,1193.87 919.13,1258.43 854.95,1322.61 711.87,1322.61 688.06,1298.8 688.06,1223.01 669.07,1204.02 566,1204.02 476.9,1114.92 476.9,1075.69 506.35,1046.24 506.35,901.23 595.44,812.14 844.32,812.14 859.96,827.79 878.48,827.79 911.51,794.76 911.51,744.99 825.41,658.89 825.41,459.29 894.35,390.35 920.5,390.35 948.76,418.62 1051.55,418.62 1103.05,367.11 1274.78,367.11 1300.23,341.66 1300.23,247.24 1342.99,204.49 1342.99,143.84 v1(1342.79,143.64)
  L08-BOTTOM w4: v1(1342.79,143.64) 1388.74,143.64 R216.1@1390.38,142 R89.1@1390.38,168.04
UARTA_TX: R40.1 U4.L11 | length 1045.4
  L01-TOP w3.8: v1(1150.91,436.99) 1153.95,440.03 1153.95,451.04 1154.17,451.25 1154.17,465.14 R40.1@1154.08,465.22
  L01-TOP w4: U4.L11@1149.45,1168.01 1149.58,1168.01 1162.38,1180.81 v2(1162.51,1180.81)
  L06-SIG w3.8: v1(1150.91,436.99) 1149.58,438.32 1149.58,631.34 1064.46,716.46 1064.46,789.89 1112.73,838.16 1225.74,838.16 1281.69,894.11 1281.69,1063.78 1231.33,1114.14 1231.33,1132.96 1183.48,1180.81 v2(1162.51,1180.81)
V1: J4.3 J4.4 U10.5 | length 183.7
  L01-TOP w15: v4(224.54,1774.32) 227.41,1777.19 258.16,1777.19 264.14,1783.17 U10.5@294.12,1783.17 294.16,1783.21 U10.5@303.06,1783.21
  L08-BOTTOM w15: J4.3@185.49,1778.2 216.59,1778.2 220.48,1774.32 v4(224.54,1774.32) 225.49,1773.36 246.61,1773.36 261.45,1758.52 J4.4@278.79,1758.52
V1P8: C25.1 C26.1 TP8.1 U3.5 | length 189.3
  L01-TOP w8: TP8.1@1570.47,265.67 C25.1@1570.47,316.78 ; C25.1@1570.7,320.69 1572.48,322.47 1572.48,332.31 1586.74,346.58 v1(1586.74,362.12) U3.5@1586.74,391.42
  L08-BOTTOM w8: v1(1586.74,362.12) 1611.08,386.46 1611.13,386.46 1611.13,406.15 C26.1@1615.82,410.83
V2: J5.3 J5.4 U11.5 | length 177.9
  L01-TOP w15: v4(780.44,1772.86) 814.76,1772.86 821.73,1779.83 U11.5@845.93,1779.83 ; U11.5@853.96,1779.86 U11.5@845.97,1779.86 ; U11.5@845.93,1779.83 U11.5@845.97,1779.86
  L08-BOTTOM w15: J5.3@741.4,1776.74 772.5,1776.74 776.39,1772.86 v4(780.44,1772.86) 781.4,1771.9 802.52,1771.9 817.36,1757.05 J5.4@834.7,1757.05
V3: J6.3 J6.4 U12.5 | length 174.6
  L01-TOP w15: v4(1341.49,1774.43) 1345.55,1774.43 1351.4,1780.28 U12.5@1404.31,1780.28 U12.5@1412.19,1780.29
  L08-BOTTOM w15: J6.3@1302.44,1778.32 1333.55,1778.32 1337.43,1774.43 v4(1341.49,1774.43) 1342.45,1773.47 1363.56,1773.47 1378.41,1758.63 J6.4@1395.75,1758.63
V4: J7.3 J7.4 U13.5 | length 183.3
  L01-TOP w15: v4(1877.69,2012.02) 1880.56,2014.89 1906.42,2014.89 1913.33,2021.81 U13.5@1947.38,2021.81 U13.5@1955.49,2021.81
  L08-BOTTOM w15: J7.3@1838.64,2015.9 1869.75,2015.9 1873.63,2012.02 v4(1877.69,2012.02) 1878.65,2011.06 1899.76,2011.06 1914.61,1996.22 J7.4@1931.95,1996.22
V5: J8.3 J8.4 U14.5 | length 185.3
  L01-TOP w15: v4(1850.66,1396.3) 1854.72,1396.3 1860.62,1402.2 U14.5@1932.08,1402.2
  L08-BOTTOM w15: J8.3@1811.61,1400.19 1842.72,1400.19 1846.6,1396.3 v4(1850.66,1396.3) 1851.62,1395.35 1872.74,1395.35 1887.58,1380.5 J8.4@1904.92,1380.5
V6: J9.3 J9.4 U15.5 | length 185.3
  L01-TOP w15: v4(2381.08,1721.53) 2383.95,1724.4 2414.7,1724.4 2420.23,1729.93 U15.5@2450.65,1729.93 ; U15.5@2450.71,1729.99 U15.5@2461.47,1729.99
  L08-BOTTOM w15: J9.3@2342.03,1725.41 2373.14,1725.41 2377.02,1721.53 v4(2381.08,1721.53) 2382.04,1720.57 2403.16,1720.57 2418,1705.73 J9.4@2435.34,1705.73
VBUS_SEN: C46.1 R44.2 U4.J5 | length 1004.2
  L01-TOP w4: v1(873.52,476.06) 894.96,476.06 C46.1@898.97,472.06 898.97,504.72 R44.2@899.97,505.73 ; U4.J5@1098.27,1014.47 1098.39,1014.47 1110.74,1002.12 v2(1110.87,1002.12)
  L06-SIG w4: v1(873.52,476.06) 873.52,543.24 1030.43,700.15 1030.43,810.04 1093.71,873.32 1210.72,873.32 1249.88,912.48 1249.88,935.83 1226.22,959.49 1226.22,989.74 1238.66,1002.18 1238.66,1018.17 1227.32,1029.51 1138.26,1029.51 v2(1110.87,1002.12)
VBUS_SENSE: C202.1 R44.1 R210.1 R213.2 | length 1930.3
  L01-TOP w4: R44.1@873.9,502.33 873.9,523.67 882.31,532.08 901.7,532.08 v1(902.25,532.63)
  L01-TOP w5: v1(2292.6,895.35) C202.1@2323.71,895.35 ; R210.1@2324.18,797.02 2324.18,854.24 R213.2@2323.7,854.72 C202.1@2323.7,895.33 ; C202.1@2323.71,895.35 C202.1@2324.53,896.17 C202.1@2323.7,895.33
  L03-SIG w4: v1(902.25,532.63) 902.8,532.08 1070.69,532.08 1137.25,465.52 1363.57,465.52 1409.22,419.87 1484.07,419.87 1573.6,509.4 1704.65,509.4 1769.22,573.97 1769.22,763.28 1843.77,837.84 2128.15,837.84 2175.47,885.16 2185.66,895.35 v1(2292.6,895.35)
VDD: C75.1 C76.1 C77.1 C78.1 C79.1 L5.2 U4.F5 U4.F7 U4.G9 U4.J9 | length 290.5
  L01-TOP w10: v2(1008.57,1052.72) U4.F7@1021.5,1065.65 ; v2(1009.15,1001.85) 1009.15,1001.99 1021.5,1014.33 U4.F5@1021.5,1014.47 ; v2(1034.58,1129.06) 1034.72,1129.06 1046.95,1116.83 U4.G9@1047.09,1116.83 ; U4.J9@1098.27,1116.83 1098.27,1116.97 v2(1111.06,1129.82) v2(1111.06,1129.82)
  L08-BOTTOM w6: v2(1008.57,1052.72) 1008.57,1070.99 C76.1@1009.62,1072.05 ; C79.1@1029.57,1005.37 C79.1@1034.42,1000.52 ; v2(1034.58,1129.06) 1035.12,1129.6 1053.4,1129.6 C77.1@1053.8,1130 ; C78.1@1084.71,1105.14 1084.71,1105.93 1089.98,1111.2 1093.82,1111.2 1111.06,1128.44 v2(1111.06,1129.82)
  L08-BOTTOM w10: v1(1004.69,763.38) 1006.54,765.23 1016.29,765.23 1036.32,785.26 C75.1@1037.3,785.26 ; v2(1009.15,1001.85) 1009.92,1002.62 1026.82,1002.62 C79.1@1029.57,1005.37
  L08-BOTTOM w15: C75.1@1037.3,785.26 1048.24,774.31 1048.24,726.16 L5.2@1043.03,720.95
VDDA: C82.1 C83.1 L6.2 U4.L2 U4.M5 | length 230.8
  L01-TOP w10: U4.L2@1149.45,937.7 1149.45,937.56 1162.25,924.77 v2(1162.25,924.63) ; U4.M5@1175.04,1014.47 1175.16,1014.47 1187.75,1001.88 v2(1187.88,1001.88)
  L05-PWR w10: v2(1162.25,924.63) v2@1163.01,925.4
  L08-BOTTOM w8: v2(1187.88,1001.88) 1189.03,1003.03 1189.03,1010.82 1206.91,1028.71 1248.99,1028.71 1256.8,1036.52 C82.1@1256.8,1040.24
  L08-BOTTOM w10: v2(1162.25,924.63) 1174.4,912.48 C83.1@1174.4,890.65
  L08-BOTTOM w15: L6.2@1168.14,833.15 1168.14,887.85 1172.45,892.16 C83.1@1174.35,892.16
VDDIO: C85.1 C86.1 C87.1 C88.1 C89.1 C90.1 C91.1 C92.1 C93.1 L7.2 U4.C13 U4.E11 U4.F4 U4.F6 U4.F8 U4.H9 U4.J8 U4.M8 | length 665.1
  L01-TOP w8: v2(940.33,1240.37) 940.33,1238.74 944,1235.08 944,1219.92 U4.C13@944.73,1219.2 ; U4.E11@995.77,1168.01 U4.E11@995.91,1168.01
  L01-TOP w10: v2(983.7,1180.48) 983.7,1180.35 995.77,1168.28 U4.E11@995.77,1168.01 ; v2(1008.43,1027.27) 1008.57,1027.27 1021.36,1040.06 U4.F6@1021.5,1040.06 ; v2(1008.7,1104.31) 1008.7,1104.17 1021.5,1091.38 U4.F8@1021.5,1091.24 ; v2(1008.8,976.3) 1008.86,976.3 1021.43,988.88 U4.F4@1021.5,988.88 ; U4.H9@1072.68,1116.83 1072.81,1116.83 1085.61,1129.63 v2(1085.74,1129.63) ; U4.J8@1098.27,1091.24 1098.27,1091.38 1110.59,1103.7 v2(1110.59,1103.84) ; v2(1162.72,1078.64) 1162.72,1078.78 1175.04,1091.1 U4.M8@1175.04,1091.24
  L05-PWR w10: v2(1008.43,1027.27) v2@1008.7,1027
  L08-BOTTOM w6: C93.1@963.38,1207.74 968.65,1202.48 968.65,1195.76 983.7,1180.71 v2(983.7,1180.48) ; C90.1@1004.96,869.2 1008.85,873.1 1008.85,883.36 1027.22,901.73 1027.22,967.2 1019.66,974.77 1010.33,974.77 v2(1008.8,976.3) ; C87.1@1057.05,1159.08 1057.05,1158.29 1062.32,1153.02 1063.11,1153.02 1085.74,1130.39 v2(1085.74,1129.63) ; C88.1@1110.41,1056.67 1115.68,1061.94 1121.25,1061.94 1124.76,1065.45 1124.76,1091.14 1112.07,1103.84 v2(1110.59,1103.84)
  L08-BOTTOM w8: C89.1@937.97,1257.66 939.19,1256.44 939.19,1241.51 v2(940.33,1240.37)
  L08-BOTTOM w10: C85.1@913.99,844.51 920.63,851.15 942.32,851.15 956.62,865.45 976.88,865.45 980.23,868.8 980.23,869.11 1004.87,869.11 C90.1@1004.96,869.2 ; v2(1008.7,1104.31) 1008.7,1105.39 1017.96,1114.64 C86.1@1017.96,1117.06 ; v2(1162.72,1078.64) 1162.78,1078.58 1178.05,1078.58 C91.1@1178.11,1078.52
  L08-BOTTOM w15: C85.1@913.99,844.51 925.11,833.39 925.11,794.94 933.16,786.89 933.16,774.29 L7.2@944.36,763.09
VLDO: C39.2 C40.2 U3.1 | length 121.6
  L01-TOP w8: U3.1@1507.26,396.59 1506.85,396.17 1506.85,381.8 1499.26,374.21 C39.2@1499.26,321.05 1500.56,319.75 1539.67,319.75 C40.2@1540.97,318.46
VLIMIT1: C126.2 R127.1 R129.2 U10.28 | length 200.8
  L01-TOP w10: v1(271.39,2000.17) 272.52,1999.04 285.4,1999.04 287.06,1997.38 299.33,1997.38 303.52,1993.19 303.52,1990.31 312.27,1981.55 312.27,1965.04 319.72,1957.59 U10.28@319.72,1940.65
  L08-BOTTOM w10: v1(271.39,2000.17) 274.01,2000.17 288.64,2014.79 301.3,2014.79 306.14,2019.64 R129.2@306.14,2020.96 R127.1@306.14,1958.52
VLIMIT2: C141.2 R144.1 R145.2 U11.28 | length 190.3
  L01-TOP w10: v1(821.82,1997.93) 851.22,1997.93 855.52,1993.63 C141.2@855.52,1992.7 ; C141.2@858.03,1996.43 858.03,1969.43 871.52,1955.94 U11.28@871.52,1937.31
  L08-BOTTOM w10: v1(821.82,1997.93) 824.44,1997.93 835.88,1986.5 849.87,1986.5 856.79,1979.58 R144.1@856.79,1978.85 ; R145.2@856.47,2020.82 856.79,2020.5 R144.1@856.79,1975.12
VLIMIT3: C156.2 R160.1 R161.2 U12.28 | length 183.5
  L01-TOP w6: v1(1384.44,2018.75) 1387.06,2016.13 1387.06,2006.61 1396.83,1996.84 1406.78,1996.84 1415.37,1988.25 C156.2@1415.37,1984.66 ; C156.2@1417.04,1985.57 1424.18,1978.42 1424.18,1966.22 1429.9,1960.51 U12.28@1429.9,1937.76
  L08-BOTTOM w6: v1(1384.44,2018.75) 1388.14,2018.75 1392.97,2013.92 1415.51,2013.92 R161.2@1415.59,2013.84 ; R160.1@1415.93,1969.51 R161.2@1415.93,2013.92
VLIMIT4: C171.2 R176.1 R177.2 U13.28 | length 183.9
  L01-TOP w8: v1(1929.67,2250.55) 1932.83,2250.55 1936.45,2246.92 1950.4,2246.92 1953.06,2244.25 1953.06,2240.32 1966.02,2227.36 1966.02,2208.75 1972.97,2201.8 U13.28@1972.97,2179.29
  L08-BOTTOM w8: v1(1929.67,2250.55) 1953.01,2250.55 1959.73,2243.83 R176.1@1959.73,2191.97
VLIMIT5: C186.2 R192.1 R193.2 U14.28 | length 166.7
  L01-TOP w6: v1(1899.76,1607.57) 1932.31,1607.57 1941.53,1598.35 1941.53,1586.28 1949.55,1578.26 U14.28@1949.55,1559.68
  L08-BOTTOM w6: v1(1899.76,1607.57) R193.2@1933.06,1607.57 ; R192.1@1932.82,1561.9 1932.82,1607.29 R193.2@1933.08,1607.55
VLIMIT6: C201.2 R208.1 R209.2 U15.28 | length 176.6
  L01-TOP w8: v1(2431.33,1954.62) 2434.49,1954.62 2438.39,1950.72 2455.51,1950.72 2463.32,1942.91 C201.2@2463.32,1938.97 2471.14,1931.16 2471.14,1918.53 2476.24,1913.42 U15.28@2476.24,1887.41
  L08-BOTTOM w8: v1(2431.33,1954.62) 2433.26,1956.55 R209.2@2463.32,1956.55 2462.34,1955.57 R208.1@2462.34,1910.82
VREGENZ: R33.1 R36.2 U4.E10 | length 317.2
  L01-TOP w5: v2(983.11,1155.49) 983.11,1155.35 995.91,1142.56 U4.E10@995.91,1142.42
  L08-BOTTOM w4: R33.1@788.32,1242.31 788.32,1194.58 801.19,1181.7 905.45,1181.7 919.13,1168.01 970.59,1168.01 v2(983.11,1155.49)
  L08-BOTTOM w5: R33.1@788.55,1242.31 792.7,1246.45 818.15,1246.45 R36.2@824.36,1252.66
W1: J4.5 J4.6 U10.6 | length 175.2
  L01-TOP w15: v4(235.09,1732.85) 239.15,1732.85 256.01,1749.71 U10.6@294.12,1749.71 294.16,1749.74 U10.6@302.78,1749.74
  L08-BOTTOM w15: J4.5@185.49,1738.83 225.05,1738.83 231.03,1732.85 v4(235.09,1732.85) ; v4@236.71,1734.47 252.03,1719.15 J4.6@278.79,1719.15
W2: J5.5 J5.6 U11.6 | length 169.7
  L01-TOP w15: v4(791,1731.38) 793.87,1734.25 802.03,1734.25 814.14,1746.36 U11.6@845.93,1746.36 846,1746.43 U11.6@853.92,1746.43
  L08-BOTTOM w15: J5.5@741.4,1737.37 780.96,1737.37 786.94,1731.38 v4(791,1731.38) ; v4@792.62,1733 807.94,1717.68 J5.6@834.7,1717.68
W3: J6.5 J6.6 U12.6 | length 166.4
  L01-TOP w15: v4(1352.05,1732.96) 1356.1,1732.96 1369.96,1746.82 U12.6@1404.31,1746.82 ; U12.6@1404.31,1746.82 U12.6@1412.19,1746.84
  L08-BOTTOM w15: J6.5@1302.44,1738.95 1342,1738.95 1347.99,1732.96 v4(1352.05,1732.96) ; v4@1353.67,1734.58 1368.99,1719.26 J6.6@1395.75,1719.26
W4: J7.5 J7.6 U13.6 | length 175.3
  L01-TOP w15: v4(1888.25,1970.55) 1889.64,1971.94 1909.89,1971.94 1926.29,1988.34 U13.6@1947.38,1988.34 U13.6@1955.69,1988.34
  L08-BOTTOM w15: J7.5@1838.64,1976.53 1878.2,1976.53 1884.19,1970.55 v4(1888.25,1970.55) ; v4@1889.87,1972.17 1905.19,1956.85 J7.6@1931.95,1956.85
W5: J8.5 J8.6 U14.6 | length 177.2
  L01-TOP w15: v4(1861.22,1354.83) 1862.61,1356.23 1882.86,1356.23 1895.37,1368.74 U14.6@1923.96,1368.74 ; U14.6@1923.99,1368.76 U14.6@1931.83,1368.76
  L08-BOTTOM w10: J8.5@1811.42,1360.63 J8.5@1811.61,1360.82
  L08-BOTTOM w15: J8.5@1811.61,1360.82 1851.18,1360.82 1857.16,1354.83 v4(1861.22,1354.83) ; v4@1862.84,1356.45 1878.16,1341.13 J8.6@1904.92,1341.13
W6: J9.5 J9.6 U15.6 | length 174.8
  L01-TOP w15: v4(2391.64,1680.06) 2393.03,1681.45 2413.28,1681.45 2428.75,1696.92 U15.6@2458.91,1696.92
  L08-BOTTOM w15: J9.5@2342.03,1686.04 2381.6,1686.04 2387.58,1680.06 v4(2391.64,1680.06) ; v4@2393.26,1681.68 2408.58,1666.36 J9.6@2435.34,1666.36
XRSn: C42.1 R39.2 R41.1 SW1.1 SW1.3 U4.D12 | length 4071.4
  L01-TOP w3.8: v1@948.52,1305.01 942.08,1298.56 942.08,1275.42 957.52,1259.98 957.52,1206.4 U4.D12@970.32,1193.6
  L01-TOP w5: v1(233.44,1415.35) 372.59,1415.35 407.9,1450.67 407.9,1483.52 C42.1@409.39,1485.01 470.18,1485.01 R41.1@470.74,1484.46 470.74,1456.81 v1(428.46,1414.53)
  L03-SIG w5: v1(233.44,1415.35) 233.44,1033.06 439.67,382.55 467.89,354.33 ; 467.96,354.26 467.96,260.78 509.79,218.95 758.1,218.95 801.62,175.43 921.53,175.43 959.26,137.71 959.26,52.82 978.74,33.33 1497,33.33 1511.41,47.74 1511.41,189.13 1535.54,213.26 1568.94,213.26 v1(1601.35,245.67)
  L08-BOTTOM w4: v1(428.46,1414.53) 458.11,1444.19 720.55,1444.19 858.92,1305.82 v1(950.87,1305.82)
  L08-BOTTOM w5: SW1.1@183.25,1408.15 190.45,1415.35 v1(233.44,1415.35) ; R39.2@1571.31,281.76 1571.31,260.22 1585.98,245.54 v1@1601.23,245.54
  L08-BOTTOM w8: SW1.1@183.25,1408.15 180.82,1403.39 246.61,1200.9 SW1.3@251.38,1198.47
pads on no net: FID1.1 FID2.1 FID3.1 LBL1.0 Q1.0 Q2.0 U1.11 U1.20 U1.21 U1.26 U4.B7 U4.E4 U4.E13 U4.J6 U4.K6 U4.M1 U4.M2 U6.6 U6.9 U7.9@1175.17,303.85 U8.8 U8.28 U8.29 U9.3@606.72,809.63 U9.8@606.72,776.75 U16.5 U16.8
copper on no net:
  other v10: 665.35,118.11 2014.57,118.11 118.11,2291.34 2669.29,2291.34

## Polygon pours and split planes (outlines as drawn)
GND on L01-TOP "L01-TOP_GND_P062" (solid, remove dead copper, pour order 62): 1889.92,1536.64 1890.2,1536.36 1890.2,1496.99 1885.44,1492.23 1789.85,1492.23 1789.85,1494.51 1772.06,1512.3 1711.23,1512.3 1699.9,1523.68 1699.9,1716.95 1701.82,1716.95 1732.39,1747.52 1732.39,2013.15 1661.68,2083.86 1397.01,2083.86 1372.8,2059.65 1372.8,1886.07 1358.91,1872.17 1271.68,1872.17 1259.25,1884.6 1198.2,1884.6 1182.84,1899.96 1182.84,2070.83 1165.83,2087.84 830.16,2087.84 809.68,2067.36 811.68,2065.35 811.68,1884.02 799.79,1872.13 785.78,1872.17 712.95,1872.38 696.26,1889.08 641.47,1889.08 627.88,1902.78 627.88,2001.65 541.44,2088.09 282.56,2088.09 257.66,2063.19 257.66,1889.08 243.37,1876.26 137.79,1876.26 113.81,1900.24 57.11,1900.24 40.12,1883.25 40.12,1618.46 49.94,1605.68 111.63,1355.39 200.12,1098.57 308.66,820.3 332.19,737.33 785.28,737.33 796.17,726.45 796.17,548.49 810.89,533.77 810.89,459.23 797.12,445.46 796.17,445.46 796.17,63.83 833.66,26.34 1909.57,26.34 1931.24,48 1931.24,196.24 1966,231 2114.24,231 2204.84,321.6 2222.62,366.49 2293.95,498.3 2746.34,1556.84 2763,1589 2763,2044.52 2744.83,2062.69 2552.56,2062.69 2531.58,2041.71 2432.82,2041.71 2413.29,2022.18 2413.29,1829.26 2412.9,1829.26 2403.9,1820.27 2313.54,1820.27 2296.65,1837.16 2245.82,1837.16 2222.62,1858.58 2222.62,1951 2267.87,1996.25 2267.87,2201.19 2148.48,2320.57 1954.49,2320.57 1917.07,2283.14 1917.07,2140.1 1917.14,2140.03 1917.14,2123.78 1905.76,2112.39 1814.2,2112.39 1797.74,2128.85 1731.34,2128.85 1726.14,2123.66 1726.14,2100.52 1749.4,2077.27 1824.71,2077.27 1846.7,2055.27 1846.7,1930 1824.45,1907.75 1804.07,1907.75 1797.96,1902.75 1797.96,1850.79 1851.17,1804.32 1851.17,1732.14 1889.92,1692.13
24V on L01-TOP "L01-TOP_24V_P029" (solid, remove dead copper, pour order 29): 1899.76,2133.07 1894.24,2126.41 1816.45,2127.75 1802.07,2140.1 1726.08,2140.1 1715.25,2128.85 1716.14,2086.31 1738.64,2066.36 1782,2066.36 1807.38,2066.36 1827.15,2046.59 1827.15,1936.71 1803,1915.47 1787.76,1900.24 1787.76,1851.86 1838.5,1802.25 1838.5,1720.99 1873.86,1685.63 1873.86,1598.49 1873.79,1598.42 1883.74,1588.47 1883.74,1512.55 1878.46,1507.26 1799.52,1507.26 1779.85,1526.94 1721.85,1526.94 1712.31,1536.03 1712.31,1691.37 1744.29,1723.34 1744.29,2013.35 1661.68,2095.96 1390.83,2095.96 1359.85,2064.98 1359.85,1890.82 1354.83,1885.8 1272.89,1885.8 1262.29,1896.4 1206.36,1896.4 1197.63,1904.77 1197.63,2073.05 1170.22,2100.45 822.29,2100.45 795.4,2073.56 795.4,1894.26 787.72,1886.57 713.39,1886.57 698.38,1901.58 654.49,1901.58 644.46,1911.38 644.46,2000.13 548.55,2100.45 274.34,2100.45 241.25,2067.36 241.25,1897.65 235.38,1891.78 235.13,1892.03 135.71,1892.03 118.69,1909.05 68.27,1909.05 40,1934.81 40,2161.73 68.27,2190 155,2190 220.57,2255.57 220.57,2353.57 247,2380 2510,2380 2569.48,2320.52 2569.48,2107.91 2524.26,2062.69 2431.33,2062.69 2405.21,2036.57 2405.21,1842.27 2399.6,1836.66 2324.24,1836.66 2309.52,1851.39 2251.14,1851.39 2245.06,1857.17 2245.06,1930.13 2284.23,1969.3 2284.23,2202.84 2209.19,2282.42 2158.4,2333.21 1945.52,2333.21 1899.76,2287.45
GND on L01-TOP "L01-TOP_GND_P000" (solid, remove dead copper, pour order 0): 517.87,2369.71 575.67,2369.71 592.19,2353.2 592.19,2210.1 577.29,2195.2 516.9,2195.2 497.19,2214.91 497.19,2360.53 506.37,2369.71
GND on L01-TOP "L01-TOP_GND_P005" (solid, remove dead copper, pour order 5): 1014.14,2232.5 1629.59,2232.5 1638.01,2224.09 1638.01,2154.12 1629.07,2145.18 1009.88,2145.18 998.22,2156.84 998.22,2226.17 1003.85,2232.5
24V on L01-TOP "L01-TOP_24V_P002" (solid, remove dead copper, pour order 2): 2122.38,744.79 2122.38,726.05 2125.86,722.57 2274.86,722.57 2278.41,726.12 2278.41,789.88 2271.86,796.43 2211.91,796.43 2179.19,763.71 2124.95,763.71 2122.35,761.11 2122.35,744.82
5V_SYS on L01-TOP "L01-TOP_5V_SYS_P009" (solid, pour order 9): 2170.52,648.21 2170.52,478.19 2170.52,395.27 2143.42,373.83 1993.83,373.83 1974.75,392.91 1974.75,647.01 1984.83,657.09 2164.32,657.09 2170.52,650.9
1V2 on L01-TOP "L01-TOP_1V2_P031" (solid, pour order 31): 1378.73,681.72 1385.07,687.89 1552.44,687.89 1558.61,681.72 1558.61,661.91 1551.32,654.63 1386.54,654.63 1378.73,662.43 1378.73,672.79
24V on L01-TOP "L01-TOP_24V_P007" (solid, remove dead copper, pour order 7): 1910.61,782.1 1897.11,795.61 1840.27,795.61 1830.87,786.2 1831.18,774.36 1831.18,731.75 1839.44,723.49 2018.36,723.49 2021,726.12 2021,762.09 2017.75,765.33 1968.63,765.33 1951.86,782.1
5V on L01-TOP "L01-TOP_5V_P032" (solid, pour order 32): 1950.35,378.67 1943.67,371.99 1796.98,371.99 1776.27,392.7 1693.47,392.7 1687.08,399.09 1687.08,433.8 1692.53,439.24 1888.05,439.24 1905.19,456.38 1950.35,456.38
GND on L01-TOP "L01-TOP_GND_P001" (solid, remove dead copper, pour order 1): 1112.81,1062.51 1106.7,1056.41 1047.85,1056.41 1042.95,1050.39 1037.25,1050.39 1036.89,1050.39 1032.89,1055.69 1032.89,1062.29 1032.89,1096.41 1029.64,1099.66 1021.52,1107.77 1015.78,1107.92 1013.39,1110.31 1013.52,1110.45 1013.52,1123.5 1016.38,1126.37 1031.7,1126.37 1035.33,1122.74 1035.33,1109.75 1044.57,1100.51 1079.94,1100.51 1083.25,1097.21 1083.25,1087.44 1089.88,1080.81 1105,1080.81 1112.81,1073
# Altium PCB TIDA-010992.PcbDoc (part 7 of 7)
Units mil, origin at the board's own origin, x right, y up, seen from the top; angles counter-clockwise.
Board outline 2810.81 x 2427 mil, 8 copper layers (L01-TOP, L02-GND, L03-SIG, L04-GND, L05-PWR, L06-SIG, L07-GND, L08-BOTTOM), stack 61.9 mil thick; 521 components, 377 nets, 1545 pads, 874 vias.

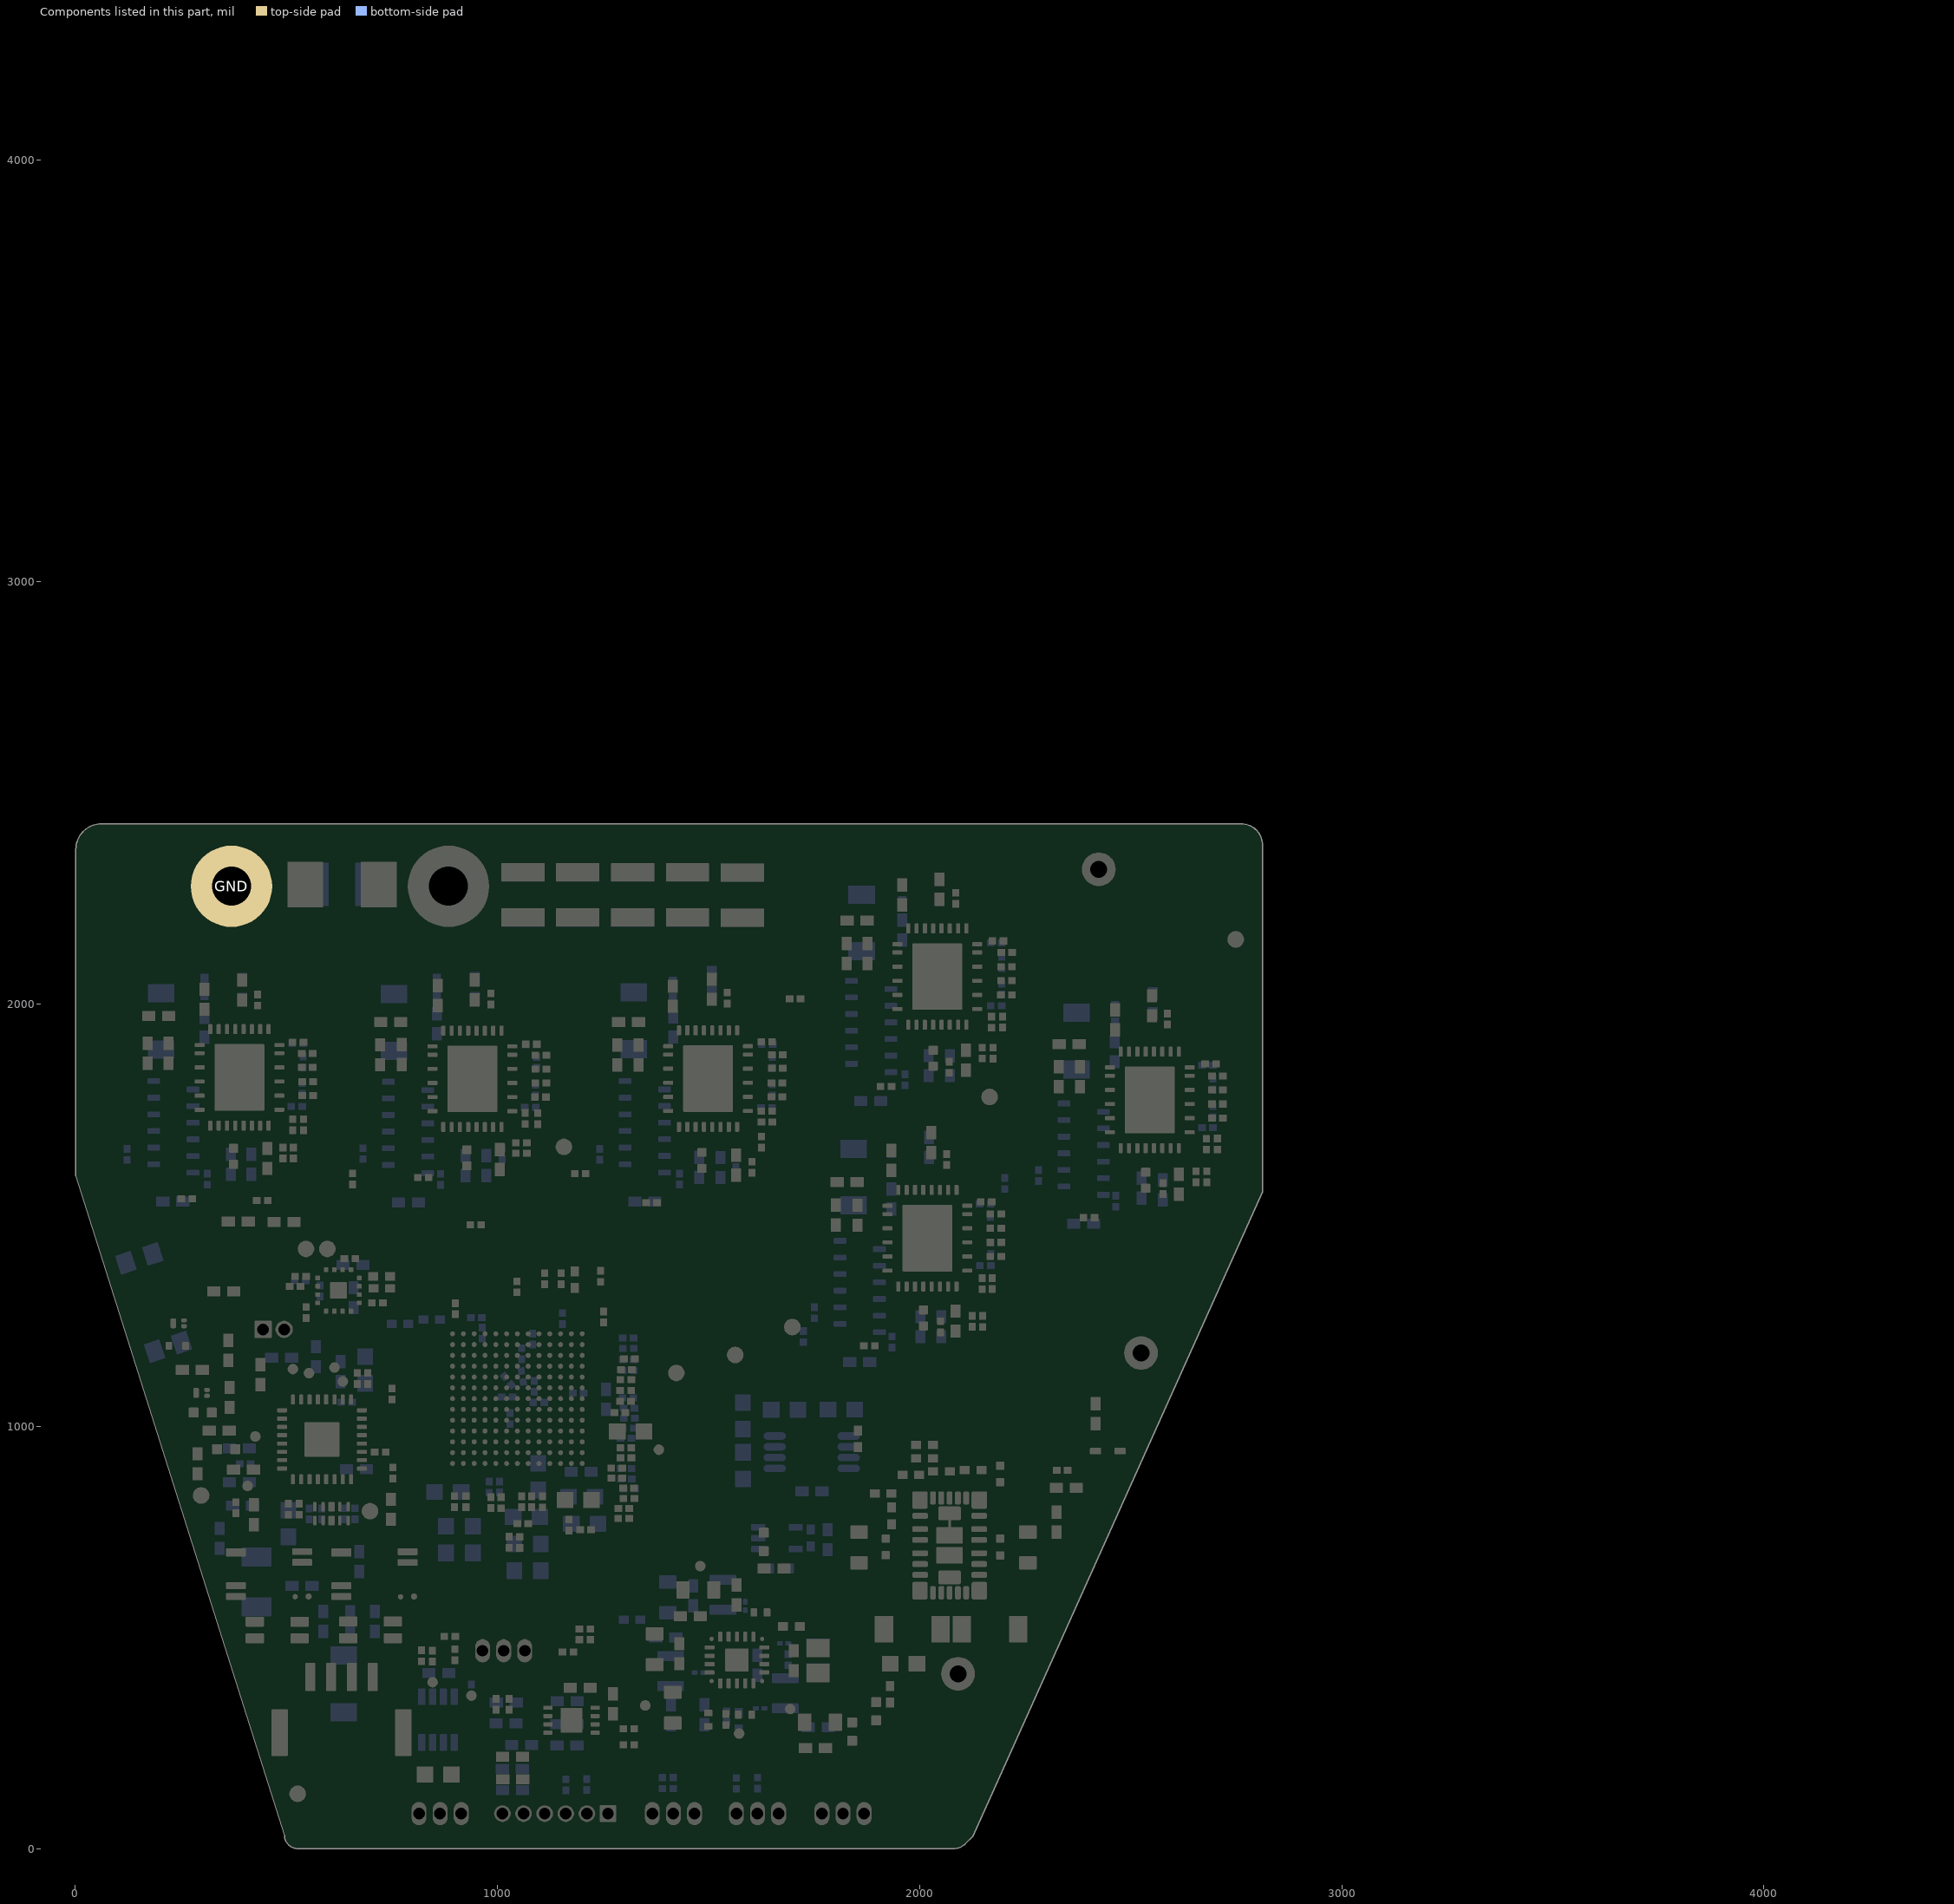
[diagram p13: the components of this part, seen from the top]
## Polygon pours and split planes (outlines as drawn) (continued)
3V3 on L01-TOP "L01-TOP_3V3_P015" (solid, pour order 15): 1635.96,329.08 1635.16,328.3 1626.19,319.46 1626.19,267.64 1629.82,264.01 1742.21,264.01 1745.59,267.38 1745.59,337.13 1738.53,344.2 1719.55,344.34 1664.08,344.34 1654.85,344.25 1652.4,344.25 1649.26,344.2
1V8 on L01-TOP "L01-TOP_1V8_P028" (solid, pour order 28): 1441.9,357.92 1434.83,352.29 1399.18,352.54 1390.18,325.83 1342.81,325.15 1334.7,333.26 1334.7,382.78 1349.09,397.17 1432.11,397.17 1441.9,389.74
GND on L08-BOTTOM "L08-BOTTOM_GND_P067" (solid, remove dead copper, pour order 67): 1291.62,1916.97 1350.05,1916.97 1372.8,1939.38 1372.8,2059.65 1397.01,2083.86 1661.68,2083.86 1732.39,2013.15 1732.39,1747.52 1701.82,1716.95 1699.9,1716.95 1699.9,1571.93 1723.53,1548.18 1875.83,1548.18 1889.92,1562.27 1889.92,1692.13 1851.17,1732.14 1851.17,1804.32 1797.96,1850.79 1797.96,1902.75 1797.96,2028.7 1749.4,2077.27 1726.14,2100.52 1726.14,2123.66 1750.67,2148.19 1891.16,2148.19 1917.07,2174.1 1917.07,2283.14 1954.49,2320.57 2148.48,2320.57 2267.87,2201.19 2267.87,1996.25 2222.62,1951 2222.62,1899.6 2257.5,1867.39 2399.21,1867.39 2413.29,1881.47 2413.29,2022.18 2432.82,2041.71 2531.58,2041.71 2552.56,2062.69 2744.83,2062.69 2763,2044.52 2763,1589 2746.34,1556.84 2293.95,498.3 2222.62,366.49 2204.84,321.6 2114.24,231 1966,231 1931.24,196.24 1931.24,48 1907.69,24.45 835.55,24.45 796.17,63.83 796.17,445.46 797.12,445.46 810.89,459.23 810.89,533.77 796.17,548.49 796.17,726.45 785.28,737.33 332.19,737.33 308.66,820.3 200.12,1098.57 111.63,1355.39 49.94,1605.68 40.12,1618.46 40.12,1883.25 71.43,1914.56 246.91,1914.56 257.66,1925.2 257.66,2063.19 282.56,2088.09 541.44,2088.09 627.88,2001.65 627.88,1937.8 654.24,1911.22 786.7,1911.22 809.68,1933.95 809.68,2067.36 830.16,2087.84 1165.83,2087.84 1182.84,2070.83 1182.84,1949.91 1215.77,1916.97
GND on L08-BOTTOM "L08-BOTTOM_GND_P006" (solid, remove dead copper, pour order 6): 1014.14,2232.5 1629.59,2232.5 1638.01,2224.09 1638.01,2154.12 1629.07,2145.18 1009.88,2145.18 998.22,2156.84 998.22,2226.17 1003.85,2232.5
GND on L08-BOTTOM "L08-BOTTOM_GND_P004" (solid, remove dead copper, pour order 4): 517.87,2369.71 575.67,2369.71 592.19,2353.2 592.19,2210.1 577.29,2195.2 516.9,2195.2 497.19,2214.91 497.19,2360.53 506.37,2369.71
5V_SYS on L08-BOTTOM "L08-BOTTOM_5V_SYS_P063" (solid, remove dead copper, pour order 63): 2164.1,654.63 2173.63,645.1 2173.63,486.83 2166.57,479.78 1980.57,479.78 1974.75,485.61 1974.75,647.01 1982.36,654.63
5V on L08-BOTTOM "L08-BOTTOM_5V_P061" (solid, pour order 61): 1902.15,382.64 1885.73,371.99 1796.98,371.99 1776.27,392.7 1739.17,392.7 1732.06,399.82 1732.06,431.87 1739.43,439.24 1888.05,439.24 1902.15,427.63 1902.15,403.27
24V on L08-BOTTOM "L08-BOTTOM_24V_P035" (solid, remove dead copper, pour order 35): 1787.76,2019.66 1715.69,2087.88 1715.69,2149.34 1738.3,2170.06 1846.7,2170.06 1883.19,2169.6 1899.76,2191.63 1899.76,2222.26 1899.76,2287.45 1945.52,2333.21 2158.4,2333.21 2209.19,2282.42 2284.23,2202.84 2284.23,1969.3 2245.06,1930.13 2245.06,1903.84 2255.66,1893.76 2385.85,1893.76 2405.21,1913.12 2405.21,2036.57 2431.33,2062.69 2524.26,2062.69 2569.48,2107.91 2569.48,2320.52 2510,2380 247,2380 220.57,2353.57 220.57,2255.57 155,2190 68.27,2190 40,2161.73 40,1942.75 53.85,1930.13 231.94,1930.13 241.25,1939.44 241.25,2067.36 274.34,2100.45 548.55,2100.45 644.46,2000.13 644.46,1957.23 659.29,1942.75 787.23,1942.75 795.4,1950.93 795.4,2073.56 822.29,2100.45 1170.22,2100.45 1197.63,2073.05 1197.63,1964.76 1219.14,1944.13 1346.12,1944.13 1359.85,1957.87 1359.85,2064.98 1406.18,2111.31 1622,2111.31 1744.29,1989.02 1744.29,1723.34 1712.31,1691.37 1712.31,1579.62 1724.57,1567.93 1863.21,1567.93 1873.86,1578.59 1873.79,1598.42 1873.86,1598.49 1873.86,1685.63 1838.5,1720.99 1838.5,1802.25 1787.76,1851.86
1V2 on L08-BOTTOM "L08-BOTTOM_1V2_P016" (solid, pour order 16): 1397.33,684.09 1556.24,684.09 1564.52,675.81 1564.52,624.14 1562.71,622.33 1485.27,622.33 1476.02,613.09 1476.02,607.09 1474.02,605.09 1424.02,605.09 1415.02,614.09 1386.9,614.09 1381.94,619.04 1381.94,671.12
3V3 on L08-BOTTOM "L08-BOTTOM_3V3_P034" (solid, remove dead copper, pour order 34): 865.49,653.34 952.46,653.34 961.16,662.04 961.16,718.61 956.9,721.81 862.1,721.81 859.46,719.17 859.46,659.55 865.84,653.16 866.02,653.33
1V2 on L08-BOTTOM "L08-BOTTOM_1V2_P027" (solid, remove dead copper, pour order 27): 1025.29,610.09 1122,610.09 1129.98,618.06 1129.98,674.41 1124.46,678.56 1021.9,678.56 1019.25,675.91 1019.25,616.29 1025.64,609.9 1025.82,610.08
3V3 on L08-BOTTOM "L08-BOTTOM_3V3_P008" (solid, pour order 8): 1664.08,344.34 1738.38,344.34 1752.27,330.45 1752.27,274.07 1742.21,264.01 1629.82,264.01 1626.19,267.64 1626.19,318.8 1644.02,344.25 1652.4,344.25 1654.85,344.25
1V8 on L08-BOTTOM "L08-BOTTOM_1V8_P014" (solid, pour order 14): 1441.9,370.93 1431.17,360.2 1431.17,334.17 1424.44,327.45 1357,327.45 1346.81,337.64 1347.02,337.86 1347.02,395.11 1354.18,402.27 1439.41,402.27 1441.9,400.37
3V3 on L05-PWR "L05-PWR_3V3_P050" (solid, remove dead copper, pour order 50): 796.94,547.72 810.89,533.77 810.89,459.23 810.41,459.23 796.94,445.46 796.94,63.06 823,37 1920.24,37 1931.24,48 1931.24,196.24 1966,231 2114.24,231 2204.84,321.6 2222.62,366.49 2284.12,480.12 2334.58,606.2 2763,1589 2763,2044.52 2744.83,2062.69 2552.56,2062.69 2531.58,2041.71 2432.82,2041.71 2413.29,2022.18 2413.29,1829.26 2428.8,1813.75 2474.54,1813.75 2486.44,1801.84 2486.44,1688.27 2495.93,1678.78 2495.93,1621.39 2482.1,1607.57 2259.48,1607.57 2222.62,1644.43 2222.62,1951 2267.87,1996.25 2267.87,2201.19 2148.48,2320.57 1954.49,2320.57 1917.07,2283.14 1917.07,2140.1 1938.38,2118.79 1970.93,2118.79 1981.54,2108.18 1981.54,1984.15 1999.37,1966.33 1999.37,1915.5 1973.69,1889.83 1847.21,1889.83 1829.28,1907.75 1804.07,1907.75 1797.96,1902.75 1797.96,1850.79 1851.17,1804.32 1851.17,1732.14 1889.92,1692.13 1889.92,1536.64 1957.45,1469.11 1957.45,1369.79 1968.13,1359.11 1968.13,1288.98 1947.23,1268.08 1946.77,1268.54 1711.29,1268.54 1693.64,1286.19 1699.9,1292.46 1699.9,1716.95 1701.82,1716.95 1732.39,1747.52 1732.39,2013.15 1661.68,2083.86 1397.01,2083.86 1372.8,2059.65 1372.8,1886.07 1382.04,1876.83 1421.53,1876.83 1437.78,1860.59 1437.78,1746.57 1449.53,1734.82 1449.53,1670.96 1438.44,1659.87 1204.95,1659.87 1182.84,1681.98 1182.84,2070.83 1165.83,2087.84 830.16,2087.84 809.68,2067.36 811.68,2065.35 811.68,1870.36 816.99,1865.06 868.58,1865.06 877.16,1856.48 877.16,1742.13 891.1,1728.18 891.1,1676.7 876,1661.6 637.84,1661.6 627.88,1671.55 627.88,2001.65 541.44,2088.09 282.56,2088.09 257.66,2063.19 257.66,1885.97 269.88,1873.75 311.32,1873.75 327.49,1857.57 327.49,1754.04 341.23,1740.31 341.23,1678.61 321.44,1658.82 87.72,1658.82 49.94,1621.04 49.94,1605.68 111.63,1355.39 200.12,1098.57 308.66,820.3 352.6,665.41 750.27,665.41 796.94,618.73
24V on L05-PWR "L05-PWR_24V_P020" (solid, remove dead copper, pour order 20): 1873.86,1001.75 1873.79,1001.68 1873.86,971.44 1873.86,818.86 1919,773.72 2173.63,773.72 2196.35,796.43 2274,796.43 2284.23,786.2 2284.23,731.93 2275.78,723.49 1833.28,723.49 1819.16,737.61 1819.16,1107.63 1819.16,1122.59 1819.35,1244.78 1712.31,1351.81 1712.31,1691.37 1744.29,1723.34 1744.29,2018.75 1667.08,2095.96 1390.83,2095.96 1359.85,2064.98 1359.85,1738.18 1345.44,1723.77 1224.26,1723.77 1197.63,1750.4 1197.63,2073.05 1170.22,2100.45 822.29,2100.45 797.06,2075.22 797.06,1735.74 782.7,1721.38 660.45,1721.38 644.46,1737.37 644.46,2000.13 548.55,2100.45 274.34,2100.45 241.61,2067.72 241.61,1733.49 229.15,1721.04 56.33,1721.04 40,1737.37 40,2161.73 68.27,2190 155,2190 220.57,2255.57 220.57,2353.57 247,2380 2510,2380 2569.48,2320.52 2569.48,2107.91 2524.26,2062.69 2431.33,2062.69 2405.21,2036.57 2405.21,1695.51 2386.74,1677.04 2384.52,1679.27 2284.23,1679.27 2245.06,1718.44 2245.06,1930.13 2284.23,1969.3 2284.23,2202.84 2209.19,2282.42 2158.4,2333.21 1945.52,2333.21 1902.23,2289.92 1902.23,1981.15 1836.54,1915.47 1795.01,1915.47 1787.76,1908.22 1787.76,1851.86 1838.5,1802.25 1838.5,1720.99 1873.86,1685.63 1873.86,1598.49 1873.79,1598.42 1873.86,1598.36
VDDA on L05-PWR "L05-PWR_VDDA_P013" (solid, remove dead copper, pour order 13): 1117.86,879 1114.01,882.86 1114.01,988.88 1118.88,993.76 1168.3,993.76 1178.54,1004 1185.4,1010.85 1192.87,1010.85 1195.79,1007.93 1195.66,989.45 1195.66,884.66 1190,879
VDDIO on L05-PWR "L05-PWR_VDDIO_P011" (solid, remove dead copper, pour order 11): 1089.37,1121.72 1092.83,1125.17 1092.83,1137.05 1097.45,1141.67 1121.54,1141.67 1124.75,1138.46 1124.75,1114.08 1120.62,1109.95 1104.66,1109.95 1097.57,1102.57 1097.57,1018.47 1102.57,1013.47 1179.82,1013.47 1187.89,1021.53 1187.89,1221.27 1165.16,1244 949.42,1244 910.38,1244 882.31,1215.93 882.31,924.63 893.93,907.28 1006.61,907.28 1015.15,915.47 1015.15,1134.27 1023,1142.13 1072.42,1142.13 1078.5,1136.04 1078.5,1125.3 1082.09,1121.72
1V2 on L05-PWR "L05-PWR_1V2_P023" (solid, remove dead copper, pour order 23): 1019.25,616.12 1028.29,607.09 1548.55,607.09 1564.52,623.05 1564.52,630.98 1564.52,675.81 1550.5,689.83 1212.63,689.83 1197.63,674.83 1028.68,674.83 1019.25,665.41
VDD on L05-PWR "L05-PWR_VDD_P012" (solid, remove dead copper, pour order 12): 1047.15,879 1039.11,870.95 1039.11,750.79 1030.89,742.58 1001.53,742.58 992.38,751.72 992.38,876.67 1023,908.72 1023,987.1 1020.69,989.41 1004.34,989.41 998.66,995.09 998.66,1007.63 1003.08,1012.05 1019.14,1012.05 1021.12,1014.03 1021.12,1039 1019.4,1040.72 1003.35,1040.72 997.32,1046.75 997.32,1057.83 1002.03,1062.53 1019.83,1062.53 1021.18,1063.88 1021.18,1133.26 1025.95,1138.03 1071.15,1138.03 1087.46,1121.72 1092.83,1121.72 1092.83,1128.63 1102.22,1138.03 1119.91,1138.03 1121.24,1136.7 1121.24,1108.47 1115.34,1102.57 1095.25,1102.57 1095.25,1057.11 1080.58,1042.45 1057.38,1042.45 1047.15,1032.22
GND on L02-GND "L02-GND_GND_P046" (solid, remove dead copper, pour order 46): 44.39,1616.91 40,1630.97 40,2161.73 68.27,2190 155,2190 220.57,2255.57 220.57,2353.57 247,2380 2510,2380 2571.81,2318.19 2571.81,2235.71 2763,2044.52 2763,1589 2734.51,1534.01 2284.12,480.12 2222.62,366.49 2204.84,321.6 2114.24,231 1966,231 1931.24,196.24 1931.24,48 1912.24,29 831,29 796.94,63.06 796.94,445.46 810.89,459.23 810.89,533.77 796.94,547.72 796.94,618.73 750.27,665.41 352.6,665.41 308.66,820.3 200.12,1098.57 111.63,1355.39 49.94,1605.68
EARTH on L02-GND "L02-GND_EARTH_P051" (solid, remove dead copper, pour order 51): 590.45,630.71 751.42,630.29 777.28,604.43 777.28,535.63 795.91,517.01 795.91,473.1 770.98,448.17 770.98,230.36 748.15,207.53 466.31,207.53 466.31,209.42 446.46,229.27 425.06,323.29 403.41,385.11 370.78,522.81 354.36,587.68 354.36,625.68 359.39,630.71
GND on L04-GND "L04-GND_GND_P065" (solid, remove dead copper, pour order 65): 44.39,1616.91 40,1630.97 40,2161.73 68.27,2190 155,2190 220.57,2255.57 220.57,2353.57 247,2380 2510,2380 2571.81,2318.19 2571.81,2235.71 2763,2044.52 2763,1589 2734.51,1534.01 2284.12,480.12 2222.62,366.49 2204.84,321.6 2114.24,231 1966,231 1931.24,196.24 1931.24,48 1906.89,23.65 836.35,23.65 796.94,63.06 796.94,445.46 810.89,459.23 810.89,533.77 796.94,547.72 796.94,618.73 750.27,665.41 352.6,665.41 308.66,820.3 200.12,1098.57 111.63,1355.39 49.94,1605.68
EARTH on L04-GND "L04-GND_EARTH_P052" (solid, remove dead copper, pour order 52): 590.45,630.71 751.42,630.29 777.28,604.43 777.28,535.63 795.91,517.01 795.91,473.1 770.98,448.17 770.98,230.36 748.15,207.53 466.31,207.53 466.31,209.42 446.46,229.27 425.06,323.29 403.41,385.11 370.78,522.81 354.36,587.68 354.36,625.68 359.39,630.71
GND on L07-GND "L07-GND_GND_P066" (solid, remove dead copper, pour order 66): 44.39,1616.91 40,1630.97 40,2161.73 68.27,2190 155,2190 220.57,2255.57 220.57,2353.57 247,2380 2510,2380 2571.81,2318.19 2571.81,2235.71 2763,2044.52 2763,1589 2734.51,1534.01 2284.12,480.12 2222.62,366.49 2204.84,321.6 2114.24,231 1966,231 1931.24,196.24 1931.24,48 1908.95,25.71 834.29,25.71 796.94,63.06 796.94,445.46 810.89,459.23 810.89,533.77 796.94,547.72 796.94,618.73 750.27,665.41 352.6,665.41 308.66,820.3 200.12,1098.57 111.63,1355.39 49.94,1605.68
EARTH on L07-GND "L07-GND_EARTH_P053" (solid, remove dead copper, pour order 53): 590.45,630.71 751.42,630.29 777.28,604.43 777.28,535.63 795.91,517.01 795.91,473.1 770.98,448.17 770.98,230.36 748.15,207.53 466.31,207.53 466.31,209.42 446.46,229.27 425.06,323.29 403.41,385.11 370.78,522.81 354.36,587.68 354.36,625.68 359.39,630.71

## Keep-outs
Keep-Out Layer:
  text ".Layer_Name" at 577,-858.49 h60

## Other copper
L01-TOP:
  text ".Layer_Name" at 577,-858.49 h60
L08-BOTTOM:
  text ".Layer_Name" at 577,-858.49 h60

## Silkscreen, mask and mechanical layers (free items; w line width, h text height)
Top Overlay:
  lines w6: 382,1369.13 463.18,1347.98 483.62,1347.98 ; 473.94,1340.38 483.62,1347.98 ; 475.32,1356.47 483.62,1347.98
  text "'.PRJ_Number'.PCB_Rev" at 1351.59,1231.39 h50
  text ".Layer_Name" at 577,-858.49 h60
Bottom Overlay:
  text ".Layer_Name" at 577,-858.49 h60
Top Paste:
  text ".Layer_Name" at 577,-858.49 h60
Bottom Paste:
  text ".Layer_Name" at 577,-858.49 h60
Top Solder:
  text ".Layer_Name" at 577,-858.49 h60
  text ".Layer_Name" at 577,-858.49 h60
Bottom Solder:
  text ".Layer_Name" at 577,-858.49 h60
Drill Guide:
  text ".Layer_Name" at 577,-858.49 h60
M1 Board Outline:
  lines w10: 1.19,1592.72 495.35,31.41 ccw(c526.76,31.41) 526.76,0 529,0 2034.41,0 2049.34,0 2081,0 ccw(c2081,38.63) 2108.31,11.31 2126,29 2811.97,1555 2812,2377 ccw(c2762,2377) 2762,2427 2739,2427 61.71,2427 ccw(c61.71,2366.47) 1.19,2366.47 1.19,1592.72
  text ".Layer_Name" at 577,-858.49 h60
M2 Board Dimensions:
  rectangle: 39,-500 164,-375
  rectangle: 164,-625 539,-500
  lines w7: 39,-500 1039,-500 ; 164,-625 164,-375 ; 289,-625 289,-375 ; 539,-625 539,-375 ; 789,-625 789,-375 ; 39,-625 1039,-625 1039,-375 39,-375 39,-625
  text ".Layer_Name" at -42,-469 h60
M3 3D STEP Top:
  text ".Layer_Name" at 577,-858.49 h60
M4 3D STEP Bottom:
  text ".Layer_Name" at 577,-858.49 h60
M5 Assembly Top:
  lines w10: -292,-930.17 6308,-930.17 ; -292,-726.83 6310,-726.83 ; -292,-523.5 -292,-1133.5 3713,-1133.5 6310,-1133.5 6310,-523.5 -291.5,-523.5 -291.5,-1133.5 1284,-1133.5 ; 2173,-1133.5 2173,-523.5 ; 3440,-726.83 3440,-523.5 ; 4280,-726.83 4280,-523.5 ; 4902,-1140 4902,-937.17
  text "COMPONENTS MARKED 'DNP' SHOULD NOT BE POPULATED." at 1153.5,-318.5 h25
  text "ASSEMBLY VARIANT:" at 1153,-434 h25
  text ".VariantName" at 2189,-434 h25
  text "PCB VIEWED FROM TOP SIDE" at -228.5,-655.67 h60
  text "BOARD #:" at 2248,-655.67 h60
  text ".PRJ_Number" at 2793.5,-655.67 h60
  text "REV:" at 3638,-655.67 h60
  text ".PCB_Rev" at 3929.5,-655.67 h60
  text "SVN REV:" at 4476,-655.67 h60
  text ".VersionControl_RevNumber" at 4982,-655.67 h60
  text "TID #:" at 2248,-859 h60
  text ".TID" at 2793.5,-859 h60
  text "PLOT NAME =" at -228.5,-1064.34 h60
  text ".plot_File_Name" at 577,-1064.34 h60
  text "GENERATED    :" at 2250,-1064.34 h60
  text ".Print_Date" at 3119.5,-1064.34 h60
  text ".Print_Time" at 3848.5,-1064.34 h60
  text "TEXAS INSTRUMENTS" at 5113,-1064.34 h60
M6 Assembly Bottom:
  lines w10: -292.5,-727.33 6309.5,-727.33 ; -290.5,-930.67 6309.5,-930.67 ; 1115.5,-1140.5 1115.5,-937.67 ; 1737.5,-727.33 1737.5,-524 ; 2577.5,-727.33 2577.5,-524 ; 3844.5,-1134 3844.5,-524 ; 4733.5,-1134 6309,-1134 6309,-524 -292.5,-524 -292.5,-1134 2304.5,-1134 6309.5,-1134 6309.5,-524
  text "COMPONENTS MARKED 'DNP' SHOULD NOT BE POPULATED." at 6102,-318 h25
  text ".VariantName" at 5058,-434 h25
  text "ASSEMBLY VARIANT:" at 6097,-434 h25
  text ".VersionControl_RevNumber" at 1035.5,-656.17 h60
  text "SVN REV:" at 1541.5,-656.17 h60
  text ".PCB_Rev" at 2088,-656.17 h60
  text "REV:" at 2379.5,-656.17 h60
  text ".PRJ_Number" at 3224,-656.17 h60
  text "BOARD #:" at 3769.5,-656.17 h60
  text "PCB VIEWED FROM BOTTOM SIDE" at 6246,-656.17 h60
  text ".TID" at 3224,-859.5 h60
  text "TID #:" at 3769.5,-859.5 h60
  text "TEXAS INSTRUMENTS" at 904.5,-1064.84 h60
  text ".Print_Time" at 2169,-1064.84 h60
  text ".Print_Date" at 2898,-1064.84 h60
  text "GENERATED    :" at 3767.5,-1064.84 h60
  text ".plot_File_Name" at 5440.5,-1064.84 h60
  text "PLOT NAME =" at 6246,-1064.84 h60
M9 Title Sheet:
  drawing of 57 lines, arcs and shapes, not listed
  text "1" at 739.84,8036.5 h70
  text "2" at 3235.5,8036.5 h70
  text "3" at 5724.84,8036.5 h70
  text "4" at 8231.51,8036.5 h70
  text "5" at 10730.5,8036.5 h70
  text "6" at 13235.5,8036.5 h70
  text "A" at -416.5,6893.5 h70
  text "A" at 14383.5,6893.5 h70
  text "B" at -416.5,4513.5 h70
  text "B" at 14383.5,4513.5 h70
  text "C" at -416.5,2138.5 h70
  text "C" at 14383.5,2138.5 h70
  text "PROJECT TITLE:" at 11343.5,277.5 h45
  text ".PRJ_Title" at 11393.5,144.17 h70
  text "DESIGNED FOR:" at 11343.5,-23.5 h45
  text ".PRJ_Customer" at 11393.5,-163.5 h70
  text "D" at -416.5,-231.5 h70
  text "D" at 14383.5,-231.5 h70
  text "FILE NAME:" at 11343.5,-323.5 h45
  text ".PCB_File_Name_No_Path" at 11393.5,-443.5 h70
  text "Texas Instruments (TI) and/or its licensors do not warrant the accuracy or completeness of this specification" at 6374,-605.34 h45
  text "ENGINEER:" at 11343.5,-613.5 h45
  text "LAYOUT BY:" at 12848.5,-613.5 h45
  text "or any information contained therein. TI and/or its licensors do not warrant that this design will meet" at 6329.01,-718 h45
  text ".PRJ_Engineer" at 11393.5,-768.49 h70
  text ".PCB_Layout" at 12899,-768.49 h70
  text "the specifications, will be suitable for your application or fit for any particular purpose, or will operate in" at 6329.01,-830.67 h45
  text ".Layer_Name" at 577,-858.49 h60
  text "ALTIUM DESIGNER VERSION:" at 12848.5,-923.5 h45
  text "an implementation. TI and/or its licensors do not warrant that the design is production worthy. You should" at 6329.01,-943.33 h45
  text "completely validate and test your design implementation to confirm the system functionality for your application." at 6374,-1056 h45
  text ".print_Scale" at 11393.5,-1056.83 h70
  text ".Application_BuildNumber" at 12899,-1056.83 h70
  text "1" at 739.84,-1263.5 h70
  text "2" at 3235.5,-1263.5 h70
  text "3" at 5724.84,-1263.5 h70
  text "4" at 8231.51,-1263.5 h70
  text "5" at 10730.5,-1263.5 h70
  text "6" at 13235.5,-1263.5 h70
M10 Fab Notes:
  drawing of 189 lines, arcs and shapes, not listed
  text "DESIGN INFORMATION" at 12382.02,6356.17 h60
  text "MIN. TRACK WIDTH:" at 11737.46,6224.05 h60
  text "8" at 12833.7,6224.05 h60
  text "MIL" at 12988.46,6224.05 h60
  text "7.874" at 12667.32,6102.36 h60
  text "MIN. CLEARANCE:" at 11737.46,6099.92 h60
  text "MIL" at 12988.46,6099.92 h60
  text "MIN. VIA PAD SIZE:" at 11737.46,5975.8 h60
  text "24" at 12803.71,5975.8 h60
  text "MIL" at 12988.46,5975.8 h60
  text "0.05mm (2MIL)" at 12432.46,5845.9 h60
  text "MINIMUM ANNULAR RING" at 11408.23,5837.67 h60
  text "EXTERNAL" at 13140.46,5837.67 h60
  text "PER" at 11608.23,5727.55 h60
  text "IPC-D-275 CLASS 2 LEVEL C" at 11828.23,5727.54 h60
  text "MIL, HOLES" at 13316.46,5627.07 h60
  text "+/-" at 12924,5618.48 h60
  text "+/-" at 13778,5618.48 h60
  text "REGISTRATION TOLERANCES:" at 11408.23,5617.42 h60
  text "METAL" at 12608,5617.42 h60
  text "5" at 13184.2,5617.42 h60
  text "3" at 14017.2,5617.42 h60
  text "MIL" at 14133.46,5617.42 h60
  text "HOLE SIZE TOLERANCE (UNLESS OTHERWISE SPECIFIED):" at 11408.23,5519.1 h60
  text "+/-" at 13778,5516.23 h60
  text "3" at 14017.2,5515.17 h60
  text "MIL" at 14133.46,5515.17 h60
  text "MATERIAL:" at 11333.46,5377.52 h60
  text "FR-4 High Tg" at 12319.9,5249 h60
  text "X" at 12175.46,5241.01 h60
  text "FR-4" at 11754.46,5236.49 h60
  text "OTHER" at 13242.46,5236.49 h60
  text "62 MIL (1.6mm) +/-10%" at 12074.56,5093.46 h60
  text "X" at 11954.46,5091.01 h60
  text "THICKNESS:" at 11408.23,5085.24 h60
  text "OTHER" at 13359.46,5085.24 h60
  text "TOLERANCE:" at 11408.23,4946.92 h60
  text "X" at 12256.46,4946.92 h60
  text "ANSI IPC-6012 TYPE 3 CLASS 2" at 12434.48,4946.92 h60
  text "OTHER +/-" at 12434.46,4802.73 h60
  text "BOW & TWIST:" at 11408.23,4657.54 h60
  text "X" at 12256.46,4657.54 h60
  text "ANSI IPC-6012 TYPE 3 CLASS 2" at 12434.48,4657.54 h60
  text "OTHER +/-" at 12434.46,4510.85 h60
  text "DRILLING:" at 11333.46,4380.23 h60
  text "NC_DRILL FILES" at 13094.46,4275.04 h60
  text "REFERENCE:" at 11408.23,4271.1 h60
  text "X" at 12065.46,4271.01 h60
  text "AS SHOWN" at 12243.46,4271.1 h60
  text "X" at 12966.46,4271.1 h60
  text "OTHER" at 13392.46,4128.85 h60
  text "PTH COPPER THICKNESS:" at 11407.91,4125.32 h60
  text "X" at 12547.14,4125.32 h60
  text "20-30 um" at 12675.14,4125.32 h60
  text "BOARD FINISH:" at 11333.46,3977.73 h60
  text "SILKSCREEN:" at 11488.68,3867.6 h60
  text "X" at 12446.46,3867.6 h60
  text "TOP" at 12563.46,3867.6 h60
  text "X" at 12956.46,3867.6 h60
  text "BOTTOM" at 13074.46,3867.6 h60
  text "SILKSCREEN COLOR:" at 11488.68,3712.41 h60
  text "X" at 12445.46,3712.41 h60
  text "WHITE" at 12563.46,3712.41 h60
  text "OTHER" at 13074.46,3712.41 h60
  text "X" at 12576.46,3568.96 h60
  text "GREEN" at 12694.46,3568.96 h60
  text "OTHER" at 13312.46,3568.96 h60
  text "SOLDER RESIST COLOR:" at 11488.68,3562.1 h60
  text "X" at 12576.46,3414.71 h60
  text "MATTE" at 12694.46,3414.71 h60
  text "SEMI-GLOSS" at 13312,3414.07 h60
  text "IMMERSION GOLD (ENIG)" at 12394.46,3241.94 h60
  text "ENEPIG" at 13732,3234.72 h60
  text "SURFACE FINISH:" at 11333.46,3233.72 h60
  text "X" at 12216.46,3233.72 h60
  text "IMM. TIN/SILVER OR EQUIV" at 11663,3096.4 h60
  text "OTHER" at 13094.46,3092.47 h60
  text "ARRAY/PANEL:" at 11333.46,2937.09 h60
  text "CUT AND TRIM PER M1 BOARD OUTLINE" at 12394.46,2928.87 h60
  text "N.C. ROUTE" at 12394.46,2792.9 h60
  text "X" at 13082.46,2792.9 h60
  text "V. SCORE" at 13260.46,2792.9 h60
  text "CERTIFICATION:" at 11333.46,2663.77 h60
  text "MATERIALS AND WORKMANSHIP FOR ALL PCBS" at 12058.46,2663.77 h60
  text "TO MEET OR EXCEED THE REQUIREMENTS OF:" at 12058.46,2569.71 h60
  text "X" at 11695.97,2441.08 h60
  text "ANSI IPC-A-600F CLASS ->" at 11823.96,2441.08 h60
  text "X" at 13471.97,2441.08 h60
  text "2" at 13581.96,2441.08 h60
  text "1" at 13266.96,2439.58 h60
  text "3" at 13935.96,2439.58 h60
  text "X" at 12507.97,2293.39 h60
  text "RoHS" at 12635.96,2293.39 h60
  text "OTHER" at 13280.36,2293.39 h60
  text "PER ORDER" at 13677.42,2293.39 h60
  text "ALL BOARDS MUST MEET OR EXCEED UL94-V0 REQUIREMENTS." at 11361,2139.57 h60
  text "PCB MUST BEAR THE UL94V-0 UL REGISTERED MATERIAL ID NUMBER" at 11361,2023.5 h60
  text "ADDITIONAL REQUIREMENTS:" at 11333.46,1854.08 h60
  text "MICROSECTION:" at 11408.23,1746.95 h60
  text "YES" at 12313.96,1746.95 h60
  text "REQUIRED" at 13175.46,1602.62 h60
  text "BARE BOARD ELEC. TEST:" at 11408.23,1599.76 h60
  text "NONE" at 12713.96,1599.76 h60
  text "X" at 13057.46,1599.76 h60
  text "PER ORDER" at 13767.46,1599.76 h60
  text "XX MIL VIAS REQUIRE NON-CONDUCTIVE FILL AND PLANARIZE" at 11576.38,1394.82 h59
  text "XX MIL VIAS REQUIRE CONDUCTIVE FILL AND PLANARIZE" at 11584.38,1290.84 h60
  text "OUTER XX MIL TRACES REQUIRE 50 OHM SINGLE-ENDED IMPEDANCE" at 11583.39,1127.46 h58
  text "LAYER 2 & 3 (INNER LAYERS) XX MIL WIDE, XX MIL SPACE / TRACES REQUIRE 100 OHM DIFFERENTIAL IMPEDANCE" at 11575.39,891.74 h60
  text ".Layer_Name" at 577,-858.49 h60
M11 Gerber Information:
  lines w10: -292,-930.17 6308,-930.17 ; -292,-726.83 6310,-726.83 ; -292,-523.5 -292,-1133.5 3713,-1133.5 6310,-1133.5 6310,-523.5 -291.5,-523.5 -291.5,-1133.5 1284,-1133.5 ; 2173,-1133.5 2173,-523.5 ; 3440,-726.83 3440,-523.5 ; 4280,-726.83 4280,-523.5 ; 4902,-1140 4902,-937.17
  text "ALL ARTWORK VIEWED FROM TOP SIDE" at -210,-172 h60
  text "BOARD #:" at 2248,-655.67 h60
  text ".PRJ_Number" at 2793.5,-655.67 h60
  text "REV:" at 3638,-655.67 h60
  text ".PCB_Rev" at 3929.5,-655.67 h60
  text "SVN REV:" at 4476,-655.67 h60
  text ".VersionControl_RevNumber" at 4982,-655.67 h60
  text "LAYER NAME =" at -228.5,-858.49 h60
  text "TID #:" at 2248,-859 h60
  text ".TID" at 2793.5,-859 h60
  text "PLOT NAME =" at -228.5,-1064.34 h60
  text ".plot_File_Name" at 577,-1064.34 h60
  text "GENERATED    :" at 2250,-1064.34 h60
  text ".Print_Date" at 3119.5,-1064.34 h60
  text ".Print_Time" at 3848.5,-1064.34 h60
  text "TEXAS INSTRUMENTS" at 5113,-1064.34 h60
M12 Stackup:
  drawing of 503 lines, arcs and shapes, not listed
  text "Layer" at 9796.59,7912.44 h35
  text "Name" at 10044.04,7912.44 h35
  text "Material" at 10594.73,7912.44 h35
  text "Thickness" at 11104.59,7912.44 h35
  text "Constant" at 11492,7912.44 h35
  text "Board Layer Stack" at 11832.75,7912.44 h35
  text "Top Overlay" at 10044.04,7842.44 h35
  text "Top Solder" at 10044.04,7772.44 h35
  text "Solder Resist" at 10594.73,7772.44 h35
  text "0.40mil" at 11104.59,7772.44 h35
  text "3.5" at 11492,7772.44 h35
  text "1" at 9796.59,7702.44 h35
  text "L01-TOP" at 10044.04,7702.44 h35
  text "CF-004" at 10594.73,7702.44 h35
  text "1.40mil" at 11104.59,7702.44 h35
  text "Dielectric 1" at 10044.04,7632.44 h35
  text "FR-4 370" at 10594.73,7632.44 h35
  text "3.30mil" at 11104.59,7632.44 h35
  text "4.2" at 11492,7632.44 h35
  text "2" at 9796.59,7562.44 h35
  text "L02-GND" at 10044.04,7562.44 h35
  text "CF-004" at 10594.73,7562.44 h35
  text "1.40mil" at 11104.59,7562.44 h35
  text "Dielectric 2" at 10044.04,7492.44 h35
  text "FR-4 370" at 10594.73,7492.44 h35
  text "5.00mil" at 11104.59,7492.44 h35
  text "4.3" at 11492,7492.44 h35
  text "3" at 9796.59,7422.44 h35
  text "L03-SIG" at 10044.04,7422.44 h35
  text "CF-004" at 10594.73,7422.44 h35
  text "1.40mil" at 11104.59,7422.44 h35
  text "Dielectric 3" at 10044.04,7352.44 h35
  text "FR-4 370" at 10594.73,7352.44 h35
  text "9.80mil" at 11104.59,7352.44 h35
  text "4.1" at 11492,7352.44 h35
  text "4" at 9796.59,7282.44 h35
  text "L04-GND" at 10044.04,7282.44 h35
  text "CF-004" at 10594.73,7282.44 h35
  text "1.40mil" at 11104.59,7282.44 h35
  text "Dielectric 4" at 10044.04,7212.44 h35
  text "FR-4 370" at 10594.73,7212.44 h35
  text "14.50mil" at 11104.59,7212.44 h35
  text "4.2" at 11492,7212.44 h35
  text "5" at 9796.59,7142.44 h35
  text "L05-PWR" at 10044.04,7142.44 h35
  text "CF-004" at 10594.73,7142.44 h35
  text "1.40mil" at 11104.59,7142.44 h35
  text "Dielectric 5" at 10044.04,7072.44 h35
  text "FR-4 370" at 10594.73,7072.44 h35
  text "9.80mil" at 11104.59,7072.44 h35
  text "4.1" at 11492,7072.44 h35
  text "6" at 9796.59,7002.44 h35
  text "L06-SIG" at 10044.04,7002.44 h35
  text "CF-004" at 10594.73,7002.44 h35
  text "1.40mil" at 11104.59,7002.44 h35
  text "Dielectric 6" at 10044.04,6932.44 h35
  text "FR-4 370" at 10594.73,6932.44 h35
  text "5.00mil" at 11104.59,6932.44 h35
  text "4.3" at 11492,6932.44 h35
  text "7" at 9796.59,6862.44 h35
  text "L07-GND" at 10044.04,6862.44 h35
  text "CF-004" at 10594.73,6862.44 h35
  text "1.40mil" at 11104.59,6862.44 h35
  text "Dielectric 7" at 10044.04,6792.44 h35
  text "FR-4 370" at 10594.73,6792.44 h35
  text "3.30mil" at 11104.59,6792.44 h35
  text "4.2" at 11492,6792.44 h35
  text "8" at 9796.59,6722.44 h35
  text "L08-BOTTOM" at 10044.04,6722.44 h35
  text "CF-004" at 10594.73,6722.44 h35
  text "1.40mil" at 11104.59,6722.44 h35
  text "Bottom Solder" at 10044.04,6652.44 h35
  text "Solder Resist" at 10594.73,6652.44 h35
  text "0.40mil" at 11104.59,6652.44 h35
  text "3.5" at 11492,6652.44 h35
  text "Bottom Overlay" at 10044.04,6582.44 h35
  text ".Layer_Name" at 577,-858.49 h60
M13 Component Bodies Top:
  text ".Layer_Name" at 577,-858.49 h60
M14 Component Bodies Bottom:
  text ".Layer_Name" at 577,-858.49 h60
M15 Courtyards Top:
  text ".Layer_Name" at 577,-858.49 h60
M16 Courtyards Bottom:
  text ".Layer_Name" at 577,-858.49 h60
Drill Drawing:
  circle w10: c5332.67,2931.29 r9.68
  circle w10: c5332.67,2931.29 r16.13
  circle w10: c5332.67,2786.14 r16.13
  lines w10: 5316.54,2850.65 5324.61,2850.65 5332.67,2842.59 5340.73,2850.65 5348.8,2850.65 5340.73,2858.72 5348.8,2866.78 5340.73,2866.78 5332.67,2874.84 5324.61,2866.78 5316.54,2866.78 5324.61,2858.72 5316.54,2850.65 ; 5316.54,3020 5348.8,3020 5332.67,2987.74 5316.54,3020 ; 5316.54,3060.32 5348.8,3060.32 5348.8,3092.57 5316.54,3092.57 5316.54,3060.32 ; 5316.54,3132.89 5316.54,3140.96 5324.61,3149.02 5316.54,3157.08 5316.54,3165.15 5324.61,3165.15 5332.67,3157.08 5340.73,3165.15 5348.8,3165.15 5348.8,3157.08 5340.73,3149.02 5348.8,3140.96 5348.8,3132.89 5340.73,3132.89 5332.67,3140.96 5324.61,3132.89 5316.54,3132.89 ; 5316.54,3205.47 5332.67,3213.53 5348.8,3205.47 5340.73,3221.6 5348.8,3237.72 5332.67,3229.66 5316.54,3237.72 5324.61,3221.6 5316.54,3205.47 ; 5316.54,3294.17 5332.67,3278.04 5348.8,3294.17 5332.67,3310.3 5316.54,3294.17 ; 5316.54,3358.68 5324.61,3358.68 5324.61,3350.62 5340.73,3350.62 5340.73,3358.68 5348.8,3358.68 5348.8,3374.81 5340.73,3374.81 5340.73,3382.88 5324.61,3382.88 5324.61,3374.81 5316.54,3374.81 5316.54,3358.68
  lines w12: 5286,2748.24 7143.02,2748.24 ; 5286,3401.42 7143.02,3401.42 ; 5482.97,2675.66 5482.97,3474 ; 5676.47,2675.66 5676.47,3474 ; 6047.41,2675.66 6047.41,3474 ; 6198.47,2675.66 6198.47,3474 ; 6417.12,2675.66 6417.12,3474 ; 6812.89,2675.66 6812.89,3474 ; 5286,2675.66 7143.02,2675.66 7143.02,3474 5286,3474 5286,2675.66
  text "Symbol" at 5329.55,3423.2 h42
  text "Quantity" at 5504.74,3423.2 h42
  text "Finished Hole Size" at 5698.25,3423.2 h42
  text "Plated" at 6069.19,3423.2 h42
  text "Hole Type" at 6220.25,3423.2 h42
  text "Drill Layer Pair" at 6438.9,3423.2 h42
  text "Hole Tolerance" at 6834.66,3423.2 h42
  text "835" at 5504.74,3350.62 h35
  text "8.00mil (0.203mm)" at 5698.25,3350.62 h35
  text "PTH" at 6069.19,3350.62 h35
  text "Round" at 6220.25,3350.62 h35
  text "L01-TOP - L08-BOTTOM" at 6438.9,3350.62 h35
  text "5" at 5504.74,3278.04 h35
  text "8.00mil (0.203mm)" at 5698.25,3278.04 h35
  text "PTH" at 6069.19,3278.04 h35
  text "Round" at 6220.25,3278.04 h35
  text "L01-TOP - L08-BOTTOM" at 6438.9,3278.04 h35
  text "+/-3.00mil" at 6834.66,3278.04 h35
  text "18" at 5504.74,3205.47 h35
  text "18.00mil (0.457mm)" at 5698.25,3205.47 h35
  text "PTH" at 6069.19,3205.47 h35
  text "Round" at 6220.25,3205.47 h35
  text "L01-TOP - L08-BOTTOM" at 6438.9,3205.47 h35
  text "12" at 5504.74,3132.89 h35
  text "19.69mil (0.500mm)" at 5698.25,3132.89 h35
  text "PTH" at 6069.19,3132.89 h35
  text "Round" at 6220.25,3132.89 h35
  text "L01-TOP - L08-BOTTOM" at 6438.9,3132.89 h35
  text "21" at 5504.74,3060.32 h35
  text "27.56mil (0.700mm)" at 5698.25,3060.32 h35
  text "PTH" at 6069.19,3060.32 h35
  text "Round" at 6220.25,3060.32 h35
  text "L01-TOP - L08-BOTTOM" at 6438.9,3060.32 h35
  text "2" at 5504.74,2987.74 h35
  text "28.00mil (0.711mm)" at 5698.25,2987.74 h35
  text "PTH" at 6069.19,2987.74 h35
  text "Round" at 6220.25,2987.74 h35
  text "L01-TOP - L08-BOTTOM" at 6438.9,2987.74 h35
  text "3" at 5504.74,2915.16 h35
  text "40.00mil (1.016mm)" at 5698.25,2915.16 h35
  text "PTH" at 6069.19,2915.16 h35
  text "Round" at 6220.25,2915.16 h35
  text "L01-TOP - L08-BOTTOM" at 6438.9,2915.16 h35
  text "2" at 5504.74,2842.59 h35
  text "92.52mil (2.350mm)" at 5698.25,2842.59 h35
  text "PTH" at 6069.19,2842.59 h35
  text "Round" at 6220.25,2842.59 h35
  text "L01-TOP - L08-BOTTOM" at 6438.9,2842.59 h35
  text "4" at 5504.74,2770.01 h35
  text "98.43mil (2.500mm)" at 5698.25,2770.01 h35
  text "PTH" at 6069.19,2770.01 h35
  text "Round" at 6220.25,2770.01 h35
  text "L01-TOP - L08-BOTTOM" at 6438.9,2770.01 h35
  text "902 Total" at 5504.74,2697.44 h35
  text ".Layer_Name" at 577,-858.49 h60
M17 Embedded Cavity:
  text ".Layer_Name" at 577,-858.49 h60
M18 Embedded Assembly:
  text ".Layer_Name" at 577,-858.49 h60
M19 Embedded Keepout:
  text ".Layer_Name" at -39,-351 h60

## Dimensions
665.35,118.11 to 118.11,2291.34 on M2 Board Dimensions
526.76,0 to 1.19,2366.47 on M2 Board Dimensions
2081,0 to 2812,2377 on M2 Board Dimensions
2762,2427 to 2081,0 on M2 Board Dimensions
526.76,-10 to 2081,0 on M2 Board Dimensions
1.19,2366.47 to 2812,2377 on M2 Board Dimensions
529,0 to 61.71,2427 on M2 Board Dimensions
2669.29,2291.34 to 665.35,118.11 on M2 Board Dimensions
2669.29,2291.34 to 2014.57,118.11 on M2 Board Dimensions
2669.29,2291.34 to 118.11,2291.34 on M2 Board Dimensions
665.35,118.11 to 118.11,2291.34 on M2 Board Dimensions
39,-625 to 1039,-625 on M2 Board Dimensions
665.35,118.11 to 2014.57,118.11 on M2 Board Dimensions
